              <bitWidth>2</bitWidth>
            </field>
            <field>
              <name>MONO</name>
              <bitOffset>12</bitOffset>
              <bitWidth>1</bitWidth>
            </field>
            <field>
              <name>OUTDRIV</name>
              <bitOffset>13</bitOffset>
              <bitWidth>1</bitWidth>
            </field>
            <field>
              <name>SAIEN</name>
              <bitOffset>16</bitOffset>
              <bitWidth>1</bitWidth>
            </field>
            <field>
              <name>DMAEN</name>
              <bitOffset>17</bitOffset>
              <bitWidth>1</bitWidth>
            </field>
            <field>
              <name>NODIV</name>
              <bitOffset>19</bitOffset>
              <bitWidth>1</bitWidth>
            </field>
            <field>
              <name>MCKDIV</name>
              <bitOffset>20</bitOffset>
              <bitWidth>4</bitWidth>
            </field>
          </fields>
        </register>
        <register>
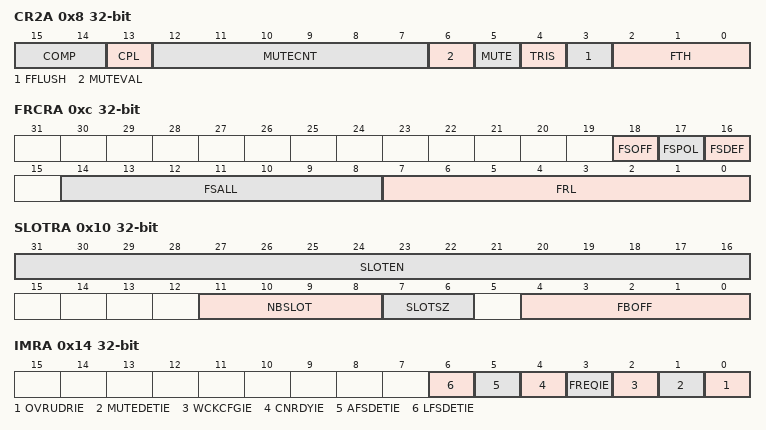
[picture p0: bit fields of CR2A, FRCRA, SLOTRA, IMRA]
          <name>CR2A</name>
          <addressOffset>0x8</addressOffset>
          <size>0x20</size>
          <fields>
            <field>
              <name>FTH</name>
              <bitOffset>0</bitOffset>
              <bitWidth>3</bitWidth>
            </field>
            <field>
              <name>FFLUSH</name>
              <bitOffset>3</bitOffset>
              <bitWidth>1</bitWidth>
            </field>
            <field>
              <name>TRIS</name>
              <bitOffset>4</bitOffset>
              <bitWidth>1</bitWidth>
            </field>
            <field>
              <name>MUTE</name>
              <bitOffset>5</bitOffset>
              <bitWidth>1</bitWidth>
            </field>
            <field>
              <name>MUTEVAL</name>
              <bitOffset>6</bitOffset>
              <bitWidth>1</bitWidth>
            </field>
            <field>
              <name>MUTECNT</name>
              <bitOffset>7</bitOffset>
              <bitWidth>6</bitWidth>
            </field>
            <field>
              <name>CPL</name>
              <bitOffset>13</bitOffset>
              <bitWidth>1</bitWidth>
            </field>
            <field>
              <name>COMP</name>
              <bitOffset>14</bitOffset>
              <bitWidth>2</bitWidth>
            </field>
          </fields>
        </register>
        <register>
          <name>FRCRA</name>
          <addressOffset>0xc</addressOffset>
          <size>0x20</size>
          <fields>
            <field>
              <name>FRL</name>
              <bitOffset>0</bitOffset>
              <bitWidth>8</bitWidth>
            </field>
            <field>
              <name>FSALL</name>
              <bitOffset>8</bitOffset>
              <bitWidth>7</bitWidth>
            </field>
            <field>
              <name>FSDEF</name>
              <bitOffset>16</bitOffset>
              <bitWidth>1</bitWidth>
            </field>
            <field>
              <name>FSPOL</name>
              <bitOffset>17</bitOffset>
              <bitWidth>1</bitWidth>
            </field>
            <field>
              <name>FSOFF</name>
              <bitOffset>18</bitOffset>
              <bitWidth>1</bitWidth>
            </field>
          </fields>
        </register>
        <register>
          <name>SLOTRA</name>
          <addressOffset>0x10</addressOffset>
          <size>0x20</size>
          <fields>
            <field>
              <name>FBOFF</name>
              <bitOffset>0</bitOffset>
              <bitWidth>5</bitWidth>
            </field>
            <field>
              <name>SLOTSZ</name>
              <bitOffset>6</bitOffset>
              <bitWidth>2</bitWidth>
            </field>
            <field>
              <name>NBSLOT</name>
              <bitOffset>8</bitOffset>
              <bitWidth>4</bitWidth>
            </field>
            <field>
              <name>SLOTEN</name>
              <bitOffset>16</bitOffset>
              <bitWidth>16</bitWidth>
            </field>
          </fields>
        </register>
        <register>
          <name>IMRA</name>
          <addressOffset>0x14</addressOffset>
          <size>0x20</size>
          <fields>
            <field>
              <name>OVRUDRIE</name>
              <bitOffset>0</bitOffset>
              <bitWidth>1</bitWidth>
            </field>
            <field>
              <name>MUTEDETIE</name>
              <bitOffset>1</bitOffset>
              <bitWidth>1</bitWidth>
            </field>
            <field>
              <name>WCKCFGIE</name>
              <bitOffset>2</bitOffset>
              <bitWidth>1</bitWidth>
            </field>
            <field>
              <name>FREQIE</name>
              <bitOffset>3</bitOffset>
              <bitWidth>1</bitWidth>
            </field>
            <field>
              <name>CNRDYIE</name>
              <bitOffset>4</bitOffset>
              <bitWidth>1</bitWidth>
            </field>
            <field>
              <name>AFSDETIE</name>
              <bitOffset>5</bitOffset>
              <bitWidth>1</bitWidth>
            </field>
            <field>
              <name>LFSDETIE</name>
              <bitOffset>6</bitOffset>
              <bitWidth>1</bitWidth>
            </field>
          </fields>
        </register>
        <register>
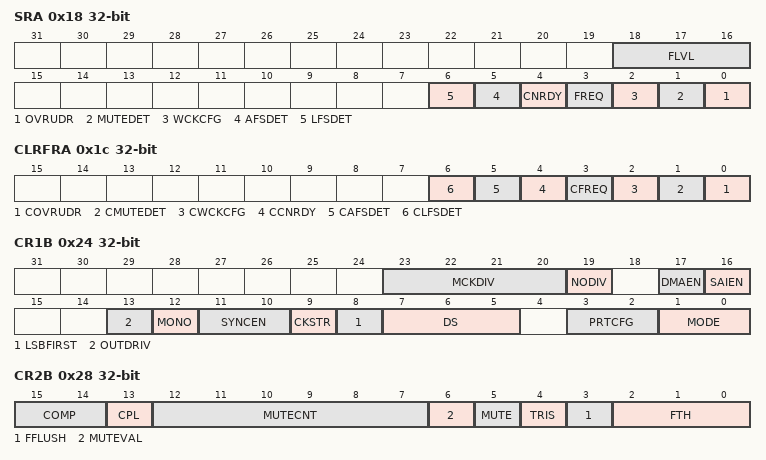
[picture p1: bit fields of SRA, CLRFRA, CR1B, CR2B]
          <name>SRA</name>
          <addressOffset>0x18</addressOffset>
          <size>0x20</size>
          <fields>
            <field>
              <name>OVRUDR</name>
              <bitOffset>0</bitOffset>
              <bitWidth>1</bitWidth>
            </field>
            <field>
              <name>MUTEDET</name>
              <bitOffset>1</bitOffset>
              <bitWidth>1</bitWidth>
            </field>
            <field>
              <name>WCKCFG</name>
              <bitOffset>2</bitOffset>
              <bitWidth>1</bitWidth>
            </field>
            <field>
              <name>FREQ</name>
              <bitOffset>3</bitOffset>
              <bitWidth>1</bitWidth>
            </field>
            <field>
              <name>CNRDY</name>
              <bitOffset>4</bitOffset>
              <bitWidth>1</bitWidth>
            </field>
            <field>
              <name>AFSDET</name>
              <bitOffset>5</bitOffset>
              <bitWidth>1</bitWidth>
            </field>
            <field>
              <name>LFSDET</name>
              <bitOffset>6</bitOffset>
              <bitWidth>1</bitWidth>
            </field>
            <field>
              <name>FLVL</name>
              <bitOffset>16</bitOffset>
              <bitWidth>3</bitWidth>
            </field>
          </fields>
        </register>
        <register>
          <name>CLRFRA</name>
          <addressOffset>0x1c</addressOffset>
          <size>0x20</size>
          <fields>
            <field>
              <name>COVRUDR</name>
              <bitOffset>0</bitOffset>
              <bitWidth>1</bitWidth>
            </field>
            <field>
              <name>CMUTEDET</name>
              <bitOffset>1</bitOffset>
              <bitWidth>1</bitWidth>
            </field>
            <field>
              <name>CWCKCFG</name>
              <bitOffset>2</bitOffset>
              <bitWidth>1</bitWidth>
            </field>
            <field>
              <name>CFREQ</name>
              <bitOffset>3</bitOffset>
              <bitWidth>1</bitWidth>
            </field>
            <field>
              <name>CCNRDY</name>
              <bitOffset>4</bitOffset>
              <bitWidth>1</bitWidth>
            </field>
            <field>
              <name>CAFSDET</name>
              <bitOffset>5</bitOffset>
              <bitWidth>1</bitWidth>
            </field>
            <field>
              <name>CLFSDET</name>
              <bitOffset>6</bitOffset>
              <bitWidth>1</bitWidth>
            </field>
          </fields>
        </register>
        <register>
          <name>DRA</name>
          <addressOffset>0x20</addressOffset>
          <size>0x20</size>
          <fields>
            <field>
              <name>DATA</name>
              <bitOffset>0</bitOffset>
              <bitWidth>32</bitWidth>
            </field>
          </fields>
        </register>
        <register>
          <name>CR1B</name>
          <addressOffset>0x24</addressOffset>
          <size>0x20</size>
          <fields>
            <field>
              <name>MODE</name>
              <bitOffset>0</bitOffset>
              <bitWidth>2</bitWidth>
            </field>
            <field>
              <name>PRTCFG</name>
              <bitOffset>2</bitOffset>
              <bitWidth>2</bitWidth>
            </field>
            <field>
              <name>DS</name>
              <bitOffset>5</bitOffset>
              <bitWidth>3</bitWidth>
            </field>
            <field>
              <name>LSBFIRST</name>
              <bitOffset>8</bitOffset>
              <bitWidth>1</bitWidth>
            </field>
            <field>
              <name>CKSTR</name>
              <bitOffset>9</bitOffset>
              <bitWidth>1</bitWidth>
            </field>
            <field>
              <name>SYNCEN</name>
              <bitOffset>10</bitOffset>
              <bitWidth>2</bitWidth>
            </field>
            <field>
              <name>MONO</name>
              <bitOffset>12</bitOffset>
              <bitWidth>1</bitWidth>
            </field>
            <field>
              <name>OUTDRIV</name>
              <bitOffset>13</bitOffset>
              <bitWidth>1</bitWidth>
            </field>
            <field>
              <name>SAIEN</name>
              <bitOffset>16</bitOffset>
              <bitWidth>1</bitWidth>
            </field>
            <field>
              <name>DMAEN</name>
              <bitOffset>17</bitOffset>
              <bitWidth>1</bitWidth>
            </field>
            <field>
              <name>NODIV</name>
              <bitOffset>19</bitOffset>
              <bitWidth>1</bitWidth>
            </field>
            <field>
              <name>MCKDIV</name>
              <bitOffset>20</bitOffset>
              <bitWidth>4</bitWidth>
            </field>
          </fields>
        </register>
        <register>
          <name>CR2B</name>
          <addressOffset>0x28</addressOffset>
          <size>0x20</size>
          <fields>
            <field>
              <name>FTH</name>
              <bitOffset>0</bitOffset>
              <bitWidth>3</bitWidth>
            </field>
            <field>
              <name>FFLUSH</name>
              <bitOffset>3</bitOffset>
              <bitWidth>1</bitWidth>
            </field>
            <field>
              <name>TRIS</name>
              <bitOffset>4</bitOffset>
              <bitWidth>1</bitWidth>
            </field>
            <field>
              <name>MUTE</name>
              <bitOffset>5</bitOffset>
              <bitWidth>1</bitWidth>
            </field>
            <field>
              <name>MUTEVAL</name>
              <bitOffset>6</bitOffset>
              <bitWidth>1</bitWidth>
            </field>
            <field>
              <name>MUTECNT</name>
              <bitOffset>7</bitOffset>
              <bitWidth>6</bitWidth>
            </field>
            <field>
              <name>CPL</name>
              <bitOffset>13</bitOffset>
              <bitWidth>1</bitWidth>
            </field>
            <field>
              <name>COMP</name>
              <bitOffset>14</bitOffset>
              <bitWidth>2</bitWidth>
            </field>
          </fields>
        </register>
        <register>
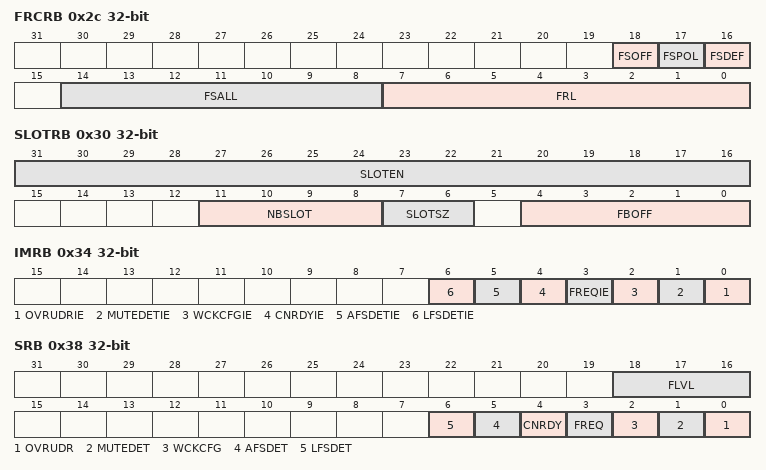
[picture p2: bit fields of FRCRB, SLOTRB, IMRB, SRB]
          <name>FRCRB</name>
          <addressOffset>0x2c</addressOffset>
          <size>0x20</size>
          <fields>
            <field>
              <name>FRL</name>
              <bitOffset>0</bitOffset>
              <bitWidth>8</bitWidth>
            </field>
            <field>
              <name>FSALL</name>
              <bitOffset>8</bitOffset>
              <bitWidth>7</bitWidth>
            </field>
            <field>
              <name>FSDEF</name>
              <bitOffset>16</bitOffset>
              <bitWidth>1</bitWidth>
            </field>
            <field>
              <name>FSPOL</name>
              <bitOffset>17</bitOffset>
              <bitWidth>1</bitWidth>
            </field>
            <field>
              <name>FSOFF</name>
              <bitOffset>18</bitOffset>
              <bitWidth>1</bitWidth>
            </field>
          </fields>
        </register>
        <register>
          <name>SLOTRB</name>
          <addressOffset>0x30</addressOffset>
          <size>0x20</size>
          <fields>
            <field>
              <name>FBOFF</name>
              <bitOffset>0</bitOffset>
              <bitWidth>5</bitWidth>
            </field>
            <field>
              <name>SLOTSZ</name>
              <bitOffset>6</bitOffset>
              <bitWidth>2</bitWidth>
            </field>
            <field>
              <name>NBSLOT</name>
              <bitOffset>8</bitOffset>
              <bitWidth>4</bitWidth>
            </field>
            <field>
              <name>SLOTEN</name>
              <bitOffset>16</bitOffset>
              <bitWidth>16</bitWidth>
            </field>
          </fields>
        </register>
        <register>
          <name>IMRB</name>
          <addressOffset>0x34</addressOffset>
          <size>0x20</size>
          <fields>
            <field>
              <name>OVRUDRIE</name>
              <bitOffset>0</bitOffset>
              <bitWidth>1</bitWidth>
            </field>
            <field>
              <name>MUTEDETIE</name>
              <bitOffset>1</bitOffset>
              <bitWidth>1</bitWidth>
            </field>
            <field>
              <name>WCKCFGIE</name>
              <bitOffset>2</bitOffset>
              <bitWidth>1</bitWidth>
            </field>
            <field>
              <name>FREQIE</name>
              <bitOffset>3</bitOffset>
              <bitWidth>1</bitWidth>
            </field>
            <field>
              <name>CNRDYIE</name>
              <bitOffset>4</bitOffset>
              <bitWidth>1</bitWidth>
            </field>
            <field>
              <name>AFSDETIE</name>
              <bitOffset>5</bitOffset>
              <bitWidth>1</bitWidth>
            </field>
            <field>
              <name>LFSDETIE</name>
              <bitOffset>6</bitOffset>
              <bitWidth>1</bitWidth>
            </field>
          </fields>
        </register>
        <register>
          <name>SRB</name>
          <addressOffset>0x38</addressOffset>
          <size>0x20</size>
          <fields>
            <field>
              <name>OVRUDR</name>
              <bitOffset>0</bitOffset>
              <bitWidth>1</bitWidth>
            </field>
            <field>
              <name>MUTEDET</name>
              <bitOffset>1</bitOffset>
              <bitWidth>1</bitWidth>
            </field>
            <field>
              <name>WCKCFG</name>
              <bitOffset>2</bitOffset>
              <bitWidth>1</bitWidth>
            </field>
            <field>
              <name>FREQ</name>
              <bitOffset>3</bitOffset>
              <bitWidth>1</bitWidth>
            </field>
            <field>
              <name>CNRDY</name>
              <bitOffset>4</bitOffset>
              <bitWidth>1</bitWidth>
            </field>
            <field>
              <name>AFSDET</name>
              <bitOffset>5</bitOffset>
              <bitWidth>1</bitWidth>
            </field>
            <field>
              <name>LFSDET</name>
              <bitOffset>6</bitOffset>
              <bitWidth>1</bitWidth>
            </field>
            <field>
              <name>FLVL</name>
              <bitOffset>16</bitOffset>
              <bitWidth>3</bitWidth>
            </field>
          </fields>
        </register>
        <register>
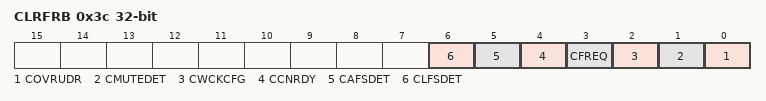
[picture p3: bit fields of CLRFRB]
          <name>CLRFRB</name>
          <addressOffset>0x3c</addressOffset>
          <size>0x20</size>
          <fields>
            <field>
              <name>COVRUDR</name>
              <bitOffset>0</bitOffset>
              <bitWidth>1</bitWidth>
            </field>
            <field>
              <name>CMUTEDET</name>
              <bitOffset>1</bitOffset>
              <bitWidth>1</bitWidth>
            </field>
            <field>
              <name>CWCKCFG</name>
              <bitOffset>2</bitOffset>
              <bitWidth>1</bitWidth>
            </field>
            <field>
              <name>CFREQ</name>
              <bitOffset>3</bitOffset>
              <bitWidth>1</bitWidth>
            </field>
            <field>
              <name>CCNRDY</name>
              <bitOffset>4</bitOffset>
              <bitWidth>1</bitWidth>
            </field>
            <field>
              <name>CAFSDET</name>
              <bitOffset>5</bitOffset>
              <bitWidth>1</bitWidth>
            </field>
            <field>
              <name>CLFSDET</name>
              <bitOffset>6</bitOffset>
              <bitWidth>1</bitWidth>
            </field>
          </fields>
        </register>
        <register>
          <name>DRB</name>
          <addressOffset>0x40</addressOffset>
          <size>0x20</size>
          <fields>
            <field>
              <name>DATA</name>
              <bitOffset>0</bitOffset>
              <bitWidth>32</bitWidth>
            </field>
          </fields>
        </register>
      </registers>
    </peripheral>
    <peripheral>
      <name>LTDC</name>
      <baseAddress>0x40016800</baseAddress>
      <registers>
        <register>
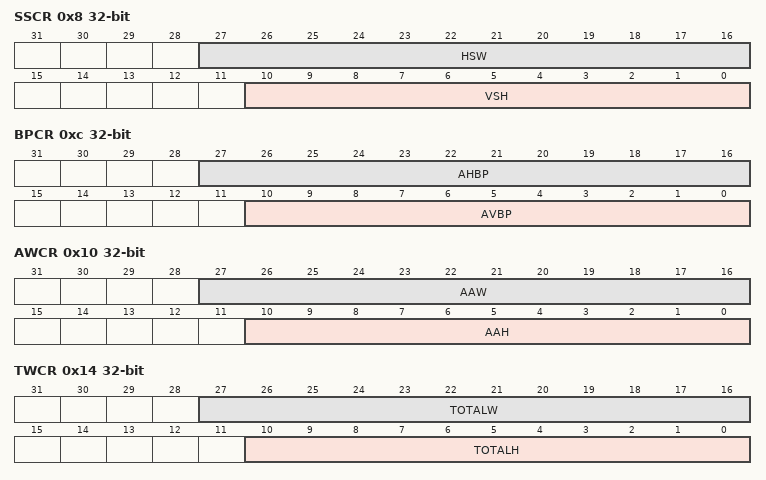
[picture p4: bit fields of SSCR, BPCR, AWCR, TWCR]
          <name>SSCR</name>
          <addressOffset>0x8</addressOffset>
          <size>0x20</size>
          <fields>
            <field>
              <name>VSH</name>
              <bitOffset>0</bitOffset>
              <bitWidth>11</bitWidth>
            </field>
            <field>
              <name>HSW</name>
              <bitOffset>16</bitOffset>
              <bitWidth>12</bitWidth>
            </field>
          </fields>
        </register>
        <register>
          <name>BPCR</name>
          <addressOffset>0xc</addressOffset>
          <size>0x20</size>
          <fields>
            <field>
              <name>AVBP</name>
              <bitOffset>0</bitOffset>
              <bitWidth>11</bitWidth>
            </field>
            <field>
              <name>AHBP</name>
              <bitOffset>16</bitOffset>
              <bitWidth>12</bitWidth>
            </field>
          </fields>
        </register>
        <register>
          <name>AWCR</name>
          <addressOffset>0x10</addressOffset>
          <size>0x20</size>
          <fields>
            <field>
              <name>AAH</name>
              <bitOffset>0</bitOffset>
              <bitWidth>11</bitWidth>
            </field>
            <field>
              <name>AAW</name>
              <bitOffset>16</bitOffset>
              <bitWidth>12</bitWidth>
            </field>
          </fields>
        </register>
        <register>
          <name>TWCR</name>
          <addressOffset>0x14</addressOffset>
          <size>0x20</size>
          <fields>
            <field>
              <name>TOTALH</name>
              <bitOffset>0</bitOffset>
              <bitWidth>11</bitWidth>
            </field>
            <field>
              <name>TOTALW</name>
              <bitOffset>16</bitOffset>
              <bitWidth>12</bitWidth>
            </field>
          </fields>
        </register>
        <register>
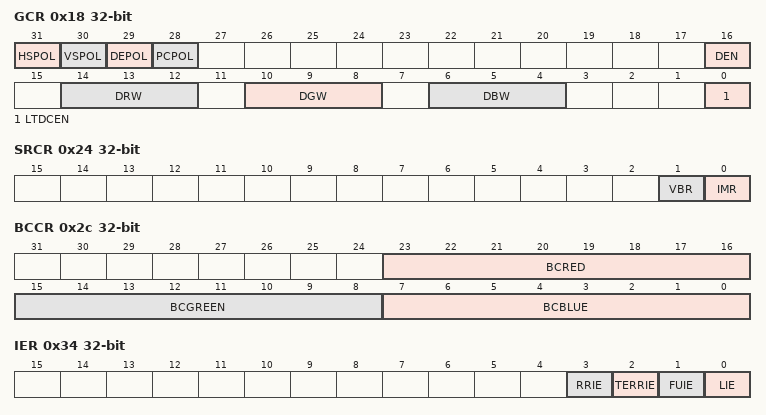
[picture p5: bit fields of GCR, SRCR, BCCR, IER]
          <name>GCR</name>
          <addressOffset>0x18</addressOffset>
          <size>0x20</size>
          <fields>
            <field>
              <name>LTDCEN</name>
              <bitOffset>0</bitOffset>
              <bitWidth>1</bitWidth>
            </field>
            <field>
              <name>DBW</name>
              <bitOffset>4</bitOffset>
              <bitWidth>3</bitWidth>
            </field>
            <field>
              <name>DGW</name>
              <bitOffset>8</bitOffset>
              <bitWidth>3</bitWidth>
            </field>
            <field>
              <name>DRW</name>
              <bitOffset>12</bitOffset>
              <bitWidth>3</bitWidth>
            </field>
            <field>
              <name>DEN</name>
              <bitOffset>16</bitOffset>
              <bitWidth>1</bitWidth>
            </field>
            <field>
              <name>PCPOL</name>
              <bitOffset>28</bitOffset>
              <bitWidth>1</bitWidth>
            </field>
            <field>
              <name>DEPOL</name>
              <bitOffset>29</bitOffset>
              <bitWidth>1</bitWidth>
            </field>
            <field>
              <name>VSPOL</name>
              <bitOffset>30</bitOffset>
              <bitWidth>1</bitWidth>
            </field>
            <field>
              <name>HSPOL</name>
              <bitOffset>31</bitOffset>
              <bitWidth>1</bitWidth>
            </field>
          </fields>
        </register>
        <register>
          <name>SRCR</name>
          <addressOffset>0x24</addressOffset>
          <size>0x20</size>
          <fields>
            <field>
              <name>IMR</name>
              <bitOffset>0</bitOffset>
              <bitWidth>1</bitWidth>
            </field>
            <field>
              <name>VBR</name>
              <bitOffset>1</bitOffset>
              <bitWidth>1</bitWidth>
            </field>
          </fields>
        </register>
        <register>
          <name>BCCR</name>
          <addressOffset>0x2c</addressOffset>
          <size>0x20</size>
          <fields>
            <field>
              <name>BCBLUE</name>
              <bitOffset>0</bitOffset>
              <bitWidth>8</bitWidth>
            </field>
            <field>
              <name>BCGREEN</name>
              <bitOffset>8</bitOffset>
              <bitWidth>8</bitWidth>
            </field>
            <field>
              <name>BCRED</name>
              <bitOffset>16</bitOffset>
              <bitWidth>8</bitWidth>
            </field>
          </fields>
        </register>
        <register>
          <name>IER</name>
          <addressOffset>0x34</addressOffset>
          <size>0x20</size>
          <fields>
            <field>
              <name>LIE</name>
              <bitOffset>0</bitOffset>
              <bitWidth>1</bitWidth>
            </field>
            <field>
              <name>FUIE</name>
              <bitOffset>1</bitOffset>
              <bitWidth>1</bitWidth>
            </field>
            <field>
              <name>TERRIE</name>
              <bitOffset>2</bitOffset>
              <bitWidth>1</bitWidth>
            </field>
            <field>
              <name>RRIE</name>
              <bitOffset>3</bitOffset>
              <bitWidth>1</bitWidth>
            </field>
          </fields>
        </register>
        <register>
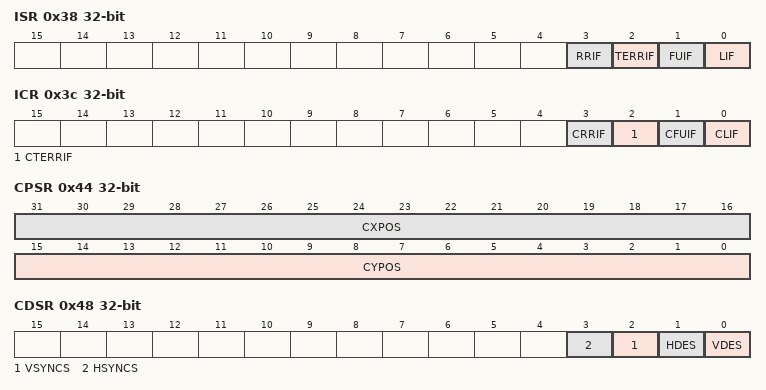
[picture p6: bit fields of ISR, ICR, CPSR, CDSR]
          <name>ISR</name>
          <addressOffset>0x38</addressOffset>
          <size>0x20</size>
          <fields>
            <field>
              <name>LIF</name>
              <bitOffset>0</bitOffset>
              <bitWidth>1</bitWidth>
            </field>
            <field>
              <name>FUIF</name>
              <bitOffset>1</bitOffset>
              <bitWidth>1</bitWidth>
            </field>
            <field>
              <name>TERRIF</name>
              <bitOffset>2</bitOffset>
              <bitWidth>1</bitWidth>
            </field>
            <field>
              <name>RRIF</name>
              <bitOffset>3</bitOffset>
              <bitWidth>1</bitWidth>
            </field>
          </fields>
        </register>
        <register>
          <name>ICR</name>
          <addressOffset>0x3c</addressOffset>
          <size>0x20</size>
          <fields>
            <field>
              <name>CLIF</name>
              <bitOffset>0</bitOffset>
              <bitWidth>1</bitWidth>
            </field>
            <field>
              <name>CFUIF</name>
              <bitOffset>1</bitOffset>
              <bitWidth>1</bitWidth>
            </field>
            <field>
              <name>CTERRIF</name>
              <bitOffset>2</bitOffset>
              <bitWidth>1</bitWidth>
            </field>
            <field>
              <name>CRRIF</name>
              <bitOffset>3</bitOffset>
              <bitWidth>1</bitWidth>
            </field>
          </fields>
        </register>
        <register>
          <name>LIPCR</name>
          <addressOffset>0x40</addressOffset>
          <size>0x20</size>
          <fields>
            <field>
              <name>LIPOS</name>
              <bitOffset>0</bitOffset>
              <bitWidth>11</bitWidth>
            </field>
          </fields>
        </register>
        <register>
          <name>CPSR</name>
          <addressOffset>0x44</addressOffset>
          <size>0x20</size>
          <fields>
            <field>
              <name>CYPOS</name>
              <bitOffset>0</bitOffset>
              <bitWidth>16</bitWidth>
            </field>
            <field>
              <name>CXPOS</name>
              <bitOffset>16</bitOffset>
              <bitWidth>16</bitWidth>
            </field>
          </fields>
        </register>
        <register>
          <name>CDSR</name>
          <addressOffset>0x48</addressOffset>
          <size>0x20</size>
          <fields>
            <field>
              <name>VDES</name>
              <bitOffset>0</bitOffset>
              <bitWidth>1</bitWidth>
            </field>
            <field>
              <name>HDES</name>
              <bitOffset>1</bitOffset>
              <bitWidth>1</bitWidth>
            </field>
            <field>
              <name>VSYNCS</name>
              <bitOffset>2</bitOffset>
              <bitWidth>1</bitWidth>
            </field>
            <field>
              <name>HSYNCS</name>
              <bitOffset>3</bitOffset>
              <bitWidth>1</bitWidth>
            </field>
          </fields>
        </register>
        <register>
          <name>CR1</name>
          <addressOffset>0x84</addressOffset>
          <size>0x20</size>
        </register>
        <register>
          <name>WHPCR1</name>
          <addressOffset>0x88</addressOffset>
          <size>0x20</size>
        </register>
        <register>
          <name>WVPCR1</name>
          <addressOffset>0x8c</addressOffset>
          <size>0x20</size>
        </register>
        <register>
          <name>CKCR1</name>
          <addressOffset>0x90</addressOffset>
          <size>0x20</size>
        </register>
        <register>
          <name>PFCR1</name>
          <addressOffset>0x94</addressOffset>
          <size>0x20</size>
        </register>
        <register>
          <name>CACR1</name>
          <addressOffset>0x98</addressOffset>
          <size>0x20</size>
        </register>
        <register>
          <name>DCCR1</name>
          <addressOffset>0x9c</addressOffset>
          <size>0x20</size>
        </register>
        <register>
          <name>BFCR1</name>
          <addressOffset>0xa0</addressOffset>
          <size>0x20</size>
        </register>
        <register>
          <name>CFBAR1</name>
          <addressOffset>0xac</addressOffset>
          <size>0x20</size>
        </register>
        <register>
          <name>CFBLR1</name>
          <addressOffset>0xb0</addressOffset>
          <size>0x20</size>
        </register>
        <register>
          <name>CFBLNR1</name>
          <addressOffset>0xb4</addressOffset>
          <size>0x20</size>
        </register>
        <register>
          <name>CLUTWR1</name>
          <addressOffset>0xc4</addressOffset>
          <size>0x20</size>
        </register>
        <register>
          <name>CR2</name>
          <addressOffset>0x104</addressOffset>
          <size>0x20</size>
        </register>
        <register>
          <name>WHPCR2</name>
          <addressOffset>0x108</addressOffset>
          <size>0x20</size>
        </register>
        <register>
          <name>WVPCR2</name>
          <addressOffset>0x10c</addressOffset>
          <size>0x20</size>
        </register>
        <register>
          <name>CKCR2</name>
          <addressOffset>0x110</addressOffset>
          <size>0x20</size>
        </register>
        <register>
          <name>PFCR2</name>
          <addressOffset>0x114</addressOffset>
          <size>0x20</size>
        </register>
        <register>
          <name>CACR2</name>
          <addressOffset>0x118</addressOffset>
          <size>0x20</size>
        </register>
        <register>
          <name>DCCR2</name>
          <addressOffset>0x11c</addressOffset>
          <size>0x20</size>
        </register>
        <register>
          <name>BFCR2</name>
          <addressOffset>0x120</addressOffset>
          <size>0x20</size>
        </register>
        <register>
          <name>CFBAR2</name>
          <addressOffset>0x12c</addressOffset>
          <size>0x20</size>
        </register>
        <register>
          <name>CFBLR2</name>
          <addressOffset>0x130</addressOffset>
          <size>0x20</size>
        </register>
        <register>
          <name>CFBLNR2</name>
          <addressOffset>0x134</addressOffset>
          <size>0x20</size>
        </register>
        <register>
          <name>CLUTWR2</name>
          <addressOffset>0x144</addressOffset>
          <size>0x20</size>
        </register>
      </registers>
    </peripheral>
    <peripheral>
      <name>GPIOA</name>
      <baseAddress>0x40020000</baseAddress>
      <registers>
        <register>
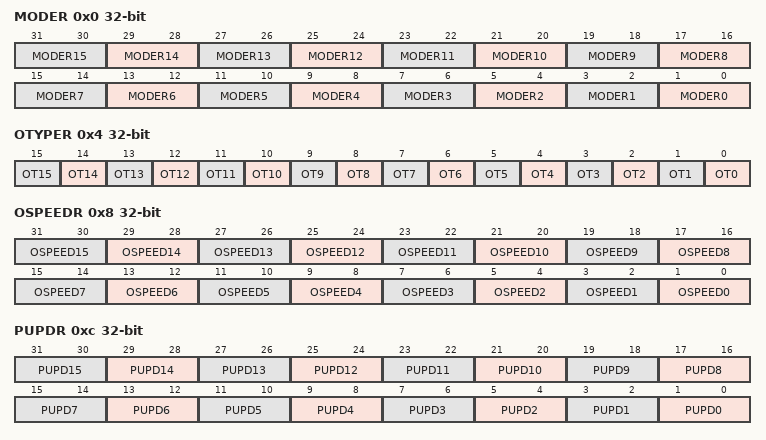
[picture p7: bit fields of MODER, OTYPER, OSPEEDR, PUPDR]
          <name>MODER</name>
          <addressOffset>0x0</addressOffset>
          <size>0x20</size>
          <fields>
            <field>
              <name>MODER0</name>
              <bitOffset>0</bitOffset>
              <bitWidth>2</bitWidth>
            </field>
            <field>
              <name>MODER1</name>
              <bitOffset>2</bitOffset>
              <bitWidth>2</bitWidth>
            </field>
            <field>
              <name>MODER2</name>
              <bitOffset>4</bitOffset>
              <bitWidth>2</bitWidth>
            </field>
            <field>
              <name>MODER3</name>
              <bitOffset>6</bitOffset>
              <bitWidth>2</bitWidth>
            </field>
            <field>
              <name>MODER4</name>
              <bitOffset>8</bitOffset>
              <bitWidth>2</bitWidth>
            </field>
            <field>
              <name>MODER5</name>
              <bitOffset>10</bitOffset>
              <bitWidth>2</bitWidth>
            </field>
            <field>
              <name>MODER6</name>
              <bitOffset>12</bitOffset>
              <bitWidth>2</bitWidth>
            </field>
            <field>
              <name>MODER7</name>
              <bitOffset>14</bitOffset>
              <bitWidth>2</bitWidth>
            </field>
            <field>
              <name>MODER8</name>
              <bitOffset>16</bitOffset>
              <bitWidth>2</bitWidth>
            </field>
            <field>
              <name>MODER9</name>
              <bitOffset>18</bitOffset>
              <bitWidth>2</bitWidth>
            </field>
            <field>
              <name>MODER10</name>
              <bitOffset>20</bitOffset>
              <bitWidth>2</bitWidth>
            </field>
            <field>
              <name>MODER11</name>
              <bitOffset>22</bitOffset>
              <bitWidth>2</bitWidth>
            </field>
            <field>
              <name>MODER12</name>
              <bitOffset>24</bitOffset>
              <bitWidth>2</bitWidth>
            </field>
            <field>
              <name>MODER13</name>
              <bitOffset>26</bitOffset>
              <bitWidth>2</bitWidth>
            </field>
            <field>
              <name>MODER14</name>
              <bitOffset>28</bitOffset>
              <bitWidth>2</bitWidth>
            </field>
            <field>
              <name>MODER15</name>
              <bitOffset>30</bitOffset>
              <bitWidth>2</bitWidth>
            </field>
          </fields>
        </register>
        <register>
          <name>OTYPER</name>
          <addressOffset>0x4</addressOffset>
          <size>0x20</size>
          <fields>
            <field>
              <name>OT0</name>
              <bitOffset>0</bitOffset>
              <bitWidth>1</bitWidth>
            </field>
            <field>
              <name>OT1</name>
              <bitOffset>1</bitOffset>
              <bitWidth>1</bitWidth>
            </field>
            <field>
              <name>OT2</name>
              <bitOffset>2</bitOffset>
              <bitWidth>1</bitWidth>
            </field>
            <field>
              <name>OT3</name>
              <bitOffset>3</bitOffset>
              <bitWidth>1</bitWidth>
            </field>
            <field>
              <name>OT4</name>
              <bitOffset>4</bitOffset>
              <bitWidth>1</bitWidth>
            </field>
            <field>
              <name>OT5</name>
              <bitOffset>5</bitOffset>
              <bitWidth>1</bitWidth>
            </field>
            <field>
              <name>OT6</name>
              <bitOffset>6</bitOffset>
              <bitWidth>1</bitWidth>
            </field>
            <field>
              <name>OT7</name>
              <bitOffset>7</bitOffset>
              <bitWidth>1</bitWidth>
            </field>
            <field>
              <name>OT8</name>
              <bitOffset>8</bitOffset>
              <bitWidth>1</bitWidth>
            </field>
            <field>
              <name>OT9</name>
              <bitOffset>9</bitOffset>
              <bitWidth>1</bitWidth>
            </field>
            <field>
              <name>OT10</name>
              <bitOffset>10</bitOffset>
              <bitWidth>1</bitWidth>
            </field>
            <field>
              <name>OT11</name>
              <bitOffset>11</bitOffset>
              <bitWidth>1</bitWidth>
            </field>
            <field>
              <name>OT12</name>
              <bitOffset>12</bitOffset>
              <bitWidth>1</bitWidth>
            </field>
            <field>
              <name>OT13</name>
              <bitOffset>13</bitOffset>
              <bitWidth>1</bitWidth>
            </field>
            <field>
              <name>OT14</name>
              <bitOffset>14</bitOffset>
              <bitWidth>1</bitWidth>
            </field>
            <field>
              <name>OT15</name>
              <bitOffset>15</bitOffset>
              <bitWidth>1</bitWidth>
            </field>
          </fields>
        </register>
        <register>
          <name>OSPEEDR</name>
          <addressOffset>0x8</addressOffset>
          <size>0x20</size>
          <fields>
            <field>
              <name>OSPEED0</name>
              <bitOffset>0</bitOffset>
              <bitWidth>2</bitWidth>
            </field>
            <field>
              <name>OSPEED1</name>
              <bitOffset>2</bitOffset>
              <bitWidth>2</bitWidth>
            </field>
            <field>
              <name>OSPEED2</name>
              <bitOffset>4</bitOffset>
              <bitWidth>2</bitWidth>
            </field>
            <field>
              <name>OSPEED3</name>
              <bitOffset>6</bitOffset>
              <bitWidth>2</bitWidth>
            </field>
            <field>
              <name>OSPEED4</name>
              <bitOffset>8</bitOffset>
              <bitWidth>2</bitWidth>
            </field>
            <field>
              <name>OSPEED5</name>
              <bitOffset>10</bitOffset>
              <bitWidth>2</bitWidth>
            </field>
            <field>
              <name>OSPEED6</name>
              <bitOffset>12</bitOffset>
              <bitWidth>2</bitWidth>
            </field>
            <field>
              <name>OSPEED7</name>
              <bitOffset>14</bitOffset>
              <bitWidth>2</bitWidth>
            </field>
            <field>
              <name>OSPEED8</name>
              <bitOffset>16</bitOffset>
              <bitWidth>2</bitWidth>
            </field>
            <field>
              <name>OSPEED9</name>
              <bitOffset>18</bitOffset>
              <bitWidth>2</bitWidth>
            </field>
            <field>
              <name>OSPEED10</name>
              <bitOffset>20</bitOffset>
              <bitWidth>2</bitWidth>
            </field>
            <field>
              <name>OSPEED11</name>
              <bitOffset>22</bitOffset>
              <bitWidth>2</bitWidth>
            </field>
            <field>
              <name>OSPEED12</name>
              <bitOffset>24</bitOffset>
              <bitWidth>2</bitWidth>
            </field>
            <field>
              <name>OSPEED13</name>
              <bitOffset>26</bitOffset>
              <bitWidth>2</bitWidth>
            </field>
            <field>
              <name>OSPEED14</name>
              <bitOffset>28</bitOffset>
              <bitWidth>2</bitWidth>
            </field>
            <field>
              <name>OSPEED15</name>
              <bitOffset>30</bitOffset>
              <bitWidth>2</bitWidth>
            </field>
          </fields>
        </register>
        <register>
          <name>PUPDR</name>
          <addressOffset>0xc</addressOffset>
          <size>0x20</size>
          <fields>
            <field>
              <name>PUPD0</name>
              <bitOffset>0</bitOffset>
              <bitWidth>2</bitWidth>
            </field>
            <field>
              <name>PUPD1</name>
              <bitOffset>2</bitOffset>
              <bitWidth>2</bitWidth>
            </field>
            <field>
              <name>PUPD2</name>
              <bitOffset>4</bitOffset>
              <bitWidth>2</bitWidth>
            </field>
            <field>
              <name>PUPD3</name>
              <bitOffset>6</bitOffset>
              <bitWidth>2</bitWidth>
            </field>
            <field>
              <name>PUPD4</name>
              <bitOffset>8</bitOffset>
              <bitWidth>2</bitWidth>
            </field>
            <field>
              <name>PUPD5</name>
              <bitOffset>10</bitOffset>
              <bitWidth>2</bitWidth>
            </field>
            <field>
              <name>PUPD6</name>
              <bitOffset>12</bitOffset>
              <bitWidth>2</bitWidth>
            </field>
            <field>
              <name>PUPD7</name>
              <bitOffset>14</bitOffset>
              <bitWidth>2</bitWidth>
            </field>
            <field>
              <name>PUPD8</name>
              <bitOffset>16</bitOffset>
              <bitWidth>2</bitWidth>
            </field>
            <field>
              <name>PUPD9</name>
              <bitOffset>18</bitOffset>
              <bitWidth>2</bitWidth>
            </field>
            <field>
              <name>PUPD10</name>
              <bitOffset>20</bitOffset>
              <bitWidth>2</bitWidth>
            </field>
            <field>
              <name>PUPD11</name>
              <bitOffset>22</bitOffset>
              <bitWidth>2</bitWidth>
            </field>
            <field>
              <name>PUPD12</name>
              <bitOffset>24</bitOffset>
              <bitWidth>2</bitWidth>
            </field>
            <field>
              <name>PUPD13</name>
              <bitOffset>26</bitOffset>
              <bitWidth>2</bitWidth>
            </field>
            <field>
              <name>PUPD14</name>
              <bitOffset>28</bitOffset>
              <bitWidth>2</bitWidth>
            </field>
            <field>
              <name>PUPD15</name>
              <bitOffset>30</bitOffset>
              <bitWidth>2</bitWidth>
            </field>
          </fields>
        </register>
        <register>
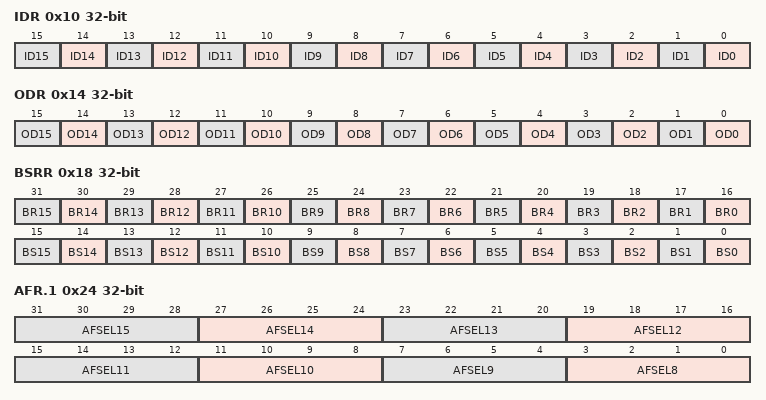
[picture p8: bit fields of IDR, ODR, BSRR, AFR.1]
          <name>IDR</name>
          <addressOffset>0x10</addressOffset>
          <size>0x20</size>
          <fields>
            <field>
              <name>ID0</name>
              <bitOffset>0</bitOffset>
              <bitWidth>1</bitWidth>
            </field>
            <field>
              <name>ID1</name>
              <bitOffset>1</bitOffset>
              <bitWidth>1</bitWidth>
            </field>
            <field>
              <name>ID2</name>
              <bitOffset>2</bitOffset>
              <bitWidth>1</bitWidth>
            </field>
            <field>
              <name>ID3</name>
              <bitOffset>3</bitOffset>
              <bitWidth>1</bitWidth>
            </field>
            <field>
              <name>ID4</name>
              <bitOffset>4</bitOffset>
              <bitWidth>1</bitWidth>
            </field>
            <field>
              <name>ID5</name>
              <bitOffset>5</bitOffset>
              <bitWidth>1</bitWidth>
            </field>
            <field>
              <name>ID6</name>
              <bitOffset>6</bitOffset>
              <bitWidth>1</bitWidth>
            </field>
            <field>
              <name>ID7</name>
              <bitOffset>7</bitOffset>
              <bitWidth>1</bitWidth>
            </field>
            <field>
              <name>ID8</name>
              <bitOffset>8</bitOffset>
              <bitWidth>1</bitWidth>
            </field>
            <field>
              <name>ID9</name>
              <bitOffset>9</bitOffset>
              <bitWidth>1</bitWidth>
            </field>
            <field>
              <name>ID10</name>
              <bitOffset>10</bitOffset>
              <bitWidth>1</bitWidth>
            </field>
            <field>
              <name>ID11</name>
              <bitOffset>11</bitOffset>
              <bitWidth>1</bitWidth>
            </field>
            <field>
              <name>ID12</name>
              <bitOffset>12</bitOffset>
              <bitWidth>1</bitWidth>
            </field>
            <field>
              <name>ID13</name>
              <bitOffset>13</bitOffset>
              <bitWidth>1</bitWidth>
            </field>
            <field>
              <name>ID14</name>
              <bitOffset>14</bitOffset>
              <bitWidth>1</bitWidth>
            </field>
            <field>
              <name>ID15</name>
              <bitOffset>15</bitOffset>
              <bitWidth>1</bitWidth>
            </field>
          </fields>
        </register>
        <register>
          <name>ODR</name>
          <addressOffset>0x14</addressOffset>
          <size>0x20</size>
          <fields>
            <field>
              <name>OD0</name>
              <bitOffset>0</bitOffset>
              <bitWidth>1</bitWidth>
            </field>
            <field>
              <name>OD1</name>
              <bitOffset>1</bitOffset>
              <bitWidth>1</bitWidth>
            </field>
            <field>
              <name>OD2</name>
              <bitOffset>2</bitOffset>
              <bitWidth>1</bitWidth>
            </field>
            <field>
              <name>OD3</name>
              <bitOffset>3</bitOffset>
              <bitWidth>1</bitWidth>
            </field>
            <field>
              <name>OD4</name>
              <bitOffset>4</bitOffset>
              <bitWidth>1</bitWidth>
            </field>
            <field>
              <name>OD5</name>
              <bitOffset>5</bitOffset>
              <bitWidth>1</bitWidth>
            </field>
            <field>
              <name>OD6</name>
              <bitOffset>6</bitOffset>
              <bitWidth>1</bitWidth>
            </field>
            <field>
              <name>OD7</name>
              <bitOffset>7</bitOffset>
              <bitWidth>1</bitWidth>
            </field>
            <field>
              <name>OD8</name>
              <bitOffset>8</bitOffset>
              <bitWidth>1</bitWidth>
            </field>
            <field>
              <name>OD9</name>
              <bitOffset>9</bitOffset>
              <bitWidth>1</bitWidth>
            </field>
            <field>
              <name>OD10</name>
              <bitOffset>10</bitOffset>
              <bitWidth>1</bitWidth>
            </field>
            <field>
              <name>OD11</name>
              <bitOffset>11</bitOffset>
              <bitWidth>1</bitWidth>
            </field>
            <field>
              <name>OD12</name>
              <bitOffset>12</bitOffset>
              <bitWidth>1</bitWidth>
            </field>
            <field>
              <name>OD13</name>
              <bitOffset>13</bitOffset>
              <bitWidth>1</bitWidth>
            </field>
            <field>
              <name>OD14</name>
              <bitOffset>14</bitOffset>
              <bitWidth>1</bitWidth>
            </field>
            <field>
              <name>OD15</name>
              <bitOffset>15</bitOffset>
              <bitWidth>1</bitWidth>
            </field>
          </fields>
        </register>
        <register>
          <name>BSRR</name>
          <addressOffset>0x18</addressOffset>
          <size>0x20</size>
          <fields>
            <field>
              <name>BS0</name>
              <bitOffset>0</bitOffset>
              <bitWidth>1</bitWidth>
            </field>
            <field>
              <name>BS1</name>
              <bitOffset>1</bitOffset>
              <bitWidth>1</bitWidth>
            </field>
            <field>
              <name>BS2</name>
              <bitOffset>2</bitOffset>
              <bitWidth>1</bitWidth>
            </field>
            <field>
              <name>BS3</name>
              <bitOffset>3</bitOffset>
              <bitWidth>1</bitWidth>
            </field>
            <field>
              <name>BS4</name>
              <bitOffset>4</bitOffset>
              <bitWidth>1</bitWidth>
            </field>
            <field>
              <name>BS5</name>
              <bitOffset>5</bitOffset>
              <bitWidth>1</bitWidth>
            </field>
            <field>
              <name>BS6</name>
              <bitOffset>6</bitOffset>
              <bitWidth>1</bitWidth>
            </field>
            <field>
              <name>BS7</name>
              <bitOffset>7</bitOffset>
              <bitWidth>1</bitWidth>
            </field>
            <field>
              <name>BS8</name>
              <bitOffset>8</bitOffset>
              <bitWidth>1</bitWidth>
            </field>
            <field>
              <name>BS9</name>
              <bitOffset>9</bitOffset>
              <bitWidth>1</bitWidth>
            </field>
            <field>
              <name>BS10</name>
              <bitOffset>10</bitOffset>
              <bitWidth>1</bitWidth>
            </field>
            <field>
              <name>BS11</name>
              <bitOffset>11</bitOffset>
              <bitWidth>1</bitWidth>
            </field>
            <field>
              <name>BS12</name>
              <bitOffset>12</bitOffset>
              <bitWidth>1</bitWidth>
            </field>
            <field>
              <name>BS13</name>
              <bitOffset>13</bitOffset>
              <bitWidth>1</bitWidth>
            </field>
            <field>
              <name>BS14</name>
              <bitOffset>14</bitOffset>
              <bitWidth>1</bitWidth>
            </field>
            <field>
              <name>BS15</name>
              <bitOffset>15</bitOffset>
              <bitWidth>1</bitWidth>
            </field>
            <field>
              <name>BR0</name>
              <bitOffset>16</bitOffset>
              <bitWidth>1</bitWidth>
            </field>
            <field>
              <name>BR1</name>
              <bitOffset>17</bitOffset>
              <bitWidth>1</bitWidth>
            </field>
            <field>
              <name>BR2</name>
              <bitOffset>18</bitOffset>
              <bitWidth>1</bitWidth>
            </field>
            <field>
              <name>BR3</name>
              <bitOffset>19</bitOffset>
              <bitWidth>1</bitWidth>
            </field>
            <field>
              <name>BR4</name>
              <bitOffset>20</bitOffset>
              <bitWidth>1</bitWidth>
            </field>
            <field>
              <name>BR5</name>
              <bitOffset>21</bitOffset>
              <bitWidth>1</bitWidth>
            </field>
            <field>
              <name>BR6</name>
              <bitOffset>22</bitOffset>
              <bitWidth>1</bitWidth>
            </field>
            <field>
              <name>BR7</name>
              <bitOffset>23</bitOffset>
              <bitWidth>1</bitWidth>
            </field>
            <field>
              <name>BR8</name>
              <bitOffset>24</bitOffset>
              <bitWidth>1</bitWidth>
            </field>
            <field>
              <name>BR9</name>
              <bitOffset>25</bitOffset>
              <bitWidth>1</bitWidth>
            </field>
            <field>
              <name>BR10</name>
              <bitOffset>26</bitOffset>
              <bitWidth>1</bitWidth>
            </field>
            <field>
              <name>BR11</name>
              <bitOffset>27</bitOffset>
              <bitWidth>1</bitWidth>
            </field>
            <field>
              <name>BR12</name>
              <bitOffset>28</bitOffset>
              <bitWidth>1</bitWidth>
            </field>
            <field>
              <name>BR13</name>
              <bitOffset>29</bitOffset>
              <bitWidth>1</bitWidth>
            </field>
            <field>
              <name>BR14</name>
              <bitOffset>30</bitOffset>
              <bitWidth>1</bitWidth>
            </field>
            <field>
              <name>BR15</name>
              <bitOffset>31</bitOffset>
              <bitWidth>1</bitWidth>
            </field>
          </fields>
        </register>
        <register>
          <name>LCKR</name>
          <addressOffset>0x1c</addressOffset>
          <size>0x20</size>
        </register>
        <register>
          <name>AFR.0</name>
          <addressOffset>0x20</addressOffset>
          <size>0x20</size>
        </register>
        <register>
          <name>AFR.1</name>
          <addressOffset>0x24</addressOffset>
          <size>0x20</size>
          <fields>
            <field>
              <name>AFSEL8</name>
              <bitOffset>0</bitOffset>
              <bitWidth>4</bitWidth>
            </field>
            <field>
              <name>AFSEL9</name>
              <bitOffset>4</bitOffset>
              <bitWidth>4</bitWidth>
            </field>
            <field>
              <name>AFSEL10</name>
              <bitOffset>8</bitOffset>
              <bitWidth>4</bitWidth>
            </field>
            <field>
              <name>AFSEL11</name>
              <bitOffset>12</bitOffset>
              <bitWidth>4</bitWidth>
            </field>
            <field>
              <name>AFSEL12</name>
              <bitOffset>16</bitOffset>
              <bitWidth>4</bitWidth>
            </field>
            <field>
              <name>AFSEL13</name>
              <bitOffset>20</bitOffset>
              <bitWidth>4</bitWidth>
            </field>
            <field>
              <name>AFSEL14</name>
              <bitOffset>24</bitOffset>
              <bitWidth>4</bitWidth>
            </field>
            <field>
              <name>AFSEL15</name>
              <bitOffset>28</bitOffset>
              <bitWidth>4</bitWidth>
            </field>
          </fields>
        </register>
      </registers>
    </peripheral>
    <peripheral>
      <name>GPIOB</name>
      <baseAddress>0x40020400</baseAddress>
      <registers>
        <register>
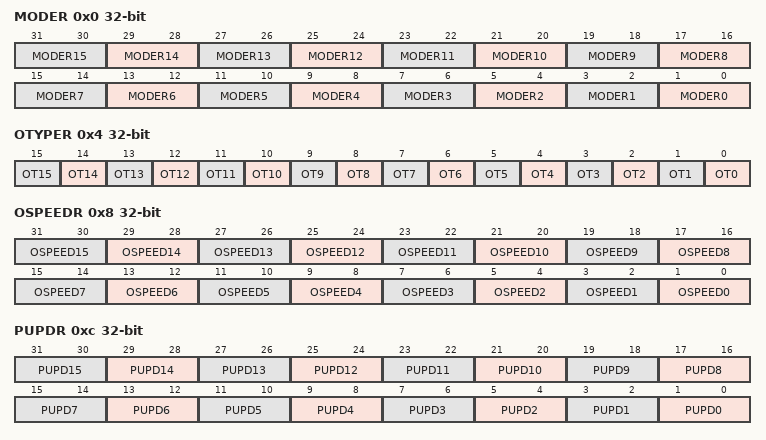
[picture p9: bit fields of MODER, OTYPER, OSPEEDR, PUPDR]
          <name>MODER</name>
          <addressOffset>0x0</addressOffset>
          <size>0x20</size>
          <fields>
            <field>
              <name>MODER0</name>
              <bitOffset>0</bitOffset>
              <bitWidth>2</bitWidth>
            </field>
            <field>
              <name>MODER1</name>
              <bitOffset>2</bitOffset>
              <bitWidth>2</bitWidth>
            </field>
            <field>
              <name>MODER2</name>
              <bitOffset>4</bitOffset>
              <bitWidth>2</bitWidth>
            </field>
            <field>
              <name>MODER3</name>
              <bitOffset>6</bitOffset>
              <bitWidth>2</bitWidth>
            </field>
            <field>
              <name>MODER4</name>
              <bitOffset>8</bitOffset>
              <bitWidth>2</bitWidth>
            </field>
            <field>
              <name>MODER5</name>
              <bitOffset>10</bitOffset>
              <bitWidth>2</bitWidth>
            </field>
            <field>
              <name>MODER6</name>
              <bitOffset>12</bitOffset>
              <bitWidth>2</bitWidth>
            </field>
            <field>
              <name>MODER7</name>
              <bitOffset>14</bitOffset>
              <bitWidth>2</bitWidth>
            </field>
            <field>
              <name>MODER8</name>
              <bitOffset>16</bitOffset>
              <bitWidth>2</bitWidth>
            </field>
            <field>
              <name>MODER9</name>
              <bitOffset>18</bitOffset>
              <bitWidth>2</bitWidth>
            </field>
            <field>
              <name>MODER10</name>
              <bitOffset>20</bitOffset>
              <bitWidth>2</bitWidth>
            </field>
            <field>
              <name>MODER11</name>
              <bitOffset>22</bitOffset>
              <bitWidth>2</bitWidth>
            </field>
            <field>
              <name>MODER12</name>
              <bitOffset>24</bitOffset>
              <bitWidth>2</bitWidth>
            </field>
            <field>
              <name>MODER13</name>
              <bitOffset>26</bitOffset>
              <bitWidth>2</bitWidth>
            </field>
            <field>
              <name>MODER14</name>
              <bitOffset>28</bitOffset>
              <bitWidth>2</bitWidth>
            </field>
            <field>
              <name>MODER15</name>
              <bitOffset>30</bitOffset>
              <bitWidth>2</bitWidth>
            </field>
          </fields>
        </register>
        <register>
          <name>OTYPER</name>
          <addressOffset>0x4</addressOffset>
          <size>0x20</size>
          <fields>
            <field>
              <name>OT0</name>
              <bitOffset>0</bitOffset>
              <bitWidth>1</bitWidth>
            </field>
            <field>
              <name>OT1</name>
              <bitOffset>1</bitOffset>
              <bitWidth>1</bitWidth>
            </field>
            <field>
              <name>OT2</name>
              <bitOffset>2</bitOffset>
              <bitWidth>1</bitWidth>
            </field>
            <field>
              <name>OT3</name>
              <bitOffset>3</bitOffset>
              <bitWidth>1</bitWidth>
            </field>
            <field>
              <name>OT4</name>
              <bitOffset>4</bitOffset>
              <bitWidth>1</bitWidth>
            </field>
            <field>
              <name>OT5</name>
              <bitOffset>5</bitOffset>
              <bitWidth>1</bitWidth>
            </field>
            <field>
              <name>OT6</name>
              <bitOffset>6</bitOffset>
              <bitWidth>1</bitWidth>
            </field>
            <field>
              <name>OT7</name>
              <bitOffset>7</bitOffset>
              <bitWidth>1</bitWidth>
            </field>
            <field>
              <name>OT8</name>
              <bitOffset>8</bitOffset>
              <bitWidth>1</bitWidth>
            </field>
            <field>
              <name>OT9</name>
              <bitOffset>9</bitOffset>
              <bitWidth>1</bitWidth>
            </field>
            <field>
              <name>OT10</name>
              <bitOffset>10</bitOffset>
              <bitWidth>1</bitWidth>
            </field>
            <field>
              <name>OT11</name>
              <bitOffset>11</bitOffset>
              <bitWidth>1</bitWidth>
            </field>
            <field>
              <name>OT12</name>
              <bitOffset>12</bitOffset>
              <bitWidth>1</bitWidth>
            </field>
            <field>
              <name>OT13</name>
              <bitOffset>13</bitOffset>
              <bitWidth>1</bitWidth>
            </field>
            <field>
              <name>OT14</name>
              <bitOffset>14</bitOffset>
              <bitWidth>1</bitWidth>
            </field>
            <field>
              <name>OT15</name>
              <bitOffset>15</bitOffset>
              <bitWidth>1</bitWidth>
            </field>
          </fields>
        </register>
        <register>
          <name>OSPEEDR</name>
          <addressOffset>0x8</addressOffset>
          <size>0x20</size>
          <fields>
            <field>
              <name>OSPEED0</name>
              <bitOffset>0</bitOffset>
              <bitWidth>2</bitWidth>
            </field>
            <field>
              <name>OSPEED1</name>
              <bitOffset>2</bitOffset>
              <bitWidth>2</bitWidth>
            </field>
            <field>
              <name>OSPEED2</name>
              <bitOffset>4</bitOffset>
              <bitWidth>2</bitWidth>
            </field>
            <field>
              <name>OSPEED3</name>
              <bitOffset>6</bitOffset>
              <bitWidth>2</bitWidth>
            </field>
            <field>
              <name>OSPEED4</name>
              <bitOffset>8</bitOffset>
              <bitWidth>2</bitWidth>
            </field>
            <field>
              <name>OSPEED5</name>
              <bitOffset>10</bitOffset>
              <bitWidth>2</bitWidth>
            </field>
            <field>
              <name>OSPEED6</name>
              <bitOffset>12</bitOffset>
              <bitWidth>2</bitWidth>
            </field>
            <field>
              <name>OSPEED7</name>
              <bitOffset>14</bitOffset>
              <bitWidth>2</bitWidth>
            </field>
            <field>
              <name>OSPEED8</name>
              <bitOffset>16</bitOffset>
              <bitWidth>2</bitWidth>
            </field>
            <field>
              <name>OSPEED9</name>
              <bitOffset>18</bitOffset>
              <bitWidth>2</bitWidth>
            </field>
            <field>
              <name>OSPEED10</name>
              <bitOffset>20</bitOffset>
              <bitWidth>2</bitWidth>
            </field>
            <field>
              <name>OSPEED11</name>
              <bitOffset>22</bitOffset>
              <bitWidth>2</bitWidth>
            </field>
            <field>
              <name>OSPEED12</name>
              <bitOffset>24</bitOffset>
              <bitWidth>2</bitWidth>
            </field>
            <field>
              <name>OSPEED13</name>
              <bitOffset>26</bitOffset>
              <bitWidth>2</bitWidth>
            </field>
            <field>
              <name>OSPEED14</name>
              <bitOffset>28</bitOffset>
              <bitWidth>2</bitWidth>
            </field>
            <field>
              <name>OSPEED15</name>
              <bitOffset>30</bitOffset>
              <bitWidth>2</bitWidth>
            </field>
          </fields>
        </register>
        <register>
          <name>PUPDR</name>
          <addressOffset>0xc</addressOffset>
          <size>0x20</size>
          <fields>
            <field>
              <name>PUPD0</name>
              <bitOffset>0</bitOffset>
              <bitWidth>2</bitWidth>
            </field>
            <field>
              <name>PUPD1</name>
              <bitOffset>2</bitOffset>
              <bitWidth>2</bitWidth>
            </field>
            <field>
              <name>PUPD2</name>
              <bitOffset>4</bitOffset>
              <bitWidth>2</bitWidth>
            </field>
            <field>
              <name>PUPD3</name>
              <bitOffset>6</bitOffset>
              <bitWidth>2</bitWidth>
            </field>
            <field>
              <name>PUPD4</name>
              <bitOffset>8</bitOffset>
              <bitWidth>2</bitWidth>
            </field>
            <field>
              <name>PUPD5</name>
              <bitOffset>10</bitOffset>
              <bitWidth>2</bitWidth>
            </field>
            <field>
              <name>PUPD6</name>
              <bitOffset>12</bitOffset>
              <bitWidth>2</bitWidth>
            </field>
            <field>
              <name>PUPD7</name>
              <bitOffset>14</bitOffset>
              <bitWidth>2</bitWidth>
            </field>
            <field>
              <name>PUPD8</name>
              <bitOffset>16</bitOffset>
              <bitWidth>2</bitWidth>
            </field>
            <field>
              <name>PUPD9</name>
              <bitOffset>18</bitOffset>
              <bitWidth>2</bitWidth>
            </field>
            <field>
              <name>PUPD10</name>
              <bitOffset>20</bitOffset>
              <bitWidth>2</bitWidth>
            </field>
            <field>
              <name>PUPD11</name>
              <bitOffset>22</bitOffset>
              <bitWidth>2</bitWidth>
            </field>
            <field>
              <name>PUPD12</name>
              <bitOffset>24</bitOffset>
              <bitWidth>2</bitWidth>
            </field>
            <field>
              <name>PUPD13</name>
              <bitOffset>26</bitOffset>
              <bitWidth>2</bitWidth>
            </field>
            <field>
              <name>PUPD14</name>
              <bitOffset>28</bitOffset>
              <bitWidth>2</bitWidth>
            </field>
            <field>
              <name>PUPD15</name>
              <bitOffset>30</bitOffset>
              <bitWidth>2</bitWidth>
            </field>
          </fields>
        </register>
        <register>
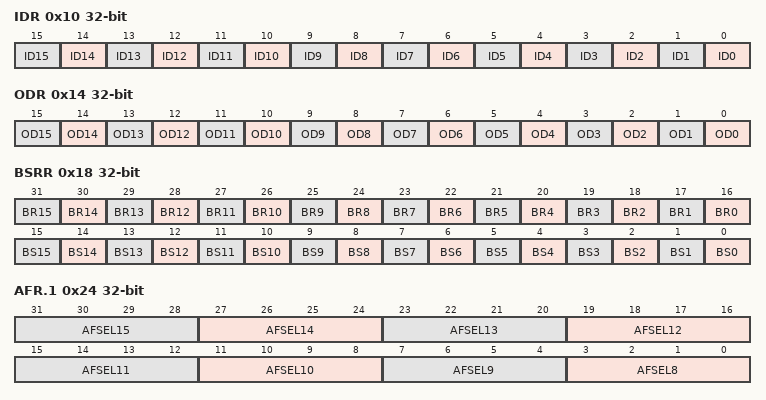
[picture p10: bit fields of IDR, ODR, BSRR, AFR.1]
          <name>IDR</name>
          <addressOffset>0x10</addressOffset>
          <size>0x20</size>
          <fields>
            <field>
              <name>ID0</name>
              <bitOffset>0</bitOffset>
              <bitWidth>1</bitWidth>
            </field>
            <field>
              <name>ID1</name>
              <bitOffset>1</bitOffset>
              <bitWidth>1</bitWidth>
            </field>
            <field>
              <name>ID2</name>
              <bitOffset>2</bitOffset>
              <bitWidth>1</bitWidth>
            </field>
            <field>
              <name>ID3</name>
              <bitOffset>3</bitOffset>
              <bitWidth>1</bitWidth>
            </field>
            <field>
              <name>ID4</name>
              <bitOffset>4</bitOffset>
              <bitWidth>1</bitWidth>
            </field>
            <field>
              <name>ID5</name>
              <bitOffset>5</bitOffset>
              <bitWidth>1</bitWidth>
            </field>
            <field>
              <name>ID6</name>
              <bitOffset>6</bitOffset>
              <bitWidth>1</bitWidth>
            </field>
            <field>
              <name>ID7</name>
              <bitOffset>7</bitOffset>
              <bitWidth>1</bitWidth>
            </field>
            <field>
              <name>ID8</name>
              <bitOffset>8</bitOffset>
              <bitWidth>1</bitWidth>
            </field>
            <field>
              <name>ID9</name>
              <bitOffset>9</bitOffset>
              <bitWidth>1</bitWidth>
            </field>
            <field>
              <name>ID10</name>
              <bitOffset>10</bitOffset>
              <bitWidth>1</bitWidth>
            </field>
            <field>
              <name>ID11</name>
              <bitOffset>11</bitOffset>
              <bitWidth>1</bitWidth>
            </field>
            <field>
              <name>ID12</name>
              <bitOffset>12</bitOffset>
              <bitWidth>1</bitWidth>
            </field>
            <field>
              <name>ID13</name>
              <bitOffset>13</bitOffset>
              <bitWidth>1</bitWidth>
            </field>
            <field>
              <name>ID14</name>
              <bitOffset>14</bitOffset>
              <bitWidth>1</bitWidth>
            </field>
            <field>
              <name>ID15</name>
              <bitOffset>15</bitOffset>
              <bitWidth>1</bitWidth>
            </field>
          </fields>
        </register>
        <register>
          <name>ODR</name>
          <addressOffset>0x14</addressOffset>
          <size>0x20</size>
          <fields>
            <field>
              <name>OD0</name>
              <bitOffset>0</bitOffset>
              <bitWidth>1</bitWidth>
            </field>
            <field>
              <name>OD1</name>
              <bitOffset>1</bitOffset>
              <bitWidth>1</bitWidth>
            </field>
            <field>
              <name>OD2</name>
              <bitOffset>2</bitOffset>
              <bitWidth>1</bitWidth>
            </field>
            <field>
              <name>OD3</name>
              <bitOffset>3</bitOffset>
              <bitWidth>1</bitWidth>
            </field>
            <field>
              <name>OD4</name>
              <bitOffset>4</bitOffset>
              <bitWidth>1</bitWidth>
            </field>
            <field>
              <name>OD5</name>
              <bitOffset>5</bitOffset>
              <bitWidth>1</bitWidth>
            </field>
            <field>
              <name>OD6</name>
              <bitOffset>6</bitOffset>
              <bitWidth>1</bitWidth>
            </field>
            <field>
              <name>OD7</name>
              <bitOffset>7</bitOffset>
              <bitWidth>1</bitWidth>
            </field>
            <field>
              <name>OD8</name>
              <bitOffset>8</bitOffset>
              <bitWidth>1</bitWidth>
            </field>
            <field>
              <name>OD9</name>
              <bitOffset>9</bitOffset>
              <bitWidth>1</bitWidth>
            </field>
            <field>
              <name>OD10</name>
              <bitOffset>10</bitOffset>
              <bitWidth>1</bitWidth>
            </field>
            <field>
              <name>OD11</name>
              <bitOffset>11</bitOffset>
              <bitWidth>1</bitWidth>
            </field>
            <field>
              <name>OD12</name>
              <bitOffset>12</bitOffset>
              <bitWidth>1</bitWidth>
            </field>
            <field>
              <name>OD13</name>
              <bitOffset>13</bitOffset>
              <bitWidth>1</bitWidth>
            </field>
            <field>
              <name>OD14</name>
              <bitOffset>14</bitOffset>
              <bitWidth>1</bitWidth>
            </field>
            <field>
              <name>OD15</name>
              <bitOffset>15</bitOffset>
              <bitWidth>1</bitWidth>
            </field>
          </fields>
        </register>
        <register>
          <name>BSRR</name>
          <addressOffset>0x18</addressOffset>
          <size>0x20</size>
          <fields>
            <field>
              <name>BS0</name>
              <bitOffset>0</bitOffset>
              <bitWidth>1</bitWidth>
            </field>
            <field>
              <name>BS1</name>
              <bitOffset>1</bitOffset>
              <bitWidth>1</bitWidth>
            </field>
            <field>
              <name>BS2</name>
              <bitOffset>2</bitOffset>
              <bitWidth>1</bitWidth>
            </field>
            <field>
              <name>BS3</name>
              <bitOffset>3</bitOffset>
              <bitWidth>1</bitWidth>
            </field>
            <field>
              <name>BS4</name>
              <bitOffset>4</bitOffset>
              <bitWidth>1</bitWidth>
            </field>
            <field>
              <name>BS5</name>
              <bitOffset>5</bitOffset>
              <bitWidth>1</bitWidth>
            </field>
            <field>
              <name>BS6</name>
              <bitOffset>6</bitOffset>
              <bitWidth>1</bitWidth>
            </field>
            <field>
              <name>BS7</name>
              <bitOffset>7</bitOffset>
              <bitWidth>1</bitWidth>
            </field>
            <field>
              <name>BS8</name>
              <bitOffset>8</bitOffset>
              <bitWidth>1</bitWidth>
            </field>
            <field>
              <name>BS9</name>
              <bitOffset>9</bitOffset>
              <bitWidth>1</bitWidth>
            </field>
            <field>
              <name>BS10</name>
              <bitOffset>10</bitOffset>
              <bitWidth>1</bitWidth>
            </field>
            <field>
              <name>BS11</name>
              <bitOffset>11</bitOffset>
              <bitWidth>1</bitWidth>
            </field>
            <field>
              <name>BS12</name>
              <bitOffset>12</bitOffset>
              <bitWidth>1</bitWidth>
            </field>
            <field>
              <name>BS13</name>
              <bitOffset>13</bitOffset>
              <bitWidth>1</bitWidth>
            </field>
            <field>
              <name>BS14</name>
              <bitOffset>14</bitOffset>
              <bitWidth>1</bitWidth>
            </field>
            <field>
              <name>BS15</name>
              <bitOffset>15</bitOffset>
              <bitWidth>1</bitWidth>
            </field>
            <field>
              <name>BR0</name>
              <bitOffset>16</bitOffset>
              <bitWidth>1</bitWidth>
            </field>
            <field>
              <name>BR1</name>
              <bitOffset>17</bitOffset>
              <bitWidth>1</bitWidth>
            </field>
            <field>
              <name>BR2</name>
              <bitOffset>18</bitOffset>
              <bitWidth>1</bitWidth>
            </field>
            <field>
              <name>BR3</name>
              <bitOffset>19</bitOffset>
              <bitWidth>1</bitWidth>
            </field>
            <field>
              <name>BR4</name>
              <bitOffset>20</bitOffset>
              <bitWidth>1</bitWidth>
            </field>
            <field>
              <name>BR5</name>
              <bitOffset>21</bitOffset>
              <bitWidth>1</bitWidth>
            </field>
            <field>
              <name>BR6</name>
              <bitOffset>22</bitOffset>
              <bitWidth>1</bitWidth>
            </field>
            <field>
              <name>BR7</name>
              <bitOffset>23</bitOffset>
              <bitWidth>1</bitWidth>
            </field>
            <field>
              <name>BR8</name>
              <bitOffset>24</bitOffset>
              <bitWidth>1</bitWidth>
            </field>
            <field>
              <name>BR9</name>
              <bitOffset>25</bitOffset>
              <bitWidth>1</bitWidth>
            </field>
            <field>
              <name>BR10</name>
              <bitOffset>26</bitOffset>
              <bitWidth>1</bitWidth>
            </field>
            <field>
              <name>BR11</name>
              <bitOffset>27</bitOffset>
              <bitWidth>1</bitWidth>
            </field>
            <field>
              <name>BR12</name>
              <bitOffset>28</bitOffset>
              <bitWidth>1</bitWidth>
            </field>
            <field>
              <name>BR13</name>
              <bitOffset>29</bitOffset>
              <bitWidth>1</bitWidth>
            </field>
            <field>
              <name>BR14</name>
              <bitOffset>30</bitOffset>
              <bitWidth>1</bitWidth>
            </field>
            <field>
              <name>BR15</name>
              <bitOffset>31</bitOffset>
              <bitWidth>1</bitWidth>
            </field>
          </fields>
        </register>
        <register>
          <name>LCKR</name>
          <addressOffset>0x1c</addressOffset>
          <size>0x20</size>
        </register>
        <register>
          <name>AFR.0</name>
          <addressOffset>0x20</addressOffset>
          <size>0x20</size>
        </register>
        <register>
          <name>AFR.1</name>
          <addressOffset>0x24</addressOffset>
          <size>0x20</size>
          <fields>
            <field>
              <name>AFSEL8</name>
              <bitOffset>0</bitOffset>
              <bitWidth>4</bitWidth>
            </field>
            <field>
              <name>AFSEL9</name>
              <bitOffset>4</bitOffset>
              <bitWidth>4</bitWidth>
            </field>
            <field>
              <name>AFSEL10</name>
              <bitOffset>8</bitOffset>
              <bitWidth>4</bitWidth>
            </field>
            <field>
              <name>AFSEL11</name>
              <bitOffset>12</bitOffset>
              <bitWidth>4</bitWidth>
            </field>
            <field>
              <name>AFSEL12</name>
              <bitOffset>16</bitOffset>
              <bitWidth>4</bitWidth>
            </field>
            <field>
              <name>AFSEL13</name>
              <bitOffset>20</bitOffset>
              <bitWidth>4</bitWidth>
            </field>
            <field>
              <name>AFSEL14</name>
              <bitOffset>24</bitOffset>
              <bitWidth>4</bitWidth>
            </field>
            <field>
              <name>AFSEL15</name>
              <bitOffset>28</bitOffset>
              <bitWidth>4</bitWidth>
            </field>
          </fields>
        </register>
      </registers>
    </peripheral>
    <peripheral>
      <name>GPIOC</name>
      <baseAddress>0x40020800</baseAddress>
      <registers>
        <register>
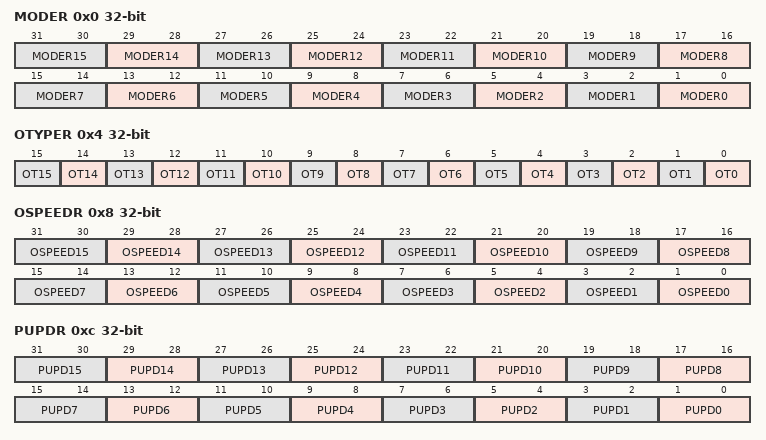
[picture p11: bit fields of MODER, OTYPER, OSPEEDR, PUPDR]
          <name>MODER</name>
          <addressOffset>0x0</addressOffset>
          <size>0x20</size>
          <fields>
            <field>
              <name>MODER0</name>
              <bitOffset>0</bitOffset>
              <bitWidth>2</bitWidth>
            </field>
            <field>
              <name>MODER1</name>
              <bitOffset>2</bitOffset>
              <bitWidth>2</bitWidth>
            </field>
            <field>
              <name>MODER2</name>
              <bitOffset>4</bitOffset>
              <bitWidth>2</bitWidth>
            </field>
            <field>
              <name>MODER3</name>
              <bitOffset>6</bitOffset>
              <bitWidth>2</bitWidth>
            </field>
            <field>
              <name>MODER4</name>
              <bitOffset>8</bitOffset>
              <bitWidth>2</bitWidth>
            </field>
            <field>
              <name>MODER5</name>
              <bitOffset>10</bitOffset>
              <bitWidth>2</bitWidth>
            </field>
            <field>
              <name>MODER6</name>
              <bitOffset>12</bitOffset>
              <bitWidth>2</bitWidth>
            </field>
            <field>
              <name>MODER7</name>
              <bitOffset>14</bitOffset>
              <bitWidth>2</bitWidth>
            </field>
            <field>
              <name>MODER8</name>
              <bitOffset>16</bitOffset>
              <bitWidth>2</bitWidth>
            </field>
            <field>
              <name>MODER9</name>
              <bitOffset>18</bitOffset>
              <bitWidth>2</bitWidth>
            </field>
            <field>
              <name>MODER10</name>
              <bitOffset>20</bitOffset>
              <bitWidth>2</bitWidth>
            </field>
            <field>
              <name>MODER11</name>
              <bitOffset>22</bitOffset>
              <bitWidth>2</bitWidth>
            </field>
            <field>
              <name>MODER12</name>
              <bitOffset>24</bitOffset>
              <bitWidth>2</bitWidth>
            </field>
            <field>
              <name>MODER13</name>
              <bitOffset>26</bitOffset>
              <bitWidth>2</bitWidth>
            </field>
            <field>
              <name>MODER14</name>
              <bitOffset>28</bitOffset>
              <bitWidth>2</bitWidth>
            </field>
            <field>
              <name>MODER15</name>
              <bitOffset>30</bitOffset>
              <bitWidth>2</bitWidth>
            </field>
          </fields>
        </register>
        <register>
          <name>OTYPER</name>
          <addressOffset>0x4</addressOffset>
          <size>0x20</size>
          <fields>
            <field>
              <name>OT0</name>
              <bitOffset>0</bitOffset>
              <bitWidth>1</bitWidth>
            </field>
            <field>
              <name>OT1</name>
              <bitOffset>1</bitOffset>
              <bitWidth>1</bitWidth>
            </field>
            <field>
              <name>OT2</name>
              <bitOffset>2</bitOffset>
              <bitWidth>1</bitWidth>
            </field>
            <field>
              <name>OT3</name>
              <bitOffset>3</bitOffset>
              <bitWidth>1</bitWidth>
            </field>
            <field>
              <name>OT4</name>
              <bitOffset>4</bitOffset>
              <bitWidth>1</bitWidth>
            </field>
            <field>
              <name>OT5</name>
              <bitOffset>5</bitOffset>
              <bitWidth>1</bitWidth>
            </field>
            <field>
              <name>OT6</name>
              <bitOffset>6</bitOffset>
              <bitWidth>1</bitWidth>
            </field>
            <field>
              <name>OT7</name>
              <bitOffset>7</bitOffset>
              <bitWidth>1</bitWidth>
            </field>
            <field>
              <name>OT8</name>
              <bitOffset>8</bitOffset>
              <bitWidth>1</bitWidth>
            </field>
            <field>
              <name>OT9</name>
              <bitOffset>9</bitOffset>
              <bitWidth>1</bitWidth>
            </field>
            <field>
              <name>OT10</name>
              <bitOffset>10</bitOffset>
              <bitWidth>1</bitWidth>
            </field>
            <field>
              <name>OT11</name>
              <bitOffset>11</bitOffset>
              <bitWidth>1</bitWidth>
            </field>
            <field>
              <name>OT12</name>
              <bitOffset>12</bitOffset>
              <bitWidth>1</bitWidth>
            </field>
            <field>
              <name>OT13</name>
              <bitOffset>13</bitOffset>
              <bitWidth>1</bitWidth>
            </field>
            <field>
              <name>OT14</name>
              <bitOffset>14</bitOffset>
              <bitWidth>1</bitWidth>
            </field>
            <field>
              <name>OT15</name>
              <bitOffset>15</bitOffset>
              <bitWidth>1</bitWidth>
            </field>
          </fields>
        </register>
        <register>
          <name>OSPEEDR</name>
          <addressOffset>0x8</addressOffset>
          <size>0x20</size>
          <fields>
            <field>
              <name>OSPEED0</name>
              <bitOffset>0</bitOffset>
              <bitWidth>2</bitWidth>
            </field>
            <field>
              <name>OSPEED1</name>
              <bitOffset>2</bitOffset>
              <bitWidth>2</bitWidth>
            </field>
            <field>
              <name>OSPEED2</name>
              <bitOffset>4</bitOffset>
              <bitWidth>2</bitWidth>
            </field>
            <field>
              <name>OSPEED3</name>
              <bitOffset>6</bitOffset>
              <bitWidth>2</bitWidth>
            </field>
            <field>
              <name>OSPEED4</name>
              <bitOffset>8</bitOffset>
              <bitWidth>2</bitWidth>
            </field>
            <field>
              <name>OSPEED5</name>
              <bitOffset>10</bitOffset>
              <bitWidth>2</bitWidth>
            </field>
            <field>
              <name>OSPEED6</name>
              <bitOffset>12</bitOffset>
              <bitWidth>2</bitWidth>
            </field>
            <field>
              <name>OSPEED7</name>
              <bitOffset>14</bitOffset>
              <bitWidth>2</bitWidth>
            </field>
            <field>
              <name>OSPEED8</name>
              <bitOffset>16</bitOffset>
              <bitWidth>2</bitWidth>
            </field>
            <field>
              <name>OSPEED9</name>
              <bitOffset>18</bitOffset>
              <bitWidth>2</bitWidth>
            </field>
            <field>
              <name>OSPEED10</name>
              <bitOffset>20</bitOffset>
              <bitWidth>2</bitWidth>
            </field>
            <field>
              <name>OSPEED11</name>
              <bitOffset>22</bitOffset>
              <bitWidth>2</bitWidth>
            </field>
            <field>
              <name>OSPEED12</name>
              <bitOffset>24</bitOffset>
              <bitWidth>2</bitWidth>
            </field>
            <field>
              <name>OSPEED13</name>
              <bitOffset>26</bitOffset>
              <bitWidth>2</bitWidth>
            </field>
            <field>
              <name>OSPEED14</name>
              <bitOffset>28</bitOffset>
              <bitWidth>2</bitWidth>
            </field>
            <field>
              <name>OSPEED15</name>
              <bitOffset>30</bitOffset>
              <bitWidth>2</bitWidth>
            </field>
          </fields>
        </register>
        <register>
          <name>PUPDR</name>
          <addressOffset>0xc</addressOffset>
          <size>0x20</size>
          <fields>
            <field>
              <name>PUPD0</name>
              <bitOffset>0</bitOffset>
              <bitWidth>2</bitWidth>
            </field>
            <field>
              <name>PUPD1</name>
              <bitOffset>2</bitOffset>
              <bitWidth>2</bitWidth>
            </field>
            <field>
              <name>PUPD2</name>
              <bitOffset>4</bitOffset>
              <bitWidth>2</bitWidth>
            </field>
            <field>
              <name>PUPD3</name>
              <bitOffset>6</bitOffset>
              <bitWidth>2</bitWidth>
            </field>
            <field>
              <name>PUPD4</name>
              <bitOffset>8</bitOffset>
              <bitWidth>2</bitWidth>
            </field>
            <field>
              <name>PUPD5</name>
              <bitOffset>10</bitOffset>
              <bitWidth>2</bitWidth>
            </field>
            <field>
              <name>PUPD6</name>
              <bitOffset>12</bitOffset>
              <bitWidth>2</bitWidth>
            </field>
            <field>
              <name>PUPD7</name>
              <bitOffset>14</bitOffset>
              <bitWidth>2</bitWidth>
            </field>
            <field>
              <name>PUPD8</name>
              <bitOffset>16</bitOffset>
              <bitWidth>2</bitWidth>
            </field>
            <field>
              <name>PUPD9</name>
              <bitOffset>18</bitOffset>
              <bitWidth>2</bitWidth>
            </field>
            <field>
              <name>PUPD10</name>
              <bitOffset>20</bitOffset>
              <bitWidth>2</bitWidth>
            </field>
            <field>
              <name>PUPD11</name>
              <bitOffset>22</bitOffset>
              <bitWidth>2</bitWidth>
            </field>
            <field>
              <name>PUPD12</name>
              <bitOffset>24</bitOffset>
              <bitWidth>2</bitWidth>
            </field>
            <field>
              <name>PUPD13</name>
              <bitOffset>26</bitOffset>
              <bitWidth>2</bitWidth>
            </field>
            <field>
              <name>PUPD14</name>
              <bitOffset>28</bitOffset>
              <bitWidth>2</bitWidth>
            </field>
            <field>
              <name>PUPD15</name>
              <bitOffset>30</bitOffset>
              <bitWidth>2</bitWidth>
            </field>
          </fields>
        </register>
        <register>
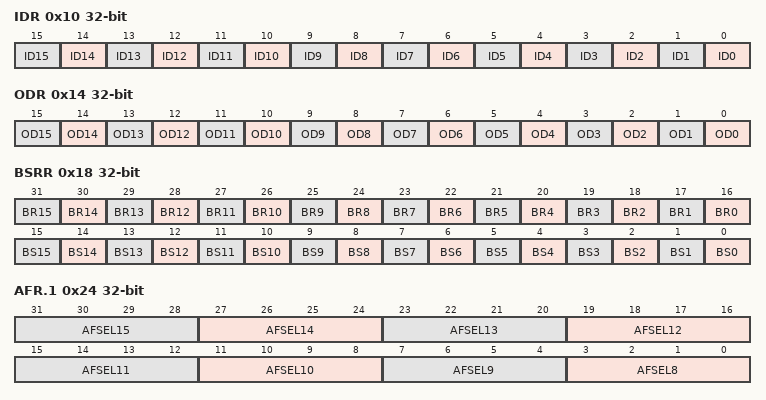
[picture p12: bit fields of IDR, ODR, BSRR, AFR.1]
          <name>IDR</name>
          <addressOffset>0x10</addressOffset>
          <size>0x20</size>
          <fields>
            <field>
              <name>ID0</name>
              <bitOffset>0</bitOffset>
              <bitWidth>1</bitWidth>
            </field>
            <field>
              <name>ID1</name>
              <bitOffset>1</bitOffset>
              <bitWidth>1</bitWidth>
            </field>
            <field>
              <name>ID2</name>
              <bitOffset>2</bitOffset>
              <bitWidth>1</bitWidth>
            </field>
            <field>
              <name>ID3</name>
              <bitOffset>3</bitOffset>
              <bitWidth>1</bitWidth>
            </field>
            <field>
              <name>ID4</name>
              <bitOffset>4</bitOffset>
              <bitWidth>1</bitWidth>
            </field>
            <field>
              <name>ID5</name>
              <bitOffset>5</bitOffset>
              <bitWidth>1</bitWidth>
            </field>
            <field>
              <name>ID6</name>
              <bitOffset>6</bitOffset>
              <bitWidth>1</bitWidth>
            </field>
            <field>
              <name>ID7</name>
              <bitOffset>7</bitOffset>
              <bitWidth>1</bitWidth>
            </field>
            <field>
              <name>ID8</name>
              <bitOffset>8</bitOffset>
              <bitWidth>1</bitWidth>
            </field>
            <field>
              <name>ID9</name>
              <bitOffset>9</bitOffset>
              <bitWidth>1</bitWidth>
            </field>
            <field>
              <name>ID10</name>
              <bitOffset>10</bitOffset>
              <bitWidth>1</bitWidth>
            </field>
            <field>
              <name>ID11</name>
              <bitOffset>11</bitOffset>
              <bitWidth>1</bitWidth>
            </field>
            <field>
              <name>ID12</name>
              <bitOffset>12</bitOffset>
              <bitWidth>1</bitWidth>
            </field>
            <field>
              <name>ID13</name>
              <bitOffset>13</bitOffset>
              <bitWidth>1</bitWidth>
            </field>
            <field>
              <name>ID14</name>
              <bitOffset>14</bitOffset>
              <bitWidth>1</bitWidth>
            </field>
            <field>
              <name>ID15</name>
              <bitOffset>15</bitOffset>
              <bitWidth>1</bitWidth>
            </field>
          </fields>
        </register>
        <register>
          <name>ODR</name>
          <addressOffset>0x14</addressOffset>
          <size>0x20</size>
          <fields>
            <field>
              <name>OD0</name>
              <bitOffset>0</bitOffset>
              <bitWidth>1</bitWidth>
            </field>
            <field>
              <name>OD1</name>
              <bitOffset>1</bitOffset>
              <bitWidth>1</bitWidth>
            </field>
            <field>
              <name>OD2</name>
              <bitOffset>2</bitOffset>
              <bitWidth>1</bitWidth>
            </field>
            <field>
              <name>OD3</name>
              <bitOffset>3</bitOffset>
              <bitWidth>1</bitWidth>
            </field>
            <field>
              <name>OD4</name>
              <bitOffset>4</bitOffset>
              <bitWidth>1</bitWidth>
            </field>
            <field>
              <name>OD5</name>
              <bitOffset>5</bitOffset>
              <bitWidth>1</bitWidth>
            </field>
            <field>
              <name>OD6</name>
              <bitOffset>6</bitOffset>
              <bitWidth>1</bitWidth>
            </field>
            <field>
              <name>OD7</name>
              <bitOffset>7</bitOffset>
              <bitWidth>1</bitWidth>
            </field>
            <field>
              <name>OD8</name>
              <bitOffset>8</bitOffset>
              <bitWidth>1</bitWidth>
            </field>
            <field>
              <name>OD9</name>
              <bitOffset>9</bitOffset>
              <bitWidth>1</bitWidth>
            </field>
            <field>
              <name>OD10</name>
              <bitOffset>10</bitOffset>
              <bitWidth>1</bitWidth>
            </field>
            <field>
              <name>OD11</name>
              <bitOffset>11</bitOffset>
              <bitWidth>1</bitWidth>
            </field>
            <field>
              <name>OD12</name>
              <bitOffset>12</bitOffset>
              <bitWidth>1</bitWidth>
            </field>
            <field>
              <name>OD13</name>
              <bitOffset>13</bitOffset>
              <bitWidth>1</bitWidth>
            </field>
            <field>
              <name>OD14</name>
              <bitOffset>14</bitOffset>
              <bitWidth>1</bitWidth>
            </field>
            <field>
              <name>OD15</name>
              <bitOffset>15</bitOffset>
              <bitWidth>1</bitWidth>
            </field>
          </fields>
        </register>
        <register>
          <name>BSRR</name>
          <addressOffset>0x18</addressOffset>
          <size>0x20</size>
          <fields>
            <field>
              <name>BS0</name>
              <bitOffset>0</bitOffset>
              <bitWidth>1</bitWidth>
            </field>
            <field>
              <name>BS1</name>
              <bitOffset>1</bitOffset>
              <bitWidth>1</bitWidth>
            </field>
            <field>
              <name>BS2</name>
              <bitOffset>2</bitOffset>
              <bitWidth>1</bitWidth>
            </field>
            <field>
              <name>BS3</name>
              <bitOffset>3</bitOffset>
              <bitWidth>1</bitWidth>
            </field>
            <field>
              <name>BS4</name>
              <bitOffset>4</bitOffset>
              <bitWidth>1</bitWidth>
            </field>
            <field>
              <name>BS5</name>
              <bitOffset>5</bitOffset>
              <bitWidth>1</bitWidth>
            </field>
            <field>
              <name>BS6</name>
              <bitOffset>6</bitOffset>
              <bitWidth>1</bitWidth>
            </field>
            <field>
              <name>BS7</name>
              <bitOffset>7</bitOffset>
              <bitWidth>1</bitWidth>
            </field>
            <field>
              <name>BS8</name>
              <bitOffset>8</bitOffset>
              <bitWidth>1</bitWidth>
            </field>
            <field>
              <name>BS9</name>
              <bitOffset>9</bitOffset>
              <bitWidth>1</bitWidth>
            </field>
            <field>
              <name>BS10</name>
              <bitOffset>10</bitOffset>
              <bitWidth>1</bitWidth>
            </field>
            <field>
              <name>BS11</name>
              <bitOffset>11</bitOffset>
              <bitWidth>1</bitWidth>
            </field>
            <field>
              <name>BS12</name>
              <bitOffset>12</bitOffset>
              <bitWidth>1</bitWidth>
            </field>
            <field>
              <name>BS13</name>
              <bitOffset>13</bitOffset>
              <bitWidth>1</bitWidth>
            </field>
            <field>
              <name>BS14</name>
              <bitOffset>14</bitOffset>
              <bitWidth>1</bitWidth>
            </field>
            <field>
              <name>BS15</name>
              <bitOffset>15</bitOffset>
              <bitWidth>1</bitWidth>
            </field>
            <field>
              <name>BR0</name>
              <bitOffset>16</bitOffset>
              <bitWidth>1</bitWidth>
            </field>
            <field>
              <name>BR1</name>
              <bitOffset>17</bitOffset>
              <bitWidth>1</bitWidth>
            </field>
            <field>
              <name>BR2</name>
              <bitOffset>18</bitOffset>
              <bitWidth>1</bitWidth>
            </field>
            <field>
              <name>BR3</name>
              <bitOffset>19</bitOffset>
              <bitWidth>1</bitWidth>
            </field>
            <field>
              <name>BR4</name>
              <bitOffset>20</bitOffset>
              <bitWidth>1</bitWidth>
            </field>
            <field>
              <name>BR5</name>
              <bitOffset>21</bitOffset>
              <bitWidth>1</bitWidth>
            </field>
            <field>
              <name>BR6</name>
              <bitOffset>22</bitOffset>
              <bitWidth>1</bitWidth>
            </field>
            <field>
              <name>BR7</name>
              <bitOffset>23</bitOffset>
              <bitWidth>1</bitWidth>
            </field>
            <field>
              <name>BR8</name>
              <bitOffset>24</bitOffset>
              <bitWidth>1</bitWidth>
            </field>
            <field>
              <name>BR9</name>
              <bitOffset>25</bitOffset>
              <bitWidth>1</bitWidth>
            </field>
            <field>
              <name>BR10</name>
              <bitOffset>26</bitOffset>
              <bitWidth>1</bitWidth>
            </field>
            <field>
              <name>BR11</name>
              <bitOffset>27</bitOffset>
              <bitWidth>1</bitWidth>
            </field>
            <field>
              <name>BR12</name>
              <bitOffset>28</bitOffset>
              <bitWidth>1</bitWidth>
            </field>
            <field>
              <name>BR13</name>
              <bitOffset>29</bitOffset>
              <bitWidth>1</bitWidth>
            </field>
            <field>
              <name>BR14</name>
              <bitOffset>30</bitOffset>
              <bitWidth>1</bitWidth>
            </field>
            <field>
              <name>BR15</name>
              <bitOffset>31</bitOffset>
              <bitWidth>1</bitWidth>
            </field>
          </fields>
        </register>
        <register>
          <name>LCKR</name>
          <addressOffset>0x1c</addressOffset>
          <size>0x20</size>
        </register>
        <register>
          <name>AFR.0</name>
          <addressOffset>0x20</addressOffset>
          <size>0x20</size>
        </register>
        <register>
          <name>AFR.1</name>
          <addressOffset>0x24</addressOffset>
          <size>0x20</size>
          <fields>
            <field>
              <name>AFSEL8</name>
              <bitOffset>0</bitOffset>
              <bitWidth>4</bitWidth>
            </field>
            <field>
              <name>AFSEL9</name>
              <bitOffset>4</bitOffset>
              <bitWidth>4</bitWidth>
            </field>
            <field>
              <name>AFSEL10</name>
              <bitOffset>8</bitOffset>
              <bitWidth>4</bitWidth>
            </field>
            <field>
              <name>AFSEL11</name>
              <bitOffset>12</bitOffset>
              <bitWidth>4</bitWidth>
            </field>
            <field>
              <name>AFSEL12</name>
              <bitOffset>16</bitOffset>
              <bitWidth>4</bitWidth>
            </field>
            <field>
              <name>AFSEL13</name>
              <bitOffset>20</bitOffset>
              <bitWidth>4</bitWidth>
            </field>
            <field>
              <name>AFSEL14</name>
              <bitOffset>24</bitOffset>
              <bitWidth>4</bitWidth>
            </field>
            <field>
              <name>AFSEL15</name>
              <bitOffset>28</bitOffset>
              <bitWidth>4</bitWidth>
            </field>
          </fields>
        </register>
      </registers>
    </peripheral>
    <peripheral>
      <name>GPIOD</name>
      <baseAddress>0x40020c00</baseAddress>
      <registers>
        <register>
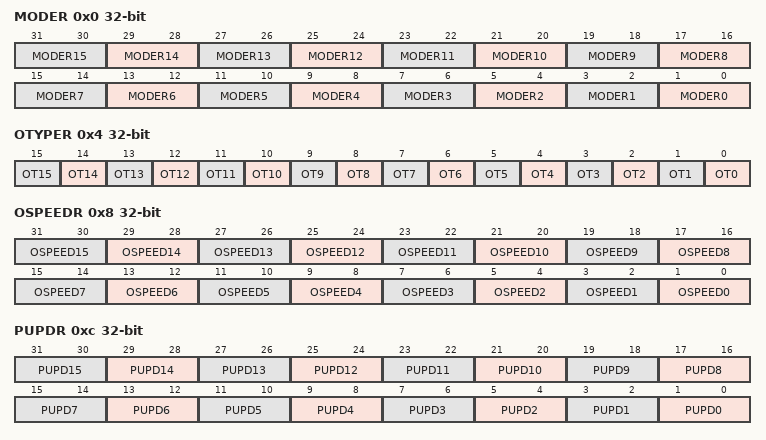
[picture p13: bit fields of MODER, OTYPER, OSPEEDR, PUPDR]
          <name>MODER</name>
          <addressOffset>0x0</addressOffset>
          <size>0x20</size>
          <fields>
            <field>
              <name>MODER0</name>
              <bitOffset>0</bitOffset>
              <bitWidth>2</bitWidth>
            </field>
            <field>
              <name>MODER1</name>
              <bitOffset>2</bitOffset>
              <bitWidth>2</bitWidth>
            </field>
            <field>
              <name>MODER2</name>
              <bitOffset>4</bitOffset>
              <bitWidth>2</bitWidth>
            </field>
            <field>
              <name>MODER3</name>
              <bitOffset>6</bitOffset>
              <bitWidth>2</bitWidth>
            </field>
            <field>
              <name>MODER4</name>
              <bitOffset>8</bitOffset>
              <bitWidth>2</bitWidth>
            </field>
            <field>
              <name>MODER5</name>
              <bitOffset>10</bitOffset>
              <bitWidth>2</bitWidth>
            </field>
            <field>
              <name>MODER6</name>
              <bitOffset>12</bitOffset>
              <bitWidth>2</bitWidth>
            </field>
            <field>
              <name>MODER7</name>
              <bitOffset>14</bitOffset>
              <bitWidth>2</bitWidth>
            </field>
            <field>
              <name>MODER8</name>
              <bitOffset>16</bitOffset>
              <bitWidth>2</bitWidth>
            </field>
            <field>
              <name>MODER9</name>
              <bitOffset>18</bitOffset>
              <bitWidth>2</bitWidth>
            </field>
            <field>
              <name>MODER10</name>
              <bitOffset>20</bitOffset>
              <bitWidth>2</bitWidth>
            </field>
            <field>
              <name>MODER11</name>
              <bitOffset>22</bitOffset>
              <bitWidth>2</bitWidth>
            </field>
            <field>
              <name>MODER12</name>
              <bitOffset>24</bitOffset>
              <bitWidth>2</bitWidth>
            </field>
            <field>
              <name>MODER13</name>
              <bitOffset>26</bitOffset>
              <bitWidth>2</bitWidth>
            </field>
            <field>
              <name>MODER14</name>
              <bitOffset>28</bitOffset>
              <bitWidth>2</bitWidth>
            </field>
            <field>
              <name>MODER15</name>
              <bitOffset>30</bitOffset>
              <bitWidth>2</bitWidth>
            </field>
          </fields>
        </register>
        <register>
          <name>OTYPER</name>
          <addressOffset>0x4</addressOffset>
          <size>0x20</size>
          <fields>
            <field>
              <name>OT0</name>
              <bitOffset>0</bitOffset>
              <bitWidth>1</bitWidth>
            </field>
            <field>
              <name>OT1</name>
              <bitOffset>1</bitOffset>
              <bitWidth>1</bitWidth>
            </field>
            <field>
              <name>OT2</name>
              <bitOffset>2</bitOffset>
              <bitWidth>1</bitWidth>
            </field>
            <field>
              <name>OT3</name>
              <bitOffset>3</bitOffset>
              <bitWidth>1</bitWidth>
            </field>
            <field>
              <name>OT4</name>
              <bitOffset>4</bitOffset>
              <bitWidth>1</bitWidth>
            </field>
            <field>
              <name>OT5</name>
              <bitOffset>5</bitOffset>
              <bitWidth>1</bitWidth>
            </field>
            <field>
              <name>OT6</name>
              <bitOffset>6</bitOffset>
              <bitWidth>1</bitWidth>
            </field>
            <field>
              <name>OT7</name>
              <bitOffset>7</bitOffset>
              <bitWidth>1</bitWidth>
            </field>
            <field>
              <name>OT8</name>
              <bitOffset>8</bitOffset>
              <bitWidth>1</bitWidth>
            </field>
            <field>
              <name>OT9</name>
              <bitOffset>9</bitOffset>
              <bitWidth>1</bitWidth>
            </field>
            <field>
              <name>OT10</name>
              <bitOffset>10</bitOffset>
              <bitWidth>1</bitWidth>
            </field>
            <field>
              <name>OT11</name>
              <bitOffset>11</bitOffset>
              <bitWidth>1</bitWidth>
            </field>
            <field>
              <name>OT12</name>
              <bitOffset>12</bitOffset>
              <bitWidth>1</bitWidth>
            </field>
            <field>
              <name>OT13</name>
              <bitOffset>13</bitOffset>
              <bitWidth>1</bitWidth>
            </field>
            <field>
              <name>OT14</name>
              <bitOffset>14</bitOffset>
              <bitWidth>1</bitWidth>
            </field>
            <field>
              <name>OT15</name>
              <bitOffset>15</bitOffset>
              <bitWidth>1</bitWidth>
            </field>
          </fields>
        </register>
        <register>
          <name>OSPEEDR</name>
          <addressOffset>0x8</addressOffset>
          <size>0x20</size>
          <fields>
            <field>
              <name>OSPEED0</name>
              <bitOffset>0</bitOffset>
              <bitWidth>2</bitWidth>
            </field>
            <field>
              <name>OSPEED1</name>
              <bitOffset>2</bitOffset>
              <bitWidth>2</bitWidth>
            </field>
            <field>
              <name>OSPEED2</name>
              <bitOffset>4</bitOffset>
              <bitWidth>2</bitWidth>
            </field>
            <field>
              <name>OSPEED3</name>
              <bitOffset>6</bitOffset>
              <bitWidth>2</bitWidth>
            </field>
            <field>
              <name>OSPEED4</name>
              <bitOffset>8</bitOffset>
              <bitWidth>2</bitWidth>
            </field>
            <field>
              <name>OSPEED5</name>
              <bitOffset>10</bitOffset>
              <bitWidth>2</bitWidth>
            </field>
            <field>
              <name>OSPEED6</name>
              <bitOffset>12</bitOffset>
              <bitWidth>2</bitWidth>
            </field>
            <field>
              <name>OSPEED7</name>
              <bitOffset>14</bitOffset>
              <bitWidth>2</bitWidth>
            </field>
            <field>
              <name>OSPEED8</name>
              <bitOffset>16</bitOffset>
              <bitWidth>2</bitWidth>
            </field>
            <field>
              <name>OSPEED9</name>
              <bitOffset>18</bitOffset>
              <bitWidth>2</bitWidth>
            </field>
            <field>
              <name>OSPEED10</name>
              <bitOffset>20</bitOffset>
              <bitWidth>2</bitWidth>
            </field>
            <field>
              <name>OSPEED11</name>
              <bitOffset>22</bitOffset>
              <bitWidth>2</bitWidth>
            </field>
            <field>
              <name>OSPEED12</name>
              <bitOffset>24</bitOffset>
              <bitWidth>2</bitWidth>
            </field>
            <field>
              <name>OSPEED13</name>
              <bitOffset>26</bitOffset>
              <bitWidth>2</bitWidth>
            </field>
            <field>
              <name>OSPEED14</name>
              <bitOffset>28</bitOffset>
              <bitWidth>2</bitWidth>
            </field>
            <field>
              <name>OSPEED15</name>
              <bitOffset>30</bitOffset>
              <bitWidth>2</bitWidth>
            </field>
          </fields>
        </register>
        <register>
          <name>PUPDR</name>
          <addressOffset>0xc</addressOffset>
          <size>0x20</size>
          <fields>
            <field>
              <name>PUPD0</name>
              <bitOffset>0</bitOffset>
              <bitWidth>2</bitWidth>
            </field>
            <field>
              <name>PUPD1</name>
              <bitOffset>2</bitOffset>
              <bitWidth>2</bitWidth>
            </field>
            <field>
              <name>PUPD2</name>
              <bitOffset>4</bitOffset>
              <bitWidth>2</bitWidth>
            </field>
            <field>
              <name>PUPD3</name>
              <bitOffset>6</bitOffset>
              <bitWidth>2</bitWidth>
            </field>
            <field>
              <name>PUPD4</name>
              <bitOffset>8</bitOffset>
              <bitWidth>2</bitWidth>
            </field>
            <field>
              <name>PUPD5</name>
              <bitOffset>10</bitOffset>
              <bitWidth>2</bitWidth>
            </field>
            <field>
              <name>PUPD6</name>
              <bitOffset>12</bitOffset>
              <bitWidth>2</bitWidth>
            </field>
            <field>
              <name>PUPD7</name>
              <bitOffset>14</bitOffset>
              <bitWidth>2</bitWidth>
            </field>
            <field>
              <name>PUPD8</name>
              <bitOffset>16</bitOffset>
              <bitWidth>2</bitWidth>
            </field>
            <field>
              <name>PUPD9</name>
              <bitOffset>18</bitOffset>
              <bitWidth>2</bitWidth>
            </field>
            <field>
              <name>PUPD10</name>
              <bitOffset>20</bitOffset>
              <bitWidth>2</bitWidth>
            </field>
            <field>
              <name>PUPD11</name>
              <bitOffset>22</bitOffset>
              <bitWidth>2</bitWidth>
            </field>
            <field>
              <name>PUPD12</name>
              <bitOffset>24</bitOffset>
              <bitWidth>2</bitWidth>
            </field>
            <field>
              <name>PUPD13</name>
              <bitOffset>26</bitOffset>
              <bitWidth>2</bitWidth>
            </field>
            <field>
              <name>PUPD14</name>
              <bitOffset>28</bitOffset>
              <bitWidth>2</bitWidth>
            </field>
            <field>
              <name>PUPD15</name>
              <bitOffset>30</bitOffset>
              <bitWidth>2</bitWidth>
            </field>
          </fields>
        </register>
        <register>
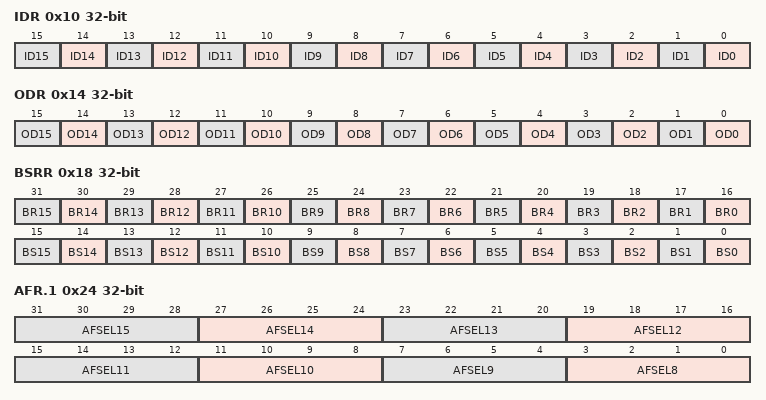
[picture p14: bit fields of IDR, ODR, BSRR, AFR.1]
          <name>IDR</name>
          <addressOffset>0x10</addressOffset>
          <size>0x20</size>
          <fields>
            <field>
              <name>ID0</name>
              <bitOffset>0</bitOffset>
              <bitWidth>1</bitWidth>
            </field>
            <field>
              <name>ID1</name>
              <bitOffset>1</bitOffset>
              <bitWidth>1</bitWidth>
            </field>
            <field>
              <name>ID2</name>
              <bitOffset>2</bitOffset>
              <bitWidth>1</bitWidth>
            </field>
            <field>
              <name>ID3</name>
              <bitOffset>3</bitOffset>
              <bitWidth>1</bitWidth>
            </field>
            <field>
              <name>ID4</name>
              <bitOffset>4</bitOffset>
              <bitWidth>1</bitWidth>
            </field>
            <field>
              <name>ID5</name>
              <bitOffset>5</bitOffset>
              <bitWidth>1</bitWidth>
            </field>
            <field>
              <name>ID6</name>
              <bitOffset>6</bitOffset>
              <bitWidth>1</bitWidth>
            </field>
            <field>
              <name>ID7</name>
              <bitOffset>7</bitOffset>
              <bitWidth>1</bitWidth>
            </field>
            <field>
              <name>ID8</name>
              <bitOffset>8</bitOffset>
              <bitWidth>1</bitWidth>
            </field>
            <field>
              <name>ID9</name>
              <bitOffset>9</bitOffset>
              <bitWidth>1</bitWidth>
            </field>
            <field>
              <name>ID10</name>
              <bitOffset>10</bitOffset>
              <bitWidth>1</bitWidth>
            </field>
            <field>
              <name>ID11</name>
              <bitOffset>11</bitOffset>
              <bitWidth>1</bitWidth>
            </field>
            <field>
              <name>ID12</name>
              <bitOffset>12</bitOffset>
              <bitWidth>1</bitWidth>
            </field>
            <field>
              <name>ID13</name>
              <bitOffset>13</bitOffset>
              <bitWidth>1</bitWidth>
            </field>
            <field>
              <name>ID14</name>
              <bitOffset>14</bitOffset>
              <bitWidth>1</bitWidth>
            </field>
            <field>
              <name>ID15</name>
              <bitOffset>15</bitOffset>
              <bitWidth>1</bitWidth>
            </field>
          </fields>
        </register>
        <register>
          <name>ODR</name>
          <addressOffset>0x14</addressOffset>
          <size>0x20</size>
          <fields>
            <field>
              <name>OD0</name>
              <bitOffset>0</bitOffset>
              <bitWidth>1</bitWidth>
            </field>
            <field>
              <name>OD1</name>
              <bitOffset>1</bitOffset>
              <bitWidth>1</bitWidth>
            </field>
            <field>
              <name>OD2</name>
              <bitOffset>2</bitOffset>
              <bitWidth>1</bitWidth>
            </field>
            <field>
              <name>OD3</name>
              <bitOffset>3</bitOffset>
              <bitWidth>1</bitWidth>
            </field>
            <field>
              <name>OD4</name>
              <bitOffset>4</bitOffset>
              <bitWidth>1</bitWidth>
            </field>
            <field>
              <name>OD5</name>
              <bitOffset>5</bitOffset>
              <bitWidth>1</bitWidth>
            </field>
            <field>
              <name>OD6</name>
              <bitOffset>6</bitOffset>
              <bitWidth>1</bitWidth>
            </field>
            <field>
              <name>OD7</name>
              <bitOffset>7</bitOffset>
              <bitWidth>1</bitWidth>
            </field>
            <field>
              <name>OD8</name>
              <bitOffset>8</bitOffset>
              <bitWidth>1</bitWidth>
            </field>
            <field>
              <name>OD9</name>
              <bitOffset>9</bitOffset>
              <bitWidth>1</bitWidth>
            </field>
            <field>
              <name>OD10</name>
              <bitOffset>10</bitOffset>
              <bitWidth>1</bitWidth>
            </field>
            <field>
              <name>OD11</name>
              <bitOffset>11</bitOffset>
              <bitWidth>1</bitWidth>
            </field>
            <field>
              <name>OD12</name>
              <bitOffset>12</bitOffset>
              <bitWidth>1</bitWidth>
            </field>
            <field>
              <name>OD13</name>
              <bitOffset>13</bitOffset>
              <bitWidth>1</bitWidth>
            </field>
            <field>
              <name>OD14</name>
              <bitOffset>14</bitOffset>
              <bitWidth>1</bitWidth>
            </field>
            <field>
              <name>OD15</name>
              <bitOffset>15</bitOffset>
              <bitWidth>1</bitWidth>
            </field>
          </fields>
        </register>
        <register>
          <name>BSRR</name>
          <addressOffset>0x18</addressOffset>
          <size>0x20</size>
          <fields>
            <field>
              <name>BS0</name>
              <bitOffset>0</bitOffset>
              <bitWidth>1</bitWidth>
            </field>
            <field>
              <name>BS1</name>
              <bitOffset>1</bitOffset>
              <bitWidth>1</bitWidth>
            </field>
            <field>
              <name>BS2</name>
              <bitOffset>2</bitOffset>
              <bitWidth>1</bitWidth>
            </field>
            <field>
              <name>BS3</name>
              <bitOffset>3</bitOffset>
              <bitWidth>1</bitWidth>
            </field>
            <field>
              <name>BS4</name>
              <bitOffset>4</bitOffset>
              <bitWidth>1</bitWidth>
            </field>
            <field>
              <name>BS5</name>
              <bitOffset>5</bitOffset>
              <bitWidth>1</bitWidth>
            </field>
            <field>
              <name>BS6</name>
              <bitOffset>6</bitOffset>
              <bitWidth>1</bitWidth>
            </field>
            <field>
              <name>BS7</name>
              <bitOffset>7</bitOffset>
              <bitWidth>1</bitWidth>
            </field>
            <field>
              <name>BS8</name>
              <bitOffset>8</bitOffset>
              <bitWidth>1</bitWidth>
            </field>
            <field>
              <name>BS9</name>
              <bitOffset>9</bitOffset>
              <bitWidth>1</bitWidth>
            </field>
            <field>
              <name>BS10</name>
              <bitOffset>10</bitOffset>
              <bitWidth>1</bitWidth>
            </field>
            <field>
              <name>BS11</name>
              <bitOffset>11</bitOffset>
              <bitWidth>1</bitWidth>
            </field>
            <field>
              <name>BS12</name>
              <bitOffset>12</bitOffset>
              <bitWidth>1</bitWidth>
            </field>
            <field>
              <name>BS13</name>
              <bitOffset>13</bitOffset>
              <bitWidth>1</bitWidth>
            </field>
            <field>
              <name>BS14</name>
              <bitOffset>14</bitOffset>
              <bitWidth>1</bitWidth>
            </field>
            <field>
              <name>BS15</name>
              <bitOffset>15</bitOffset>
              <bitWidth>1</bitWidth>
            </field>
            <field>
              <name>BR0</name>
              <bitOffset>16</bitOffset>
              <bitWidth>1</bitWidth>
            </field>
            <field>
              <name>BR1</name>
              <bitOffset>17</bitOffset>
              <bitWidth>1</bitWidth>
            </field>
            <field>
              <name>BR2</name>
              <bitOffset>18</bitOffset>
              <bitWidth>1</bitWidth>
            </field>
            <field>
              <name>BR3</name>
              <bitOffset>19</bitOffset>
              <bitWidth>1</bitWidth>
            </field>
            <field>
              <name>BR4</name>
              <bitOffset>20</bitOffset>
              <bitWidth>1</bitWidth>
            </field>
            <field>
              <name>BR5</name>
              <bitOffset>21</bitOffset>
              <bitWidth>1</bitWidth>
            </field>
            <field>
              <name>BR6</name>
              <bitOffset>22</bitOffset>
              <bitWidth>1</bitWidth>
            </field>
            <field>
              <name>BR7</name>
              <bitOffset>23</bitOffset>
              <bitWidth>1</bitWidth>
            </field>
            <field>
              <name>BR8</name>
              <bitOffset>24</bitOffset>
              <bitWidth>1</bitWidth>
            </field>
            <field>
              <name>BR9</name>
              <bitOffset>25</bitOffset>
              <bitWidth>1</bitWidth>
            </field>
            <field>
              <name>BR10</name>
              <bitOffset>26</bitOffset>
              <bitWidth>1</bitWidth>
            </field>
            <field>
              <name>BR11</name>
              <bitOffset>27</bitOffset>
              <bitWidth>1</bitWidth>
            </field>
            <field>
              <name>BR12</name>
              <bitOffset>28</bitOffset>
              <bitWidth>1</bitWidth>
            </field>
            <field>
              <name>BR13</name>
              <bitOffset>29</bitOffset>
              <bitWidth>1</bitWidth>
            </field>
            <field>
              <name>BR14</name>
              <bitOffset>30</bitOffset>
              <bitWidth>1</bitWidth>
            </field>
            <field>
              <name>BR15</name>
              <bitOffset>31</bitOffset>
              <bitWidth>1</bitWidth>
            </field>
          </fields>
        </register>
        <register>
          <name>LCKR</name>
          <addressOffset>0x1c</addressOffset>
          <size>0x20</size>
        </register>
        <register>
          <name>AFR.0</name>
          <addressOffset>0x20</addressOffset>
          <size>0x20</size>
        </register>
        <register>
          <name>AFR.1</name>
          <addressOffset>0x24</addressOffset>
          <size>0x20</size>
          <fields>
            <field>
              <name>AFSEL8</name>
              <bitOffset>0</bitOffset>
              <bitWidth>4</bitWidth>
            </field>
            <field>
              <name>AFSEL9</name>
              <bitOffset>4</bitOffset>
              <bitWidth>4</bitWidth>
            </field>
            <field>
              <name>AFSEL10</name>
              <bitOffset>8</bitOffset>
              <bitWidth>4</bitWidth>
            </field>
            <field>
              <name>AFSEL11</name>
              <bitOffset>12</bitOffset>
              <bitWidth>4</bitWidth>
            </field>
            <field>
              <name>AFSEL12</name>
              <bitOffset>16</bitOffset>
              <bitWidth>4</bitWidth>
            </field>
            <field>
              <name>AFSEL13</name>
              <bitOffset>20</bitOffset>
              <bitWidth>4</bitWidth>
            </field>
            <field>
              <name>AFSEL14</name>
              <bitOffset>24</bitOffset>
              <bitWidth>4</bitWidth>
            </field>
            <field>
              <name>AFSEL15</name>
              <bitOffset>28</bitOffset>
              <bitWidth>4</bitWidth>
            </field>
          </fields>
        </register>
      </registers>
    </peripheral>
    <peripheral>
      <name>GPIOE</name>
      <baseAddress>0x40021000</baseAddress>
      <registers>
        <register>
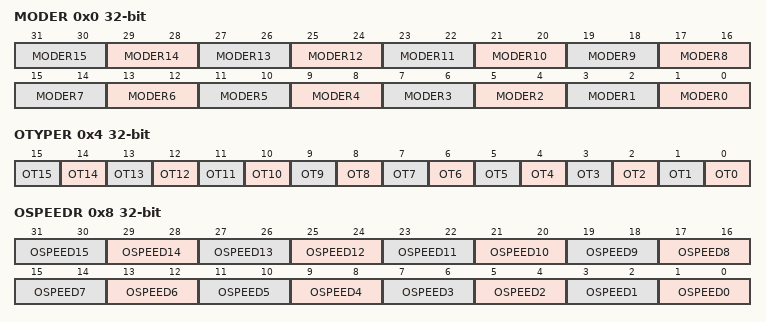
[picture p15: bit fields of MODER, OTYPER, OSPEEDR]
          <name>MODER</name>
          <addressOffset>0x0</addressOffset>
          <size>0x20</size>
          <fields>
            <field>
              <name>MODER0</name>
              <bitOffset>0</bitOffset>
              <bitWidth>2</bitWidth>
            </field>
            <field>
              <name>MODER1</name>
              <bitOffset>2</bitOffset>
              <bitWidth>2</bitWidth>
            </field>
            <field>
              <name>MODER2</name>
              <bitOffset>4</bitOffset>
              <bitWidth>2</bitWidth>
            </field>
            <field>
              <name>MODER3</name>
              <bitOffset>6</bitOffset>
              <bitWidth>2</bitWidth>
            </field>
            <field>
              <name>MODER4</name>
              <bitOffset>8</bitOffset>
              <bitWidth>2</bitWidth>
            </field>
            <field>
              <name>MODER5</name>
              <bitOffset>10</bitOffset>
              <bitWidth>2</bitWidth>
            </field>
            <field>
              <name>MODER6</name>
              <bitOffset>12</bitOffset>
              <bitWidth>2</bitWidth>
            </field>
            <field>
              <name>MODER7</name>
              <bitOffset>14</bitOffset>
              <bitWidth>2</bitWidth>
            </field>
            <field>
              <name>MODER8</name>
              <bitOffset>16</bitOffset>
              <bitWidth>2</bitWidth>
            </field>
            <field>
              <name>MODER9</name>
              <bitOffset>18</bitOffset>
              <bitWidth>2</bitWidth>
            </field>
            <field>
              <name>MODER10</name>
              <bitOffset>20</bitOffset>
              <bitWidth>2</bitWidth>
            </field>
            <field>
              <name>MODER11</name>
              <bitOffset>22</bitOffset>
              <bitWidth>2</bitWidth>
            </field>
            <field>
              <name>MODER12</name>
              <bitOffset>24</bitOffset>
              <bitWidth>2</bitWidth>
            </field>
            <field>
              <name>MODER13</name>
              <bitOffset>26</bitOffset>
              <bitWidth>2</bitWidth>
            </field>
            <field>
              <name>MODER14</name>
              <bitOffset>28</bitOffset>
              <bitWidth>2</bitWidth>
            </field>
            <field>
              <name>MODER15</name>
              <bitOffset>30</bitOffset>
              <bitWidth>2</bitWidth>
            </field>
          </fields>
        </register>
        <register>
          <name>OTYPER</name>
          <addressOffset>0x4</addressOffset>
          <size>0x20</size>
          <fields>
            <field>
              <name>OT0</name>
              <bitOffset>0</bitOffset>
              <bitWidth>1</bitWidth>
            </field>
            <field>
              <name>OT1</name>
              <bitOffset>1</bitOffset>
              <bitWidth>1</bitWidth>
            </field>
            <field>
              <name>OT2</name>
              <bitOffset>2</bitOffset>
              <bitWidth>1</bitWidth>
            </field>
            <field>
              <name>OT3</name>
              <bitOffset>3</bitOffset>
              <bitWidth>1</bitWidth>
            </field>
            <field>
              <name>OT4</name>
              <bitOffset>4</bitOffset>
              <bitWidth>1</bitWidth>
            </field>
            <field>
              <name>OT5</name>
              <bitOffset>5</bitOffset>
              <bitWidth>1</bitWidth>
            </field>
            <field>
              <name>OT6</name>
              <bitOffset>6</bitOffset>
              <bitWidth>1</bitWidth>
            </field>
            <field>
              <name>OT7</name>
              <bitOffset>7</bitOffset>
              <bitWidth>1</bitWidth>
            </field>
            <field>
              <name>OT8</name>
              <bitOffset>8</bitOffset>
              <bitWidth>1</bitWidth>
            </field>
            <field>
              <name>OT9</name>
              <bitOffset>9</bitOffset>
              <bitWidth>1</bitWidth>
            </field>
            <field>
              <name>OT10</name>
              <bitOffset>10</bitOffset>
              <bitWidth>1</bitWidth>
            </field>
            <field>
              <name>OT11</name>
              <bitOffset>11</bitOffset>
              <bitWidth>1</bitWidth>
            </field>
            <field>
              <name>OT12</name>
              <bitOffset>12</bitOffset>
              <bitWidth>1</bitWidth>
            </field>
            <field>
              <name>OT13</name>
              <bitOffset>13</bitOffset>
              <bitWidth>1</bitWidth>
            </field>
            <field>
              <name>OT14</name>
              <bitOffset>14</bitOffset>
              <bitWidth>1</bitWidth>
            </field>
            <field>
              <name>OT15</name>
              <bitOffset>15</bitOffset>
              <bitWidth>1</bitWidth>
            </field>
          </fields>
        </register>
        <register>
          <name>OSPEEDR</name>
          <addressOffset>0x8</addressOffset>
          <size>0x20</size>
          <fields>
            <field>
              <name>OSPEED0</name>
              <bitOffset>0</bitOffset>
              <bitWidth>2</bitWidth>
            </field>
            <field>
              <name>OSPEED1</name>
              <bitOffset>2</bitOffset>
              <bitWidth>2</bitWidth>
            </field>
            <field>
              <name>OSPEED2</name>
              <bitOffset>4</bitOffset>
              <bitWidth>2</bitWidth>
            </field>
            <field>
              <name>OSPEED3</name>
              <bitOffset>6</bitOffset>
              <bitWidth>2</bitWidth>
            </field>
            <field>
              <name>OSPEED4</name>
              <bitOffset>8</bitOffset>
              <bitWidth>2</bitWidth>
            </field>
            <field>
              <name>OSPEED5</name>
              <bitOffset>10</bitOffset>
              <bitWidth>2</bitWidth>
            </field>
            <field>
              <name>OSPEED6</name>
              <bitOffset>12</bitOffset>
              <bitWidth>2</bitWidth>
            </field>
            <field>
              <name>OSPEED7</name>
              <bitOffset>14</bitOffset>
              <bitWidth>2</bitWidth>
            </field>
            <field>
              <name>OSPEED8</name>
              <bitOffset>16</bitOffset>
              <bitWidth>2</bitWidth>
            </field>
            <field>
              <name>OSPEED9</name>
              <bitOffset>18</bitOffset>
              <bitWidth>2</bitWidth>
            </field>
            <field>
              <name>OSPEED10</name>
              <bitOffset>20</bitOffset>
              <bitWidth>2</bitWidth>
            </field>
            <field>
              <name>OSPEED11</name>
              <bitOffset>22</bitOffset>
              <bitWidth>2</bitWidth>
            </field>
            <field>
              <name>OSPEED12</name>
              <bitOffset>24</bitOffset>
              <bitWidth>2</bitWidth>
            </field>
            <field>
              <name>OSPEED13</name>
              <bitOffset>26</bitOffset>
              <bitWidth>2</bitWidth>
            </field>
            <field>
              <name>OSPEED14</name>
              <bitOffset>28</bitOffset>
              <bitWidth>2</bitWidth>
            </field>
            <field>
              <name>OSPEED15</name>
              <bitOffset>30</bitOffset>
              <bitWidth>2</bitWidth>
            </field>
          </fields>
        </register>
        <register>
          <name>PUPDR</name>
          <addressOffset>0xc</addressOffset>
          <size>0x20</size>
          <fields>
            <field>
              <name>PUPD0</name>
              <bitOffset>0</bitOffset>
              <bitWidth>2</bitWidth>
            </field>
            <field>
              <name>PUPD1</name>
              <bitOffset>2</bitOffset>
              <bitWidth>2</bitWidth>
            </field>
            <field>
              <name>PUPD2</name>
              <bitOffset>4</bitOffset>
              <bitWidth>2</bitWidth>
            </field>
            <field>
              <name>PUPD3</name>
              <bitOffset>6</bitOffset>
              <bitWidth>2</bitWidth>
            </field>
            <field>
              <name>PUPD4</name>
              <bitOffset>8</bitOffset>
              <bitWidth>2</bitWidth>
            </field>
            <field>
              <name>PUPD5</name>
              <bitOffset>10</bitOffset>
              <bitWidth>2</bitWidth>
            </field>
            <field>
              <name>PUPD6</name>
              <bitOffset>12</bitOffset>
              <bitWidth>2</bitWidth>
            </field>
            <field>
              <name>PUPD7</name>
              <bitOffset>14</bitOffset>
              <bitWidth>2</bitWidth>
            </field>
            <field>
              <name>PUPD8</name>
              <bitOffset>16</bitOffset>
              <bitWidth>2</bitWidth>
            </field>
            <field>
              <name>PUPD9</name>
              <bitOffset>18</bitOffset>
              <bitWidth>2</bitWidth>
            </field>
            <field>
              <name>PUPD10</name>
              <bitOffset>20</bitOffset>
              <bitWidth>2</bitWidth>
            </field>
            <field>
              <name>PUPD11</name>
              <bitOffset>22</bitOffset>
              <bitWidth>2</bitWidth>
            </field>
            <field>
              <name>PUPD12</name>
              <bitOffset>24</bitOffset>
              <bitWidth>2</bitWidth>
            </field>
            <field>
              <name>PUPD13</name>
              <bitOffset>26</bitOffset>
              <bitWidth>2</bitWidth>
            </field>
            <field>
              <name>PUPD14</name>
              <bitOffset>28</bitOffset>
              <bitWidth>2</bitWidth>
            </field>
            <field>
              <name>PUPD15</name>
              <bitOffset>30</bitOffset>
              <bitWidth>2</bitWidth>
            </field>
          </fields>
        </register>
        <register>
          <name>IDR</name>
          <addressOffset>0x10</addressOffset>
          <size>0x20</size>
          <fields>
            <field>
              <name>ID0</name>
              <bitOffset>0</bitOffset>
              <bitWidth>1</bitWidth>
            </field>
            <field>
              <name>ID1</name>
              <bitOffset>1</bitOffset>
              <bitWidth>1</bitWidth>
            </field>
            <field>
              <name>ID2</name>
              <bitOffset>2</bitOffset>
              <bitWidth>1</bitWidth>
            </field>
            <field>
              <name>ID3</name>
              <bitOffset>3</bitOffset>
              <bitWidth>1</bitWidth>
            </field>
            <field>
              <name>ID4</name>
              <bitOffset>4</bitOffset>
              <bitWidth>1</bitWidth>
            </field>
            <field>
              <name>ID5</name>
              <bitOffset>5</bitOffset>
              <bitWidth>1</bitWidth>
            </field>
            <field>
              <name>ID6</name>
              <bitOffset>6</bitOffset>
              <bitWidth>1</bitWidth>
            </field>
            <field>
              <name>ID7</name>
              <bitOffset>7</bitOffset>
              <bitWidth>1</bitWidth>
            </field>
            <field>
              <name>ID8</name>
              <bitOffset>8</bitOffset>
              <bitWidth>1</bitWidth>
            </field>
            <field>
              <name>ID9</name>
              <bitOffset>9</bitOffset>
              <bitWidth>1</bitWidth>
            </field>
            <field>
              <name>ID10</name>
              <bitOffset>10</bitOffset>
              <bitWidth>1</bitWidth>
            </field>
            <field>
              <name>ID11</name>
              <bitOffset>11</bitOffset>
              <bitWidth>1</bitWidth>
            </field>
            <field>
              <name>ID12</name>
              <bitOffset>12</bitOffset>
              <bitWidth>1</bitWidth>
            </field>
            <field>
              <name>ID13</name>
              <bitOffset>13</bitOffset>
              <bitWidth>1</bitWidth>
            </field>
            <field>
              <name>ID14</name>
              <bitOffset>14</bitOffset>
              <bitWidth>1</bitWidth>
            </field>
            <field>
              <name>ID15</name>
              <bitOffset>15</bitOffset>
              <bitWidth>1</bitWidth>
            </field>
          </fields>
        </register>
        <register>
          <name>ODR</name>
          <addressOffset>0x14</addressOffset>
          <size>0x20</size>
          <fields>
            <field>
              <name>OD0</name>
              <bitOffset>0</bitOffset>
              <bitWidth>1</bitWidth>
            </field>
            <field>
              <name>OD1</name>
              <bitOffset>1</bitOffset>
              <bitWidth>1</bitWidth>
            </field>
            <field>
              <name>OD2</name>
              <bitOffset>2</bitOffset>
              <bitWidth>1</bitWidth>
            </field>
            <field>
              <name>OD3</name>
              <bitOffset>3</bitOffset>
              <bitWidth>1</bitWidth>
            </field>
            <field>
              <name>OD4</name>
              <bitOffset>4</bitOffset>
              <bitWidth>1</bitWidth>
            </field>
            <field>
              <name>OD5</name>
              <bitOffset>5</bitOffset>
              <bitWidth>1</bitWidth>
            </field>
            <field>
              <name>OD6</name>
              <bitOffset>6</bitOffset>
              <bitWidth>1</bitWidth>
            </field>
            <field>
              <name>OD7</name>
              <bitOffset>7</bitOffset>
              <bitWidth>1</bitWidth>
            </field>
            <field>
              <name>OD8</name>
              <bitOffset>8</bitOffset>
              <bitWidth>1</bitWidth>
            </field>
            <field>
              <name>OD9</name>
              <bitOffset>9</bitOffset>
              <bitWidth>1</bitWidth>
            </field>
            <field>
              <name>OD10</name>
              <bitOffset>10</bitOffset>
              <bitWidth>1</bitWidth>
            </field>
            <field>
              <name>OD11</name>
              <bitOffset>11</bitOffset>
              <bitWidth>1</bitWidth>
            </field>
            <field>
              <name>OD12</name>
              <bitOffset>12</bitOffset>
              <bitWidth>1</bitWidth>
            </field>
            <field>
              <name>OD13</name>
              <bitOffset>13</bitOffset>
              <bitWidth>1</bitWidth>
            </field>
            <field>
              <name>OD14</name>
              <bitOffset>14</bitOffset>
              <bitWidth>1</bitWidth>
            </field>
            <field>
              <name>OD15</name>
              <bitOffset>15</bitOffset>
              <bitWidth>1</bitWidth>
            </field>
          </fields>
        </register>
        <register>
          <name>BSRR</name>
          <addressOffset>0x18</addressOffset>
          <size>0x20</size>
          <fields>
            <field>
              <name>BS0</name>
              <bitOffset>0</bitOffset>
              <bitWidth>1</bitWidth>
            </field>
            <field>
              <name>BS1</name>
              <bitOffset>1</bitOffset>
              <bitWidth>1</bitWidth>
            </field>
            <field>
              <name>BS2</name>
              <bitOffset>2</bitOffset>
              <bitWidth>1</bitWidth>
            </field>
            <field>
              <name>BS3</name>
              <bitOffset>3</bitOffset>
              <bitWidth>1</bitWidth>
            </field>
            <field>
              <name>BS4</name>
              <bitOffset>4</bitOffset>
              <bitWidth>1</bitWidth>
            </field>
            <field>
              <name>BS5</name>
              <bitOffset>5</bitOffset>
              <bitWidth>1</bitWidth>
            </field>
            <field>
              <name>BS6</name>
              <bitOffset>6</bitOffset>
              <bitWidth>1</bitWidth>
            </field>
            <field>
              <name>BS7</name>
              <bitOffset>7</bitOffset>
              <bitWidth>1</bitWidth>
            </field>
            <field>
              <name>BS8</name>
              <bitOffset>8</bitOffset>
              <bitWidth>1</bitWidth>
            </field>
            <field>
              <name>BS9</name>
              <bitOffset>9</bitOffset>
              <bitWidth>1</bitWidth>
            </field>
            <field>
              <name>BS10</name>
              <bitOffset>10</bitOffset>
              <bitWidth>1</bitWidth>
            </field>
            <field>
              <name>BS11</name>
              <bitOffset>11</bitOffset>
              <bitWidth>1</bitWidth>
            </field>
            <field>
              <name>BS12</name>
              <bitOffset>12</bitOffset>
              <bitWidth>1</bitWidth>
            </field>
            <field>
              <name>BS13</name>
              <bitOffset>13</bitOffset>
              <bitWidth>1</bitWidth>
            </field>
            <field>
              <name>BS14</name>
              <bitOffset>14</bitOffset>
              <bitWidth>1</bitWidth>
            </field>
            <field>
              <name>BS15</name>
              <bitOffset>15</bitOffset>
              <bitWidth>1</bitWidth>
            </field>
            <field>
              <name>BR0</name>
              <bitOffset>16</bitOffset>
              <bitWidth>1</bitWidth>
            </field>
            <field>
              <name>BR1</name>
              <bitOffset>17</bitOffset>
              <bitWidth>1</bitWidth>
            </field>
            <field>
              <name>BR2</name>
              <bitOffset>18</bitOffset>
              <bitWidth>1</bitWidth>
            </field>
            <field>
              <name>BR3</name>
              <bitOffset>19</bitOffset>
              <bitWidth>1</bitWidth>
            </field>
            <field>
              <name>BR4</name>
              <bitOffset>20</bitOffset>
              <bitWidth>1</bitWidth>
            </field>
            <field>
              <name>BR5</name>
              <bitOffset>21</bitOffset>
              <bitWidth>1</bitWidth>
            </field>
            <field>
              <name>BR6</name>
              <bitOffset>22</bitOffset>
              <bitWidth>1</bitWidth>
            </field>
            <field>
              <name>BR7</name>
              <bitOffset>23</bitOffset>
              <bitWidth>1</bitWidth>
            </field>
            <field>
              <name>BR8</name>
              <bitOffset>24</bitOffset>
              <bitWidth>1</bitWidth>
            </field>
            <field>
              <name>BR9</name>
              <bitOffset>25</bitOffset>
              <bitWidth>1</bitWidth>
            </field>
            <field>
              <name>BR10</name>
              <bitOffset>26</bitOffset>
              <bitWidth>1</bitWidth>
            </field>
            <field>
              <name>BR11</name>
              <bitOffset>27</bitOffset>
              <bitWidth>1</bitWidth>
            </field>
            <field>
              <name>BR12</name>
              <bitOffset>28</bitOffset>
              <bitWidth>1</bitWidth>
            </field>
            <field>
              <name>BR13</name>
              <bitOffset>29</bitOffset>
              <bitWidth>1</bitWidth>
            </field>
            <field>
              <name>BR14</name>
              <bitOffset>30</bitOffset>
              <bitWidth>1</bitWidth>
            </field>
            <field>
              <name>BR15</name>
              <bitOffset>31</bitOffset>
              <bitWidth>1</bitWidth>
            </field>
          </fields>
        </register>
        <register>
          <name>LCKR</name>
          <addressOffset>0x1c</addressOffset>
          <size>0x20</size>
        </register>
        <register>
          <name>AFR.0</name>
          <addressOffset>0x20</addressOffset>
          <size>0x20</size>
        </register>
        <register>
          <name>AFR.1</name>
          <addressOffset>0x24</addressOffset>
          <size>0x20</size>
          <fields>
            <field>
              <name>AFSEL8</name>
              <bitOffset>0</bitOffset>
              <bitWidth>4</bitWidth>
            </field>
            <field>
              <name>AFSEL9</name>
              <bitOffset>4</bitOffset>
              <bitWidth>4</bitWidth>
            </field>
            <field>
              <name>AFSEL10</name>
              <bitOffset>8</bitOffset>
              <bitWidth>4</bitWidth>
            </field>
            <field>
              <name>AFSEL11</name>
              <bitOffset>12</bitOffset>
              <bitWidth>4</bitWidth>
            </field>
            <field>
              <name>AFSEL12</name>
              <bitOffset>16</bitOffset>
              <bitWidth>4</bitWidth>
            </field>
            <field>
              <name>AFSEL13</name>
              <bitOffset>20</bitOffset>
              <bitWidth>4</bitWidth>
            </field>
            <field>
              <name>AFSEL14</name>
              <bitOffset>24</bitOffset>
              <bitWidth>4</bitWidth>
            </field>
            <field>
              <name>AFSEL15</name>
              <bitOffset>28</bitOffset>
              <bitWidth>4</bitWidth>
            </field>
          </fields>
        </register>
      </registers>
    </peripheral>
    <peripheral>
      <name>GPIOF</name>
      <baseAddress>0x40021400</baseAddress>
      <registers>
        <register>
          <name>MODER</name>
          <addressOffset>0x0</addressOffset>
          <size>0x20</size>
          <fields>
            <field>
              <name>MODER0</name>
              <bitOffset>0</bitOffset>
              <bitWidth>2</bitWidth>
            </field>
            <field>
              <name>MODER1</name>
              <bitOffset>2</bitOffset>
              <bitWidth>2</bitWidth>
            </field>
            <field>
              <name>MODER2</name>
              <bitOffset>4</bitOffset>
              <bitWidth>2</bitWidth>
            </field>
            <field>
              <name>MODER3</name>
              <bitOffset>6</bitOffset>
              <bitWidth>2</bitWidth>
            </field>
            <field>
              <name>MODER4</name>
              <bitOffset>8</bitOffset>
              <bitWidth>2</bitWidth>
            </field>
            <field>
              <name>MODER5</name>
              <bitOffset>10</bitOffset>
              <bitWidth>2</bitWidth>
            </field>
            <field>
              <name>MODER6</name>
              <bitOffset>12</bitOffset>
              <bitWidth>2</bitWidth>
            </field>
            <field>
              <name>MODER7</name>
              <bitOffset>14</bitOffset>
              <bitWidth>2</bitWidth>
            </field>
            <field>
              <name>MODER8</name>
              <bitOffset>16</bitOffset>
              <bitWidth>2</bitWidth>
            </field>
            <field>
              <name>MODER9</name>
              <bitOffset>18</bitOffset>
              <bitWidth>2</bitWidth>
            </field>
            <field>
              <name>MODER10</name>
              <bitOffset>20</bitOffset>
              <bitWidth>2</bitWidth>
            </field>
            <field>
              <name>MODER11</name>
              <bitOffset>22</bitOffset>
              <bitWidth>2</bitWidth>
            </field>
            <field>
              <name>MODER12</name>
              <bitOffset>24</bitOffset>
              <bitWidth>2</bitWidth>
            </field>
            <field>
              <name>MODER13</name>
              <bitOffset>26</bitOffset>
              <bitWidth>2</bitWidth>
            </field>
            <field>
              <name>MODER14</name>
              <bitOffset>28</bitOffset>
              <bitWidth>2</bitWidth>
            </field>
            <field>
              <name>MODER15</name>
              <bitOffset>30</bitOffset>
              <bitWidth>2</bitWidth>
            </field>
          </fields>
        </register>
        <register>
          <name>OTYPER</name>
          <addressOffset>0x4</addressOffset>
          <size>0x20</size>
          <fields>
            <field>
              <name>OT0</name>
              <bitOffset>0</bitOffset>
              <bitWidth>1</bitWidth>
            </field>
            <field>
              <name>OT1</name>
              <bitOffset>1</bitOffset>
              <bitWidth>1</bitWidth>
            </field>
            <field>
              <name>OT2</name>
              <bitOffset>2</bitOffset>
              <bitWidth>1</bitWidth>
            </field>
            <field>
              <name>OT3</name>
              <bitOffset>3</bitOffset>
              <bitWidth>1</bitWidth>
            </field>
            <field>
              <name>OT4</name>
              <bitOffset>4</bitOffset>
              <bitWidth>1</bitWidth>
            </field>
            <field>
              <name>OT5</name>
              <bitOffset>5</bitOffset>
              <bitWidth>1</bitWidth>
            </field>
            <field>
              <name>OT6</name>
              <bitOffset>6</bitOffset>
              <bitWidth>1</bitWidth>
            </field>
            <field>
              <name>OT7</name>
              <bitOffset>7</bitOffset>
              <bitWidth>1</bitWidth>
            </field>
            <field>
              <name>OT8</name>
              <bitOffset>8</bitOffset>
              <bitWidth>1</bitWidth>
            </field>
            <field>
              <name>OT9</name>
              <bitOffset>9</bitOffset>
              <bitWidth>1</bitWidth>
            </field>
            <field>
              <name>OT10</name>
              <bitOffset>10</bitOffset>
              <bitWidth>1</bitWidth>
            </field>
            <field>
              <name>OT11</name>
              <bitOffset>11</bitOffset>
              <bitWidth>1</bitWidth>
            </field>
            <field>
              <name>OT12</name>
              <bitOffset>12</bitOffset>
              <bitWidth>1</bitWidth>
            </field>
            <field>
              <name>OT13</name>
              <bitOffset>13</bitOffset>
              <bitWidth>1</bitWidth>
            </field>
            <field>
              <name>OT14</name>
              <bitOffset>14</bitOffset>
              <bitWidth>1</bitWidth>
            </field>
            <field>
              <name>OT15</name>
              <bitOffset>15</bitOffset>
              <bitWidth>1</bitWidth>
            </field>
          </fields>
        </register>
        <register>
          <name>OSPEEDR</name>
          <addressOffset>0x8</addressOffset>
          <size>0x20</size>
          <fields>
            <field>
              <name>OSPEED0</name>
              <bitOffset>0</bitOffset>
              <bitWidth>2</bitWidth>
            </field>
            <field>
              <name>OSPEED1</name>
              <bitOffset>2</bitOffset>
              <bitWidth>2</bitWidth>
            </field>
            <field>
              <name>OSPEED2</name>
              <bitOffset>4</bitOffset>
              <bitWidth>2</bitWidth>
            </field>
            <field>
              <name>OSPEED3</name>
              <bitOffset>6</bitOffset>
              <bitWidth>2</bitWidth>
            </field>
            <field>
              <name>OSPEED4</name>
              <bitOffset>8</bitOffset>
              <bitWidth>2</bitWidth>
            </field>
            <field>
              <name>OSPEED5</name>
              <bitOffset>10</bitOffset>
              <bitWidth>2</bitWidth>
            </field>
            <field>
              <name>OSPEED6</name>
              <bitOffset>12</bitOffset>
              <bitWidth>2</bitWidth>
            </field>
            <field>
              <name>OSPEED7</name>
              <bitOffset>14</bitOffset>
              <bitWidth>2</bitWidth>
            </field>
            <field>
              <name>OSPEED8</name>
              <bitOffset>16</bitOffset>
              <bitWidth>2</bitWidth>
            </field>
            <field>
              <name>OSPEED9</name>
              <bitOffset>18</bitOffset>
              <bitWidth>2</bitWidth>
            </field>
            <field>
              <name>OSPEED10</name>
              <bitOffset>20</bitOffset>
              <bitWidth>2</bitWidth>
            </field>
            <field>
              <name>OSPEED11</name>
              <bitOffset>22</bitOffset>
              <bitWidth>2</bitWidth>
            </field>
            <field>
              <name>OSPEED12</name>
              <bitOffset>24</bitOffset>
              <bitWidth>2</bitWidth>
            </field>
            <field>
              <name>OSPEED13</name>
              <bitOffset>26</bitOffset>
              <bitWidth>2</bitWidth>
            </field>
            <field>
              <name>OSPEED14</name>
              <bitOffset>28</bitOffset>
              <bitWidth>2</bitWidth>
            </field>
            <field>
              <name>OSPEED15</name>
              <bitOffset>30</bitOffset>
              <bitWidth>2</bitWidth>
            </field>
          </fields>
        </register>
        <register>
          <name>PUPDR</name>
          <addressOffset>0xc</addressOffset>
          <size>0x20</size>
          <fields>
            <field>
              <name>PUPD0</name>
              <bitOffset>0</bitOffset>
              <bitWidth>2</bitWidth>
            </field>
            <field>
              <name>PUPD1</name>
              <bitOffset>2</bitOffset>
              <bitWidth>2</bitWidth>
            </field>
            <field>
              <name>PUPD2</name>
              <bitOffset>4</bitOffset>
              <bitWidth>2</bitWidth>
            </field>
            <field>
              <name>PUPD3</name>
              <bitOffset>6</bitOffset>
              <bitWidth>2</bitWidth>
            </field>
            <field>
              <name>PUPD4</name>
              <bitOffset>8</bitOffset>
              <bitWidth>2</bitWidth>
            </field>
            <field>
              <name>PUPD5</name>
              <bitOffset>10</bitOffset>
              <bitWidth>2</bitWidth>
            </field>
            <field>
              <name>PUPD6</name>
              <bitOffset>12</bitOffset>
              <bitWidth>2</bitWidth>
            </field>
            <field>
              <name>PUPD7</name>
              <bitOffset>14</bitOffset>
              <bitWidth>2</bitWidth>
            </field>
            <field>
              <name>PUPD8</name>
              <bitOffset>16</bitOffset>
              <bitWidth>2</bitWidth>
            </field>
            <field>
              <name>PUPD9</name>
              <bitOffset>18</bitOffset>
              <bitWidth>2</bitWidth>
            </field>
            <field>
              <name>PUPD10</name>
              <bitOffset>20</bitOffset>
              <bitWidth>2</bitWidth>
            </field>
            <field>
              <name>PUPD11</name>
              <bitOffset>22</bitOffset>
              <bitWidth>2</bitWidth>
            </field>
            <field>
              <name>PUPD12</name>
              <bitOffset>24</bitOffset>
              <bitWidth>2</bitWidth>
            </field>
            <field>
              <name>PUPD13</name>
              <bitOffset>26</bitOffset>
              <bitWidth>2</bitWidth>
            </field>
            <field>
              <name>PUPD14</name>
              <bitOffset>28</bitOffset>
              <bitWidth>2</bitWidth>
            </field>
            <field>
              <name>PUPD15</name>
              <bitOffset>30</bitOffset>
              <bitWidth>2</bitWidth>
            </field>
          </fields>
        </register>
        <register>
          <name>IDR</name>
          <addressOffset>0x10</addressOffset>
          <size>0x20</size>
          <fields>
            <field>
              <name>ID0</name>
              <bitOffset>0</bitOffset>
              <bitWidth>1</bitWidth>
            </field>
            <field>
              <name>ID1</name>
              <bitOffset>1</bitOffset>
              <bitWidth>1</bitWidth>
            </field>
            <field>
              <name>ID2</name>
              <bitOffset>2</bitOffset>
              <bitWidth>1</bitWidth>
            </field>
            <field>
              <name>ID3</name>
              <bitOffset>3</bitOffset>
              <bitWidth>1</bitWidth>
            </field>
            <field>
              <name>ID4</name>
              <bitOffset>4</bitOffset>
              <bitWidth>1</bitWidth>
            </field>
            <field>
              <name>ID5</name>
              <bitOffset>5</bitOffset>
              <bitWidth>1</bitWidth>
            </field>
            <field>
              <name>ID6</name>
              <bitOffset>6</bitOffset>
              <bitWidth>1</bitWidth>
            </field>
            <field>
              <name>ID7</name>
              <bitOffset>7</bitOffset>
              <bitWidth>1</bitWidth>
            </field>
            <field>
              <name>ID8</name>
              <bitOffset>8</bitOffset>
              <bitWidth>1</bitWidth>
            </field>
            <field>
              <name>ID9</name>
              <bitOffset>9</bitOffset>
              <bitWidth>1</bitWidth>
            </field>
            <field>
              <name>ID10</name>
              <bitOffset>10</bitOffset>
              <bitWidth>1</bitWidth>
            </field>
            <field>
              <name>ID11</name>
              <bitOffset>11</bitOffset>
              <bitWidth>1</bitWidth>
            </field>
            <field>
              <name>ID12</name>
              <bitOffset>12</bitOffset>
              <bitWidth>1</bitWidth>
            </field>
            <field>
              <name>ID13</name>
              <bitOffset>13</bitOffset>
              <bitWidth>1</bitWidth>
            </field>
            <field>
              <name>ID14</name>
              <bitOffset>14</bitOffset>
              <bitWidth>1</bitWidth>
            </field>
            <field>
              <name>ID15</name>
              <bitOffset>15</bitOffset>
              <bitWidth>1</bitWidth>
            </field>
          </fields>
        </register>
        <register>
          <name>ODR</name>
          <addressOffset>0x14</addressOffset>
          <size>0x20</size>
          <fields>
            <field>
              <name>OD0</name>
              <bitOffset>0</bitOffset>
              <bitWidth>1</bitWidth>
            </field>
            <field>
              <name>OD1</name>
              <bitOffset>1</bitOffset>
              <bitWidth>1</bitWidth>
            </field>
            <field>
              <name>OD2</name>
              <bitOffset>2</bitOffset>
              <bitWidth>1</bitWidth>
            </field>
            <field>
              <name>OD3</name>
              <bitOffset>3</bitOffset>
              <bitWidth>1</bitWidth>
            </field>
            <field>
              <name>OD4</name>
              <bitOffset>4</bitOffset>
              <bitWidth>1</bitWidth>
            </field>
            <field>
              <name>OD5</name>
              <bitOffset>5</bitOffset>
              <bitWidth>1</bitWidth>
            </field>
            <field>
              <name>OD6</name>
              <bitOffset>6</bitOffset>
              <bitWidth>1</bitWidth>
            </field>
            <field>
              <name>OD7</name>
              <bitOffset>7</bitOffset>
              <bitWidth>1</bitWidth>
            </field>
            <field>
              <name>OD8</name>
              <bitOffset>8</bitOffset>
              <bitWidth>1</bitWidth>
            </field>
            <field>
              <name>OD9</name>
              <bitOffset>9</bitOffset>
              <bitWidth>1</bitWidth>
            </field>
            <field>
              <name>OD10</name>
              <bitOffset>10</bitOffset>
              <bitWidth>1</bitWidth>
            </field>
            <field>
              <name>OD11</name>
              <bitOffset>11</bitOffset>
              <bitWidth>1</bitWidth>
            </field>
            <field>
              <name>OD12</name>
              <bitOffset>12</bitOffset>
              <bitWidth>1</bitWidth>
            </field>
            <field>
              <name>OD13</name>
              <bitOffset>13</bitOffset>
              <bitWidth>1</bitWidth>
            </field>
            <field>
              <name>OD14</name>
              <bitOffset>14</bitOffset>
              <bitWidth>1</bitWidth>
            </field>
            <field>
              <name>OD15</name>
              <bitOffset>15</bitOffset>
              <bitWidth>1</bitWidth>
            </field>
          </fields>
        </register>
        <register>
          <name>BSRR</name>
          <addressOffset>0x18</addressOffset>
          <size>0x20</size>
          <fields>
            <field>
              <name>BS0</name>
              <bitOffset>0</bitOffset>
              <bitWidth>1</bitWidth>
            </field>
            <field>
              <name>BS1</name>
              <bitOffset>1</bitOffset>
              <bitWidth>1</bitWidth>
            </field>
            <field>
              <name>BS2</name>
              <bitOffset>2</bitOffset>
              <bitWidth>1</bitWidth>
            </field>
            <field>
              <name>BS3</name>
              <bitOffset>3</bitOffset>
              <bitWidth>1</bitWidth>
            </field>
            <field>
              <name>BS4</name>
              <bitOffset>4</bitOffset>
              <bitWidth>1</bitWidth>
            </field>
            <field>
              <name>BS5</name>
              <bitOffset>5</bitOffset>
              <bitWidth>1</bitWidth>
            </field>
            <field>
              <name>BS6</name>
              <bitOffset>6</bitOffset>
              <bitWidth>1</bitWidth>
            </field>
            <field>
              <name>BS7</name>
              <bitOffset>7</bitOffset>
              <bitWidth>1</bitWidth>
            </field>
            <field>
              <name>BS8</name>
              <bitOffset>8</bitOffset>
              <bitWidth>1</bitWidth>
            </field>
            <field>
              <name>BS9</name>
              <bitOffset>9</bitOffset>
              <bitWidth>1</bitWidth>
            </field>
            <field>
              <name>BS10</name>
              <bitOffset>10</bitOffset>
              <bitWidth>1</bitWidth>
            </field>
            <field>
              <name>BS11</name>
              <bitOffset>11</bitOffset>
              <bitWidth>1</bitWidth>
            </field>
            <field>
              <name>BS12</name>
              <bitOffset>12</bitOffset>
              <bitWidth>1</bitWidth>
            </field>
            <field>
              <name>BS13</name>
              <bitOffset>13</bitOffset>
              <bitWidth>1</bitWidth>
            </field>
            <field>
              <name>BS14</name>
              <bitOffset>14</bitOffset>
              <bitWidth>1</bitWidth>
            </field>
            <field>
              <name>BS15</name>
              <bitOffset>15</bitOffset>
              <bitWidth>1</bitWidth>
            </field>
            <field>
              <name>BR0</name>
              <bitOffset>16</bitOffset>
              <bitWidth>1</bitWidth>
            </field>
            <field>
              <name>BR1</name>
              <bitOffset>17</bitOffset>
              <bitWidth>1</bitWidth>
            </field>
            <field>
              <name>BR2</name>
              <bitOffset>18</bitOffset>
              <bitWidth>1</bitWidth>
            </field>
            <field>
              <name>BR3</name>
              <bitOffset>19</bitOffset>
              <bitWidth>1</bitWidth>
            </field>
            <field>
              <name>BR4</name>
              <bitOffset>20</bitOffset>
              <bitWidth>1</bitWidth>
            </field>
            <field>
              <name>BR5</name>
              <bitOffset>21</bitOffset>
              <bitWidth>1</bitWidth>
            </field>
            <field>
              <name>BR6</name>
              <bitOffset>22</bitOffset>
              <bitWidth>1</bitWidth>
            </field>
            <field>
              <name>BR7</name>
              <bitOffset>23</bitOffset>
              <bitWidth>1</bitWidth>
            </field>
            <field>
              <name>BR8</name>
              <bitOffset>24</bitOffset>
              <bitWidth>1</bitWidth>
            </field>
            <field>
              <name>BR9</name>
              <bitOffset>25</bitOffset>
              <bitWidth>1</bitWidth>
            </field>
            <field>
              <name>BR10</name>
              <bitOffset>26</bitOffset>
              <bitWidth>1</bitWidth>
            </field>
            <field>
              <name>BR11</name>
              <bitOffset>27</bitOffset>
              <bitWidth>1</bitWidth>
            </field>
            <field>
              <name>BR12</name>
              <bitOffset>28</bitOffset>
              <bitWidth>1</bitWidth>
            </field>
            <field>
              <name>BR13</name>
              <bitOffset>29</bitOffset>
              <bitWidth>1</bitWidth>
            </field>
            <field>
              <name>BR14</name>
              <bitOffset>30</bitOffset>
              <bitWidth>1</bitWidth>
            </field>
            <field>
              <name>BR15</name>
              <bitOffset>31</bitOffset>
              <bitWidth>1</bitWidth>
            </field>
          </fields>
        </register>
        <register>
          <name>LCKR</name>
          <addressOffset>0x1c</addressOffset>
          <size>0x20</size>
        </register>
        <register>
          <name>AFR.0</name>
          <addressOffset>0x20</addressOffset>
          <size>0x20</size>
        </register>
        <register>
          <name>AFR.1</name>
          <addressOffset>0x24</addressOffset>
          <size>0x20</size>
          <fields>
            <field>
              <name>AFSEL8</name>
              <bitOffset>0</bitOffset>
              <bitWidth>4</bitWidth>
            </field>
            <field>
              <name>AFSEL9</name>
              <bitOffset>4</bitOffset>
              <bitWidth>4</bitWidth>
            </field>
            <field>
              <name>AFSEL10</name>
              <bitOffset>8</bitOffset>
              <bitWidth>4</bitWidth>
            </field>
            <field>
              <name>AFSEL11</name>
              <bitOffset>12</bitOffset>
              <bitWidth>4</bitWidth>
            </field>
            <field>
              <name>AFSEL12</name>
              <bitOffset>16</bitOffset>
              <bitWidth>4</bitWidth>
            </field>
            <field>
              <name>AFSEL13</name>
              <bitOffset>20</bitOffset>
              <bitWidth>4</bitWidth>
            </field>
            <field>
              <name>AFSEL14</name>
              <bitOffset>24</bitOffset>
              <bitWidth>4</bitWidth>
            </field>
            <field>
              <name>AFSEL15</name>
              <bitOffset>28</bitOffset>
              <bitWidth>4</bitWidth>
            </field>
          </fields>
        </register>
      </registers>
    </peripheral>
    <peripheral>
      <name>GPIOG</name>
      <baseAddress>0x40021800</baseAddress>
      <registers>
        <register>
          <name>MODER</name>
          <addressOffset>0x0</addressOffset>
          <size>0x20</size>
          <fields>
            <field>
              <name>MODER0</name>
              <bitOffset>0</bitOffset>
              <bitWidth>2</bitWidth>
            </field>
            <field>
              <name>MODER1</name>
              <bitOffset>2</bitOffset>
              <bitWidth>2</bitWidth>
            </field>
            <field>
              <name>MODER2</name>
              <bitOffset>4</bitOffset>
              <bitWidth>2</bitWidth>
            </field>
            <field>
              <name>MODER3</name>
              <bitOffset>6</bitOffset>
              <bitWidth>2</bitWidth>
            </field>
            <field>
              <name>MODER4</name>
              <bitOffset>8</bitOffset>
              <bitWidth>2</bitWidth>
            </field>
            <field>
              <name>MODER5</name>
              <bitOffset>10</bitOffset>
              <bitWidth>2</bitWidth>
            </field>
            <field>
              <name>MODER6</name>
              <bitOffset>12</bitOffset>
              <bitWidth>2</bitWidth>
            </field>
            <field>
              <name>MODER7</name>
              <bitOffset>14</bitOffset>
              <bitWidth>2</bitWidth>
            </field>
            <field>
              <name>MODER8</name>
              <bitOffset>16</bitOffset>
              <bitWidth>2</bitWidth>
            </field>
            <field>
              <name>MODER9</name>
              <bitOffset>18</bitOffset>
              <bitWidth>2</bitWidth>
            </field>
            <field>
              <name>MODER10</name>
              <bitOffset>20</bitOffset>
              <bitWidth>2</bitWidth>
            </field>
            <field>
              <name>MODER11</name>
              <bitOffset>22</bitOffset>
              <bitWidth>2</bitWidth>
            </field>
            <field>
              <name>MODER12</name>
              <bitOffset>24</bitOffset>
              <bitWidth>2</bitWidth>
            </field>
            <field>
              <name>MODER13</name>
              <bitOffset>26</bitOffset>
              <bitWidth>2</bitWidth>
            </field>
            <field>
              <name>MODER14</name>
              <bitOffset>28</bitOffset>
              <bitWidth>2</bitWidth>
            </field>
            <field>
              <name>MODER15</name>
              <bitOffset>30</bitOffset>
              <bitWidth>2</bitWidth>
            </field>
          </fields>
        </register>
        <register>
          <name>OTYPER</name>
          <addressOffset>0x4</addressOffset>
          <size>0x20</size>
          <fields>
            <field>
              <name>OT0</name>
              <bitOffset>0</bitOffset>
              <bitWidth>1</bitWidth>
            </field>
            <field>
              <name>OT1</name>
              <bitOffset>1</bitOffset>
              <bitWidth>1</bitWidth>
            </field>
            <field>
              <name>OT2</name>
              <bitOffset>2</bitOffset>
              <bitWidth>1</bitWidth>
            </field>
            <field>
              <name>OT3</name>
              <bitOffset>3</bitOffset>
              <bitWidth>1</bitWidth>
            </field>
            <field>
              <name>OT4</name>
              <bitOffset>4</bitOffset>
              <bitWidth>1</bitWidth>
            </field>
            <field>
              <name>OT5</name>
              <bitOffset>5</bitOffset>
              <bitWidth>1</bitWidth>
            </field>
            <field>
              <name>OT6</name>
              <bitOffset>6</bitOffset>
              <bitWidth>1</bitWidth>
            </field>
            <field>
              <name>OT7</name>
              <bitOffset>7</bitOffset>
              <bitWidth>1</bitWidth>
            </field>
            <field>
              <name>OT8</name>
              <bitOffset>8</bitOffset>
              <bitWidth>1</bitWidth>
            </field>
            <field>
              <name>OT9</name>
              <bitOffset>9</bitOffset>
              <bitWidth>1</bitWidth>
            </field>
            <field>
              <name>OT10</name>
              <bitOffset>10</bitOffset>
              <bitWidth>1</bitWidth>
            </field>
            <field>
              <name>OT11</name>
              <bitOffset>11</bitOffset>
              <bitWidth>1</bitWidth>
            </field>
            <field>
              <name>OT12</name>
              <bitOffset>12</bitOffset>
              <bitWidth>1</bitWidth>
            </field>
            <field>
              <name>OT13</name>
              <bitOffset>13</bitOffset>
              <bitWidth>1</bitWidth>
            </field>
            <field>
              <name>OT14</name>
              <bitOffset>14</bitOffset>
              <bitWidth>1</bitWidth>
            </field>
            <field>
              <name>OT15</name>
              <bitOffset>15</bitOffset>
              <bitWidth>1</bitWidth>
            </field>
          </fields>
        </register>
        <register>
          <name>OSPEEDR</name>
          <addressOffset>0x8</addressOffset>
          <size>0x20</size>
          <fields>
            <field>
              <name>OSPEED0</name>
              <bitOffset>0</bitOffset>
              <bitWidth>2</bitWidth>
            </field>
            <field>
              <name>OSPEED1</name>
              <bitOffset>2</bitOffset>
              <bitWidth>2</bitWidth>
            </field>
            <field>
              <name>OSPEED2</name>
              <bitOffset>4</bitOffset>
              <bitWidth>2</bitWidth>
            </field>
            <field>
              <name>OSPEED3</name>
              <bitOffset>6</bitOffset>
              <bitWidth>2</bitWidth>
            </field>
            <field>
              <name>OSPEED4</name>
              <bitOffset>8</bitOffset>
              <bitWidth>2</bitWidth>
            </field>
            <field>
              <name>OSPEED5</name>
              <bitOffset>10</bitOffset>
              <bitWidth>2</bitWidth>
            </field>
            <field>
              <name>OSPEED6</name>
              <bitOffset>12</bitOffset>
              <bitWidth>2</bitWidth>
            </field>
            <field>
              <name>OSPEED7</name>
              <bitOffset>14</bitOffset>
              <bitWidth>2</bitWidth>
            </field>
            <field>
              <name>OSPEED8</name>
              <bitOffset>16</bitOffset>
              <bitWidth>2</bitWidth>
            </field>
            <field>
              <name>OSPEED9</name>
              <bitOffset>18</bitOffset>
              <bitWidth>2</bitWidth>
            </field>
            <field>
              <name>OSPEED10</name>
              <bitOffset>20</bitOffset>
              <bitWidth>2</bitWidth>
            </field>
            <field>
              <name>OSPEED11</name>
              <bitOffset>22</bitOffset>
              <bitWidth>2</bitWidth>
            </field>
            <field>
              <name>OSPEED12</name>
              <bitOffset>24</bitOffset>
              <bitWidth>2</bitWidth>
            </field>
            <field>
              <name>OSPEED13</name>
              <bitOffset>26</bitOffset>
              <bitWidth>2</bitWidth>
            </field>
            <field>
              <name>OSPEED14</name>
              <bitOffset>28</bitOffset>
              <bitWidth>2</bitWidth>
            </field>
            <field>
              <name>OSPEED15</name>
              <bitOffset>30</bitOffset>
              <bitWidth>2</bitWidth>
            </field>
          </fields>
        </register>
        <register>
          <name>PUPDR</name>
          <addressOffset>0xc</addressOffset>
          <size>0x20</size>
          <fields>
            <field>
              <name>PUPD0</name>
              <bitOffset>0</bitOffset>
              <bitWidth>2</bitWidth>
            </field>
            <field>
              <name>PUPD1</name>
              <bitOffset>2</bitOffset>
              <bitWidth>2</bitWidth>
            </field>
            <field>
              <name>PUPD2</name>
              <bitOffset>4</bitOffset>
              <bitWidth>2</bitWidth>
            </field>
            <field>
              <name>PUPD3</name>
              <bitOffset>6</bitOffset>
              <bitWidth>2</bitWidth>
            </field>
            <field>
              <name>PUPD4</name>
              <bitOffset>8</bitOffset>
              <bitWidth>2</bitWidth>
            </field>
            <field>
              <name>PUPD5</name>
              <bitOffset>10</bitOffset>
              <bitWidth>2</bitWidth>
            </field>
            <field>
              <name>PUPD6</name>
              <bitOffset>12</bitOffset>
              <bitWidth>2</bitWidth>
            </field>
            <field>
              <name>PUPD7</name>
              <bitOffset>14</bitOffset>
              <bitWidth>2</bitWidth>
            </field>
            <field>
              <name>PUPD8</name>
              <bitOffset>16</bitOffset>
              <bitWidth>2</bitWidth>
            </field>
            <field>
              <name>PUPD9</name>
              <bitOffset>18</bitOffset>
              <bitWidth>2</bitWidth>
            </field>
            <field>
              <name>PUPD10</name>
              <bitOffset>20</bitOffset>
              <bitWidth>2</bitWidth>
            </field>
            <field>
              <name>PUPD11</name>
              <bitOffset>22</bitOffset>
              <bitWidth>2</bitWidth>
            </field>
            <field>
              <name>PUPD12</name>
              <bitOffset>24</bitOffset>
              <bitWidth>2</bitWidth>
            </field>
            <field>
              <name>PUPD13</name>
              <bitOffset>26</bitOffset>
              <bitWidth>2</bitWidth>
            </field>
            <field>
              <name>PUPD14</name>
              <bitOffset>28</bitOffset>
              <bitWidth>2</bitWidth>
            </field>
            <field>
              <name>PUPD15</name>
              <bitOffset>30</bitOffset>
              <bitWidth>2</bitWidth>
            </field>
          </fields>
        </register>
        <register>
          <name>IDR</name>
          <addressOffset>0x10</addressOffset>
          <size>0x20</size>
          <fields>
            <field>
              <name>ID0</name>
              <bitOffset>0</bitOffset>
              <bitWidth>1</bitWidth>
            </field>
            <field>
              <name>ID1</name>
              <bitOffset>1</bitOffset>
              <bitWidth>1</bitWidth>
            </field>
            <field>
              <name>ID2</name>
              <bitOffset>2</bitOffset>
              <bitWidth>1</bitWidth>
            </field>
            <field>
              <name>ID3</name>
              <bitOffset>3</bitOffset>
              <bitWidth>1</bitWidth>
            </field>
            <field>
              <name>ID4</name>
              <bitOffset>4</bitOffset>
              <bitWidth>1</bitWidth>
            </field>
            <field>
              <name>ID5</name>
              <bitOffset>5</bitOffset>
              <bitWidth>1</bitWidth>
            </field>
            <field>
              <name>ID6</name>
              <bitOffset>6</bitOffset>
              <bitWidth>1</bitWidth>
            </field>
            <field>
              <name>ID7</name>
              <bitOffset>7</bitOffset>
              <bitWidth>1</bitWidth>
            </field>
            <field>
              <name>ID8</name>
              <bitOffset>8</bitOffset>
              <bitWidth>1</bitWidth>
            </field>
            <field>
              <name>ID9</name>
              <bitOffset>9</bitOffset>
              <bitWidth>1</bitWidth>
            </field>
            <field>
              <name>ID10</name>
              <bitOffset>10</bitOffset>
              <bitWidth>1</bitWidth>
            </field>
            <field>
              <name>ID11</name>
              <bitOffset>11</bitOffset>
              <bitWidth>1</bitWidth>
            </field>
            <field>
              <name>ID12</name>
              <bitOffset>12</bitOffset>
              <bitWidth>1</bitWidth>
            </field>
            <field>
              <name>ID13</name>
              <bitOffset>13</bitOffset>
              <bitWidth>1</bitWidth>
            </field>
            <field>
              <name>ID14</name>
              <bitOffset>14</bitOffset>
              <bitWidth>1</bitWidth>
            </field>
            <field>
              <name>ID15</name>
              <bitOffset>15</bitOffset>
              <bitWidth>1</bitWidth>
            </field>
          </fields>
        </register>
        <register>
          <name>ODR</name>
          <addressOffset>0x14</addressOffset>
          <size>0x20</size>
          <fields>
            <field>
              <name>OD0</name>
              <bitOffset>0</bitOffset>
              <bitWidth>1</bitWidth>
            </field>
            <field>
              <name>OD1</name>
              <bitOffset>1</bitOffset>
              <bitWidth>1</bitWidth>
            </field>
            <field>
              <name>OD2</name>
              <bitOffset>2</bitOffset>
              <bitWidth>1</bitWidth>
            </field>
            <field>
              <name>OD3</name>
              <bitOffset>3</bitOffset>
              <bitWidth>1</bitWidth>
            </field>
            <field>
              <name>OD4</name>
              <bitOffset>4</bitOffset>
              <bitWidth>1</bitWidth>
            </field>
            <field>
              <name>OD5</name>
              <bitOffset>5</bitOffset>
              <bitWidth>1</bitWidth>
            </field>
            <field>
              <name>OD6</name>
              <bitOffset>6</bitOffset>
              <bitWidth>1</bitWidth>
            </field>
            <field>
              <name>OD7</name>
              <bitOffset>7</bitOffset>
              <bitWidth>1</bitWidth>
            </field>
            <field>
              <name>OD8</name>
              <bitOffset>8</bitOffset>
              <bitWidth>1</bitWidth>
            </field>
            <field>
              <name>OD9</name>
              <bitOffset>9</bitOffset>
              <bitWidth>1</bitWidth>
            </field>
            <field>
              <name>OD10</name>
              <bitOffset>10</bitOffset>
              <bitWidth>1</bitWidth>
            </field>
            <field>
              <name>OD11</name>
              <bitOffset>11</bitOffset>
              <bitWidth>1</bitWidth>
            </field>
            <field>
              <name>OD12</name>
              <bitOffset>12</bitOffset>
              <bitWidth>1</bitWidth>
            </field>
            <field>
              <name>OD13</name>
              <bitOffset>13</bitOffset>
              <bitWidth>1</bitWidth>
            </field>
            <field>
              <name>OD14</name>
              <bitOffset>14</bitOffset>
              <bitWidth>1</bitWidth>
            </field>
            <field>
              <name>OD15</name>
              <bitOffset>15</bitOffset>
              <bitWidth>1</bitWidth>
            </field>
          </fields>
        </register>
        <register>
          <name>BSRR</name>
          <addressOffset>0x18</addressOffset>
          <size>0x20</size>
          <fields>
            <field>
              <name>BS0</name>
              <bitOffset>0</bitOffset>
              <bitWidth>1</bitWidth>
            </field>
            <field>
              <name>BS1</name>
              <bitOffset>1</bitOffset>
              <bitWidth>1</bitWidth>
            </field>
            <field>
              <name>BS2</name>
              <bitOffset>2</bitOffset>
              <bitWidth>1</bitWidth>
            </field>
            <field>
              <name>BS3</name>
              <bitOffset>3</bitOffset>
              <bitWidth>1</bitWidth>
            </field>
            <field>
              <name>BS4</name>
              <bitOffset>4</bitOffset>
              <bitWidth>1</bitWidth>
            </field>
            <field>
              <name>BS5</name>
              <bitOffset>5</bitOffset>
              <bitWidth>1</bitWidth>
            </field>
            <field>
              <name>BS6</name>
              <bitOffset>6</bitOffset>
              <bitWidth>1</bitWidth>
            </field>
            <field>
              <name>BS7</name>
              <bitOffset>7</bitOffset>
              <bitWidth>1</bitWidth>
            </field>
            <field>
              <name>BS8</name>
              <bitOffset>8</bitOffset>
              <bitWidth>1</bitWidth>
            </field>
            <field>
              <name>BS9</name>
              <bitOffset>9</bitOffset>
              <bitWidth>1</bitWidth>
            </field>
            <field>
              <name>BS10</name>
              <bitOffset>10</bitOffset>
              <bitWidth>1</bitWidth>
            </field>
            <field>
              <name>BS11</name>
              <bitOffset>11</bitOffset>
              <bitWidth>1</bitWidth>
            </field>
            <field>
              <name>BS12</name>
              <bitOffset>12</bitOffset>
              <bitWidth>1</bitWidth>
            </field>
            <field>
              <name>BS13</name>
              <bitOffset>13</bitOffset>
              <bitWidth>1</bitWidth>
            </field>
            <field>
              <name>BS14</name>
              <bitOffset>14</bitOffset>
              <bitWidth>1</bitWidth>
            </field>
            <field>
              <name>BS15</name>
              <bitOffset>15</bitOffset>
              <bitWidth>1</bitWidth>
            </field>
            <field>
              <name>BR0</name>
              <bitOffset>16</bitOffset>
              <bitWidth>1</bitWidth>
            </field>
            <field>
              <name>BR1</name>
              <bitOffset>17</bitOffset>
              <bitWidth>1</bitWidth>
            </field>
            <field>
              <name>BR2</name>
              <bitOffset>18</bitOffset>
              <bitWidth>1</bitWidth>
            </field>
            <field>
              <name>BR3</name>
              <bitOffset>19</bitOffset>
              <bitWidth>1</bitWidth>
            </field>
            <field>
              <name>BR4</name>
              <bitOffset>20</bitOffset>
              <bitWidth>1</bitWidth>
            </field>
            <field>
              <name>BR5</name>
              <bitOffset>21</bitOffset>
              <bitWidth>1</bitWidth>
            </field>
            <field>
              <name>BR6</name>
              <bitOffset>22</bitOffset>
              <bitWidth>1</bitWidth>
            </field>
            <field>
              <name>BR7</name>
              <bitOffset>23</bitOffset>
              <bitWidth>1</bitWidth>
            </field>
            <field>
              <name>BR8</name>
              <bitOffset>24</bitOffset>
              <bitWidth>1</bitWidth>
            </field>
            <field>
              <name>BR9</name>
              <bitOffset>25</bitOffset>
              <bitWidth>1</bitWidth>
            </field>
            <field>
              <name>BR10</name>
              <bitOffset>26</bitOffset>
              <bitWidth>1</bitWidth>
            </field>
            <field>
              <name>BR11</name>
              <bitOffset>27</bitOffset>
              <bitWidth>1</bitWidth>
            </field>
            <field>
              <name>BR12</name>
              <bitOffset>28</bitOffset>
              <bitWidth>1</bitWidth>
            </field>
            <field>
              <name>BR13</name>
              <bitOffset>29</bitOffset>
              <bitWidth>1</bitWidth>
            </field>
            <field>
              <name>BR14</name>
              <bitOffset>30</bitOffset>
              <bitWidth>1</bitWidth>
            </field>
            <field>
              <name>BR15</name>
              <bitOffset>31</bitOffset>
              <bitWidth>1</bitWidth>
            </field>
          </fields>
        </register>
        <register>
          <name>LCKR</name>
          <addressOffset>0x1c</addressOffset>
          <size>0x20</size>
        </register>
        <register>
          <name>AFR.0</name>
          <addressOffset>0x20</addressOffset>
          <size>0x20</size>
        </register>
        <register>
          <name>AFR.1</name>
          <addressOffset>0x24</addressOffset>
          <size>0x20</size>
          <fields>
            <field>
              <name>AFSEL8</name>
              <bitOffset>0</bitOffset>
              <bitWidth>4</bitWidth>
            </field>
            <field>
              <name>AFSEL9</name>
              <bitOffset>4</bitOffset>
              <bitWidth>4</bitWidth>
            </field>
            <field>
              <name>AFSEL10</name>
              <bitOffset>8</bitOffset>
              <bitWidth>4</bitWidth>
            </field>
            <field>
              <name>AFSEL11</name>
              <bitOffset>12</bitOffset>
              <bitWidth>4</bitWidth>
            </field>
            <field>
              <name>AFSEL12</name>
              <bitOffset>16</bitOffset>
              <bitWidth>4</bitWidth>
            </field>
            <field>
              <name>AFSEL13</name>
              <bitOffset>20</bitOffset>
              <bitWidth>4</bitWidth>
            </field>
            <field>
              <name>AFSEL14</name>
              <bitOffset>24</bitOffset>
              <bitWidth>4</bitWidth>
            </field>
            <field>
              <name>AFSEL15</name>
              <bitOffset>28</bitOffset>
              <bitWidth>4</bitWidth>
            </field>
          </fields>
        </register>
      </registers>
    </peripheral>
    <peripheral>
      <name>GPIOH</name>
      <baseAddress>0x40021c00</baseAddress>
      <registers>
        <register>
          <name>MODER</name>
          <addressOffset>0x0</addressOffset>
          <size>0x20</size>
          <fields>
            <field>
              <name>MODER0</name>
              <bitOffset>0</bitOffset>
              <bitWidth>2</bitWidth>
            </field>
            <field>
              <name>MODER1</name>
              <bitOffset>2</bitOffset>
              <bitWidth>2</bitWidth>
            </field>
            <field>
              <name>MODER2</name>
              <bitOffset>4</bitOffset>
              <bitWidth>2</bitWidth>
            </field>
            <field>
              <name>MODER3</name>
              <bitOffset>6</bitOffset>
              <bitWidth>2</bitWidth>
            </field>
            <field>
              <name>MODER4</name>
              <bitOffset>8</bitOffset>
              <bitWidth>2</bitWidth>
            </field>
            <field>
              <name>MODER5</name>
              <bitOffset>10</bitOffset>
              <bitWidth>2</bitWidth>
            </field>
            <field>
              <name>MODER6</name>
              <bitOffset>12</bitOffset>
              <bitWidth>2</bitWidth>
            </field>
            <field>
              <name>MODER7</name>
              <bitOffset>14</bitOffset>
              <bitWidth>2</bitWidth>
            </field>
            <field>
              <name>MODER8</name>
              <bitOffset>16</bitOffset>
              <bitWidth>2</bitWidth>
            </field>
            <field>
              <name>MODER9</name>
              <bitOffset>18</bitOffset>
              <bitWidth>2</bitWidth>
            </field>
            <field>
              <name>MODER10</name>
              <bitOffset>20</bitOffset>
              <bitWidth>2</bitWidth>
            </field>
            <field>
              <name>MODER11</name>
              <bitOffset>22</bitOffset>
              <bitWidth>2</bitWidth>
            </field>
            <field>
              <name>MODER12</name>
              <bitOffset>24</bitOffset>
              <bitWidth>2</bitWidth>
            </field>
            <field>
              <name>MODER13</name>
              <bitOffset>26</bitOffset>
              <bitWidth>2</bitWidth>
            </field>
            <field>
              <name>MODER14</name>
              <bitOffset>28</bitOffset>
              <bitWidth>2</bitWidth>
            </field>
            <field>
              <name>MODER15</name>
              <bitOffset>30</bitOffset>
              <bitWidth>2</bitWidth>
            </field>
          </fields>
        </register>
        <register>
          <name>OTYPER</name>
          <addressOffset>0x4</addressOffset>
          <size>0x20</size>
          <fields>
            <field>
              <name>OT0</name>
              <bitOffset>0</bitOffset>
              <bitWidth>1</bitWidth>
            </field>
            <field>
              <name>OT1</name>
              <bitOffset>1</bitOffset>
              <bitWidth>1</bitWidth>
            </field>
            <field>
              <name>OT2</name>
              <bitOffset>2</bitOffset>
              <bitWidth>1</bitWidth>
            </field>
            <field>
              <name>OT3</name>
              <bitOffset>3</bitOffset>
              <bitWidth>1</bitWidth>
            </field>
            <field>
              <name>OT4</name>
              <bitOffset>4</bitOffset>
              <bitWidth>1</bitWidth>
            </field>
            <field>
              <name>OT5</name>
              <bitOffset>5</bitOffset>
              <bitWidth>1</bitWidth>
            </field>
            <field>
              <name>OT6</name>
              <bitOffset>6</bitOffset>
              <bitWidth>1</bitWidth>
            </field>
            <field>
              <name>OT7</name>
              <bitOffset>7</bitOffset>
              <bitWidth>1</bitWidth>
            </field>
            <field>
              <name>OT8</name>
              <bitOffset>8</bitOffset>
              <bitWidth>1</bitWidth>
            </field>
            <field>
              <name>OT9</name>
              <bitOffset>9</bitOffset>
              <bitWidth>1</bitWidth>
            </field>
            <field>
              <name>OT10</name>
              <bitOffset>10</bitOffset>
              <bitWidth>1</bitWidth>
            </field>
            <field>
              <name>OT11</name>
              <bitOffset>11</bitOffset>
              <bitWidth>1</bitWidth>
            </field>
            <field>
              <name>OT12</name>
              <bitOffset>12</bitOffset>
              <bitWidth>1</bitWidth>
            </field>
            <field>
              <name>OT13</name>
              <bitOffset>13</bitOffset>
              <bitWidth>1</bitWidth>
            </field>
            <field>
              <name>OT14</name>
              <bitOffset>14</bitOffset>
              <bitWidth>1</bitWidth>
            </field>
            <field>
              <name>OT15</name>
              <bitOffset>15</bitOffset>
              <bitWidth>1</bitWidth>
            </field>
          </fields>
        </register>
        <register>
          <name>OSPEEDR</name>
          <addressOffset>0x8</addressOffset>
          <size>0x20</size>
          <fields>
            <field>
              <name>OSPEED0</name>
              <bitOffset>0</bitOffset>
              <bitWidth>2</bitWidth>
            </field>
            <field>
              <name>OSPEED1</name>
              <bitOffset>2</bitOffset>
              <bitWidth>2</bitWidth>
            </field>
            <field>
              <name>OSPEED2</name>
              <bitOffset>4</bitOffset>
              <bitWidth>2</bitWidth>
            </field>
            <field>
              <name>OSPEED3</name>
              <bitOffset>6</bitOffset>
              <bitWidth>2</bitWidth>
            </field>
            <field>
              <name>OSPEED4</name>
              <bitOffset>8</bitOffset>
              <bitWidth>2</bitWidth>
            </field>
            <field>
              <name>OSPEED5</name>
              <bitOffset>10</bitOffset>
              <bitWidth>2</bitWidth>
            </field>
            <field>
              <name>OSPEED6</name>
              <bitOffset>12</bitOffset>
              <bitWidth>2</bitWidth>
            </field>
            <field>
              <name>OSPEED7</name>
              <bitOffset>14</bitOffset>
              <bitWidth>2</bitWidth>
            </field>
            <field>
              <name>OSPEED8</name>
              <bitOffset>16</bitOffset>
              <bitWidth>2</bitWidth>
            </field>
            <field>
              <name>OSPEED9</name>
              <bitOffset>18</bitOffset>
              <bitWidth>2</bitWidth>
            </field>
            <field>
              <name>OSPEED10</name>
              <bitOffset>20</bitOffset>
              <bitWidth>2</bitWidth>
            </field>
            <field>
              <name>OSPEED11</name>
              <bitOffset>22</bitOffset>
              <bitWidth>2</bitWidth>
            </field>
            <field>
              <name>OSPEED12</name>
              <bitOffset>24</bitOffset>
              <bitWidth>2</bitWidth>
            </field>
            <field>
              <name>OSPEED13</name>
              <bitOffset>26</bitOffset>
              <bitWidth>2</bitWidth>
            </field>
            <field>
              <name>OSPEED14</name>
              <bitOffset>28</bitOffset>
              <bitWidth>2</bitWidth>
            </field>
            <field>
              <name>OSPEED15</name>
              <bitOffset>30</bitOffset>
              <bitWidth>2</bitWidth>
            </field>
          </fields>
        </register>
        <register>
          <name>PUPDR</name>
          <addressOffset>0xc</addressOffset>
          <size>0x20</size>
          <fields>
            <field>
              <name>PUPD0</name>
              <bitOffset>0</bitOffset>
              <bitWidth>2</bitWidth>
            </field>
            <field>
              <name>PUPD1</name>
              <bitOffset>2</bitOffset>
              <bitWidth>2</bitWidth>
            </field>
            <field>
              <name>PUPD2</name>
              <bitOffset>4</bitOffset>
              <bitWidth>2</bitWidth>
            </field>
            <field>
              <name>PUPD3</name>
              <bitOffset>6</bitOffset>
              <bitWidth>2</bitWidth>
            </field>
            <field>
              <name>PUPD4</name>
              <bitOffset>8</bitOffset>
              <bitWidth>2</bitWidth>
            </field>
            <field>
              <name>PUPD5</name>
              <bitOffset>10</bitOffset>
              <bitWidth>2</bitWidth>
            </field>
            <field>
              <name>PUPD6</name>
              <bitOffset>12</bitOffset>
              <bitWidth>2</bitWidth>
            </field>
            <field>
              <name>PUPD7</name>
              <bitOffset>14</bitOffset>
              <bitWidth>2</bitWidth>
            </field>
            <field>
              <name>PUPD8</name>
              <bitOffset>16</bitOffset>
              <bitWidth>2</bitWidth>
            </field>
            <field>
              <name>PUPD9</name>
              <bitOffset>18</bitOffset>
              <bitWidth>2</bitWidth>
            </field>
            <field>
              <name>PUPD10</name>
              <bitOffset>20</bitOffset>
              <bitWidth>2</bitWidth>
            </field>
            <field>
              <name>PUPD11</name>
              <bitOffset>22</bitOffset>
              <bitWidth>2</bitWidth>
            </field>
            <field>
              <name>PUPD12</name>
              <bitOffset>24</bitOffset>
              <bitWidth>2</bitWidth>
            </field>
            <field>
              <name>PUPD13</name>
              <bitOffset>26</bitOffset>
              <bitWidth>2</bitWidth>
            </field>
            <field>
              <name>PUPD14</name>
              <bitOffset>28</bitOffset>
              <bitWidth>2</bitWidth>
            </field>
            <field>
              <name>PUPD15</name>
              <bitOffset>30</bitOffset>
              <bitWidth>2</bitWidth>
            </field>
          </fields>
        </register>
        <register>
          <name>IDR</name>
          <addressOffset>0x10</addressOffset>
          <size>0x20</size>
          <fields>
            <field>
              <name>ID0</name>
              <bitOffset>0</bitOffset>
              <bitWidth>1</bitWidth>
            </field>
            <field>
              <name>ID1</name>
              <bitOffset>1</bitOffset>
              <bitWidth>1</bitWidth>
            </field>
            <field>
              <name>ID2</name>
              <bitOffset>2</bitOffset>
              <bitWidth>1</bitWidth>
            </field>
            <field>
              <name>ID3</name>
              <bitOffset>3</bitOffset>
              <bitWidth>1</bitWidth>
            </field>
            <field>
              <name>ID4</name>
              <bitOffset>4</bitOffset>
              <bitWidth>1</bitWidth>
            </field>
            <field>
              <name>ID5</name>
              <bitOffset>5</bitOffset>
              <bitWidth>1</bitWidth>
            </field>
            <field>
              <name>ID6</name>
              <bitOffset>6</bitOffset>
              <bitWidth>1</bitWidth>
            </field>
            <field>
              <name>ID7</name>
              <bitOffset>7</bitOffset>
              <bitWidth>1</bitWidth>
            </field>
            <field>
              <name>ID8</name>
              <bitOffset>8</bitOffset>
              <bitWidth>1</bitWidth>
            </field>
            <field>
              <name>ID9</name>
              <bitOffset>9</bitOffset>
              <bitWidth>1</bitWidth>
            </field>
            <field>
              <name>ID10</name>
              <bitOffset>10</bitOffset>
              <bitWidth>1</bitWidth>
            </field>
            <field>
              <name>ID11</name>
              <bitOffset>11</bitOffset>
              <bitWidth>1</bitWidth>
            </field>
            <field>
              <name>ID12</name>
              <bitOffset>12</bitOffset>
              <bitWidth>1</bitWidth>
            </field>
            <field>
              <name>ID13</name>
              <bitOffset>13</bitOffset>
              <bitWidth>1</bitWidth>
            </field>
            <field>
              <name>ID14</name>
              <bitOffset>14</bitOffset>
              <bitWidth>1</bitWidth>
            </field>
            <field>
              <name>ID15</name>
              <bitOffset>15</bitOffset>
              <bitWidth>1</bitWidth>
            </field>
          </fields>
        </register>
        <register>
          <name>ODR</name>
          <addressOffset>0x14</addressOffset>
          <size>0x20</size>
          <fields>
            <field>
              <name>OD0</name>
              <bitOffset>0</bitOffset>
              <bitWidth>1</bitWidth>
            </field>
            <field>
              <name>OD1</name>
              <bitOffset>1</bitOffset>
              <bitWidth>1</bitWidth>
            </field>
            <field>
              <name>OD2</name>
              <bitOffset>2</bitOffset>
              <bitWidth>1</bitWidth>
            </field>
            <field>
              <name>OD3</name>
              <bitOffset>3</bitOffset>
              <bitWidth>1</bitWidth>
            </field>
            <field>
              <name>OD4</name>
              <bitOffset>4</bitOffset>
              <bitWidth>1</bitWidth>
            </field>
            <field>
              <name>OD5</name>
              <bitOffset>5</bitOffset>
              <bitWidth>1</bitWidth>
            </field>
            <field>
              <name>OD6</name>
              <bitOffset>6</bitOffset>
              <bitWidth>1</bitWidth>
            </field>
            <field>
              <name>OD7</name>
              <bitOffset>7</bitOffset>
              <bitWidth>1</bitWidth>
            </field>
            <field>
              <name>OD8</name>
              <bitOffset>8</bitOffset>
              <bitWidth>1</bitWidth>
            </field>
            <field>
              <name>OD9</name>
              <bitOffset>9</bitOffset>
              <bitWidth>1</bitWidth>
            </field>
            <field>
              <name>OD10</name>
              <bitOffset>10</bitOffset>
              <bitWidth>1</bitWidth>
            </field>
            <field>
              <name>OD11</name>
              <bitOffset>11</bitOffset>
              <bitWidth>1</bitWidth>
            </field>
            <field>
              <name>OD12</name>
              <bitOffset>12</bitOffset>
              <bitWidth>1</bitWidth>
            </field>
            <field>
              <name>OD13</name>
              <bitOffset>13</bitOffset>
              <bitWidth>1</bitWidth>
            </field>
            <field>
              <name>OD14</name>
              <bitOffset>14</bitOffset>
              <bitWidth>1</bitWidth>
            </field>
            <field>
              <name>OD15</name>
              <bitOffset>15</bitOffset>
              <bitWidth>1</bitWidth>
            </field>
          </fields>
        </register>
        <register>
          <name>BSRR</name>
          <addressOffset>0x18</addressOffset>
          <size>0x20</size>
          <fields>
            <field>
              <name>BS0</name>
              <bitOffset>0</bitOffset>
              <bitWidth>1</bitWidth>
            </field>
            <field>
              <name>BS1</name>
              <bitOffset>1</bitOffset>
              <bitWidth>1</bitWidth>
            </field>
            <field>
              <name>BS2</name>
              <bitOffset>2</bitOffset>
              <bitWidth>1</bitWidth>
            </field>
            <field>
              <name>BS3</name>
              <bitOffset>3</bitOffset>
              <bitWidth>1</bitWidth>
            </field>
            <field>
              <name>BS4</name>
              <bitOffset>4</bitOffset>
              <bitWidth>1</bitWidth>
            </field>
            <field>
              <name>BS5</name>
              <bitOffset>5</bitOffset>
              <bitWidth>1</bitWidth>
            </field>
            <field>
              <name>BS6</name>
              <bitOffset>6</bitOffset>
              <bitWidth>1</bitWidth>
            </field>
            <field>
              <name>BS7</name>
              <bitOffset>7</bitOffset>
              <bitWidth>1</bitWidth>
            </field>
            <field>
              <name>BS8</name>
              <bitOffset>8</bitOffset>
              <bitWidth>1</bitWidth>
            </field>
            <field>
              <name>BS9</name>
              <bitOffset>9</bitOffset>
              <bitWidth>1</bitWidth>
            </field>
            <field>
              <name>BS10</name>
              <bitOffset>10</bitOffset>
              <bitWidth>1</bitWidth>
            </field>
            <field>
              <name>BS11</name>
              <bitOffset>11</bitOffset>
              <bitWidth>1</bitWidth>
            </field>
            <field>
              <name>BS12</name>
              <bitOffset>12</bitOffset>
              <bitWidth>1</bitWidth>
            </field>
            <field>
              <name>BS13</name>
              <bitOffset>13</bitOffset>
              <bitWidth>1</bitWidth>
            </field>
            <field>
              <name>BS14</name>
              <bitOffset>14</bitOffset>
              <bitWidth>1</bitWidth>
            </field>
            <field>
              <name>BS15</name>
              <bitOffset>15</bitOffset>
              <bitWidth>1</bitWidth>
            </field>
            <field>
              <name>BR0</name>
              <bitOffset>16</bitOffset>
              <bitWidth>1</bitWidth>
            </field>
            <field>
              <name>BR1</name>
              <bitOffset>17</bitOffset>
              <bitWidth>1</bitWidth>
            </field>
            <field>
              <name>BR2</name>
              <bitOffset>18</bitOffset>
              <bitWidth>1</bitWidth>
            </field>
            <field>
              <name>BR3</name>
              <bitOffset>19</bitOffset>
              <bitWidth>1</bitWidth>
            </field>
            <field>
              <name>BR4</name>
              <bitOffset>20</bitOffset>
              <bitWidth>1</bitWidth>
            </field>
            <field>
              <name>BR5</name>
              <bitOffset>21</bitOffset>
              <bitWidth>1</bitWidth>
            </field>
            <field>
              <name>BR6</name>
              <bitOffset>22</bitOffset>
              <bitWidth>1</bitWidth>
            </field>
            <field>
              <name>BR7</name>
              <bitOffset>23</bitOffset>
              <bitWidth>1</bitWidth>
            </field>
            <field>
              <name>BR8</name>
              <bitOffset>24</bitOffset>
              <bitWidth>1</bitWidth>
            </field>
            <field>
              <name>BR9</name>
              <bitOffset>25</bitOffset>
              <bitWidth>1</bitWidth>
            </field>
            <field>
              <name>BR10</name>
              <bitOffset>26</bitOffset>
              <bitWidth>1</bitWidth>
            </field>
            <field>
              <name>BR11</name>
              <bitOffset>27</bitOffset>
              <bitWidth>1</bitWidth>
            </field>
            <field>
              <name>BR12</name>
              <bitOffset>28</bitOffset>
              <bitWidth>1</bitWidth>
            </field>
            <field>
              <name>BR13</name>
              <bitOffset>29</bitOffset>
              <bitWidth>1</bitWidth>
            </field>
            <field>
              <name>BR14</name>
              <bitOffset>30</bitOffset>
              <bitWidth>1</bitWidth>
            </field>
            <field>
              <name>BR15</name>
              <bitOffset>31</bitOffset>
              <bitWidth>1</bitWidth>
            </field>
          </fields>
        </register>
        <register>
          <name>LCKR</name>
          <addressOffset>0x1c</addressOffset>
          <size>0x20</size>
        </register>
        <register>
          <name>AFR.0</name>
          <addressOffset>0x20</addressOffset>
          <size>0x20</size>
        </register>
        <register>
          <name>AFR.1</name>
          <addressOffset>0x24</addressOffset>
          <size>0x20</size>
          <fields>
            <field>
              <name>AFSEL8</name>
              <bitOffset>0</bitOffset>
              <bitWidth>4</bitWidth>
            </field>
            <field>
              <name>AFSEL9</name>
              <bitOffset>4</bitOffset>
              <bitWidth>4</bitWidth>
            </field>
            <field>
              <name>AFSEL10</name>
              <bitOffset>8</bitOffset>
              <bitWidth>4</bitWidth>
            </field>
            <field>
              <name>AFSEL11</name>
              <bitOffset>12</bitOffset>
              <bitWidth>4</bitWidth>
            </field>
            <field>
              <name>AFSEL12</name>
              <bitOffset>16</bitOffset>
              <bitWidth>4</bitWidth>
            </field>
            <field>
              <name>AFSEL13</name>
              <bitOffset>20</bitOffset>
              <bitWidth>4</bitWidth>
            </field>
            <field>
              <name>AFSEL14</name>
              <bitOffset>24</bitOffset>
              <bitWidth>4</bitWidth>
            </field>
            <field>
              <name>AFSEL15</name>
              <bitOffset>28</bitOffset>
              <bitWidth>4</bitWidth>
            </field>
          </fields>
        </register>
      </registers>
    </peripheral>
    <peripheral>
      <name>GPIOI</name>
      <baseAddress>0x40022000</baseAddress>
      <registers>
        <register>
          <name>MODER</name>
          <addressOffset>0x0</addressOffset>
          <size>0x20</size>
          <fields>
            <field>
              <name>MODER0</name>
              <bitOffset>0</bitOffset>
              <bitWidth>2</bitWidth>
            </field>
            <field>
              <name>MODER1</name>
              <bitOffset>2</bitOffset>
              <bitWidth>2</bitWidth>
            </field>
            <field>
              <name>MODER2</name>
              <bitOffset>4</bitOffset>
              <bitWidth>2</bitWidth>
            </field>
            <field>
              <name>MODER3</name>
              <bitOffset>6</bitOffset>
              <bitWidth>2</bitWidth>
            </field>
            <field>
              <name>MODER4</name>
              <bitOffset>8</bitOffset>
              <bitWidth>2</bitWidth>
            </field>
            <field>
              <name>MODER5</name>
              <bitOffset>10</bitOffset>
              <bitWidth>2</bitWidth>
            </field>
            <field>
              <name>MODER6</name>
              <bitOffset>12</bitOffset>
              <bitWidth>2</bitWidth>
            </field>
            <field>
              <name>MODER7</name>
              <bitOffset>14</bitOffset>
              <bitWidth>2</bitWidth>
            </field>
            <field>
              <name>MODER8</name>
              <bitOffset>16</bitOffset>
              <bitWidth>2</bitWidth>
            </field>
            <field>
              <name>MODER9</name>
              <bitOffset>18</bitOffset>
              <bitWidth>2</bitWidth>
            </field>
            <field>
              <name>MODER10</name>
              <bitOffset>20</bitOffset>
              <bitWidth>2</bitWidth>
            </field>
            <field>
              <name>MODER11</name>
              <bitOffset>22</bitOffset>
              <bitWidth>2</bitWidth>
            </field>
            <field>
              <name>MODER12</name>
              <bitOffset>24</bitOffset>
              <bitWidth>2</bitWidth>
            </field>
            <field>
              <name>MODER13</name>
              <bitOffset>26</bitOffset>
              <bitWidth>2</bitWidth>
            </field>
            <field>
              <name>MODER14</name>
              <bitOffset>28</bitOffset>
              <bitWidth>2</bitWidth>
            </field>
            <field>
              <name>MODER15</name>
              <bitOffset>30</bitOffset>
              <bitWidth>2</bitWidth>
            </field>
          </fields>
        </register>
        <register>
          <name>OTYPER</name>
          <addressOffset>0x4</addressOffset>
          <size>0x20</size>
          <fields>
            <field>
              <name>OT0</name>
              <bitOffset>0</bitOffset>
              <bitWidth>1</bitWidth>
            </field>
            <field>
              <name>OT1</name>
              <bitOffset>1</bitOffset>
              <bitWidth>1</bitWidth>
            </field>
            <field>
              <name>OT2</name>
              <bitOffset>2</bitOffset>
              <bitWidth>1</bitWidth>
            </field>
            <field>
              <name>OT3</name>
              <bitOffset>3</bitOffset>
              <bitWidth>1</bitWidth>
            </field>
            <field>
              <name>OT4</name>
              <bitOffset>4</bitOffset>
              <bitWidth>1</bitWidth>
            </field>
            <field>
              <name>OT5</name>
              <bitOffset>5</bitOffset>
              <bitWidth>1</bitWidth>
            </field>
            <field>
              <name>OT6</name>
              <bitOffset>6</bitOffset>
              <bitWidth>1</bitWidth>
            </field>
            <field>
              <name>OT7</name>
              <bitOffset>7</bitOffset>
              <bitWidth>1</bitWidth>
            </field>
            <field>
              <name>OT8</name>
              <bitOffset>8</bitOffset>
              <bitWidth>1</bitWidth>
            </field>
            <field>
              <name>OT9</name>
              <bitOffset>9</bitOffset>
              <bitWidth>1</bitWidth>
            </field>
            <field>
              <name>OT10</name>
              <bitOffset>10</bitOffset>
              <bitWidth>1</bitWidth>
            </field>
            <field>
              <name>OT11</name>
              <bitOffset>11</bitOffset>
              <bitWidth>1</bitWidth>
            </field>
            <field>
              <name>OT12</name>
              <bitOffset>12</bitOffset>
              <bitWidth>1</bitWidth>
            </field>
            <field>
              <name>OT13</name>
              <bitOffset>13</bitOffset>
              <bitWidth>1</bitWidth>
            </field>
            <field>
              <name>OT14</name>
              <bitOffset>14</bitOffset>
              <bitWidth>1</bitWidth>
            </field>
            <field>
              <name>OT15</name>
              <bitOffset>15</bitOffset>
              <bitWidth>1</bitWidth>
            </field>
          </fields>
        </register>
        <register>
          <name>OSPEEDR</name>
          <addressOffset>0x8</addressOffset>
          <size>0x20</size>
          <fields>
            <field>
              <name>OSPEED0</name>
              <bitOffset>0</bitOffset>
              <bitWidth>2</bitWidth>
            </field>
            <field>
              <name>OSPEED1</name>
              <bitOffset>2</bitOffset>
              <bitWidth>2</bitWidth>
            </field>
            <field>
              <name>OSPEED2</name>
              <bitOffset>4</bitOffset>
              <bitWidth>2</bitWidth>
            </field>
            <field>
              <name>OSPEED3</name>
              <bitOffset>6</bitOffset>
              <bitWidth>2</bitWidth>
            </field>
            <field>
              <name>OSPEED4</name>
              <bitOffset>8</bitOffset>
              <bitWidth>2</bitWidth>
            </field>
            <field>
              <name>OSPEED5</name>
              <bitOffset>10</bitOffset>
              <bitWidth>2</bitWidth>
            </field>
            <field>
              <name>OSPEED6</name>
              <bitOffset>12</bitOffset>
              <bitWidth>2</bitWidth>
            </field>
            <field>
              <name>OSPEED7</name>
              <bitOffset>14</bitOffset>
              <bitWidth>2</bitWidth>
            </field>
            <field>
              <name>OSPEED8</name>
              <bitOffset>16</bitOffset>
              <bitWidth>2</bitWidth>
            </field>
            <field>
              <name>OSPEED9</name>
              <bitOffset>18</bitOffset>
              <bitWidth>2</bitWidth>
            </field>
            <field>
              <name>OSPEED10</name>
              <bitOffset>20</bitOffset>
              <bitWidth>2</bitWidth>
            </field>
            <field>
              <name>OSPEED11</name>
              <bitOffset>22</bitOffset>
              <bitWidth>2</bitWidth>
            </field>
            <field>
              <name>OSPEED12</name>
              <bitOffset>24</bitOffset>
              <bitWidth>2</bitWidth>
            </field>
            <field>
              <name>OSPEED13</name>
              <bitOffset>26</bitOffset>
              <bitWidth>2</bitWidth>
            </field>
            <field>
              <name>OSPEED14</name>
              <bitOffset>28</bitOffset>
              <bitWidth>2</bitWidth>
            </field>
            <field>
              <name>OSPEED15</name>
              <bitOffset>30</bitOffset>
              <bitWidth>2</bitWidth>
            </field>
          </fields>
        </register>
        <register>
          <name>PUPDR</name>
          <addressOffset>0xc</addressOffset>
          <size>0x20</size>
          <fields>
            <field>
              <name>PUPD0</name>
              <bitOffset>0</bitOffset>
              <bitWidth>2</bitWidth>
            </field>
            <field>
              <name>PUPD1</name>
              <bitOffset>2</bitOffset>
              <bitWidth>2</bitWidth>
            </field>
            <field>
              <name>PUPD2</name>
              <bitOffset>4</bitOffset>
              <bitWidth>2</bitWidth>
            </field>
            <field>
              <name>PUPD3</name>
              <bitOffset>6</bitOffset>
              <bitWidth>2</bitWidth>
            </field>
            <field>
              <name>PUPD4</name>
              <bitOffset>8</bitOffset>
              <bitWidth>2</bitWidth>
            </field>
            <field>
              <name>PUPD5</name>
              <bitOffset>10</bitOffset>
              <bitWidth>2</bitWidth>
            </field>
            <field>
              <name>PUPD6</name>
              <bitOffset>12</bitOffset>
              <bitWidth>2</bitWidth>
            </field>
            <field>
              <name>PUPD7</name>
              <bitOffset>14</bitOffset>
              <bitWidth>2</bitWidth>
            </field>
            <field>
              <name>PUPD8</name>
              <bitOffset>16</bitOffset>
              <bitWidth>2</bitWidth>
            </field>
            <field>
              <name>PUPD9</name>
              <bitOffset>18</bitOffset>
              <bitWidth>2</bitWidth>
            </field>
            <field>
              <name>PUPD10</name>
              <bitOffset>20</bitOffset>
              <bitWidth>2</bitWidth>
            </field>
            <field>
              <name>PUPD11</name>
              <bitOffset>22</bitOffset>
              <bitWidth>2</bitWidth>
            </field>
            <field>
              <name>PUPD12</name>
              <bitOffset>24</bitOffset>
              <bitWidth>2</bitWidth>
            </field>
            <field>
              <name>PUPD13</name>
              <bitOffset>26</bitOffset>
              <bitWidth>2</bitWidth>
            </field>
            <field>
              <name>PUPD14</name>
              <bitOffset>28</bitOffset>
              <bitWidth>2</bitWidth>
            </field>
            <field>
              <name>PUPD15</name>
              <bitOffset>30</bitOffset>
              <bitWidth>2</bitWidth>
            </field>
          </fields>
        </register>
        <register>
          <name>IDR</name>
          <addressOffset>0x10</addressOffset>
          <size>0x20</size>
          <fields>
            <field>
              <name>ID0</name>
              <bitOffset>0</bitOffset>
              <bitWidth>1</bitWidth>
            </field>
            <field>
              <name>ID1</name>
              <bitOffset>1</bitOffset>
              <bitWidth>1</bitWidth>
            </field>
            <field>
              <name>ID2</name>
              <bitOffset>2</bitOffset>
              <bitWidth>1</bitWidth>
            </field>
            <field>
              <name>ID3</name>
              <bitOffset>3</bitOffset>
              <bitWidth>1</bitWidth>
            </field>
            <field>
              <name>ID4</name>
              <bitOffset>4</bitOffset>
              <bitWidth>1</bitWidth>
            </field>
            <field>
              <name>ID5</name>
              <bitOffset>5</bitOffset>
              <bitWidth>1</bitWidth>
            </field>
            <field>
              <name>ID6</name>
              <bitOffset>6</bitOffset>
              <bitWidth>1</bitWidth>
            </field>
            <field>
              <name>ID7</name>
              <bitOffset>7</bitOffset>
              <bitWidth>1</bitWidth>
            </field>
            <field>
              <name>ID8</name>
              <bitOffset>8</bitOffset>
              <bitWidth>1</bitWidth>
            </field>
            <field>
              <name>ID9</name>
              <bitOffset>9</bitOffset>
              <bitWidth>1</bitWidth>
            </field>
            <field>
              <name>ID10</name>
              <bitOffset>10</bitOffset>
              <bitWidth>1</bitWidth>
            </field>
            <field>
              <name>ID11</name>
              <bitOffset>11</bitOffset>
              <bitWidth>1</bitWidth>
            </field>
            <field>
              <name>ID12</name>
              <bitOffset>12</bitOffset>
              <bitWidth>1</bitWidth>
            </field>
            <field>
              <name>ID13</name>
              <bitOffset>13</bitOffset>
              <bitWidth>1</bitWidth>
            </field>
            <field>
              <name>ID14</name>
              <bitOffset>14</bitOffset>
              <bitWidth>1</bitWidth>
            </field>
            <field>
              <name>ID15</name>
              <bitOffset>15</bitOffset>
              <bitWidth>1</bitWidth>
            </field>
          </fields>
        </register>
        <register>
          <name>ODR</name>
          <addressOffset>0x14</addressOffset>
          <size>0x20</size>
          <fields>
            <field>
              <name>OD0</name>
              <bitOffset>0</bitOffset>
              <bitWidth>1</bitWidth>
            </field>
            <field>
              <name>OD1</name>
              <bitOffset>1</bitOffset>
              <bitWidth>1</bitWidth>
            </field>
            <field>
              <name>OD2</name>
              <bitOffset>2</bitOffset>
              <bitWidth>1</bitWidth>
            </field>
            <field>
              <name>OD3</name>
              <bitOffset>3</bitOffset>
              <bitWidth>1</bitWidth>
            </field>
            <field>
              <name>OD4</name>
              <bitOffset>4</bitOffset>
              <bitWidth>1</bitWidth>
            </field>
            <field>
              <name>OD5</name>
              <bitOffset>5</bitOffset>
              <bitWidth>1</bitWidth>
            </field>
            <field>
              <name>OD6</name>
              <bitOffset>6</bitOffset>
              <bitWidth>1</bitWidth>
            </field>
            <field>
              <name>OD7</name>
              <bitOffset>7</bitOffset>
              <bitWidth>1</bitWidth>
            </field>
            <field>
              <name>OD8</name>
              <bitOffset>8</bitOffset>
              <bitWidth>1</bitWidth>
            </field>
            <field>
              <name>OD9</name>
              <bitOffset>9</bitOffset>
              <bitWidth>1</bitWidth>
            </field>
            <field>
              <name>OD10</name>
              <bitOffset>10</bitOffset>
              <bitWidth>1</bitWidth>
            </field>
            <field>
              <name>OD11</name>
              <bitOffset>11</bitOffset>
              <bitWidth>1</bitWidth>
            </field>
            <field>
              <name>OD12</name>
              <bitOffset>12</bitOffset>
              <bitWidth>1</bitWidth>
            </field>
            <field>
              <name>OD13</name>
              <bitOffset>13</bitOffset>
              <bitWidth>1</bitWidth>
            </field>
            <field>
              <name>OD14</name>
              <bitOffset>14</bitOffset>
              <bitWidth>1</bitWidth>
            </field>
            <field>
              <name>OD15</name>
              <bitOffset>15</bitOffset>
              <bitWidth>1</bitWidth>
            </field>
          </fields>
        </register>
        <register>
          <name>BSRR</name>
          <addressOffset>0x18</addressOffset>
          <size>0x20</size>
          <fields>
            <field>
              <name>BS0</name>
              <bitOffset>0</bitOffset>
              <bitWidth>1</bitWidth>
            </field>
            <field>
              <name>BS1</name>
              <bitOffset>1</bitOffset>
              <bitWidth>1</bitWidth>
            </field>
            <field>
              <name>BS2</name>
              <bitOffset>2</bitOffset>
              <bitWidth>1</bitWidth>
            </field>
            <field>
              <name>BS3</name>
              <bitOffset>3</bitOffset>
              <bitWidth>1</bitWidth>
            </field>
            <field>
              <name>BS4</name>
              <bitOffset>4</bitOffset>
              <bitWidth>1</bitWidth>
            </field>
            <field>
              <name>BS5</name>
              <bitOffset>5</bitOffset>
              <bitWidth>1</bitWidth>
            </field>
            <field>
              <name>BS6</name>
              <bitOffset>6</bitOffset>
              <bitWidth>1</bitWidth>
            </field>
            <field>
              <name>BS7</name>
              <bitOffset>7</bitOffset>
              <bitWidth>1</bitWidth>
            </field>
            <field>
              <name>BS8</name>
              <bitOffset>8</bitOffset>
              <bitWidth>1</bitWidth>
            </field>
            <field>
              <name>BS9</name>
              <bitOffset>9</bitOffset>
              <bitWidth>1</bitWidth>
            </field>
            <field>
              <name>BS10</name>
              <bitOffset>10</bitOffset>
              <bitWidth>1</bitWidth>
            </field>
            <field>
              <name>BS11</name>
              <bitOffset>11</bitOffset>
              <bitWidth>1</bitWidth>
            </field>
            <field>
              <name>BS12</name>
              <bitOffset>12</bitOffset>
              <bitWidth>1</bitWidth>
            </field>
            <field>
              <name>BS13</name>
              <bitOffset>13</bitOffset>
              <bitWidth>1</bitWidth>
            </field>
            <field>
              <name>BS14</name>
              <bitOffset>14</bitOffset>
              <bitWidth>1</bitWidth>
            </field>
            <field>
              <name>BS15</name>
              <bitOffset>15</bitOffset>
              <bitWidth>1</bitWidth>
            </field>
            <field>
              <name>BR0</name>
              <bitOffset>16</bitOffset>
              <bitWidth>1</bitWidth>
            </field>
            <field>
              <name>BR1</name>
              <bitOffset>17</bitOffset>
              <bitWidth>1</bitWidth>
            </field>
            <field>
              <name>BR2</name>
              <bitOffset>18</bitOffset>
              <bitWidth>1</bitWidth>
            </field>
            <field>
              <name>BR3</name>
              <bitOffset>19</bitOffset>
              <bitWidth>1</bitWidth>
            </field>
            <field>
              <name>BR4</name>
              <bitOffset>20</bitOffset>
              <bitWidth>1</bitWidth>
            </field>
            <field>
              <name>BR5</name>
              <bitOffset>21</bitOffset>
              <bitWidth>1</bitWidth>
            </field>
            <field>
              <name>BR6</name>
              <bitOffset>22</bitOffset>
              <bitWidth>1</bitWidth>
            </field>
            <field>
              <name>BR7</name>
              <bitOffset>23</bitOffset>
              <bitWidth>1</bitWidth>
            </field>
            <field>
              <name>BR8</name>
              <bitOffset>24</bitOffset>
              <bitWidth>1</bitWidth>
            </field>
            <field>
              <name>BR9</name>
              <bitOffset>25</bitOffset>
              <bitWidth>1</bitWidth>
            </field>
            <field>
              <name>BR10</name>
              <bitOffset>26</bitOffset>
              <bitWidth>1</bitWidth>
            </field>
            <field>
              <name>BR11</name>
              <bitOffset>27</bitOffset>
              <bitWidth>1</bitWidth>
            </field>
            <field>
              <name>BR12</name>
              <bitOffset>28</bitOffset>
              <bitWidth>1</bitWidth>
            </field>
            <field>
              <name>BR13</name>
              <bitOffset>29</bitOffset>
              <bitWidth>1</bitWidth>
            </field>
            <field>
              <name>BR14</name>
              <bitOffset>30</bitOffset>
              <bitWidth>1</bitWidth>
            </field>
            <field>
              <name>BR15</name>
              <bitOffset>31</bitOffset>
              <bitWidth>1</bitWidth>
            </field>
          </fields>
        </register>
        <register>
          <name>LCKR</name>
          <addressOffset>0x1c</addressOffset>
          <size>0x20</size>
        </register>
        <register>
          <name>AFR.0</name>
          <addressOffset>0x20</addressOffset>
          <size>0x20</size>
        </register>
        <register>
          <name>AFR.1</name>
          <addressOffset>0x24</addressOffset>
          <size>0x20</size>
          <fields>
            <field>
              <name>AFSEL8</name>
              <bitOffset>0</bitOffset>
              <bitWidth>4</bitWidth>
            </field>
            <field>
              <name>AFSEL9</name>
              <bitOffset>4</bitOffset>
              <bitWidth>4</bitWidth>
            </field>
            <field>
              <name>AFSEL10</name>
              <bitOffset>8</bitOffset>
              <bitWidth>4</bitWidth>
            </field>
            <field>
              <name>AFSEL11</name>
              <bitOffset>12</bitOffset>
              <bitWidth>4</bitWidth>
            </field>
            <field>
              <name>AFSEL12</name>
              <bitOffset>16</bitOffset>
              <bitWidth>4</bitWidth>
            </field>
            <field>
              <name>AFSEL13</name>
              <bitOffset>20</bitOffset>
              <bitWidth>4</bitWidth>
            </field>
            <field>
              <name>AFSEL14</name>
              <bitOffset>24</bitOffset>
              <bitWidth>4</bitWidth>
            </field>
            <field>
              <name>AFSEL15</name>
              <bitOffset>28</bitOffset>
              <bitWidth>4</bitWidth>
            </field>
          </fields>
        </register>
      </registers>
    </peripheral>
    <peripheral>
      <name>GPIOJ</name>
      <baseAddress>0x40022400</baseAddress>
      <registers>
        <register>
          <name>MODER</name>
          <addressOffset>0x0</addressOffset>
          <size>0x20</size>
          <fields>
            <field>
              <name>MODER0</name>
              <bitOffset>0</bitOffset>
              <bitWidth>2</bitWidth>
            </field>
            <field>
              <name>MODER1</name>
              <bitOffset>2</bitOffset>
              <bitWidth>2</bitWidth>
            </field>
            <field>
              <name>MODER2</name>
              <bitOffset>4</bitOffset>
              <bitWidth>2</bitWidth>
            </field>
            <field>
              <name>MODER3</name>
              <bitOffset>6</bitOffset>
              <bitWidth>2</bitWidth>
            </field>
            <field>
              <name>MODER4</name>
              <bitOffset>8</bitOffset>
              <bitWidth>2</bitWidth>
            </field>
            <field>
              <name>MODER5</name>
              <bitOffset>10</bitOffset>
              <bitWidth>2</bitWidth>
            </field>
            <field>
              <name>MODER6</name>
              <bitOffset>12</bitOffset>
              <bitWidth>2</bitWidth>
            </field>
            <field>
              <name>MODER7</name>
              <bitOffset>14</bitOffset>
              <bitWidth>2</bitWidth>
            </field>
            <field>
              <name>MODER8</name>
              <bitOffset>16</bitOffset>
              <bitWidth>2</bitWidth>
            </field>
            <field>
              <name>MODER9</name>
              <bitOffset>18</bitOffset>
              <bitWidth>2</bitWidth>
            </field>
            <field>
              <name>MODER10</name>
              <bitOffset>20</bitOffset>
              <bitWidth>2</bitWidth>
            </field>
            <field>
              <name>MODER11</name>
              <bitOffset>22</bitOffset>
              <bitWidth>2</bitWidth>
            </field>
            <field>
              <name>MODER12</name>
              <bitOffset>24</bitOffset>
              <bitWidth>2</bitWidth>
            </field>
            <field>
              <name>MODER13</name>
              <bitOffset>26</bitOffset>
              <bitWidth>2</bitWidth>
            </field>
            <field>
              <name>MODER14</name>
              <bitOffset>28</bitOffset>
              <bitWidth>2</bitWidth>
            </field>
            <field>
              <name>MODER15</name>
              <bitOffset>30</bitOffset>
              <bitWidth>2</bitWidth>
            </field>
          </fields>
        </register>
        <register>
          <name>OTYPER</name>
          <addressOffset>0x4</addressOffset>
          <size>0x20</size>
          <fields>
            <field>
              <name>OT0</name>
              <bitOffset>0</bitOffset>
              <bitWidth>1</bitWidth>
            </field>
            <field>
              <name>OT1</name>
              <bitOffset>1</bitOffset>
              <bitWidth>1</bitWidth>
            </field>
            <field>
              <name>OT2</name>
              <bitOffset>2</bitOffset>
              <bitWidth>1</bitWidth>
            </field>
            <field>
              <name>OT3</name>
              <bitOffset>3</bitOffset>
              <bitWidth>1</bitWidth>
            </field>
            <field>
              <name>OT4</name>
              <bitOffset>4</bitOffset>
              <bitWidth>1</bitWidth>
            </field>
            <field>
              <name>OT5</name>
              <bitOffset>5</bitOffset>
              <bitWidth>1</bitWidth>
            </field>
            <field>
              <name>OT6</name>
              <bitOffset>6</bitOffset>
              <bitWidth>1</bitWidth>
            </field>
            <field>
              <name>OT7</name>
              <bitOffset>7</bitOffset>
              <bitWidth>1</bitWidth>
            </field>
            <field>
              <name>OT8</name>
              <bitOffset>8</bitOffset>
              <bitWidth>1</bitWidth>
            </field>
            <field>
              <name>OT9</name>
              <bitOffset>9</bitOffset>
              <bitWidth>1</bitWidth>
            </field>
            <field>
              <name>OT10</name>
              <bitOffset>10</bitOffset>
              <bitWidth>1</bitWidth>
            </field>
            <field>
              <name>OT11</name>
              <bitOffset>11</bitOffset>
              <bitWidth>1</bitWidth>
            </field>
            <field>
              <name>OT12</name>
              <bitOffset>12</bitOffset>
              <bitWidth>1</bitWidth>
            </field>
            <field>
              <name>OT13</name>
              <bitOffset>13</bitOffset>
              <bitWidth>1</bitWidth>
            </field>
            <field>
              <name>OT14</name>
              <bitOffset>14</bitOffset>
              <bitWidth>1</bitWidth>
            </field>
            <field>
              <name>OT15</name>
              <bitOffset>15</bitOffset>
              <bitWidth>1</bitWidth>
            </field>
          </fields>
        </register>
        <register>
          <name>OSPEEDR</name>
          <addressOffset>0x8</addressOffset>
          <size>0x20</size>
          <fields>
            <field>
              <name>OSPEED0</name>
              <bitOffset>0</bitOffset>
              <bitWidth>2</bitWidth>
            </field>
            <field>
              <name>OSPEED1</name>
              <bitOffset>2</bitOffset>
              <bitWidth>2</bitWidth>
            </field>
            <field>
              <name>OSPEED2</name>
              <bitOffset>4</bitOffset>
              <bitWidth>2</bitWidth>
            </field>
            <field>
              <name>OSPEED3</name>
              <bitOffset>6</bitOffset>
              <bitWidth>2</bitWidth>
            </field>
            <field>
              <name>OSPEED4</name>
              <bitOffset>8</bitOffset>
              <bitWidth>2</bitWidth>
            </field>
            <field>
              <name>OSPEED5</name>
              <bitOffset>10</bitOffset>
              <bitWidth>2</bitWidth>
            </field>
            <field>
              <name>OSPEED6</name>
              <bitOffset>12</bitOffset>
              <bitWidth>2</bitWidth>
            </field>
            <field>
              <name>OSPEED7</name>
              <bitOffset>14</bitOffset>
              <bitWidth>2</bitWidth>
            </field>
            <field>
              <name>OSPEED8</name>
              <bitOffset>16</bitOffset>
              <bitWidth>2</bitWidth>
            </field>
            <field>
              <name>OSPEED9</name>
              <bitOffset>18</bitOffset>
              <bitWidth>2</bitWidth>
            </field>
            <field>
              <name>OSPEED10</name>
              <bitOffset>20</bitOffset>
              <bitWidth>2</bitWidth>
            </field>
            <field>
              <name>OSPEED11</name>
              <bitOffset>22</bitOffset>
              <bitWidth>2</bitWidth>
            </field>
            <field>
              <name>OSPEED12</name>
              <bitOffset>24</bitOffset>
              <bitWidth>2</bitWidth>
            </field>
            <field>
              <name>OSPEED13</name>
              <bitOffset>26</bitOffset>
              <bitWidth>2</bitWidth>
            </field>
            <field>
              <name>OSPEED14</name>
              <bitOffset>28</bitOffset>
              <bitWidth>2</bitWidth>
            </field>
            <field>
              <name>OSPEED15</name>
              <bitOffset>30</bitOffset>
              <bitWidth>2</bitWidth>
            </field>
          </fields>
        </register>
        <register>
          <name>PUPDR</name>
          <addressOffset>0xc</addressOffset>
          <size>0x20</size>
          <fields>
            <field>
              <name>PUPD0</name>
              <bitOffset>0</bitOffset>
              <bitWidth>2</bitWidth>
            </field>
            <field>
              <name>PUPD1</name>
              <bitOffset>2</bitOffset>
              <bitWidth>2</bitWidth>
            </field>
            <field>
              <name>PUPD2</name>
              <bitOffset>4</bitOffset>
              <bitWidth>2</bitWidth>
            </field>
            <field>
              <name>PUPD3</name>
              <bitOffset>6</bitOffset>
              <bitWidth>2</bitWidth>
            </field>
            <field>
              <name>PUPD4</name>
              <bitOffset>8</bitOffset>
              <bitWidth>2</bitWidth>
            </field>
            <field>
              <name>PUPD5</name>
              <bitOffset>10</bitOffset>
              <bitWidth>2</bitWidth>
            </field>
            <field>
              <name>PUPD6</name>
              <bitOffset>12</bitOffset>
              <bitWidth>2</bitWidth>
            </field>
            <field>
              <name>PUPD7</name>
              <bitOffset>14</bitOffset>
              <bitWidth>2</bitWidth>
            </field>
            <field>
              <name>PUPD8</name>
              <bitOffset>16</bitOffset>
              <bitWidth>2</bitWidth>
            </field>
            <field>
              <name>PUPD9</name>
              <bitOffset>18</bitOffset>
              <bitWidth>2</bitWidth>
            </field>
            <field>
              <name>PUPD10</name>
              <bitOffset>20</bitOffset>
              <bitWidth>2</bitWidth>
            </field>
            <field>
              <name>PUPD11</name>
              <bitOffset>22</bitOffset>
              <bitWidth>2</bitWidth>
            </field>
            <field>
              <name>PUPD12</name>
              <bitOffset>24</bitOffset>
              <bitWidth>2</bitWidth>
            </field>
            <field>
              <name>PUPD13</name>
              <bitOffset>26</bitOffset>
              <bitWidth>2</bitWidth>
            </field>
            <field>
              <name>PUPD14</name>
              <bitOffset>28</bitOffset>
              <bitWidth>2</bitWidth>
            </field>
            <field>
              <name>PUPD15</name>
              <bitOffset>30</bitOffset>
              <bitWidth>2</bitWidth>
            </field>
          </fields>
        </register>
        <register>
          <name>IDR</name>
          <addressOffset>0x10</addressOffset>
          <size>0x20</size>
          <fields>
            <field>
              <name>ID0</name>
              <bitOffset>0</bitOffset>
              <bitWidth>1</bitWidth>
            </field>
            <field>
              <name>ID1</name>
              <bitOffset>1</bitOffset>
              <bitWidth>1</bitWidth>
            </field>
            <field>
              <name>ID2</name>
              <bitOffset>2</bitOffset>
              <bitWidth>1</bitWidth>
            </field>
            <field>
              <name>ID3</name>
              <bitOffset>3</bitOffset>
              <bitWidth>1</bitWidth>
            </field>
            <field>
              <name>ID4</name>
              <bitOffset>4</bitOffset>
              <bitWidth>1</bitWidth>
            </field>
            <field>
              <name>ID5</name>
              <bitOffset>5</bitOffset>
              <bitWidth>1</bitWidth>
            </field>
            <field>
              <name>ID6</name>
              <bitOffset>6</bitOffset>
              <bitWidth>1</bitWidth>
            </field>
            <field>
              <name>ID7</name>
              <bitOffset>7</bitOffset>
              <bitWidth>1</bitWidth>
            </field>
            <field>
              <name>ID8</name>
              <bitOffset>8</bitOffset>
              <bitWidth>1</bitWidth>
            </field>
            <field>
              <name>ID9</name>
              <bitOffset>9</bitOffset>
              <bitWidth>1</bitWidth>
            </field>
            <field>
              <name>ID10</name>
              <bitOffset>10</bitOffset>
              <bitWidth>1</bitWidth>
            </field>
            <field>
              <name>ID11</name>
              <bitOffset>11</bitOffset>
              <bitWidth>1</bitWidth>
            </field>
            <field>
              <name>ID12</name>
              <bitOffset>12</bitOffset>
              <bitWidth>1</bitWidth>
            </field>
            <field>
              <name>ID13</name>
              <bitOffset>13</bitOffset>
              <bitWidth>1</bitWidth>
            </field>
            <field>
              <name>ID14</name>
              <bitOffset>14</bitOffset>
              <bitWidth>1</bitWidth>
            </field>
            <field>
              <name>ID15</name>
              <bitOffset>15</bitOffset>
              <bitWidth>1</bitWidth>
            </field>
          </fields>
        </register>
        <register>
          <name>ODR</name>
          <addressOffset>0x14</addressOffset>
          <size>0x20</size>
          <fields>
            <field>
              <name>OD0</name>
              <bitOffset>0</bitOffset>
              <bitWidth>1</bitWidth>
            </field>
            <field>
              <name>OD1</name>
              <bitOffset>1</bitOffset>
              <bitWidth>1</bitWidth>
            </field>
            <field>
              <name>OD2</name>
              <bitOffset>2</bitOffset>
              <bitWidth>1</bitWidth>
            </field>
            <field>
              <name>OD3</name>
              <bitOffset>3</bitOffset>
              <bitWidth>1</bitWidth>
            </field>
            <field>
              <name>OD4</name>
              <bitOffset>4</bitOffset>
              <bitWidth>1</bitWidth>
            </field>
            <field>
              <name>OD5</name>
              <bitOffset>5</bitOffset>
              <bitWidth>1</bitWidth>
            </field>
            <field>
              <name>OD6</name>
              <bitOffset>6</bitOffset>
              <bitWidth>1</bitWidth>
            </field>
            <field>
              <name>OD7</name>
              <bitOffset>7</bitOffset>
              <bitWidth>1</bitWidth>
            </field>
            <field>
              <name>OD8</name>
              <bitOffset>8</bitOffset>
              <bitWidth>1</bitWidth>
            </field>
            <field>
              <name>OD9</name>
              <bitOffset>9</bitOffset>
              <bitWidth>1</bitWidth>
            </field>
            <field>
              <name>OD10</name>
              <bitOffset>10</bitOffset>
              <bitWidth>1</bitWidth>
            </field>
            <field>
              <name>OD11</name>
              <bitOffset>11</bitOffset>
              <bitWidth>1</bitWidth>
            </field>
            <field>
              <name>OD12</name>
              <bitOffset>12</bitOffset>
              <bitWidth>1</bitWidth>
            </field>
            <field>
              <name>OD13</name>
              <bitOffset>13</bitOffset>
              <bitWidth>1</bitWidth>
            </field>
            <field>
              <name>OD14</name>
              <bitOffset>14</bitOffset>
              <bitWidth>1</bitWidth>
            </field>
            <field>
              <name>OD15</name>
              <bitOffset>15</bitOffset>
              <bitWidth>1</bitWidth>
            </field>
          </fields>
        </register>
        <register>
          <name>BSRR</name>
          <addressOffset>0x18</addressOffset>
          <size>0x20</size>
          <fields>
            <field>
              <name>BS0</name>
              <bitOffset>0</bitOffset>
              <bitWidth>1</bitWidth>
            </field>
            <field>
              <name>BS1</name>
              <bitOffset>1</bitOffset>
              <bitWidth>1</bitWidth>
            </field>
            <field>
              <name>BS2</name>
              <bitOffset>2</bitOffset>
              <bitWidth>1</bitWidth>
            </field>
            <field>
              <name>BS3</name>
              <bitOffset>3</bitOffset>
              <bitWidth>1</bitWidth>
            </field>
            <field>
              <name>BS4</name>
              <bitOffset>4</bitOffset>
              <bitWidth>1</bitWidth>
            </field>
            <field>
              <name>BS5</name>
              <bitOffset>5</bitOffset>
              <bitWidth>1</bitWidth>
            </field>
            <field>
              <name>BS6</name>
              <bitOffset>6</bitOffset>
              <bitWidth>1</bitWidth>
            </field>
            <field>
              <name>BS7</name>
              <bitOffset>7</bitOffset>
              <bitWidth>1</bitWidth>
            </field>
            <field>
              <name>BS8</name>
              <bitOffset>8</bitOffset>
              <bitWidth>1</bitWidth>
            </field>
            <field>
              <name>BS9</name>
              <bitOffset>9</bitOffset>
              <bitWidth>1</bitWidth>
            </field>
            <field>
              <name>BS10</name>
              <bitOffset>10</bitOffset>
              <bitWidth>1</bitWidth>
            </field>
            <field>
              <name>BS11</name>
              <bitOffset>11</bitOffset>
              <bitWidth>1</bitWidth>
            </field>
            <field>
              <name>BS12</name>
              <bitOffset>12</bitOffset>
              <bitWidth>1</bitWidth>
            </field>
            <field>
              <name>BS13</name>
              <bitOffset>13</bitOffset>
              <bitWidth>1</bitWidth>
            </field>
            <field>
              <name>BS14</name>
              <bitOffset>14</bitOffset>
              <bitWidth>1</bitWidth>
            </field>
            <field>
              <name>BS15</name>
              <bitOffset>15</bitOffset>
              <bitWidth>1</bitWidth>
            </field>
            <field>
              <name>BR0</name>
              <bitOffset>16</bitOffset>
              <bitWidth>1</bitWidth>
            </field>
            <field>
              <name>BR1</name>
              <bitOffset>17</bitOffset>
              <bitWidth>1</bitWidth>
            </field>
            <field>
              <name>BR2</name>
              <bitOffset>18</bitOffset>
              <bitWidth>1</bitWidth>
            </field>
            <field>
              <name>BR3</name>
              <bitOffset>19</bitOffset>
              <bitWidth>1</bitWidth>
            </field>
            <field>
              <name>BR4</name>
              <bitOffset>20</bitOffset>
              <bitWidth>1</bitWidth>
            </field>
            <field>
              <name>BR5</name>
              <bitOffset>21</bitOffset>
              <bitWidth>1</bitWidth>
            </field>
            <field>
              <name>BR6</name>
              <bitOffset>22</bitOffset>
              <bitWidth>1</bitWidth>
            </field>
            <field>
              <name>BR7</name>
              <bitOffset>23</bitOffset>
              <bitWidth>1</bitWidth>
            </field>
            <field>
              <name>BR8</name>
              <bitOffset>24</bitOffset>
              <bitWidth>1</bitWidth>
            </field>
            <field>
              <name>BR9</name>
              <bitOffset>25</bitOffset>
              <bitWidth>1</bitWidth>
            </field>
            <field>
              <name>BR10</name>
              <bitOffset>26</bitOffset>
              <bitWidth>1</bitWidth>
            </field>
            <field>
              <name>BR11</name>
              <bitOffset>27</bitOffset>
              <bitWidth>1</bitWidth>
            </field>
            <field>
              <name>BR12</name>
              <bitOffset>28</bitOffset>
              <bitWidth>1</bitWidth>
            </field>
            <field>
              <name>BR13</name>
              <bitOffset>29</bitOffset>
              <bitWidth>1</bitWidth>
            </field>
            <field>
              <name>BR14</name>
              <bitOffset>30</bitOffset>
              <bitWidth>1</bitWidth>
            </field>
            <field>
              <name>BR15</name>
              <bitOffset>31</bitOffset>
              <bitWidth>1</bitWidth>
            </field>
          </fields>
        </register>
        <register>
          <name>LCKR</name>
          <addressOffset>0x1c</addressOffset>
          <size>0x20</size>
        </register>
        <register>
          <name>AFR.0</name>
          <addressOffset>0x20</addressOffset>
          <size>0x20</size>
        </register>
        <register>
          <name>AFR.1</name>
          <addressOffset>0x24</addressOffset>
          <size>0x20</size>
          <fields>
            <field>
              <name>AFSEL8</name>
              <bitOffset>0</bitOffset>
              <bitWidth>4</bitWidth>
            </field>
            <field>
              <name>AFSEL9</name>
              <bitOffset>4</bitOffset>
              <bitWidth>4</bitWidth>
            </field>
            <field>
              <name>AFSEL10</name>
              <bitOffset>8</bitOffset>
              <bitWidth>4</bitWidth>
            </field>
            <field>
              <name>AFSEL11</name>
              <bitOffset>12</bitOffset>
              <bitWidth>4</bitWidth>
            </field>
            <field>
              <name>AFSEL12</name>
              <bitOffset>16</bitOffset>
              <bitWidth>4</bitWidth>
            </field>
            <field>
              <name>AFSEL13</name>
              <bitOffset>20</bitOffset>
              <bitWidth>4</bitWidth>
            </field>
            <field>
              <name>AFSEL14</name>
              <bitOffset>24</bitOffset>
              <bitWidth>4</bitWidth>
            </field>
            <field>
              <name>AFSEL15</name>
              <bitOffset>28</bitOffset>
              <bitWidth>4</bitWidth>
            </field>
          </fields>
        </register>
      </registers>
    </peripheral>
    <peripheral>
      <name>GPIOK</name>
      <baseAddress>0x40022800</baseAddress>
      <registers>
        <register>
          <name>MODER</name>
          <addressOffset>0x0</addressOffset>
          <size>0x20</size>
          <fields>
            <field>
              <name>MODER0</name>
              <bitOffset>0</bitOffset>
              <bitWidth>2</bitWidth>
            </field>
            <field>
              <name>MODER1</name>
              <bitOffset>2</bitOffset>
              <bitWidth>2</bitWidth>
            </field>
            <field>
              <name>MODER2</name>
              <bitOffset>4</bitOffset>
              <bitWidth>2</bitWidth>
            </field>
            <field>
              <name>MODER3</name>
              <bitOffset>6</bitOffset>
              <bitWidth>2</bitWidth>
            </field>
            <field>
              <name>MODER4</name>
              <bitOffset>8</bitOffset>
              <bitWidth>2</bitWidth>
            </field>
            <field>
              <name>MODER5</name>
              <bitOffset>10</bitOffset>
              <bitWidth>2</bitWidth>
            </field>
            <field>
              <name>MODER6</name>
              <bitOffset>12</bitOffset>
              <bitWidth>2</bitWidth>
            </field>
            <field>
              <name>MODER7</name>
              <bitOffset>14</bitOffset>
              <bitWidth>2</bitWidth>
            </field>
            <field>
              <name>MODER8</name>
              <bitOffset>16</bitOffset>
              <bitWidth>2</bitWidth>
            </field>
            <field>
              <name>MODER9</name>
              <bitOffset>18</bitOffset>
              <bitWidth>2</bitWidth>
            </field>
            <field>
              <name>MODER10</name>
              <bitOffset>20</bitOffset>
              <bitWidth>2</bitWidth>
            </field>
            <field>
              <name>MODER11</name>
              <bitOffset>22</bitOffset>
              <bitWidth>2</bitWidth>
            </field>
            <field>
              <name>MODER12</name>
              <bitOffset>24</bitOffset>
              <bitWidth>2</bitWidth>
            </field>
            <field>
              <name>MODER13</name>
              <bitOffset>26</bitOffset>
              <bitWidth>2</bitWidth>
            </field>
            <field>
              <name>MODER14</name>
              <bitOffset>28</bitOffset>
              <bitWidth>2</bitWidth>
            </field>
            <field>
              <name>MODER15</name>
              <bitOffset>30</bitOffset>
              <bitWidth>2</bitWidth>
            </field>
          </fields>
        </register>
        <register>
          <name>OTYPER</name>
          <addressOffset>0x4</addressOffset>
          <size>0x20</size>
          <fields>
            <field>
              <name>OT0</name>
              <bitOffset>0</bitOffset>
              <bitWidth>1</bitWidth>
            </field>
            <field>
              <name>OT1</name>
              <bitOffset>1</bitOffset>
              <bitWidth>1</bitWidth>
            </field>
            <field>
              <name>OT2</name>
              <bitOffset>2</bitOffset>
              <bitWidth>1</bitWidth>
            </field>
            <field>
              <name>OT3</name>
              <bitOffset>3</bitOffset>
              <bitWidth>1</bitWidth>
            </field>
            <field>
              <name>OT4</name>
              <bitOffset>4</bitOffset>
              <bitWidth>1</bitWidth>
            </field>
            <field>
              <name>OT5</name>
              <bitOffset>5</bitOffset>
              <bitWidth>1</bitWidth>
            </field>
            <field>
              <name>OT6</name>
              <bitOffset>6</bitOffset>
              <bitWidth>1</bitWidth>
            </field>
            <field>
              <name>OT7</name>
              <bitOffset>7</bitOffset>
              <bitWidth>1</bitWidth>
            </field>
            <field>
              <name>OT8</name>
              <bitOffset>8</bitOffset>
              <bitWidth>1</bitWidth>
            </field>
            <field>
              <name>OT9</name>
              <bitOffset>9</bitOffset>
              <bitWidth>1</bitWidth>
            </field>
            <field>
              <name>OT10</name>
              <bitOffset>10</bitOffset>
              <bitWidth>1</bitWidth>
            </field>
            <field>
              <name>OT11</name>
              <bitOffset>11</bitOffset>
              <bitWidth>1</bitWidth>
            </field>
            <field>
              <name>OT12</name>
              <bitOffset>12</bitOffset>
              <bitWidth>1</bitWidth>
            </field>
            <field>
              <name>OT13</name>
              <bitOffset>13</bitOffset>
              <bitWidth>1</bitWidth>
            </field>
            <field>
              <name>OT14</name>
              <bitOffset>14</bitOffset>
              <bitWidth>1</bitWidth>
            </field>
            <field>
              <name>OT15</name>
              <bitOffset>15</bitOffset>
              <bitWidth>1</bitWidth>
            </field>
          </fields>
        </register>
        <register>
          <name>OSPEEDR</name>
          <addressOffset>0x8</addressOffset>
          <size>0x20</size>
          <fields>
            <field>
              <name>OSPEED0</name>
              <bitOffset>0</bitOffset>
              <bitWidth>2</bitWidth>
            </field>
            <field>
              <name>OSPEED1</name>
              <bitOffset>2</bitOffset>
              <bitWidth>2</bitWidth>
            </field>
            <field>
              <name>OSPEED2</name>
              <bitOffset>4</bitOffset>
              <bitWidth>2</bitWidth>
            </field>
            <field>
              <name>OSPEED3</name>
              <bitOffset>6</bitOffset>
              <bitWidth>2</bitWidth>
            </field>
            <field>
              <name>OSPEED4</name>
              <bitOffset>8</bitOffset>
              <bitWidth>2</bitWidth>
            </field>
            <field>
              <name>OSPEED5</name>
              <bitOffset>10</bitOffset>
              <bitWidth>2</bitWidth>
            </field>
            <field>
              <name>OSPEED6</name>
              <bitOffset>12</bitOffset>
              <bitWidth>2</bitWidth>
            </field>
            <field>
              <name>OSPEED7</name>
              <bitOffset>14</bitOffset>
              <bitWidth>2</bitWidth>
            </field>
            <field>
              <name>OSPEED8</name>
              <bitOffset>16</bitOffset>
              <bitWidth>2</bitWidth>
            </field>
            <field>
              <name>OSPEED9</name>
              <bitOffset>18</bitOffset>
              <bitWidth>2</bitWidth>
            </field>
            <field>
              <name>OSPEED10</name>
              <bitOffset>20</bitOffset>
              <bitWidth>2</bitWidth>
            </field>
            <field>
              <name>OSPEED11</name>
              <bitOffset>22</bitOffset>
              <bitWidth>2</bitWidth>
            </field>
            <field>
              <name>OSPEED12</name>
              <bitOffset>24</bitOffset>
              <bitWidth>2</bitWidth>
            </field>
            <field>
              <name>OSPEED13</name>
              <bitOffset>26</bitOffset>
              <bitWidth>2</bitWidth>
            </field>
            <field>
              <name>OSPEED14</name>
              <bitOffset>28</bitOffset>
              <bitWidth>2</bitWidth>
            </field>
            <field>
              <name>OSPEED15</name>
              <bitOffset>30</bitOffset>
              <bitWidth>2</bitWidth>
            </field>
          </fields>
        </register>
        <register>
          <name>PUPDR</name>
          <addressOffset>0xc</addressOffset>
          <size>0x20</size>
          <fields>
            <field>
              <name>PUPD0</name>
              <bitOffset>0</bitOffset>
              <bitWidth>2</bitWidth>
            </field>
            <field>
              <name>PUPD1</name>
              <bitOffset>2</bitOffset>
              <bitWidth>2</bitWidth>
            </field>
            <field>
              <name>PUPD2</name>
              <bitOffset>4</bitOffset>
              <bitWidth>2</bitWidth>
            </field>
            <field>
              <name>PUPD3</name>
              <bitOffset>6</bitOffset>
              <bitWidth>2</bitWidth>
            </field>
            <field>
              <name>PUPD4</name>
              <bitOffset>8</bitOffset>
              <bitWidth>2</bitWidth>
            </field>
            <field>
              <name>PUPD5</name>
              <bitOffset>10</bitOffset>
              <bitWidth>2</bitWidth>
            </field>
            <field>
              <name>PUPD6</name>
              <bitOffset>12</bitOffset>
              <bitWidth>2</bitWidth>
            </field>
            <field>
              <name>PUPD7</name>
              <bitOffset>14</bitOffset>
              <bitWidth>2</bitWidth>
            </field>
            <field>
              <name>PUPD8</name>
              <bitOffset>16</bitOffset>
              <bitWidth>2</bitWidth>
            </field>
            <field>
              <name>PUPD9</name>
              <bitOffset>18</bitOffset>
              <bitWidth>2</bitWidth>
            </field>
            <field>
              <name>PUPD10</name>
              <bitOffset>20</bitOffset>
              <bitWidth>2</bitWidth>
            </field>
            <field>
              <name>PUPD11</name>
              <bitOffset>22</bitOffset>
              <bitWidth>2</bitWidth>
            </field>
            <field>
              <name>PUPD12</name>
              <bitOffset>24</bitOffset>
              <bitWidth>2</bitWidth>
            </field>
            <field>
              <name>PUPD13</name>
              <bitOffset>26</bitOffset>
              <bitWidth>2</bitWidth>
            </field>
            <field>
              <name>PUPD14</name>
              <bitOffset>28</bitOffset>
              <bitWidth>2</bitWidth>
            </field>
            <field>
              <name>PUPD15</name>
              <bitOffset>30</bitOffset>
              <bitWidth>2</bitWidth>
            </field>
          </fields>
        </register>
        <register>
          <name>IDR</name>
          <addressOffset>0x10</addressOffset>
          <size>0x20</size>
          <fields>
            <field>
              <name>ID0</name>
              <bitOffset>0</bitOffset>
              <bitWidth>1</bitWidth>
            </field>
            <field>
              <name>ID1</name>
              <bitOffset>1</bitOffset>
              <bitWidth>1</bitWidth>
            </field>
            <field>
              <name>ID2</name>
              <bitOffset>2</bitOffset>
              <bitWidth>1</bitWidth>
            </field>
            <field>
              <name>ID3</name>
              <bitOffset>3</bitOffset>
              <bitWidth>1</bitWidth>
            </field>
            <field>
              <name>ID4</name>
              <bitOffset>4</bitOffset>
              <bitWidth>1</bitWidth>
            </field>
            <field>
              <name>ID5</name>
              <bitOffset>5</bitOffset>
              <bitWidth>1</bitWidth>
            </field>
            <field>
              <name>ID6</name>
              <bitOffset>6</bitOffset>
              <bitWidth>1</bitWidth>
            </field>
            <field>
              <name>ID7</name>
              <bitOffset>7</bitOffset>
              <bitWidth>1</bitWidth>
            </field>
            <field>
              <name>ID8</name>
              <bitOffset>8</bitOffset>
              <bitWidth>1</bitWidth>
            </field>
            <field>
              <name>ID9</name>
              <bitOffset>9</bitOffset>
              <bitWidth>1</bitWidth>
            </field>
            <field>
              <name>ID10</name>
              <bitOffset>10</bitOffset>
              <bitWidth>1</bitWidth>
            </field>
            <field>
              <name>ID11</name>
              <bitOffset>11</bitOffset>
              <bitWidth>1</bitWidth>
            </field>
            <field>
              <name>ID12</name>
              <bitOffset>12</bitOffset>
              <bitWidth>1</bitWidth>
            </field>
            <field>
              <name>ID13</name>
              <bitOffset>13</bitOffset>
              <bitWidth>1</bitWidth>
            </field>
            <field>
              <name>ID14</name>
              <bitOffset>14</bitOffset>
              <bitWidth>1</bitWidth>
            </field>
            <field>
              <name>ID15</name>
              <bitOffset>15</bitOffset>
              <bitWidth>1</bitWidth>
            </field>
          </fields>
        </register>
        <register>
          <name>ODR</name>
          <addressOffset>0x14</addressOffset>
          <size>0x20</size>
          <fields>
            <field>
              <name>OD0</name>
              <bitOffset>0</bitOffset>
              <bitWidth>1</bitWidth>
            </field>
            <field>
              <name>OD1</name>
              <bitOffset>1</bitOffset>
              <bitWidth>1</bitWidth>
            </field>
            <field>
              <name>OD2</name>
              <bitOffset>2</bitOffset>
              <bitWidth>1</bitWidth>
            </field>
            <field>
              <name>OD3</name>
              <bitOffset>3</bitOffset>
              <bitWidth>1</bitWidth>
            </field>
            <field>
              <name>OD4</name>
              <bitOffset>4</bitOffset>
              <bitWidth>1</bitWidth>
            </field>
            <field>
              <name>OD5</name>
              <bitOffset>5</bitOffset>
              <bitWidth>1</bitWidth>
            </field>
            <field>
              <name>OD6</name>
              <bitOffset>6</bitOffset>
              <bitWidth>1</bitWidth>
            </field>
            <field>
              <name>OD7</name>
              <bitOffset>7</bitOffset>
              <bitWidth>1</bitWidth>
            </field>
            <field>
              <name>OD8</name>
              <bitOffset>8</bitOffset>
              <bitWidth>1</bitWidth>
            </field>
            <field>
              <name>OD9</name>
              <bitOffset>9</bitOffset>
              <bitWidth>1</bitWidth>
            </field>
            <field>
              <name>OD10</name>
              <bitOffset>10</bitOffset>
              <bitWidth>1</bitWidth>
            </field>
            <field>
              <name>OD11</name>
              <bitOffset>11</bitOffset>
              <bitWidth>1</bitWidth>
            </field>
            <field>
              <name>OD12</name>
              <bitOffset>12</bitOffset>
              <bitWidth>1</bitWidth>
            </field>
            <field>
              <name>OD13</name>
              <bitOffset>13</bitOffset>
              <bitWidth>1</bitWidth>
            </field>
            <field>
              <name>OD14</name>
              <bitOffset>14</bitOffset>
              <bitWidth>1</bitWidth>
            </field>
            <field>
              <name>OD15</name>
              <bitOffset>15</bitOffset>
              <bitWidth>1</bitWidth>
            </field>
          </fields>
        </register>
        <register>
          <name>BSRR</name>
          <addressOffset>0x18</addressOffset>
          <size>0x20</size>
          <fields>
            <field>
              <name>BS0</name>
              <bitOffset>0</bitOffset>
              <bitWidth>1</bitWidth>
            </field>
            <field>
              <name>BS1</name>
              <bitOffset>1</bitOffset>
              <bitWidth>1</bitWidth>
            </field>
            <field>
              <name>BS2</name>
              <bitOffset>2</bitOffset>
              <bitWidth>1</bitWidth>
            </field>
            <field>
              <name>BS3</name>
              <bitOffset>3</bitOffset>
              <bitWidth>1</bitWidth>
            </field>
            <field>
              <name>BS4</name>
              <bitOffset>4</bitOffset>
              <bitWidth>1</bitWidth>
            </field>
            <field>
              <name>BS5</name>
              <bitOffset>5</bitOffset>
              <bitWidth>1</bitWidth>
            </field>
            <field>
              <name>BS6</name>
              <bitOffset>6</bitOffset>
              <bitWidth>1</bitWidth>
            </field>
            <field>
              <name>BS7</name>
              <bitOffset>7</bitOffset>
              <bitWidth>1</bitWidth>
            </field>
            <field>
              <name>BS8</name>
              <bitOffset>8</bitOffset>
              <bitWidth>1</bitWidth>
            </field>
            <field>
              <name>BS9</name>
              <bitOffset>9</bitOffset>
              <bitWidth>1</bitWidth>
            </field>
            <field>
              <name>BS10</name>
              <bitOffset>10</bitOffset>
              <bitWidth>1</bitWidth>
            </field>
            <field>
              <name>BS11</name>
              <bitOffset>11</bitOffset>
              <bitWidth>1</bitWidth>
            </field>
            <field>
              <name>BS12</name>
              <bitOffset>12</bitOffset>
              <bitWidth>1</bitWidth>
            </field>
            <field>
              <name>BS13</name>
              <bitOffset>13</bitOffset>
              <bitWidth>1</bitWidth>
            </field>
            <field>
              <name>BS14</name>
              <bitOffset>14</bitOffset>
              <bitWidth>1</bitWidth>
            </field>
            <field>
              <name>BS15</name>
              <bitOffset>15</bitOffset>
              <bitWidth>1</bitWidth>
            </field>
            <field>
              <name>BR0</name>
              <bitOffset>16</bitOffset>
              <bitWidth>1</bitWidth>
            </field>
            <field>
              <name>BR1</name>
              <bitOffset>17</bitOffset>
              <bitWidth>1</bitWidth>
            </field>
            <field>
              <name>BR2</name>
              <bitOffset>18</bitOffset>
              <bitWidth>1</bitWidth>
            </field>
            <field>
              <name>BR3</name>
              <bitOffset>19</bitOffset>
              <bitWidth>1</bitWidth>
            </field>
            <field>
              <name>BR4</name>
              <bitOffset>20</bitOffset>
              <bitWidth>1</bitWidth>
            </field>
            <field>
              <name>BR5</name>
              <bitOffset>21</bitOffset>
              <bitWidth>1</bitWidth>
            </field>
            <field>
              <name>BR6</name>
              <bitOffset>22</bitOffset>
              <bitWidth>1</bitWidth>
            </field>
            <field>
              <name>BR7</name>
              <bitOffset>23</bitOffset>
              <bitWidth>1</bitWidth>
            </field>
            <field>
              <name>BR8</name>
              <bitOffset>24</bitOffset>
              <bitWidth>1</bitWidth>
            </field>
            <field>
              <name>BR9</name>
              <bitOffset>25</bitOffset>
              <bitWidth>1</bitWidth>
            </field>
            <field>
              <name>BR10</name>
              <bitOffset>26</bitOffset>
              <bitWidth>1</bitWidth>
            </field>
            <field>
              <name>BR11</name>
              <bitOffset>27</bitOffset>
              <bitWidth>1</bitWidth>
            </field>
            <field>
              <name>BR12</name>
              <bitOffset>28</bitOffset>
              <bitWidth>1</bitWidth>
            </field>
            <field>
              <name>BR13</name>
              <bitOffset>29</bitOffset>
              <bitWidth>1</bitWidth>
            </field>
            <field>
              <name>BR14</name>
              <bitOffset>30</bitOffset>
              <bitWidth>1</bitWidth>
            </field>
            <field>
              <name>BR15</name>
              <bitOffset>31</bitOffset>
              <bitWidth>1</bitWidth>
            </field>
          </fields>
        </register>
        <register>
          <name>LCKR</name>
          <addressOffset>0x1c</addressOffset>
          <size>0x20</size>
        </register>
        <register>
          <name>AFR.0</name>
          <addressOffset>0x20</addressOffset>
          <size>0x20</size>
        </register>
        <register>
          <name>AFR.1</name>
          <addressOffset>0x24</addressOffset>
          <size>0x20</size>
          <fields>
            <field>
              <name>AFSEL8</name>
              <bitOffset>0</bitOffset>
              <bitWidth>4</bitWidth>
            </field>
            <field>
              <name>AFSEL9</name>
              <bitOffset>4</bitOffset>
              <bitWidth>4</bitWidth>
            </field>
            <field>
              <name>AFSEL10</name>
              <bitOffset>8</bitOffset>
              <bitWidth>4</bitWidth>
            </field>
            <field>
              <name>AFSEL11</name>
              <bitOffset>12</bitOffset>
              <bitWidth>4</bitWidth>
            </field>
            <field>
              <name>AFSEL12</name>
              <bitOffset>16</bitOffset>
              <bitWidth>4</bitWidth>
            </field>
            <field>
              <name>AFSEL13</name>
              <bitOffset>20</bitOffset>
              <bitWidth>4</bitWidth>
            </field>
            <field>
              <name>AFSEL14</name>
              <bitOffset>24</bitOffset>
              <bitWidth>4</bitWidth>
            </field>
            <field>
              <name>AFSEL15</name>
              <bitOffset>28</bitOffset>
              <bitWidth>4</bitWidth>
            </field>
          </fields>
        </register>
      </registers>
    </peripheral>
    <peripheral>
      <name>CRC</name>
      <baseAddress>0x40023000</baseAddress>
      <registers>
        <register>
          <name>DR</name>
          <addressOffset>0x0</addressOffset>
          <size>0x20</size>
          <fields>
            <field>
              <name>DR</name>
              <bitOffset>0</bitOffset>
              <bitWidth>32</bitWidth>
            </field>
          </fields>
        </register>
        <register>
          <name>IDR</name>
          <addressOffset>0x4</addressOffset>
          <size>0x8</size>
          <fields>
            <field>
              <name>IDR</name>
              <bitOffset>0</bitOffset>
              <bitWidth>8</bitWidth>
            </field>
          </fields>
        </register>
        <register>
          <name>CR</name>
          <addressOffset>0x8</addressOffset>
          <size>0x20</size>
          <fields>
            <field>
              <name>RESET</name>
              <bitOffset>0</bitOffset>
              <bitWidth>1</bitWidth>
            </field>
          </fields>
        </register>
      </registers>
    </peripheral>
    <peripheral>
      <name>RCC</name>
      <baseAddress>0x40023800</baseAddress>
      <registers>
        <register>
          <name>CR</name>
          <addressOffset>0x0</addressOffset>
          <size>0x20</size>
          <fields>
            <field>
              <name>HSION</name>
              <bitOffset>0</bitOffset>
              <bitWidth>1</bitWidth>
            </field>
            <field>
              <name>HSIRDY</name>
              <bitOffset>1</bitOffset>
              <bitWidth>1</bitWidth>
            </field>
            <field>
              <name>HSITRIM</name>
              <bitOffset>3</bitOffset>
              <bitWidth>5</bitWidth>
            </field>
            <field>
              <name>HSICAL</name>
              <bitOffset>8</bitOffset>
              <bitWidth>8</bitWidth>
            </field>
            <field>
              <name>HSEON</name>
              <bitOffset>16</bitOffset>
              <bitWidth>1</bitWidth>
            </field>
            <field>
              <name>HSERDY</name>
              <bitOffset>17</bitOffset>
              <bitWidth>1</bitWidth>
            </field>
            <field>
              <name>HSEBYP</name>
              <bitOffset>18</bitOffset>
              <bitWidth>1</bitWidth>
            </field>
            <field>
              <name>CSSON</name>
              <bitOffset>19</bitOffset>
              <bitWidth>1</bitWidth>
            </field>
            <field>
              <name>PLLON</name>
              <bitOffset>24</bitOffset>
              <bitWidth>1</bitWidth>
            </field>
            <field>
              <name>PLLRDY</name>
              <bitOffset>25</bitOffset>
              <bitWidth>1</bitWidth>
            </field>
            <field>
              <name>PLLI2SON</name>
              <bitOffset>26</bitOffset>
              <bitWidth>1</bitWidth>
            </field>
            <field>
              <name>PLLI2SRDY</name>
              <bitOffset>27</bitOffset>
              <bitWidth>1</bitWidth>
            </field>
            <field>
              <name>PLLSAION</name>
              <bitOffset>28</bitOffset>
              <bitWidth>1</bitWidth>
            </field>
            <field>
              <name>PLLSAIRDY</name>
              <bitOffset>29</bitOffset>
              <bitWidth>1</bitWidth>
            </field>
          </fields>
        </register>
        <register>
          <name>PLLCFGR</name>
          <addressOffset>0x4</addressOffset>
          <size>0x20</size>
          <fields>
            <field>
              <name>PLLM</name>
              <bitOffset>0</bitOffset>
              <bitWidth>6</bitWidth>
            </field>
            <field>
              <name>PLLN</name>
              <bitOffset>6</bitOffset>
              <bitWidth>9</bitWidth>
            </field>
            <field>
              <name>PLLP</name>
              <bitOffset>16</bitOffset>
              <bitWidth>2</bitWidth>
            </field>
            <field>
              <name>PLLSRC_HSE</name>
              <bitOffset>22</bitOffset>
              <bitWidth>1</bitWidth>
            </field>
            <field>
              <name>PLLQ</name>
              <bitOffset>24</bitOffset>
              <bitWidth>4</bitWidth>
            </field>
          </fields>
        </register>
        <register>
          <name>CFGR</name>
          <addressOffset>0x8</addressOffset>
          <size>0x20</size>
          <fields>
            <field>
              <name>SW</name>
              <bitOffset>0</bitOffset>
              <bitWidth>2</bitWidth>
            </field>
            <field>
              <name>SWS</name>
              <bitOffset>2</bitOffset>
              <bitWidth>2</bitWidth>
            </field>
            <field>
              <name>HPRE</name>
              <bitOffset>4</bitOffset>
              <bitWidth>4</bitWidth>
            </field>
            <field>
              <name>PPRE1</name>
              <bitOffset>10</bitOffset>
              <bitWidth>3</bitWidth>
            </field>
            <field>
              <name>PPRE2</name>
              <bitOffset>13</bitOffset>
              <bitWidth>3</bitWidth>
            </field>
            <field>
              <name>RTCPRE</name>
              <bitOffset>16</bitOffset>
              <bitWidth>5</bitWidth>
            </field>
            <field>
              <name>MCO1</name>
              <bitOffset>21</bitOffset>
              <bitWidth>2</bitWidth>
            </field>
            <field>
              <name>I2SSRC</name>
              <bitOffset>23</bitOffset>
              <bitWidth>1</bitWidth>
            </field>
            <field>
              <name>MCO1PRE</name>
              <bitOffset>24</bitOffset>
              <bitWidth>3</bitWidth>
            </field>
            <field>
              <name>MCO2PRE</name>
              <bitOffset>27</bitOffset>
              <bitWidth>3</bitWidth>
            </field>
            <field>
              <name>MCO2</name>
              <bitOffset>30</bitOffset>
              <bitWidth>2</bitWidth>
            </field>
          </fields>
        </register>
        <register>
          <name>CIR</name>
          <addressOffset>0xc</addressOffset>
          <size>0x20</size>
          <fields>
            <field>
              <name>LSIRDYF</name>
              <bitOffset>0</bitOffset>
              <bitWidth>1</bitWidth>
            </field>
            <field>
              <name>LSERDYF</name>
              <bitOffset>1</bitOffset>
              <bitWidth>1</bitWidth>
            </field>
            <field>
              <name>HSIRDYF</name>
              <bitOffset>2</bitOffset>
              <bitWidth>1</bitWidth>
            </field>
            <field>
              <name>HSERDYF</name>
              <bitOffset>3</bitOffset>
              <bitWidth>1</bitWidth>
            </field>
            <field>
              <name>PLLRDYF</name>
              <bitOffset>4</bitOffset>
              <bitWidth>1</bitWidth>
            </field>
            <field>
              <name>PLLI2SRDYF</name>
              <bitOffset>5</bitOffset>
              <bitWidth>1</bitWidth>
            </field>
            <field>
              <name>PLLSAIRDYF</name>
              <bitOffset>6</bitOffset>
              <bitWidth>1</bitWidth>
            </field>
            <field>
              <name>CSSF</name>
              <bitOffset>7</bitOffset>
              <bitWidth>1</bitWidth>
            </field>
            <field>
              <name>LSIRDYIE</name>
              <bitOffset>8</bitOffset>
              <bitWidth>1</bitWidth>
            </field>
            <field>
              <name>LSERDYIE</name>
              <bitOffset>9</bitOffset>
              <bitWidth>1</bitWidth>
            </field>
            <field>
              <name>HSIRDYIE</name>
              <bitOffset>10</bitOffset>
              <bitWidth>1</bitWidth>
            </field>
            <field>
              <name>HSERDYIE</name>
              <bitOffset>11</bitOffset>
              <bitWidth>1</bitWidth>
            </field>
            <field>
              <name>PLLRDYIE</name>
              <bitOffset>12</bitOffset>
              <bitWidth>1</bitWidth>
            </field>
            <field>
              <name>PLLI2SRDYIE</name>
              <bitOffset>13</bitOffset>
              <bitWidth>1</bitWidth>
            </field>
            <field>
              <name>PLLSAIRDYIE</name>
              <bitOffset>14</bitOffset>
              <bitWidth>1</bitWidth>
            </field>
            <field>
              <name>LSIRDYC</name>
              <bitOffset>16</bitOffset>
              <bitWidth>1</bitWidth>
            </field>
            <field>
              <name>LSERDYC</name>
              <bitOffset>17</bitOffset>
              <bitWidth>1</bitWidth>
            </field>
            <field>
              <name>HSIRDYC</name>
              <bitOffset>18</bitOffset>
              <bitWidth>1</bitWidth>
            </field>
            <field>
              <name>HSERDYC</name>
              <bitOffset>19</bitOffset>
              <bitWidth>1</bitWidth>
            </field>
            <field>
              <name>PLLRDYC</name>
              <bitOffset>20</bitOffset>
              <bitWidth>1</bitWidth>
            </field>
            <field>
              <name>PLLI2SRDYC</name>
              <bitOffset>21</bitOffset>
              <bitWidth>1</bitWidth>
            </field>
            <field>
              <name>PLLSAIRDYC</name>
              <bitOffset>22</bitOffset>
              <bitWidth>1</bitWidth>
            </field>
            <field>
              <name>CSSC</name>
              <bitOffset>23</bitOffset>
              <bitWidth>1</bitWidth>
            </field>
          </fields>
        </register>
        <register>
          <name>AHB1RSTR</name>
          <addressOffset>0x10</addressOffset>
          <size>0x20</size>
          <fields>
            <field>
              <name>GPIOARST</name>
              <bitOffset>0</bitOffset>
              <bitWidth>1</bitWidth>
            </field>
            <field>
              <name>GPIOBRST</name>
              <bitOffset>1</bitOffset>
              <bitWidth>1</bitWidth>
            </field>
            <field>
              <name>GPIOCRST</name>
              <bitOffset>2</bitOffset>
              <bitWidth>1</bitWidth>
            </field>
            <field>
              <name>GPIODRST</name>
              <bitOffset>3</bitOffset>
              <bitWidth>1</bitWidth>
            </field>
            <field>
              <name>GPIOERST</name>
              <bitOffset>4</bitOffset>
              <bitWidth>1</bitWidth>
            </field>
            <field>
              <name>GPIOFRST</name>
              <bitOffset>5</bitOffset>
              <bitWidth>1</bitWidth>
            </field>
            <field>
              <name>GPIOGRST</name>
              <bitOffset>6</bitOffset>
              <bitWidth>1</bitWidth>
            </field>
            <field>
              <name>GPIOHRST</name>
              <bitOffset>7</bitOffset>
              <bitWidth>1</bitWidth>
            </field>
            <field>
              <name>GPIOIRST</name>
              <bitOffset>8</bitOffset>
              <bitWidth>1</bitWidth>
            </field>
            <field>
              <name>GPIOJRST</name>
              <bitOffset>9</bitOffset>
              <bitWidth>1</bitWidth>
            </field>
            <field>
              <name>GPIOKRST</name>
              <bitOffset>10</bitOffset>
              <bitWidth>1</bitWidth>
            </field>
            <field>
              <name>CRCRST</name>
              <bitOffset>12</bitOffset>
              <bitWidth>1</bitWidth>
            </field>
            <field>
              <name>DMA1RST</name>
              <bitOffset>21</bitOffset>
              <bitWidth>1</bitWidth>
            </field>
            <field>
              <name>DMA2RST</name>
              <bitOffset>22</bitOffset>
              <bitWidth>1</bitWidth>
            </field>
            <field>
              <name>DMA2DRST</name>
              <bitOffset>23</bitOffset>
              <bitWidth>1</bitWidth>
            </field>
            <field>
              <name>ETHMACRST</name>
              <bitOffset>25</bitOffset>
              <bitWidth>1</bitWidth>
            </field>
            <field>
              <name>OTGHRST</name>
              <bitOffset>29</bitOffset>
              <bitWidth>1</bitWidth>
            </field>
          </fields>
        </register>
        <register>
          <name>AHB2RSTR</name>
          <addressOffset>0x14</addressOffset>
          <size>0x20</size>
          <fields>
            <field>
              <name>DCMIRST</name>
              <bitOffset>0</bitOffset>
              <bitWidth>1</bitWidth>
            </field>
            <field>
              <name>RNGRST</name>
              <bitOffset>6</bitOffset>
              <bitWidth>1</bitWidth>
            </field>
            <field>
              <name>OTGFSRST</name>
              <bitOffset>7</bitOffset>
              <bitWidth>1</bitWidth>
            </field>
          </fields>
        </register>
        <register>
          <name>AHB3RSTR</name>
          <addressOffset>0x18</addressOffset>
          <size>0x20</size>
          <fields>
            <field>
              <name>FMCRST</name>
              <bitOffset>0</bitOffset>
              <bitWidth>1</bitWidth>
            </field>
          </fields>
        </register>
        <register>
          <name>APB1RSTR</name>
          <addressOffset>0x20</addressOffset>
          <size>0x20</size>
          <fields>
            <field>
              <name>TIM2RST</name>
              <bitOffset>0</bitOffset>
              <bitWidth>1</bitWidth>
            </field>
            <field>
              <name>TIM3RST</name>
              <bitOffset>1</bitOffset>
              <bitWidth>1</bitWidth>
            </field>
            <field>
              <name>TIM4RST</name>
              <bitOffset>2</bitOffset>
              <bitWidth>1</bitWidth>
            </field>
            <field>
              <name>TIM5RST</name>
              <bitOffset>3</bitOffset>
              <bitWidth>1</bitWidth>
            </field>
            <field>
              <name>TIM6RST</name>
              <bitOffset>4</bitOffset>
              <bitWidth>1</bitWidth>
            </field>
            <field>
              <name>TIM7RST</name>
              <bitOffset>5</bitOffset>
              <bitWidth>1</bitWidth>
            </field>
            <field>
              <name>TIM12RST</name>
              <bitOffset>6</bitOffset>
              <bitWidth>1</bitWidth>
            </field>
            <field>
              <name>TIM13RST</name>
              <bitOffset>7</bitOffset>
              <bitWidth>1</bitWidth>
            </field>
            <field>
              <name>TIM14RST</name>
              <bitOffset>8</bitOffset>
              <bitWidth>1</bitWidth>
            </field>
            <field>
              <name>WWDGRST</name>
              <bitOffset>11</bitOffset>
              <bitWidth>1</bitWidth>
            </field>
            <field>
              <name>SPI2RST</name>
              <bitOffset>14</bitOffset>
              <bitWidth>1</bitWidth>
            </field>
            <field>
              <name>SPI3RST</name>
              <bitOffset>15</bitOffset>
              <bitWidth>1</bitWidth>
            </field>
            <field>
              <name>USART2RST</name>
              <bitOffset>17</bitOffset>
              <bitWidth>1</bitWidth>
            </field>
            <field>
              <name>USART3RST</name>
              <bitOffset>18</bitOffset>
              <bitWidth>1</bitWidth>
            </field>
            <field>
              <name>UART4RST</name>
              <bitOffset>19</bitOffset>
              <bitWidth>1</bitWidth>
            </field>
            <field>
              <name>UART5RST</name>
              <bitOffset>20</bitOffset>
              <bitWidth>1</bitWidth>
            </field>
            <field>
              <name>I2C1RST</name>
              <bitOffset>21</bitOffset>
              <bitWidth>1</bitWidth>
            </field>
            <field>
              <name>I2C2RST</name>
              <bitOffset>22</bitOffset>
              <bitWidth>1</bitWidth>
            </field>
            <field>
              <name>I2C3RST</name>
              <bitOffset>23</bitOffset>
              <bitWidth>1</bitWidth>
            </field>
            <field>
              <name>CAN1RST</name>
              <bitOffset>25</bitOffset>
              <bitWidth>1</bitWidth>
            </field>
            <field>
              <name>CAN2RST</name>
              <bitOffset>26</bitOffset>
              <bitWidth>1</bitWidth>
            </field>
            <field>
              <name>PWRRST</name>
              <bitOffset>28</bitOffset>
              <bitWidth>1</bitWidth>
            </field>
            <field>
              <name>DACRST</name>
              <bitOffset>29</bitOffset>
              <bitWidth>1</bitWidth>
            </field>
            <field>
              <name>UART7RST</name>
              <bitOffset>30</bitOffset>
              <bitWidth>1</bitWidth>
            </field>
            <field>
              <name>UART8RST</name>
              <bitOffset>31</bitOffset>
              <bitWidth>1</bitWidth>
            </field>
          </fields>
        </register>
        <register>
          <name>APB2RSTR</name>
          <addressOffset>0x24</addressOffset>
          <size>0x20</size>
          <fields>
            <field>
              <name>TIM1RST</name>
              <bitOffset>0</bitOffset>
              <bitWidth>1</bitWidth>
            </field>
            <field>
              <name>TIM8RST</name>
              <bitOffset>1</bitOffset>
              <bitWidth>1</bitWidth>
            </field>
            <field>
              <name>USART1RST</name>
              <bitOffset>4</bitOffset>
              <bitWidth>1</bitWidth>
            </field>
            <field>
              <name>USART6RST</name>
              <bitOffset>5</bitOffset>
              <bitWidth>1</bitWidth>
            </field>
            <field>
              <name>ADCRST</name>
              <bitOffset>8</bitOffset>
              <bitWidth>1</bitWidth>
            </field>
            <field>
              <name>SDIORST</name>
              <bitOffset>11</bitOffset>
              <bitWidth>1</bitWidth>
            </field>
            <field>
              <name>SPI1RST</name>
              <bitOffset>12</bitOffset>
              <bitWidth>1</bitWidth>
            </field>
            <field>
              <name>SPI4RST</name>
              <bitOffset>13</bitOffset>
              <bitWidth>1</bitWidth>
            </field>
            <field>
              <name>SYSCFGRST</name>
              <bitOffset>14</bitOffset>
              <bitWidth>1</bitWidth>
            </field>
            <field>
              <name>TIM9RST</name>
              <bitOffset>16</bitOffset>
              <bitWidth>1</bitWidth>
            </field>
            <field>
              <name>TIM10RST</name>
              <bitOffset>17</bitOffset>
              <bitWidth>1</bitWidth>
            </field>
            <field>
              <name>TIM11RST</name>
              <bitOffset>18</bitOffset>
              <bitWidth>1</bitWidth>
            </field>
            <field>
              <name>SPI5RST</name>
              <bitOffset>20</bitOffset>
              <bitWidth>1</bitWidth>
            </field>
            <field>
              <name>SPI6RST</name>
              <bitOffset>21</bitOffset>
              <bitWidth>1</bitWidth>
            </field>
            <field>
              <name>SAI1RST</name>
              <bitOffset>22</bitOffset>
              <bitWidth>1</bitWidth>
            </field>
            <field>
              <name>LTDCRST</name>
              <bitOffset>26</bitOffset>
              <bitWidth>1</bitWidth>
            </field>
          </fields>
        </register>
        <register>
          <name>AHB1ENR</name>
          <addressOffset>0x30</addressOffset>
          <size>0x20</size>
          <fields>
            <field>
              <name>GPIOAEN</name>
              <bitOffset>0</bitOffset>
              <bitWidth>1</bitWidth>
            </field>
            <field>
              <name>GPIOBEN</name>
              <bitOffset>1</bitOffset>
              <bitWidth>1</bitWidth>
            </field>
            <field>
              <name>GPIOCEN</name>
              <bitOffset>2</bitOffset>
              <bitWidth>1</bitWidth>
            </field>
            <field>
              <name>GPIODEN</name>
              <bitOffset>3</bitOffset>
              <bitWidth>1</bitWidth>
            </field>
            <field>
              <name>GPIOEEN</name>
              <bitOffset>4</bitOffset>
              <bitWidth>1</bitWidth>
            </field>
            <field>
              <name>GPIOFEN</name>
              <bitOffset>5</bitOffset>
              <bitWidth>1</bitWidth>
            </field>
            <field>
              <name>GPIOGEN</name>
              <bitOffset>6</bitOffset>
              <bitWidth>1</bitWidth>
            </field>
            <field>
              <name>GPIOHEN</name>
              <bitOffset>7</bitOffset>
              <bitWidth>1</bitWidth>
            </field>
            <field>
              <name>GPIOIEN</name>
              <bitOffset>8</bitOffset>
              <bitWidth>1</bitWidth>
            </field>
            <field>
              <name>GPIOJEN</name>
              <bitOffset>9</bitOffset>
              <bitWidth>1</bitWidth>
            </field>
            <field>
              <name>GPIOKEN</name>
              <bitOffset>10</bitOffset>
              <bitWidth>1</bitWidth>
            </field>
            <field>
              <name>CRCEN</name>
              <bitOffset>12</bitOffset>
              <bitWidth>1</bitWidth>
            </field>
            <field>
              <name>BKPSRAMEN</name>
              <bitOffset>18</bitOffset>
              <bitWidth>1</bitWidth>
            </field>
            <field>
              <name>CCMDATARAMEN</name>
              <bitOffset>20</bitOffset>
              <bitWidth>1</bitWidth>
            </field>
            <field>
              <name>DMA1EN</name>
              <bitOffset>21</bitOffset>
              <bitWidth>1</bitWidth>
            </field>
            <field>
              <name>DMA2EN</name>
              <bitOffset>22</bitOffset>
              <bitWidth>1</bitWidth>
            </field>
            <field>
              <name>DMA2DEN</name>
              <bitOffset>23</bitOffset>
              <bitWidth>1</bitWidth>
            </field>
            <field>
              <name>ETHMACEN</name>
              <bitOffset>25</bitOffset>
              <bitWidth>1</bitWidth>
            </field>
            <field>
              <name>ETHMACTXEN</name>
              <bitOffset>26</bitOffset>
              <bitWidth>1</bitWidth>
            </field>
            <field>
              <name>ETHMACRXEN</name>
              <bitOffset>27</bitOffset>
              <bitWidth>1</bitWidth>
            </field>
            <field>
              <name>ETHMACPTPEN</name>
              <bitOffset>28</bitOffset>
              <bitWidth>1</bitWidth>
            </field>
            <field>
              <name>OTGHSEN</name>
              <bitOffset>29</bitOffset>
              <bitWidth>1</bitWidth>
            </field>
            <field>
              <name>OTGHSULPIEN</name>
              <bitOffset>30</bitOffset>
              <bitWidth>1</bitWidth>
            </field>
          </fields>
        </register>
        <register>
          <name>AHB2ENR</name>
          <addressOffset>0x34</addressOffset>
          <size>0x20</size>
          <fields>
            <field>
              <name>DCMIEN</name>
              <bitOffset>0</bitOffset>
              <bitWidth>1</bitWidth>
            </field>
            <field>
              <name>RNGEN</name>
              <bitOffset>6</bitOffset>
              <bitWidth>1</bitWidth>
            </field>
            <field>
              <name>OTGFSEN</name>
              <bitOffset>7</bitOffset>
              <bitWidth>1</bitWidth>
            </field>
          </fields>
        </register>
        <register>
          <name>AHB3ENR</name>
          <addressOffset>0x38</addressOffset>
          <size>0x20</size>
          <fields>
            <field>
              <name>FMCEN</name>
              <bitOffset>0</bitOffset>
              <bitWidth>1</bitWidth>
            </field>
          </fields>
        </register>
        <register>
          <name>APB1ENR</name>
          <addressOffset>0x40</addressOffset>
          <size>0x20</size>
          <fields>
            <field>
              <name>TIM2EN</name>
              <bitOffset>0</bitOffset>
              <bitWidth>1</bitWidth>
            </field>
            <field>
              <name>TIM3EN</name>
              <bitOffset>1</bitOffset>
              <bitWidth>1</bitWidth>
            </field>
            <field>
              <name>TIM4EN</name>
              <bitOffset>2</bitOffset>
              <bitWidth>1</bitWidth>
            </field>
            <field>
              <name>TIM5EN</name>
              <bitOffset>3</bitOffset>
              <bitWidth>1</bitWidth>
            </field>
            <field>
              <name>TIM6EN</name>
              <bitOffset>4</bitOffset>
              <bitWidth>1</bitWidth>
            </field>
            <field>
              <name>TIM7EN</name>
              <bitOffset>5</bitOffset>
              <bitWidth>1</bitWidth>
            </field>
            <field>
              <name>TIM12EN</name>
              <bitOffset>6</bitOffset>
              <bitWidth>1</bitWidth>
            </field>
            <field>
              <name>TIM13EN</name>
              <bitOffset>7</bitOffset>
              <bitWidth>1</bitWidth>
            </field>
            <field>
              <name>TIM14EN</name>
              <bitOffset>8</bitOffset>
              <bitWidth>1</bitWidth>
            </field>
            <field>
              <name>WWDGEN</name>
              <bitOffset>11</bitOffset>
              <bitWidth>1</bitWidth>
            </field>
            <field>
              <name>SPI2EN</name>
              <bitOffset>14</bitOffset>
              <bitWidth>1</bitWidth>
            </field>
            <field>
              <name>SPI3EN</name>
              <bitOffset>15</bitOffset>
              <bitWidth>1</bitWidth>
            </field>
            <field>
              <name>USART2EN</name>
              <bitOffset>17</bitOffset>
              <bitWidth>1</bitWidth>
            </field>
            <field>
              <name>USART3EN</name>
              <bitOffset>18</bitOffset>
              <bitWidth>1</bitWidth>
            </field>
            <field>
              <name>UART4EN</name>
              <bitOffset>19</bitOffset>
              <bitWidth>1</bitWidth>
            </field>
            <field>
              <name>UART5EN</name>
              <bitOffset>20</bitOffset>
              <bitWidth>1</bitWidth>
            </field>
            <field>
              <name>I2C1EN</name>
              <bitOffset>21</bitOffset>
              <bitWidth>1</bitWidth>
            </field>
            <field>
              <name>I2C2EN</name>
              <bitOffset>22</bitOffset>
              <bitWidth>1</bitWidth>
            </field>
            <field>
              <name>I2C3EN</name>
              <bitOffset>23</bitOffset>
              <bitWidth>1</bitWidth>
            </field>
            <field>
              <name>CAN1EN</name>
              <bitOffset>25</bitOffset>
              <bitWidth>1</bitWidth>
            </field>
            <field>
              <name>CAN2EN</name>
              <bitOffset>26</bitOffset>
              <bitWidth>1</bitWidth>
            </field>
            <field>
              <name>PWREN</name>
              <bitOffset>28</bitOffset>
              <bitWidth>1</bitWidth>
            </field>
            <field>
              <name>DACEN</name>
              <bitOffset>29</bitOffset>
              <bitWidth>1</bitWidth>
            </field>
            <field>
              <name>UART7EN</name>
              <bitOffset>30</bitOffset>
              <bitWidth>1</bitWidth>
            </field>
            <field>
              <name>UART8EN</name>
              <bitOffset>31</bitOffset>
              <bitWidth>1</bitWidth>
            </field>
          </fields>
        </register>
        <register>
          <name>APB2ENR</name>
          <addressOffset>0x44</addressOffset>
          <size>0x20</size>
          <fields>
            <field>
              <name>TIM1EN</name>
              <bitOffset>0</bitOffset>
              <bitWidth>1</bitWidth>
            </field>
            <field>
              <name>TIM8EN</name>
              <bitOffset>1</bitOffset>
              <bitWidth>1</bitWidth>
            </field>
            <field>
              <name>USART1EN</name>
              <bitOffset>4</bitOffset>
              <bitWidth>1</bitWidth>
            </field>
            <field>
              <name>USART6EN</name>
              <bitOffset>5</bitOffset>
              <bitWidth>1</bitWidth>
            </field>
            <field>
              <name>ADC1EN</name>
              <bitOffset>8</bitOffset>
              <bitWidth>1</bitWidth>
            </field>
            <field>
              <name>ADC2EN</name>
              <bitOffset>9</bitOffset>
              <bitWidth>1</bitWidth>
            </field>
            <field>
              <name>ADC3EN</name>
              <bitOffset>10</bitOffset>
              <bitWidth>1</bitWidth>
            </field>
            <field>
              <name>SDIOEN</name>
              <bitOffset>11</bitOffset>
              <bitWidth>1</bitWidth>
            </field>
            <field>
              <name>SPI1EN</name>
              <bitOffset>12</bitOffset>
              <bitWidth>1</bitWidth>
            </field>
            <field>
              <name>SPI4EN</name>
              <bitOffset>13</bitOffset>
              <bitWidth>1</bitWidth>
            </field>
            <field>
              <name>SYSCFGEN</name>
              <bitOffset>14</bitOffset>
              <bitWidth>1</bitWidth>
            </field>
            <field>
              <name>TIM9EN</name>
              <bitOffset>16</bitOffset>
              <bitWidth>1</bitWidth>
            </field>
            <field>
              <name>TIM10EN</name>
              <bitOffset>17</bitOffset>
              <bitWidth>1</bitWidth>
            </field>
            <field>
              <name>TIM11EN</name>
              <bitOffset>18</bitOffset>
              <bitWidth>1</bitWidth>
            </field>
            <field>
              <name>SPI5EN</name>
              <bitOffset>20</bitOffset>
              <bitWidth>1</bitWidth>
            </field>
            <field>
              <name>SPI6EN</name>
              <bitOffset>21</bitOffset>
              <bitWidth>1</bitWidth>
            </field>
            <field>
              <name>SAI1EN</name>
              <bitOffset>22</bitOffset>
              <bitWidth>1</bitWidth>
            </field>
            <field>
              <name>LTDCEN</name>
              <bitOffset>26</bitOffset>
              <bitWidth>1</bitWidth>
            </field>
          </fields>
        </register>
        <register>
          <name>AHB1LPENR</name>
          <addressOffset>0x50</addressOffset>
          <size>0x20</size>
          <fields>
            <field>
              <name>GPIOALPEN</name>
              <bitOffset>0</bitOffset>
              <bitWidth>1</bitWidth>
            </field>
            <field>
              <name>GPIOBLPEN</name>
              <bitOffset>1</bitOffset>
              <bitWidth>1</bitWidth>
            </field>
            <field>
              <name>GPIOCLPEN</name>
              <bitOffset>2</bitOffset>
              <bitWidth>1</bitWidth>
            </field>
            <field>
              <name>GPIODLPEN</name>
              <bitOffset>3</bitOffset>
              <bitWidth>1</bitWidth>
            </field>
            <field>
              <name>GPIOELPEN</name>
              <bitOffset>4</bitOffset>
              <bitWidth>1</bitWidth>
            </field>
            <field>
              <name>GPIOFLPEN</name>
              <bitOffset>5</bitOffset>
              <bitWidth>1</bitWidth>
            </field>
            <field>
              <name>GPIOGLPEN</name>
              <bitOffset>6</bitOffset>
              <bitWidth>1</bitWidth>
            </field>
            <field>
              <name>GPIOHLPEN</name>
              <bitOffset>7</bitOffset>
              <bitWidth>1</bitWidth>
            </field>
            <field>
              <name>GPIOILPEN</name>
              <bitOffset>8</bitOffset>
              <bitWidth>1</bitWidth>
            </field>
            <field>
              <name>GPIOJLPEN</name>
              <bitOffset>9</bitOffset>
              <bitWidth>1</bitWidth>
            </field>
            <field>
              <name>GPIOKLPEN</name>
              <bitOffset>10</bitOffset>
              <bitWidth>1</bitWidth>
            </field>
            <field>
              <name>CRCLPEN</name>
              <bitOffset>12</bitOffset>
              <bitWidth>1</bitWidth>
            </field>
            <field>
              <name>FLITFLPEN</name>
              <bitOffset>15</bitOffset>
              <bitWidth>1</bitWidth>
            </field>
            <field>
              <name>SRAM1LPEN</name>
              <bitOffset>16</bitOffset>
              <bitWidth>1</bitWidth>
            </field>
            <field>
              <name>SRAM2LPEN</name>
              <bitOffset>17</bitOffset>
              <bitWidth>1</bitWidth>
            </field>
            <field>
              <name>BKPSRAMLPEN</name>
              <bitOffset>18</bitOffset>
              <bitWidth>1</bitWidth>
            </field>
            <field>
              <name>SRAM3LPEN</name>
              <bitOffset>19</bitOffset>
              <bitWidth>1</bitWidth>
            </field>
            <field>
              <name>DMA1LPEN</name>
              <bitOffset>21</bitOffset>
              <bitWidth>1</bitWidth>
            </field>
            <field>
              <name>DMA2LPEN</name>
              <bitOffset>22</bitOffset>
              <bitWidth>1</bitWidth>
            </field>
            <field>
              <name>DMA2DLPEN</name>
              <bitOffset>23</bitOffset>
              <bitWidth>1</bitWidth>
            </field>
            <field>
              <name>ETHMACLPEN</name>
              <bitOffset>25</bitOffset>
              <bitWidth>1</bitWidth>
            </field>
            <field>
              <name>ETHMACTXLPEN</name>
              <bitOffset>26</bitOffset>
              <bitWidth>1</bitWidth>
            </field>
            <field>
              <name>ETHMACRXLPEN</name>
              <bitOffset>27</bitOffset>
              <bitWidth>1</bitWidth>
            </field>
            <field>
              <name>ETHMACPTPLPEN</name>
              <bitOffset>28</bitOffset>
              <bitWidth>1</bitWidth>
            </field>
            <field>
              <name>OTGHSLPEN</name>
              <bitOffset>29</bitOffset>
              <bitWidth>1</bitWidth>
            </field>
            <field>
              <name>OTGHSULPILPEN</name>
              <bitOffset>30</bitOffset>
              <bitWidth>1</bitWidth>
            </field>
          </fields>
        </register>
        <register>
          <name>AHB2LPENR</name>
          <addressOffset>0x54</addressOffset>
          <size>0x20</size>
          <fields>
            <field>
              <name>DCMILPEN</name>
              <bitOffset>0</bitOffset>
              <bitWidth>1</bitWidth>
            </field>
            <field>
              <name>RNGLPEN</name>
              <bitOffset>6</bitOffset>
              <bitWidth>1</bitWidth>
            </field>
            <field>
              <name>OTGFSLPEN</name>
              <bitOffset>7</bitOffset>
              <bitWidth>1</bitWidth>
            </field>
          </fields>
        </register>
        <register>
          <name>AHB3LPENR</name>
          <addressOffset>0x58</addressOffset>
          <size>0x20</size>
          <fields>
            <field>
              <name>FMCLPEN</name>
              <bitOffset>0</bitOffset>
              <bitWidth>1</bitWidth>
            </field>
          </fields>
        </register>
        <register>
          <name>APB1LPENR</name>
          <addressOffset>0x60</addressOffset>
          <size>0x20</size>
          <fields>
            <field>
              <name>TIM2LPEN</name>
              <bitOffset>0</bitOffset>
              <bitWidth>1</bitWidth>
            </field>
            <field>
              <name>TIM3LPEN</name>
              <bitOffset>1</bitOffset>
              <bitWidth>1</bitWidth>
            </field>
            <field>
              <name>TIM4LPEN</name>
              <bitOffset>2</bitOffset>
              <bitWidth>1</bitWidth>
            </field>
            <field>
              <name>TIM5LPEN</name>
              <bitOffset>3</bitOffset>
              <bitWidth>1</bitWidth>
            </field>
            <field>
              <name>TIM6LPEN</name>
              <bitOffset>4</bitOffset>
              <bitWidth>1</bitWidth>
            </field>
            <field>
              <name>TIM7LPEN</name>
              <bitOffset>5</bitOffset>
              <bitWidth>1</bitWidth>
            </field>
            <field>
              <name>TIM12LPEN</name>
              <bitOffset>6</bitOffset>
              <bitWidth>1</bitWidth>
            </field>
            <field>
              <name>TIM13LPEN</name>
              <bitOffset>7</bitOffset>
              <bitWidth>1</bitWidth>
            </field>
            <field>
              <name>TIM14LPEN</name>
              <bitOffset>8</bitOffset>
              <bitWidth>1</bitWidth>
            </field>
            <field>
              <name>WWDGLPEN</name>
              <bitOffset>11</bitOffset>
              <bitWidth>1</bitWidth>
            </field>
            <field>
              <name>SPI2LPEN</name>
              <bitOffset>14</bitOffset>
              <bitWidth>1</bitWidth>
            </field>
            <field>
              <name>SPI3LPEN</name>
              <bitOffset>15</bitOffset>
              <bitWidth>1</bitWidth>
            </field>
            <field>
              <name>USART2LPEN</name>
              <bitOffset>17</bitOffset>
              <bitWidth>1</bitWidth>
            </field>
            <field>
              <name>USART3LPEN</name>
              <bitOffset>18</bitOffset>
              <bitWidth>1</bitWidth>
            </field>
            <field>
              <name>UART4LPEN</name>
              <bitOffset>19</bitOffset>
              <bitWidth>1</bitWidth>
            </field>
            <field>
              <name>UART5LPEN</name>
              <bitOffset>20</bitOffset>
              <bitWidth>1</bitWidth>
            </field>
            <field>
              <name>I2C1LPEN</name>
              <bitOffset>21</bitOffset>
              <bitWidth>1</bitWidth>
            </field>
            <field>
              <name>I2C2LPEN</name>
              <bitOffset>22</bitOffset>
              <bitWidth>1</bitWidth>
            </field>
            <field>
              <name>I2C3LPEN</name>
              <bitOffset>23</bitOffset>
              <bitWidth>1</bitWidth>
            </field>
            <field>
              <name>CAN1LPEN</name>
              <bitOffset>25</bitOffset>
              <bitWidth>1</bitWidth>
            </field>
            <field>
              <name>CAN2LPEN</name>
              <bitOffset>26</bitOffset>
              <bitWidth>1</bitWidth>
            </field>
            <field>
              <name>PWRLPEN</name>
              <bitOffset>28</bitOffset>
              <bitWidth>1</bitWidth>
            </field>
            <field>
              <name>DACLPEN</name>
              <bitOffset>29</bitOffset>
              <bitWidth>1</bitWidth>
            </field>
            <field>
              <name>UART7LPEN</name>
              <bitOffset>30</bitOffset>
              <bitWidth>1</bitWidth>
            </field>
            <field>
              <name>UART8LPEN</name>
              <bitOffset>31</bitOffset>
              <bitWidth>1</bitWidth>
            </field>
          </fields>
        </register>
        <register>
          <name>APB2LPENR</name>
          <addressOffset>0x64</addressOffset>
          <size>0x20</size>
          <fields>
            <field>
              <name>TIM1LPEN</name>
              <bitOffset>0</bitOffset>
              <bitWidth>1</bitWidth>
            </field>
            <field>
              <name>TIM8LPEN</name>
              <bitOffset>1</bitOffset>
              <bitWidth>1</bitWidth>
            </field>
            <field>
              <name>USART1LPEN</name>
              <bitOffset>4</bitOffset>
              <bitWidth>1</bitWidth>
            </field>
            <field>
              <name>USART6LPEN</name>
              <bitOffset>5</bitOffset>
              <bitWidth>1</bitWidth>
            </field>
            <field>
              <name>ADC1LPEN</name>
              <bitOffset>8</bitOffset>
              <bitWidth>1</bitWidth>
            </field>
            <field>
              <name>ADC2LPEN</name>
              <bitOffset>9</bitOffset>
              <bitWidth>1</bitWidth>
            </field>
            <field>
              <name>ADC3LPEN</name>
              <bitOffset>10</bitOffset>
              <bitWidth>1</bitWidth>
            </field>
            <field>
              <name>SDIOLPEN</name>
              <bitOffset>11</bitOffset>
              <bitWidth>1</bitWidth>
            </field>
            <field>
              <name>SPI1LPEN</name>
              <bitOffset>12</bitOffset>
              <bitWidth>1</bitWidth>
            </field>
            <field>
              <name>SPI4LPEN</name>
              <bitOffset>13</bitOffset>
              <bitWidth>1</bitWidth>
            </field>
            <field>
              <name>SYSCFGLPEN</name>
              <bitOffset>14</bitOffset>
              <bitWidth>1</bitWidth>
            </field>
            <field>
              <name>TIM9LPEN</name>
              <bitOffset>16</bitOffset>
              <bitWidth>1</bitWidth>
            </field>
            <field>
              <name>TIM10LPEN</name>
              <bitOffset>17</bitOffset>
              <bitWidth>1</bitWidth>
            </field>
            <field>
              <name>TIM11LPEN</name>
              <bitOffset>18</bitOffset>
              <bitWidth>1</bitWidth>
            </field>
            <field>
              <name>SPI5LPEN</name>
              <bitOffset>20</bitOffset>
              <bitWidth>1</bitWidth>
            </field>
            <field>
              <name>SPI6LPEN</name>
              <bitOffset>21</bitOffset>
              <bitWidth>1</bitWidth>
            </field>
            <field>
              <name>SAI1LPEN</name>
              <bitOffset>22</bitOffset>
              <bitWidth>1</bitWidth>
            </field>
            <field>
              <name>LTDCLPEN</name>
              <bitOffset>26</bitOffset>
              <bitWidth>1</bitWidth>
            </field>
          </fields>
        </register>
        <register>
          <name>BDCR</name>
          <addressOffset>0x70</addressOffset>
          <size>0x20</size>
          <fields>
            <field>
              <name>LSEON</name>
              <bitOffset>0</bitOffset>
              <bitWidth>1</bitWidth>
            </field>
            <field>
              <name>LSERDY</name>
              <bitOffset>1</bitOffset>
              <bitWidth>1</bitWidth>
            </field>
            <field>
              <name>LSEBYP</name>
              <bitOffset>2</bitOffset>
              <bitWidth>1</bitWidth>
            </field>
            <field>
              <name>RTCSEL</name>
              <bitOffset>8</bitOffset>
              <bitWidth>2</bitWidth>
            </field>
            <field>
              <name>RTCEN</name>
              <bitOffset>15</bitOffset>
              <bitWidth>1</bitWidth>
            </field>
            <field>
              <name>BDRST</name>
              <bitOffset>16</bitOffset>
              <bitWidth>1</bitWidth>
            </field>
          </fields>
        </register>
        <register>
          <name>CSR</name>
          <addressOffset>0x74</addressOffset>
          <size>0x20</size>
          <fields>
            <field>
              <name>LSION</name>
              <bitOffset>0</bitOffset>
              <bitWidth>1</bitWidth>
            </field>
            <field>
              <name>LSIRDY</name>
              <bitOffset>1</bitOffset>
              <bitWidth>1</bitWidth>
            </field>
            <field>
              <name>RMVF</name>
              <bitOffset>24</bitOffset>
              <bitWidth>1</bitWidth>
            </field>
            <field>
              <name>BORRSTF</name>
              <bitOffset>25</bitOffset>
              <bitWidth>1</bitWidth>
            </field>
            <field>
              <name>PINRSTF</name>
              <bitOffset>26</bitOffset>
              <bitWidth>1</bitWidth>
            </field>
            <field>
              <name>PORRSTF</name>
              <bitOffset>27</bitOffset>
              <bitWidth>1</bitWidth>
            </field>
            <field>
              <name>SFTRSTF</name>
              <bitOffset>28</bitOffset>
              <bitWidth>1</bitWidth>
            </field>
            <field>
              <name>IWDGRSTF</name>
              <bitOffset>29</bitOffset>
              <bitWidth>1</bitWidth>
            </field>
            <field>
              <name>WWDGRSTF</name>
              <bitOffset>30</bitOffset>
              <bitWidth>1</bitWidth>
            </field>
            <field>
              <name>LPWRRSTF</name>
              <bitOffset>31</bitOffset>
              <bitWidth>1</bitWidth>
            </field>
          </fields>
        </register>
        <register>
          <name>SSCGR</name>
          <addressOffset>0x80</addressOffset>
          <size>0x20</size>
          <fields>
            <field>
              <name>MODPER</name>
              <bitOffset>0</bitOffset>
              <bitWidth>13</bitWidth>
            </field>
            <field>
              <name>INCSTEP</name>
              <bitOffset>13</bitOffset>
              <bitWidth>15</bitWidth>
            </field>
            <field>
              <name>SPREADSEL</name>
              <bitOffset>30</bitOffset>
              <bitWidth>1</bitWidth>
            </field>
            <field>
              <name>SSCGEN</name>
              <bitOffset>31</bitOffset>
              <bitWidth>1</bitWidth>
            </field>
          </fields>
        </register>
        <register>
          <name>PLLI2SCFGR</name>
          <addressOffset>0x84</addressOffset>
          <size>0x20</size>
          <fields>
            <field>
              <name>PLLI2SN</name>
              <bitOffset>6</bitOffset>
              <bitWidth>9</bitWidth>
            </field>
            <field>
              <name>PLLI2SQ</name>
              <bitOffset>24</bitOffset>
              <bitWidth>4</bitWidth>
            </field>
            <field>
              <name>PLLI2SR</name>
              <bitOffset>28</bitOffset>
              <bitWidth>3</bitWidth>
            </field>
          </fields>
        </register>
        <register>
          <name>PLLSAICFGR</name>
          <addressOffset>0x88</addressOffset>
          <size>0x20</size>
          <fields>
            <field>
              <name>PLLSAIN</name>
              <bitOffset>6</bitOffset>
              <bitWidth>9</bitWidth>
            </field>
            <field>
              <name>PLLSAIQ</name>
              <bitOffset>24</bitOffset>
              <bitWidth>4</bitWidth>
            </field>
            <field>
              <name>PLLSAIR</name>
              <bitOffset>28</bitOffset>
              <bitWidth>3</bitWidth>
            </field>
          </fields>
        </register>
        <register>
          <name>DCKCFGR</name>
          <addressOffset>0x8c</addressOffset>
          <size>0x20</size>
          <fields>
            <field>
              <name>PLLI2SDIVQ</name>
              <bitOffset>0</bitOffset>
              <bitWidth>5</bitWidth>
            </field>
            <field>
              <name>PLLSAIDIVQ</name>
              <bitOffset>8</bitOffset>
              <bitWidth>5</bitWidth>
            </field>
            <field>
              <name>PLLSAIDIVR</name>
              <bitOffset>16</bitOffset>
              <bitWidth>2</bitWidth>
            </field>
            <field>
              <name>SAI1ASRC</name>
              <bitOffset>20</bitOffset>
              <bitWidth>2</bitWidth>
            </field>
            <field>
              <name>SAI1BSRC</name>
              <bitOffset>22</bitOffset>
              <bitWidth>2</bitWidth>
            </field>
            <field>
              <name>TIMPRE</name>
              <bitOffset>24</bitOffset>
              <bitWidth>1</bitWidth>
            </field>
          </fields>
        </register>
      </registers>
    </peripheral>
    <peripheral>
      <name>FLASH</name>
      <baseAddress>0x40023c00</baseAddress>
      <registers>
        <register>
          <name>ACR</name>
          <addressOffset>0x0</addressOffset>
          <size>0x20</size>
          <fields>
            <field>
              <name>LATENCY</name>
              <bitOffset>0</bitOffset>
              <bitWidth>4</bitWidth>
            </field>
            <field>
              <name>PRFTEN</name>
              <bitOffset>8</bitOffset>
              <bitWidth>1</bitWidth>
            </field>
            <field>
              <name>ICEN</name>
              <bitOffset>9</bitOffset>
              <bitWidth>1</bitWidth>
            </field>
            <field>
              <name>DCEN</name>
              <bitOffset>10</bitOffset>
              <bitWidth>1</bitWidth>
            </field>
            <field>
              <name>ICRST</name>
              <bitOffset>11</bitOffset>
              <bitWidth>1</bitWidth>
            </field>
            <field>
              <name>DCRST</name>
              <bitOffset>12</bitOffset>
              <bitWidth>1</bitWidth>
            </field>
          </fields>
        </register>
        <register>
          <name>KEYR</name>
          <addressOffset>0x4</addressOffset>
          <size>0x20</size>
        </register>
        <register>
          <name>OPTKEYR</name>
          <addressOffset>0x8</addressOffset>
          <size>0x20</size>
        </register>
        <register>
          <name>SR</name>
          <addressOffset>0xc</addressOffset>
          <size>0x20</size>
          <fields>
            <field>
              <name>EOP</name>
              <bitOffset>0</bitOffset>
              <bitWidth>1</bitWidth>
            </field>
            <field>
              <name>SOP</name>
              <bitOffset>1</bitOffset>
              <bitWidth>1</bitWidth>
            </field>
            <field>
              <name>WRPERR</name>
              <bitOffset>4</bitOffset>
              <bitWidth>1</bitWidth>
            </field>
            <field>
              <name>PGAERR</name>
              <bitOffset>5</bitOffset>
              <bitWidth>1</bitWidth>
            </field>
            <field>
              <name>PGPERR</name>
              <bitOffset>6</bitOffset>
              <bitWidth>1</bitWidth>
            </field>
            <field>
              <name>PGSERR</name>
              <bitOffset>7</bitOffset>
              <bitWidth>1</bitWidth>
            </field>
            <field>
              <name>RDERR</name>
              <bitOffset>8</bitOffset>
              <bitWidth>1</bitWidth>
            </field>
            <field>
              <name>BSY</name>
              <bitOffset>16</bitOffset>
              <bitWidth>1</bitWidth>
            </field>
          </fields>
        </register>
        <register>
          <name>CR</name>
          <addressOffset>0x10</addressOffset>
          <size>0x20</size>
          <fields>
            <field>
              <name>PG</name>
              <bitOffset>0</bitOffset>
              <bitWidth>1</bitWidth>
            </field>
            <field>
              <name>SER</name>
              <bitOffset>1</bitOffset>
              <bitWidth>1</bitWidth>
            </field>
            <field>
              <name>MER</name>
              <bitOffset>2</bitOffset>
              <bitWidth>1</bitWidth>
            </field>
            <field>
              <name>SNB</name>
              <bitOffset>3</bitOffset>
              <bitWidth>5</bitWidth>
            </field>
            <field>
              <name>PSIZE</name>
              <bitOffset>8</bitOffset>
              <bitWidth>2</bitWidth>
            </field>
            <field>
              <name>MER2</name>
              <bitOffset>15</bitOffset>
              <bitWidth>1</bitWidth>
            </field>
            <field>
              <name>STRT</name>
              <bitOffset>16</bitOffset>
              <bitWidth>1</bitWidth>
            </field>
            <field>
              <name>EOPIE</name>
              <bitOffset>24</bitOffset>
              <bitWidth>1</bitWidth>
            </field>
            <field>
              <name>ERRIE</name>
              <bitOffset>25</bitOffset>
              <bitWidth>1</bitWidth>
            </field>
            <field>
              <name>LOCK</name>
              <bitOffset>31</bitOffset>
              <bitWidth>1</bitWidth>
            </field>
          </fields>
        </register>
        <register>
          <name>OPTCR</name>
          <addressOffset>0x14</addressOffset>
          <size>0x20</size>
          <fields>
            <field>
              <name>OPTLOCK</name>
              <bitOffset>0</bitOffset>
              <bitWidth>1</bitWidth>
            </field>
            <field>
              <name>OPTSTRT</name>
              <bitOffset>1</bitOffset>
              <bitWidth>1</bitWidth>
            </field>
            <field>
              <name>BOR_LEV</name>
              <bitOffset>2</bitOffset>
              <bitWidth>2</bitWidth>
            </field>
            <field>
              <name>BFB2</name>
              <bitOffset>4</bitOffset>
              <bitWidth>1</bitWidth>
            </field>
            <field>
              <name>WDG_SW</name>
              <bitOffset>5</bitOffset>
              <bitWidth>1</bitWidth>
            </field>
            <field>
              <name>nRST_STOP</name>
              <bitOffset>6</bitOffset>
              <bitWidth>1</bitWidth>
            </field>
            <field>
              <name>nRST_STDBY</name>
              <bitOffset>7</bitOffset>
              <bitWidth>1</bitWidth>
            </field>
            <field>
              <name>RDP</name>
              <bitOffset>8</bitOffset>
              <bitWidth>8</bitWidth>
            </field>
            <field>
              <name>nWRP</name>
              <bitOffset>16</bitOffset>
              <bitWidth>12</bitWidth>
            </field>
            <field>
              <name>DB1M</name>
              <bitOffset>30</bitOffset>
              <bitWidth>1</bitWidth>
            </field>
            <field>
              <name>SPRMOD</name>
              <bitOffset>31</bitOffset>
              <bitWidth>1</bitWidth>
            </field>
          </fields>
        </register>
        <register>
          <name>OPTCR1</name>
          <addressOffset>0x18</addressOffset>
          <size>0x20</size>
          <fields>
            <field>
              <name>nWRP</name>
              <bitOffset>16</bitOffset>
              <bitWidth>12</bitWidth>
            </field>
          </fields>
        </register>
      </registers>
    </peripheral>
    <peripheral>
      <name>DMA1</name>
      <baseAddress>0x40026000</baseAddress>
      <registers>
        <register>
          <name>LISR</name>
          <addressOffset>0x0</addressOffset>
          <size>0x20</size>
          <fields>
            <field>
              <name>FEIF0</name>
              <bitOffset>0</bitOffset>
              <bitWidth>1</bitWidth>
            </field>
            <field>
              <name>DMEIF0</name>
              <bitOffset>2</bitOffset>
              <bitWidth>1</bitWidth>
            </field>
            <field>
              <name>TEIF0</name>
              <bitOffset>3</bitOffset>
              <bitWidth>1</bitWidth>
            </field>
            <field>
              <name>HTIF0</name>
              <bitOffset>4</bitOffset>
              <bitWidth>1</bitWidth>
            </field>
            <field>
              <name>TCIF0</name>
              <bitOffset>5</bitOffset>
              <bitWidth>1</bitWidth>
            </field>
            <field>
              <name>FEIF1</name>
              <bitOffset>6</bitOffset>
              <bitWidth>1</bitWidth>
            </field>
            <field>
              <name>DMEIF1</name>
              <bitOffset>8</bitOffset>
              <bitWidth>1</bitWidth>
            </field>
            <field>
              <name>TEIF1</name>
              <bitOffset>9</bitOffset>
              <bitWidth>1</bitWidth>
            </field>
            <field>
              <name>HTIF1</name>
              <bitOffset>10</bitOffset>
              <bitWidth>1</bitWidth>
            </field>
            <field>
              <name>TCIF1</name>
              <bitOffset>11</bitOffset>
              <bitWidth>1</bitWidth>
            </field>
            <field>
              <name>FEIF2</name>
              <bitOffset>16</bitOffset>
              <bitWidth>1</bitWidth>
            </field>
            <field>
              <name>DMEIF2</name>
              <bitOffset>18</bitOffset>
              <bitWidth>1</bitWidth>
            </field>
            <field>
              <name>TEIF2</name>
              <bitOffset>19</bitOffset>
              <bitWidth>1</bitWidth>
            </field>
            <field>
              <name>HTIF2</name>
              <bitOffset>20</bitOffset>
              <bitWidth>1</bitWidth>
            </field>
            <field>
              <name>TCIF2</name>
              <bitOffset>21</bitOffset>
              <bitWidth>1</bitWidth>
            </field>
            <field>
              <name>FEIF3</name>
              <bitOffset>22</bitOffset>
              <bitWidth>1</bitWidth>
            </field>
            <field>
              <name>DMEIF3</name>
              <bitOffset>24</bitOffset>
              <bitWidth>1</bitWidth>
            </field>
            <field>
              <name>TEIF3</name>
              <bitOffset>25</bitOffset>
              <bitWidth>1</bitWidth>
            </field>
            <field>
              <name>HTIF3</name>
              <bitOffset>26</bitOffset>
              <bitWidth>1</bitWidth>
            </field>
            <field>
              <name>TCIF3</name>
              <bitOffset>27</bitOffset>
              <bitWidth>1</bitWidth>
            </field>
          </fields>
        </register>
        <register>
          <name>HISR</name>
          <addressOffset>0x4</addressOffset>
          <size>0x20</size>
          <fields>
            <field>
              <name>FEIF4</name>
              <bitOffset>0</bitOffset>
              <bitWidth>1</bitWidth>
            </field>
            <field>
              <name>DMEIF4</name>
              <bitOffset>2</bitOffset>
              <bitWidth>1</bitWidth>
            </field>
            <field>
              <name>TEIF4</name>
              <bitOffset>3</bitOffset>
              <bitWidth>1</bitWidth>
            </field>
            <field>
              <name>HTIF4</name>
              <bitOffset>4</bitOffset>
              <bitWidth>1</bitWidth>
            </field>
            <field>
              <name>TCIF4</name>
              <bitOffset>5</bitOffset>
              <bitWidth>1</bitWidth>
            </field>
            <field>
              <name>FEIF5</name>
              <bitOffset>6</bitOffset>
              <bitWidth>1</bitWidth>
            </field>
            <field>
              <name>DMEIF5</name>
              <bitOffset>8</bitOffset>
              <bitWidth>1</bitWidth>
            </field>
            <field>
              <name>TEIF5</name>
              <bitOffset>9</bitOffset>
              <bitWidth>1</bitWidth>
            </field>
            <field>
              <name>HTIF5</name>
              <bitOffset>10</bitOffset>
              <bitWidth>1</bitWidth>
            </field>
            <field>
              <name>TCIF5</name>
              <bitOffset>11</bitOffset>
              <bitWidth>1</bitWidth>
            </field>
            <field>
              <name>FEIF6</name>
              <bitOffset>16</bitOffset>
              <bitWidth>1</bitWidth>
            </field>
            <field>
              <name>DMEIF6</name>
              <bitOffset>18</bitOffset>
              <bitWidth>1</bitWidth>
            </field>
            <field>
              <name>TEIF6</name>
              <bitOffset>19</bitOffset>
              <bitWidth>1</bitWidth>
            </field>
            <field>
              <name>HTIF6</name>
              <bitOffset>20</bitOffset>
              <bitWidth>1</bitWidth>
            </field>
            <field>
              <name>TCIF6</name>
              <bitOffset>21</bitOffset>
              <bitWidth>1</bitWidth>
            </field>
            <field>
              <name>FEIF7</name>
              <bitOffset>22</bitOffset>
              <bitWidth>1</bitWidth>
            </field>
            <field>
              <name>DMEIF7</name>
              <bitOffset>24</bitOffset>
              <bitWidth>1</bitWidth>
            </field>
            <field>
              <name>TEIF7</name>
              <bitOffset>25</bitOffset>
              <bitWidth>1</bitWidth>
            </field>
            <field>
              <name>HTIF7</name>
              <bitOffset>26</bitOffset>
              <bitWidth>1</bitWidth>
            </field>
            <field>
              <name>TCIF7</name>
              <bitOffset>27</bitOffset>
              <bitWidth>1</bitWidth>
            </field>
          </fields>
        </register>
        <register>
          <name>LIFCR</name>
          <addressOffset>0x8</addressOffset>
          <size>0x20</size>
          <fields>
            <field>
              <name>CFEIF0</name>
              <bitOffset>0</bitOffset>
              <bitWidth>1</bitWidth>
            </field>
            <field>
              <name>CDMEIF0</name>
              <bitOffset>2</bitOffset>
              <bitWidth>1</bitWidth>
            </field>
            <field>
              <name>CTEIF0</name>
              <bitOffset>3</bitOffset>
              <bitWidth>1</bitWidth>
            </field>
            <field>
              <name>CHTIF0</name>
              <bitOffset>4</bitOffset>
              <bitWidth>1</bitWidth>
            </field>
            <field>
              <name>CTCIF0</name>
              <bitOffset>5</bitOffset>
              <bitWidth>1</bitWidth>
            </field>
            <field>
              <name>CFEIF1</name>
              <bitOffset>6</bitOffset>
              <bitWidth>1</bitWidth>
            </field>
            <field>
              <name>CDMEIF1</name>
              <bitOffset>8</bitOffset>
              <bitWidth>1</bitWidth>
            </field>
            <field>
              <name>CTEIF1</name>
              <bitOffset>9</bitOffset>
              <bitWidth>1</bitWidth>
            </field>
            <field>
              <name>CHTIF1</name>
              <bitOffset>10</bitOffset>
              <bitWidth>1</bitWidth>
            </field>
            <field>
              <name>CTCIF1</name>
              <bitOffset>11</bitOffset>
              <bitWidth>1</bitWidth>
            </field>
            <field>
              <name>CFEIF2</name>
              <bitOffset>16</bitOffset>
              <bitWidth>1</bitWidth>
            </field>
            <field>
              <name>CDMEIF2</name>
              <bitOffset>18</bitOffset>
              <bitWidth>1</bitWidth>
            </field>
            <field>
              <name>CTEIF2</name>
              <bitOffset>19</bitOffset>
              <bitWidth>1</bitWidth>
            </field>
            <field>
              <name>CHTIF2</name>
              <bitOffset>20</bitOffset>
              <bitWidth>1</bitWidth>
            </field>
            <field>
              <name>CTCIF2</name>
              <bitOffset>21</bitOffset>
              <bitWidth>1</bitWidth>
            </field>
            <field>
              <name>CFEIF3</name>
              <bitOffset>22</bitOffset>
              <bitWidth>1</bitWidth>
            </field>
            <field>
              <name>CDMEIF3</name>
              <bitOffset>24</bitOffset>
              <bitWidth>1</bitWidth>
            </field>
            <field>
              <name>CTEIF3</name>
              <bitOffset>25</bitOffset>
              <bitWidth>1</bitWidth>
            </field>
            <field>
              <name>CHTIF3</name>
              <bitOffset>26</bitOffset>
              <bitWidth>1</bitWidth>
            </field>
            <field>
              <name>CTCIF3</name>
              <bitOffset>27</bitOffset>
              <bitWidth>1</bitWidth>
            </field>
          </fields>
        </register>
        <register>
          <name>HIFCR</name>
          <addressOffset>0xc</addressOffset>
          <size>0x20</size>
          <fields>
            <field>
              <name>CFEIF4</name>
              <bitOffset>0</bitOffset>
              <bitWidth>1</bitWidth>
            </field>
            <field>
              <name>CDMEIF4</name>
              <bitOffset>2</bitOffset>
              <bitWidth>1</bitWidth>
            </field>
            <field>
              <name>CTEIF4</name>
              <bitOffset>3</bitOffset>
              <bitWidth>1</bitWidth>
            </field>
            <field>
              <name>CHTIF4</name>
              <bitOffset>4</bitOffset>
              <bitWidth>1</bitWidth>
            </field>
            <field>
              <name>CTCIF4</name>
              <bitOffset>5</bitOffset>
              <bitWidth>1</bitWidth>
            </field>
            <field>
              <name>CFEIF5</name>
              <bitOffset>6</bitOffset>
              <bitWidth>1</bitWidth>
            </field>
            <field>
              <name>CDMEIF5</name>
              <bitOffset>8</bitOffset>
              <bitWidth>1</bitWidth>
            </field>
            <field>
              <name>CTEIF5</name>
              <bitOffset>9</bitOffset>
              <bitWidth>1</bitWidth>
            </field>
            <field>
              <name>CHTIF5</name>
              <bitOffset>10</bitOffset>
              <bitWidth>1</bitWidth>
            </field>
            <field>
              <name>CTCIF5</name>
              <bitOffset>11</bitOffset>
              <bitWidth>1</bitWidth>
            </field>
            <field>
              <name>CFEIF6</name>
              <bitOffset>16</bitOffset>
              <bitWidth>1</bitWidth>
            </field>
            <field>
              <name>CDMEIF6</name>
              <bitOffset>18</bitOffset>
              <bitWidth>1</bitWidth>
            </field>
            <field>
              <name>CTEIF6</name>
              <bitOffset>19</bitOffset>
              <bitWidth>1</bitWidth>
            </field>
            <field>
              <name>CHTIF6</name>
              <bitOffset>20</bitOffset>
              <bitWidth>1</bitWidth>
            </field>
            <field>
              <name>CTCIF6</name>
              <bitOffset>21</bitOffset>
              <bitWidth>1</bitWidth>
            </field>
            <field>
              <name>CFEIF7</name>
              <bitOffset>22</bitOffset>
              <bitWidth>1</bitWidth>
            </field>
            <field>
              <name>CDMEIF7</name>
              <bitOffset>24</bitOffset>
              <bitWidth>1</bitWidth>
            </field>
            <field>
              <name>CTEIF7</name>
              <bitOffset>25</bitOffset>
              <bitWidth>1</bitWidth>
            </field>
            <field>
              <name>CHTIF7</name>
              <bitOffset>26</bitOffset>
              <bitWidth>1</bitWidth>
            </field>
            <field>
              <name>CTCIF7</name>
              <bitOffset>27</bitOffset>
              <bitWidth>1</bitWidth>
            </field>
          </fields>
        </register>
        <register>
          <name>CR0</name>
          <addressOffset>0x10</addressOffset>
          <size>0x20</size>
        </register>
        <register>
          <name>CR0</name>
          <addressOffset>0x10</addressOffset>
          <size>0x20</size>
        </register>
        <register>
          <name>NDTR0</name>
          <addressOffset>0x14</addressOffset>
          <size>0x20</size>
        </register>
        <register>
          <name>NDTR0</name>
          <addressOffset>0x14</addressOffset>
          <size>0x20</size>
        </register>
        <register>
          <name>PAR0</name>
          <addressOffset>0x18</addressOffset>
          <size>0x20</size>
        </register>
        <register>
          <name>PAR0</name>
          <addressOffset>0x18</addressOffset>
          <size>0x20</size>
        </register>
        <register>
          <name>M0AR0</name>
          <addressOffset>0x1c</addressOffset>
          <size>0x20</size>
        </register>
        <register>
          <name>M0AR0</name>
          <addressOffset>0x1c</addressOffset>
          <size>0x20</size>
        </register>
        <register>
          <name>M1AR0</name>
          <addressOffset>0x20</addressOffset>
          <size>0x20</size>
        </register>
        <register>
          <name>M1AR0</name>
          <addressOffset>0x20</addressOffset>
          <size>0x20</size>
        </register>
        <register>
          <name>FCR0</name>
          <addressOffset>0x24</addressOffset>
          <size>0x20</size>
        </register>
        <register>
          <name>FCR0</name>
          <addressOffset>0x24</addressOffset>
          <size>0x20</size>
        </register>
        <register>
          <name>CR1</name>
          <addressOffset>0x28</addressOffset>
          <size>0x20</size>
        </register>
        <register>
          <name>CR1</name>
          <addressOffset>0x28</addressOffset>
          <size>0x20</size>
        </register>
        <register>
          <name>NDTR1</name>
          <addressOffset>0x2c</addressOffset>
          <size>0x20</size>
        </register>
        <register>
          <name>NDTR1</name>
          <addressOffset>0x2c</addressOffset>
          <size>0x20</size>
        </register>
        <register>
          <name>PAR1</name>
          <addressOffset>0x30</addressOffset>
          <size>0x20</size>
        </register>
        <register>
          <name>PAR1</name>
          <addressOffset>0x30</addressOffset>
          <size>0x20</size>
        </register>
        <register>
          <name>M0AR1</name>
          <addressOffset>0x34</addressOffset>
          <size>0x20</size>
        </register>
        <register>
          <name>M0AR1</name>
          <addressOffset>0x34</addressOffset>
          <size>0x20</size>
        </register>
        <register>
          <name>M1AR1</name>
          <addressOffset>0x38</addressOffset>
          <size>0x20</size>
        </register>
        <register>
          <name>M1AR1</name>
          <addressOffset>0x38</addressOffset>
          <size>0x20</size>
        </register>
        <register>
          <name>FCR1</name>
          <addressOffset>0x3c</addressOffset>
          <size>0x20</size>
        </register>
        <register>
          <name>FCR1</name>
          <addressOffset>0x3c</addressOffset>
          <size>0x20</size>
        </register>
        <register>
          <name>CR2</name>
          <addressOffset>0x40</addressOffset>
          <size>0x20</size>
        </register>
        <register>
          <name>CR2</name>
          <addressOffset>0x40</addressOffset>
          <size>0x20</size>
        </register>
        <register>
          <name>NDTR2</name>
          <addressOffset>0x44</addressOffset>
          <size>0x20</size>
        </register>
        <register>
          <name>NDTR2</name>
          <addressOffset>0x44</addressOffset>
          <size>0x20</size>
        </register>
        <register>
          <name>PAR2</name>
          <addressOffset>0x48</addressOffset>
          <size>0x20</size>
        </register>
        <register>
          <name>PAR2</name>
          <addressOffset>0x48</addressOffset>
          <size>0x20</size>
        </register>
        <register>
          <name>M0AR2</name>
          <addressOffset>0x4c</addressOffset>
          <size>0x20</size>
        </register>
        <register>
          <name>M0AR2</name>
          <addressOffset>0x4c</addressOffset>
          <size>0x20</size>
        </register>
        <register>
          <name>M1AR2</name>
          <addressOffset>0x50</addressOffset>
          <size>0x20</size>
        </register>
        <register>
          <name>M1AR2</name>
          <addressOffset>0x50</addressOffset>
          <size>0x20</size>
        </register>
        <register>
          <name>FCR2</name>
          <addressOffset>0x54</addressOffset>
          <size>0x20</size>
        </register>
        <register>
          <name>FCR2</name>
          <addressOffset>0x54</addressOffset>
          <size>0x20</size>
        </register>
        <register>
          <name>CR3</name>
          <addressOffset>0x58</addressOffset>
          <size>0x20</size>
        </register>
        <register>
          <name>CR3</name>
          <addressOffset>0x58</addressOffset>
          <size>0x20</size>
        </register>
        <register>
          <name>NDTR3</name>
          <addressOffset>0x5c</addressOffset>
          <size>0x20</size>
        </register>
        <register>
          <name>NDTR3</name>
          <addressOffset>0x5c</addressOffset>
          <size>0x20</size>
        </register>
        <register>
          <name>PAR3</name>
          <addressOffset>0x60</addressOffset>
          <size>0x20</size>
        </register>
        <register>
          <name>PAR3</name>
          <addressOffset>0x60</addressOffset>
          <size>0x20</size>
        </register>
        <register>
          <name>M0AR3</name>
          <addressOffset>0x64</addressOffset>
          <size>0x20</size>
        </register>
        <register>
          <name>M0AR3</name>
          <addressOffset>0x64</addressOffset>
          <size>0x20</size>
        </register>
        <register>
          <name>M1AR3</name>
          <addressOffset>0x68</addressOffset>
          <size>0x20</size>
        </register>
        <register>
          <name>M1AR3</name>
          <addressOffset>0x68</addressOffset>
          <size>0x20</size>
        </register>
        <register>
          <name>FCR3</name>
          <addressOffset>0x6c</addressOffset>
          <size>0x20</size>
        </register>
        <register>
          <name>FCR3</name>
          <addressOffset>0x6c</addressOffset>
          <size>0x20</size>
        </register>
        <register>
          <name>CR4</name>
          <addressOffset>0x70</addressOffset>
          <size>0x20</size>
        </register>
        <register>
          <name>CR4</name>
          <addressOffset>0x70</addressOffset>
          <size>0x20</size>
        </register>
        <register>
          <name>NDTR4</name>
          <addressOffset>0x74</addressOffset>
          <size>0x20</size>
        </register>
        <register>
          <name>NDTR4</name>
          <addressOffset>0x74</addressOffset>
          <size>0x20</size>
        </register>
        <register>
          <name>PAR4</name>
          <addressOffset>0x78</addressOffset>
          <size>0x20</size>
        </register>
        <register>
          <name>PAR4</name>
          <addressOffset>0x78</addressOffset>
          <size>0x20</size>
        </register>
        <register>
          <name>M0AR4</name>
          <addressOffset>0x7c</addressOffset>
          <size>0x20</size>
        </register>
        <register>
          <name>M0AR4</name>
          <addressOffset>0x7c</addressOffset>
          <size>0x20</size>
        </register>
        <register>
          <name>M1AR4</name>
          <addressOffset>0x80</addressOffset>
          <size>0x20</size>
        </register>
        <register>
          <name>M1AR4</name>
          <addressOffset>0x80</addressOffset>
          <size>0x20</size>
        </register>
        <register>
          <name>FCR4</name>
          <addressOffset>0x84</addressOffset>
          <size>0x20</size>
        </register>
        <register>
          <name>FCR4</name>
          <addressOffset>0x84</addressOffset>
          <size>0x20</size>
        </register>
        <register>
          <name>CR5</name>
          <addressOffset>0x88</addressOffset>
          <size>0x20</size>
        </register>
        <register>
          <name>CR5</name>
          <addressOffset>0x88</addressOffset>
          <size>0x20</size>
        </register>
        <register>
          <name>NDTR5</name>
          <addressOffset>0x8c</addressOffset>
          <size>0x20</size>
        </register>
        <register>
          <name>NDTR5</name>
          <addressOffset>0x8c</addressOffset>
          <size>0x20</size>
        </register>
        <register>
          <name>PAR5</name>
          <addressOffset>0x90</addressOffset>
          <size>0x20</size>
        </register>
        <register>
          <name>PAR5</name>
          <addressOffset>0x90</addressOffset>
          <size>0x20</size>
        </register>
        <register>
          <name>M0AR5</name>
          <addressOffset>0x94</addressOffset>
          <size>0x20</size>
        </register>
        <register>
          <name>M0AR5</name>
          <addressOffset>0x94</addressOffset>
          <size>0x20</size>
        </register>
        <register>
          <name>M1AR5</name>
          <addressOffset>0x98</addressOffset>
          <size>0x20</size>
        </register>
        <register>
          <name>M1AR5</name>
          <addressOffset>0x98</addressOffset>
          <size>0x20</size>
        </register>
        <register>
          <name>FCR5</name>
          <addressOffset>0x9c</addressOffset>
          <size>0x20</size>
        </register>
        <register>
          <name>FCR5</name>
          <addressOffset>0x9c</addressOffset>
          <size>0x20</size>
        </register>
        <register>
          <name>CR6</name>
          <addressOffset>0xa0</addressOffset>
          <size>0x20</size>
        </register>
        <register>
          <name>CR6</name>
          <addressOffset>0xa0</addressOffset>
          <size>0x20</size>
        </register>
        <register>
          <name>NDTR6</name>
          <addressOffset>0xa4</addressOffset>
          <size>0x20</size>
        </register>
        <register>
          <name>NDTR6</name>
          <addressOffset>0xa4</addressOffset>
          <size>0x20</size>
        </register>
        <register>
          <name>PAR6</name>
          <addressOffset>0xa8</addressOffset>
          <size>0x20</size>
        </register>
        <register>
          <name>PAR6</name>
          <addressOffset>0xa8</addressOffset>
          <size>0x20</size>
        </register>
        <register>
          <name>M0AR6</name>
          <addressOffset>0xac</addressOffset>
          <size>0x20</size>
        </register>
        <register>
          <name>M0AR6</name>
          <addressOffset>0xac</addressOffset>
          <size>0x20</size>
        </register>
        <register>
          <name>M1AR6</name>
          <addressOffset>0xb0</addressOffset>
          <size>0x20</size>
        </register>
        <register>
          <name>M1AR6</name>
          <addressOffset>0xb0</addressOffset>
          <size>0x20</size>
        </register>
        <register>
          <name>FCR6</name>
          <addressOffset>0xb4</addressOffset>
          <size>0x20</size>
        </register>
        <register>
          <name>FCR6</name>
          <addressOffset>0xb4</addressOffset>
          <size>0x20</size>
        </register>
        <register>
          <name>CR7</name>
          <addressOffset>0xb8</addressOffset>
          <size>0x20</size>
        </register>
        <register>
          <name>CR7</name>
          <addressOffset>0xb8</addressOffset>
          <size>0x20</size>
        </register>
        <register>
          <name>NDTR7</name>
          <addressOffset>0xbc</addressOffset>
          <size>0x20</size>
        </register>
        <register>
          <name>NDTR7</name>
          <addressOffset>0xbc</addressOffset>
          <size>0x20</size>
        </register>
        <register>
          <name>PAR7</name>
          <addressOffset>0xc0</addressOffset>
          <size>0x20</size>
        </register>
        <register>
          <name>PAR7</name>
          <addressOffset>0xc0</addressOffset>
          <size>0x20</size>
        </register>
        <register>
          <name>M0AR7</name>
          <addressOffset>0xc4</addressOffset>
          <size>0x20</size>
        </register>
        <register>
          <name>M0AR7</name>
          <addressOffset>0xc4</addressOffset>
          <size>0x20</size>
        </register>
        <register>
          <name>M1AR7</name>
          <addressOffset>0xc8</addressOffset>
          <size>0x20</size>
        </register>
        <register>
          <name>M1AR7</name>
          <addressOffset>0xc8</addressOffset>
          <size>0x20</size>
        </register>
        <register>
          <name>FCR7</name>
          <addressOffset>0xcc</addressOffset>
          <size>0x20</size>
        </register>
        <register>
          <name>FCR7</name>
          <addressOffset>0xcc</addressOffset>
          <size>0x20</size>
        </register>
      </registers>
    </peripheral>
    <peripheral>
      <name>DMA2</name>
      <baseAddress>0x40026400</baseAddress>
      <registers>
        <register>
          <name>LISR</name>
          <addressOffset>0x0</addressOffset>
          <size>0x20</size>
          <fields>
            <field>
              <name>FEIF0</name>
              <bitOffset>0</bitOffset>
              <bitWidth>1</bitWidth>
            </field>
            <field>
              <name>DMEIF0</name>
              <bitOffset>2</bitOffset>
              <bitWidth>1</bitWidth>
            </field>
            <field>
              <name>TEIF0</name>
              <bitOffset>3</bitOffset>
              <bitWidth>1</bitWidth>
            </field>
            <field>
              <name>HTIF0</name>
              <bitOffset>4</bitOffset>
              <bitWidth>1</bitWidth>
            </field>
            <field>
              <name>TCIF0</name>
              <bitOffset>5</bitOffset>
              <bitWidth>1</bitWidth>
            </field>
            <field>
              <name>FEIF1</name>
              <bitOffset>6</bitOffset>
              <bitWidth>1</bitWidth>
            </field>
            <field>
              <name>DMEIF1</name>
              <bitOffset>8</bitOffset>
              <bitWidth>1</bitWidth>
            </field>
            <field>
              <name>TEIF1</name>
              <bitOffset>9</bitOffset>
              <bitWidth>1</bitWidth>
            </field>
            <field>
              <name>HTIF1</name>
              <bitOffset>10</bitOffset>
              <bitWidth>1</bitWidth>
            </field>
            <field>
              <name>TCIF1</name>
              <bitOffset>11</bitOffset>
              <bitWidth>1</bitWidth>
            </field>
            <field>
              <name>FEIF2</name>
              <bitOffset>16</bitOffset>
              <bitWidth>1</bitWidth>
            </field>
            <field>
              <name>DMEIF2</name>
              <bitOffset>18</bitOffset>
              <bitWidth>1</bitWidth>
            </field>
            <field>
              <name>TEIF2</name>
              <bitOffset>19</bitOffset>
              <bitWidth>1</bitWidth>
            </field>
            <field>
              <name>HTIF2</name>
              <bitOffset>20</bitOffset>
              <bitWidth>1</bitWidth>
            </field>
            <field>
              <name>TCIF2</name>
              <bitOffset>21</bitOffset>
              <bitWidth>1</bitWidth>
            </field>
            <field>
              <name>FEIF3</name>
              <bitOffset>22</bitOffset>
              <bitWidth>1</bitWidth>
            </field>
            <field>
              <name>DMEIF3</name>
              <bitOffset>24</bitOffset>
              <bitWidth>1</bitWidth>
            </field>
            <field>
              <name>TEIF3</name>
              <bitOffset>25</bitOffset>
              <bitWidth>1</bitWidth>
            </field>
            <field>
              <name>HTIF3</name>
              <bitOffset>26</bitOffset>
              <bitWidth>1</bitWidth>
            </field>
            <field>
              <name>TCIF3</name>
              <bitOffset>27</bitOffset>
              <bitWidth>1</bitWidth>
            </field>
          </fields>
        </register>
        <register>
          <name>HISR</name>
          <addressOffset>0x4</addressOffset>
          <size>0x20</size>
          <fields>
            <field>
              <name>FEIF4</name>
              <bitOffset>0</bitOffset>
              <bitWidth>1</bitWidth>
            </field>
            <field>
              <name>DMEIF4</name>
              <bitOffset>2</bitOffset>
              <bitWidth>1</bitWidth>
            </field>
            <field>
              <name>TEIF4</name>
              <bitOffset>3</bitOffset>
              <bitWidth>1</bitWidth>
            </field>
            <field>
              <name>HTIF4</name>
              <bitOffset>4</bitOffset>
              <bitWidth>1</bitWidth>
            </field>
            <field>
              <name>TCIF4</name>
              <bitOffset>5</bitOffset>
              <bitWidth>1</bitWidth>
            </field>
            <field>
              <name>FEIF5</name>
              <bitOffset>6</bitOffset>
              <bitWidth>1</bitWidth>
            </field>
            <field>
              <name>DMEIF5</name>
              <bitOffset>8</bitOffset>
              <bitWidth>1</bitWidth>
            </field>
            <field>
              <name>TEIF5</name>
              <bitOffset>9</bitOffset>
              <bitWidth>1</bitWidth>
            </field>
            <field>
              <name>HTIF5</name>
              <bitOffset>10</bitOffset>
              <bitWidth>1</bitWidth>
            </field>
            <field>
              <name>TCIF5</name>
              <bitOffset>11</bitOffset>
              <bitWidth>1</bitWidth>
            </field>
            <field>
              <name>FEIF6</name>
              <bitOffset>16</bitOffset>
              <bitWidth>1</bitWidth>
            </field>
            <field>
              <name>DMEIF6</name>
              <bitOffset>18</bitOffset>
              <bitWidth>1</bitWidth>
            </field>
            <field>
              <name>TEIF6</name>
              <bitOffset>19</bitOffset>
              <bitWidth>1</bitWidth>
            </field>
            <field>
              <name>HTIF6</name>
              <bitOffset>20</bitOffset>
              <bitWidth>1</bitWidth>
            </field>
            <field>
              <name>TCIF6</name>
              <bitOffset>21</bitOffset>
              <bitWidth>1</bitWidth>
            </field>
            <field>
              <name>FEIF7</name>
              <bitOffset>22</bitOffset>
              <bitWidth>1</bitWidth>
            </field>
            <field>
              <name>DMEIF7</name>
              <bitOffset>24</bitOffset>
              <bitWidth>1</bitWidth>
            </field>
            <field>
              <name>TEIF7</name>
              <bitOffset>25</bitOffset>
              <bitWidth>1</bitWidth>
            </field>
            <field>
              <name>HTIF7</name>
              <bitOffset>26</bitOffset>
              <bitWidth>1</bitWidth>
            </field>
            <field>
              <name>TCIF7</name>
              <bitOffset>27</bitOffset>
              <bitWidth>1</bitWidth>
            </field>
          </fields>
        </register>
        <register>
          <name>LIFCR</name>
          <addressOffset>0x8</addressOffset>
          <size>0x20</size>
          <fields>
            <field>
              <name>CFEIF0</name>
              <bitOffset>0</bitOffset>
              <bitWidth>1</bitWidth>
            </field>
            <field>
              <name>CDMEIF0</name>
              <bitOffset>2</bitOffset>
              <bitWidth>1</bitWidth>
            </field>
            <field>
              <name>CTEIF0</name>
              <bitOffset>3</bitOffset>
              <bitWidth>1</bitWidth>
            </field>
            <field>
              <name>CHTIF0</name>
              <bitOffset>4</bitOffset>
              <bitWidth>1</bitWidth>
            </field>
            <field>
              <name>CTCIF0</name>
              <bitOffset>5</bitOffset>
              <bitWidth>1</bitWidth>
            </field>
            <field>
              <name>CFEIF1</name>
              <bitOffset>6</bitOffset>
              <bitWidth>1</bitWidth>
            </field>
            <field>
              <name>CDMEIF1</name>
              <bitOffset>8</bitOffset>
              <bitWidth>1</bitWidth>
            </field>
            <field>
              <name>CTEIF1</name>
              <bitOffset>9</bitOffset>
              <bitWidth>1</bitWidth>
            </field>
            <field>
              <name>CHTIF1</name>
              <bitOffset>10</bitOffset>
              <bitWidth>1</bitWidth>
            </field>
            <field>
              <name>CTCIF1</name>
              <bitOffset>11</bitOffset>
              <bitWidth>1</bitWidth>
            </field>
            <field>
              <name>CFEIF2</name>
              <bitOffset>16</bitOffset>
              <bitWidth>1</bitWidth>
            </field>
            <field>
              <name>CDMEIF2</name>
              <bitOffset>18</bitOffset>
              <bitWidth>1</bitWidth>
            </field>
            <field>
              <name>CTEIF2</name>
              <bitOffset>19</bitOffset>
              <bitWidth>1</bitWidth>
            </field>
            <field>
              <name>CHTIF2</name>
              <bitOffset>20</bitOffset>
              <bitWidth>1</bitWidth>
            </field>
            <field>
              <name>CTCIF2</name>
              <bitOffset>21</bitOffset>
              <bitWidth>1</bitWidth>
            </field>
            <field>
              <name>CFEIF3</name>
              <bitOffset>22</bitOffset>
              <bitWidth>1</bitWidth>
            </field>
            <field>
              <name>CDMEIF3</name>
              <bitOffset>24</bitOffset>
              <bitWidth>1</bitWidth>
            </field>
            <field>
              <name>CTEIF3</name>
              <bitOffset>25</bitOffset>
              <bitWidth>1</bitWidth>
            </field>
            <field>
              <name>CHTIF3</name>
              <bitOffset>26</bitOffset>
              <bitWidth>1</bitWidth>
            </field>
            <field>
              <name>CTCIF3</name>
              <bitOffset>27</bitOffset>
              <bitWidth>1</bitWidth>
            </field>
          </fields>
        </register>
        <register>
          <name>HIFCR</name>
          <addressOffset>0xc</addressOffset>
          <size>0x20</size>
          <fields>
            <field>
              <name>CFEIF4</name>
              <bitOffset>0</bitOffset>
              <bitWidth>1</bitWidth>
            </field>
            <field>
              <name>CDMEIF4</name>
              <bitOffset>2</bitOffset>
              <bitWidth>1</bitWidth>
            </field>
            <field>
              <name>CTEIF4</name>
              <bitOffset>3</bitOffset>
              <bitWidth>1</bitWidth>
            </field>
            <field>
              <name>CHTIF4</name>
              <bitOffset>4</bitOffset>
              <bitWidth>1</bitWidth>
            </field>
            <field>
              <name>CTCIF4</name>
              <bitOffset>5</bitOffset>
              <bitWidth>1</bitWidth>
            </field>
            <field>
              <name>CFEIF5</name>
              <bitOffset>6</bitOffset>
              <bitWidth>1</bitWidth>
            </field>
            <field>
              <name>CDMEIF5</name>
              <bitOffset>8</bitOffset>
              <bitWidth>1</bitWidth>
            </field>
            <field>
              <name>CTEIF5</name>
              <bitOffset>9</bitOffset>
              <bitWidth>1</bitWidth>
            </field>
            <field>
              <name>CHTIF5</name>
              <bitOffset>10</bitOffset>
              <bitWidth>1</bitWidth>
            </field>
            <field>
              <name>CTCIF5</name>
              <bitOffset>11</bitOffset>
              <bitWidth>1</bitWidth>
            </field>
            <field>
              <name>CFEIF6</name>
              <bitOffset>16</bitOffset>
              <bitWidth>1</bitWidth>
            </field>
            <field>
              <name>CDMEIF6</name>
              <bitOffset>18</bitOffset>
              <bitWidth>1</bitWidth>
            </field>
            <field>
              <name>CTEIF6</name>
              <bitOffset>19</bitOffset>
              <bitWidth>1</bitWidth>
            </field>
            <field>
              <name>CHTIF6</name>
              <bitOffset>20</bitOffset>
              <bitWidth>1</bitWidth>
            </field>
            <field>
              <name>CTCIF6</name>
              <bitOffset>21</bitOffset>
              <bitWidth>1</bitWidth>
            </field>
            <field>
              <name>CFEIF7</name>
              <bitOffset>22</bitOffset>
              <bitWidth>1</bitWidth>
            </field>
            <field>
              <name>CDMEIF7</name>
              <bitOffset>24</bitOffset>
              <bitWidth>1</bitWidth>
            </field>
            <field>
              <name>CTEIF7</name>
              <bitOffset>25</bitOffset>
              <bitWidth>1</bitWidth>
            </field>
            <field>
              <name>CHTIF7</name>
              <bitOffset>26</bitOffset>
              <bitWidth>1</bitWidth>
            </field>
            <field>
              <name>CTCIF7</name>
              <bitOffset>27</bitOffset>
              <bitWidth>1</bitWidth>
            </field>
          </fields>
        </register>
        <register>
          <name>CR0</name>
          <addressOffset>0x10</addressOffset>
          <size>0x20</size>
        </register>
        <register>
          <name>CR0</name>
          <addressOffset>0x10</addressOffset>
          <size>0x20</size>
        </register>
        <register>
          <name>NDTR0</name>
          <addressOffset>0x14</addressOffset>
          <size>0x20</size>
        </register>
        <register>
          <name>NDTR0</name>
          <addressOffset>0x14</addressOffset>
          <size>0x20</size>
        </register>
        <register>
          <name>PAR0</name>
          <addressOffset>0x18</addressOffset>
          <size>0x20</size>
        </register>
        <register>
          <name>PAR0</name>
          <addressOffset>0x18</addressOffset>
          <size>0x20</size>
        </register>
        <register>
          <name>M0AR0</name>
          <addressOffset>0x1c</addressOffset>
          <size>0x20</size>
        </register>
        <register>
          <name>M0AR0</name>
          <addressOffset>0x1c</addressOffset>
          <size>0x20</size>
        </register>
        <register>
          <name>M1AR0</name>
          <addressOffset>0x20</addressOffset>
          <size>0x20</size>
        </register>
        <register>
          <name>M1AR0</name>
          <addressOffset>0x20</addressOffset>
          <size>0x20</size>
        </register>
        <register>
          <name>FCR0</name>
          <addressOffset>0x24</addressOffset>
          <size>0x20</size>
        </register>
        <register>
          <name>FCR0</name>
          <addressOffset>0x24</addressOffset>
          <size>0x20</size>
        </register>
        <register>
          <name>CR1</name>
          <addressOffset>0x28</addressOffset>
          <size>0x20</size>
        </register>
        <register>
          <name>CR1</name>
          <addressOffset>0x28</addressOffset>
          <size>0x20</size>
        </register>
        <register>
          <name>NDTR1</name>
          <addressOffset>0x2c</addressOffset>
          <size>0x20</size>
        </register>
        <register>
          <name>NDTR1</name>
          <addressOffset>0x2c</addressOffset>
          <size>0x20</size>
        </register>
        <register>
          <name>PAR1</name>
          <addressOffset>0x30</addressOffset>
          <size>0x20</size>
        </register>
        <register>
          <name>PAR1</name>
          <addressOffset>0x30</addressOffset>
          <size>0x20</size>
        </register>
        <register>
          <name>M0AR1</name>
          <addressOffset>0x34</addressOffset>
          <size>0x20</size>
        </register>
        <register>
          <name>M0AR1</name>
          <addressOffset>0x34</addressOffset>
          <size>0x20</size>
        </register>
        <register>
          <name>M1AR1</name>
          <addressOffset>0x38</addressOffset>
          <size>0x20</size>
        </register>
        <register>
          <name>M1AR1</name>
          <addressOffset>0x38</addressOffset>
          <size>0x20</size>
        </register>
        <register>
          <name>FCR1</name>
          <addressOffset>0x3c</addressOffset>
          <size>0x20</size>
        </register>
        <register>
          <name>FCR1</name>
          <addressOffset>0x3c</addressOffset>
          <size>0x20</size>
        </register>
        <register>
          <name>CR2</name>
          <addressOffset>0x40</addressOffset>
          <size>0x20</size>
        </register>
        <register>
          <name>CR2</name>
          <addressOffset>0x40</addressOffset>
          <size>0x20</size>
        </register>
        <register>
          <name>NDTR2</name>
          <addressOffset>0x44</addressOffset>
          <size>0x20</size>
        </register>
        <register>
          <name>NDTR2</name>
          <addressOffset>0x44</addressOffset>
          <size>0x20</size>
        </register>
        <register>
          <name>PAR2</name>
          <addressOffset>0x48</addressOffset>
          <size>0x20</size>
        </register>
        <register>
          <name>PAR2</name>
          <addressOffset>0x48</addressOffset>
          <size>0x20</size>
        </register>
        <register>
          <name>M0AR2</name>
          <addressOffset>0x4c</addressOffset>
          <size>0x20</size>
        </register>
        <register>
          <name>M0AR2</name>
          <addressOffset>0x4c</addressOffset>
          <size>0x20</size>
        </register>
        <register>
          <name>M1AR2</name>
          <addressOffset>0x50</addressOffset>
          <size>0x20</size>
        </register>
        <register>
          <name>M1AR2</name>
          <addressOffset>0x50</addressOffset>
          <size>0x20</size>
        </register>
        <register>
          <name>FCR2</name>
          <addressOffset>0x54</addressOffset>
          <size>0x20</size>
        </register>
        <register>
          <name>FCR2</name>
          <addressOffset>0x54</addressOffset>
          <size>0x20</size>
        </register>
        <register>
          <name>CR3</name>
          <addressOffset>0x58</addressOffset>
          <size>0x20</size>
        </register>
        <register>
          <name>CR3</name>
          <addressOffset>0x58</addressOffset>
          <size>0x20</size>
        </register>
        <register>
          <name>NDTR3</name>
          <addressOffset>0x5c</addressOffset>
          <size>0x20</size>
        </register>
        <register>
          <name>NDTR3</name>
          <addressOffset>0x5c</addressOffset>
          <size>0x20</size>
        </register>
        <register>
          <name>PAR3</name>
          <addressOffset>0x60</addressOffset>
          <size>0x20</size>
        </register>
        <register>
          <name>PAR3</name>
          <addressOffset>0x60</addressOffset>
          <size>0x20</size>
        </register>
        <register>
          <name>M0AR3</name>
          <addressOffset>0x64</addressOffset>
          <size>0x20</size>
        </register>
        <register>
          <name>M0AR3</name>
          <addressOffset>0x64</addressOffset>
          <size>0x20</size>
        </register>
        <register>
          <name>M1AR3</name>
          <addressOffset>0x68</addressOffset>
          <size>0x20</size>
        </register>
        <register>
          <name>M1AR3</name>
          <addressOffset>0x68</addressOffset>
          <size>0x20</size>
        </register>
        <register>
          <name>FCR3</name>
          <addressOffset>0x6c</addressOffset>
          <size>0x20</size>
        </register>
        <register>
          <name>FCR3</name>
          <addressOffset>0x6c</addressOffset>
          <size>0x20</size>
        </register>
        <register>
          <name>CR4</name>
          <addressOffset>0x70</addressOffset>
          <size>0x20</size>
        </register>
        <register>
          <name>CR4</name>
          <addressOffset>0x70</addressOffset>
          <size>0x20</size>
        </register>
        <register>
          <name>NDTR4</name>
          <addressOffset>0x74</addressOffset>
          <size>0x20</size>
        </register>
        <register>
          <name>NDTR4</name>
          <addressOffset>0x74</addressOffset>
          <size>0x20</size>
        </register>
        <register>
          <name>PAR4</name>
          <addressOffset>0x78</addressOffset>
          <size>0x20</size>
        </register>
        <register>
          <name>PAR4</name>
          <addressOffset>0x78</addressOffset>
          <size>0x20</size>
        </register>
        <register>
          <name>M0AR4</name>
          <addressOffset>0x7c</addressOffset>
          <size>0x20</size>
        </register>
        <register>
          <name>M0AR4</name>
          <addressOffset>0x7c</addressOffset>
          <size>0x20</size>
        </register>
        <register>
          <name>M1AR4</name>
          <addressOffset>0x80</addressOffset>
          <size>0x20</size>
        </register>
        <register>
          <name>M1AR4</name>
          <addressOffset>0x80</addressOffset>
          <size>0x20</size>
        </register>
        <register>
          <name>FCR4</name>
          <addressOffset>0x84</addressOffset>
          <size>0x20</size>
        </register>
        <register>
          <name>FCR4</name>
          <addressOffset>0x84</addressOffset>
          <size>0x20</size>
        </register>
        <register>
          <name>CR5</name>
          <addressOffset>0x88</addressOffset>
          <size>0x20</size>
        </register>
        <register>
          <name>CR5</name>
          <addressOffset>0x88</addressOffset>
          <size>0x20</size>
        </register>
        <register>
          <name>NDTR5</name>
          <addressOffset>0x8c</addressOffset>
          <size>0x20</size>
        </register>
        <register>
          <name>NDTR5</name>
          <addressOffset>0x8c</addressOffset>
          <size>0x20</size>
        </register>
        <register>
          <name>PAR5</name>
          <addressOffset>0x90</addressOffset>
          <size>0x20</size>
        </register>
        <register>
          <name>PAR5</name>
          <addressOffset>0x90</addressOffset>
          <size>0x20</size>
        </register>
        <register>
          <name>M0AR5</name>
          <addressOffset>0x94</addressOffset>
          <size>0x20</size>
        </register>
        <register>
          <name>M0AR5</name>
          <addressOffset>0x94</addressOffset>
          <size>0x20</size>
        </register>
        <register>
          <name>M1AR5</name>
          <addressOffset>0x98</addressOffset>
          <size>0x20</size>
        </register>
        <register>
          <name>M1AR5</name>
          <addressOffset>0x98</addressOffset>
          <size>0x20</size>
        </register>
        <register>
          <name>FCR5</name>
          <addressOffset>0x9c</addressOffset>
          <size>0x20</size>
        </register>
        <register>
          <name>FCR5</name>
          <addressOffset>0x9c</addressOffset>
          <size>0x20</size>
        </register>
        <register>
          <name>CR6</name>
          <addressOffset>0xa0</addressOffset>
          <size>0x20</size>
        </register>
        <register>
          <name>CR6</name>
          <addressOffset>0xa0</addressOffset>
          <size>0x20</size>
        </register>
        <register>
          <name>NDTR6</name>
          <addressOffset>0xa4</addressOffset>
          <size>0x20</size>
        </register>
        <register>
          <name>NDTR6</name>
          <addressOffset>0xa4</addressOffset>
          <size>0x20</size>
        </register>
        <register>
          <name>PAR6</name>
          <addressOffset>0xa8</addressOffset>
          <size>0x20</size>
        </register>
        <register>
          <name>PAR6</name>
          <addressOffset>0xa8</addressOffset>
          <size>0x20</size>
        </register>
        <register>
          <name>M0AR6</name>
          <addressOffset>0xac</addressOffset>
          <size>0x20</size>
        </register>
        <register>
          <name>M0AR6</name>
          <addressOffset>0xac</addressOffset>
          <size>0x20</size>
        </register>
        <register>
          <name>M1AR6</name>
          <addressOffset>0xb0</addressOffset>
          <size>0x20</size>
        </register>
        <register>
          <name>M1AR6</name>
          <addressOffset>0xb0</addressOffset>
          <size>0x20</size>
        </register>
        <register>
          <name>FCR6</name>
          <addressOffset>0xb4</addressOffset>
          <size>0x20</size>
        </register>
        <register>
          <name>FCR6</name>
          <addressOffset>0xb4</addressOffset>
          <size>0x20</size>
        </register>
        <register>
          <name>CR7</name>
          <addressOffset>0xb8</addressOffset>
          <size>0x20</size>
        </register>
        <register>
          <name>CR7</name>
          <addressOffset>0xb8</addressOffset>
          <size>0x20</size>
        </register>
        <register>
          <name>NDTR7</name>
          <addressOffset>0xbc</addressOffset>
          <size>0x20</size>
        </register>
        <register>
          <name>NDTR7</name>
          <addressOffset>0xbc</addressOffset>
          <size>0x20</size>
        </register>
        <register>
          <name>PAR7</name>
          <addressOffset>0xc0</addressOffset>
          <size>0x20</size>
        </register>
        <register>
          <name>PAR7</name>
          <addressOffset>0xc0</addressOffset>
          <size>0x20</size>
        </register>
        <register>
          <name>M0AR7</name>
          <addressOffset>0xc4</addressOffset>
          <size>0x20</size>
        </register>
        <register>
          <name>M0AR7</name>
          <addressOffset>0xc4</addressOffset>
          <size>0x20</size>
        </register>
        <register>
          <name>M1AR7</name>
          <addressOffset>0xc8</addressOffset>
          <size>0x20</size>
        </register>
        <register>
          <name>M1AR7</name>
          <addressOffset>0xc8</addressOffset>
          <size>0x20</size>
        </register>
        <register>
          <name>FCR7</name>
          <addressOffset>0xcc</addressOffset>
          <size>0x20</size>
        </register>
        <register>
          <name>FCR7</name>
          <addressOffset>0xcc</addressOffset>
          <size>0x20</size>
        </register>
      </registers>
    </peripheral>
    <peripheral>
      <name>ETH</name>
      <baseAddress>0x40028000</baseAddress>
      <registers>
        <register>
          <name>MACCR</name>
          <addressOffset>0x0</addressOffset>
          <size>0x20</size>
          <fields>
            <field>
              <name>RE</name>
              <bitOffset>2</bitOffset>
              <bitWidth>1</bitWidth>
            </field>
            <field>
              <name>TE</name>
              <bitOffset>3</bitOffset>
              <bitWidth>1</bitWidth>
            </field>
            <field>
              <name>DC</name>
              <bitOffset>4</bitOffset>
              <bitWidth>1</bitWidth>
            </field>
            <field>
              <name>BL</name>
              <bitOffset>5</bitOffset>
              <bitWidth>2</bitWidth>
            </field>
            <field>
              <name>APCS</name>
              <bitOffset>7</bitOffset>
              <bitWidth>1</bitWidth>
            </field>
            <field>
              <name>RD</name>
              <bitOffset>9</bitOffset>
              <bitWidth>1</bitWidth>
            </field>
            <field>
              <name>IPCO</name>
              <bitOffset>10</bitOffset>
              <bitWidth>1</bitWidth>
            </field>
            <field>
              <name>DM</name>
              <bitOffset>11</bitOffset>
              <bitWidth>1</bitWidth>
            </field>
            <field>
              <name>LM</name>
              <bitOffset>12</bitOffset>
              <bitWidth>1</bitWidth>
            </field>
            <field>
              <name>ROD</name>
              <bitOffset>13</bitOffset>
              <bitWidth>1</bitWidth>
            </field>
            <field>
              <name>FES</name>
              <bitOffset>14</bitOffset>
              <bitWidth>1</bitWidth>
            </field>
            <field>
              <name>CSD</name>
              <bitOffset>16</bitOffset>
              <bitWidth>1</bitWidth>
            </field>
            <field>
              <name>IFG</name>
              <bitOffset>17</bitOffset>
              <bitWidth>3</bitWidth>
            </field>
            <field>
              <name>JD</name>
              <bitOffset>22</bitOffset>
              <bitWidth>1</bitWidth>
            </field>
            <field>
              <name>WD</name>
              <bitOffset>23</bitOffset>
              <bitWidth>1</bitWidth>
            </field>
          </fields>
        </register>
        <register>
          <name>MACFFR</name>
          <addressOffset>0x4</addressOffset>
          <size>0x20</size>
          <fields>
            <field>
              <name>PM</name>
              <bitOffset>0</bitOffset>
              <bitWidth>1</bitWidth>
            </field>
            <field>
              <name>HU</name>
              <bitOffset>1</bitOffset>
              <bitWidth>1</bitWidth>
            </field>
            <field>
              <name>HM</name>
              <bitOffset>2</bitOffset>
              <bitWidth>1</bitWidth>
            </field>
            <field>
              <name>DAIF</name>
              <bitOffset>3</bitOffset>
              <bitWidth>1</bitWidth>
            </field>
            <field>
              <name>PAM</name>
              <bitOffset>4</bitOffset>
              <bitWidth>1</bitWidth>
            </field>
            <field>
              <name>BFD</name>
              <bitOffset>5</bitOffset>
              <bitWidth>1</bitWidth>
            </field>
            <field>
              <name>PCF_ForwardPassedAddrFilter</name>
              <bitOffset>6</bitOffset>
              <bitWidth>2</bitWidth>
            </field>
            <field>
              <name>PCF_ForwardAll</name>
              <bitOffset>7</bitOffset>
              <bitWidth>1</bitWidth>
            </field>
            <field>
              <name>SAIF</name>
              <bitOffset>8</bitOffset>
              <bitWidth>1</bitWidth>
            </field>
            <field>
              <name>SAF</name>
              <bitOffset>9</bitOffset>
              <bitWidth>1</bitWidth>
            </field>
            <field>
              <name>HPF</name>
              <bitOffset>10</bitOffset>
              <bitWidth>1</bitWidth>
            </field>
            <field>
              <name>RA</name>
              <bitOffset>31</bitOffset>
              <bitWidth>1</bitWidth>
            </field>
          </fields>
        </register>
        <register>
          <name>MACHTHR</name>
          <addressOffset>0x8</addressOffset>
          <size>0x20</size>
          <fields>
            <field>
              <name>HTH</name>
              <bitOffset>0</bitOffset>
              <bitWidth>32</bitWidth>
            </field>
          </fields>
        </register>
        <register>
          <name>MACHTLR</name>
          <addressOffset>0xc</addressOffset>
          <size>0x20</size>
          <fields>
            <field>
              <name>HTL</name>
              <bitOffset>0</bitOffset>
              <bitWidth>32</bitWidth>
            </field>
          </fields>
        </register>
        <register>
          <name>MACMIIAR</name>
          <addressOffset>0x10</addressOffset>
          <size>0x20</size>
          <fields>
            <field>
              <name>MB</name>
              <bitOffset>0</bitOffset>
              <bitWidth>1</bitWidth>
            </field>
            <field>
              <name>MW</name>
              <bitOffset>1</bitOffset>
              <bitWidth>1</bitWidth>
            </field>
            <field>
              <name>CR_Div62</name>
              <bitOffset>2</bitOffset>
              <bitWidth>1</bitWidth>
            </field>
            <field>
              <name>CR_Div16</name>
              <bitOffset>3</bitOffset>
              <bitWidth>1</bitWidth>
            </field>
            <field>
              <name>CR_Div102</name>
              <bitOffset>4</bitOffset>
              <bitWidth>1</bitWidth>
            </field>
            <field>
              <name>MR</name>
              <bitOffset>6</bitOffset>
              <bitWidth>5</bitWidth>
            </field>
            <field>
              <name>PA</name>
              <bitOffset>11</bitOffset>
              <bitWidth>5</bitWidth>
            </field>
          </fields>
        </register>
        <register>
          <name>MACMIIDR</name>
          <addressOffset>0x14</addressOffset>
          <size>0x20</size>
          <fields>
            <field>
              <name>MD</name>
              <bitOffset>0</bitOffset>
              <bitWidth>16</bitWidth>
            </field>
          </fields>
        </register>
        <register>
          <name>MACFCR</name>
          <addressOffset>0x18</addressOffset>
          <size>0x20</size>
          <fields>
            <field>
              <name>FCBBPA</name>
              <bitOffset>0</bitOffset>
              <bitWidth>1</bitWidth>
            </field>
            <field>
              <name>TFCE</name>
              <bitOffset>1</bitOffset>
              <bitWidth>1</bitWidth>
            </field>
            <field>
              <name>RFCE</name>
              <bitOffset>2</bitOffset>
              <bitWidth>1</bitWidth>
            </field>
            <field>
              <name>UPFD</name>
              <bitOffset>3</bitOffset>
              <bitWidth>1</bitWidth>
            </field>
            <field>
              <name>PLT_Minus28</name>
              <bitOffset>4</bitOffset>
              <bitWidth>1</bitWidth>
            </field>
            <field>
              <name>PLT_Minus144</name>
              <bitOffset>5</bitOffset>
              <bitWidth>1</bitWidth>
            </field>
            <field>
              <name>ZQPD</name>
              <bitOffset>7</bitOffset>
              <bitWidth>1</bitWidth>
            </field>
            <field>
              <name>PT</name>
              <bitOffset>16</bitOffset>
              <bitWidth>16</bitWidth>
            </field>
          </fields>
        </register>
        <register>
          <name>MACVLANTR</name>
          <addressOffset>0x1c</addressOffset>
          <size>0x20</size>
          <fields>
            <field>
              <name>VLANTI</name>
              <bitOffset>0</bitOffset>
              <bitWidth>16</bitWidth>
            </field>
            <field>
              <name>VLANTC</name>
              <bitOffset>16</bitOffset>
              <bitWidth>1</bitWidth>
            </field>
          </fields>
        </register>
        <register>
          <name>MACRWUFFR</name>
          <addressOffset>0x28</addressOffset>
          <size>0x20</size>
          <fields>
            <field>
              <name>D</name>
              <bitOffset>0</bitOffset>
              <bitWidth>32</bitWidth>
            </field>
          </fields>
        </register>
        <register>
          <name>MACPMTCSR</name>
          <addressOffset>0x2c</addressOffset>
          <size>0x20</size>
          <fields>
            <field>
              <name>PD</name>
              <bitOffset>0</bitOffset>
              <bitWidth>1</bitWidth>
            </field>
            <field>
              <name>MPE</name>
              <bitOffset>1</bitOffset>
              <bitWidth>1</bitWidth>
            </field>
            <field>
              <name>WFE</name>
              <bitOffset>2</bitOffset>
              <bitWidth>1</bitWidth>
            </field>
            <field>
              <name>MPR</name>
              <bitOffset>5</bitOffset>
              <bitWidth>1</bitWidth>
            </field>
            <field>
              <name>WFR</name>
              <bitOffset>6</bitOffset>
              <bitWidth>1</bitWidth>
            </field>
            <field>
              <name>GU</name>
              <bitOffset>9</bitOffset>
              <bitWidth>1</bitWidth>
            </field>
            <field>
              <name>WFFRPR</name>
              <bitOffset>31</bitOffset>
              <bitWidth>1</bitWidth>
            </field>
          </fields>
        </register>
        <register>
          <name>MACDBGR</name>
          <addressOffset>0x34</addressOffset>
          <size>0x20</size>
          <fields>
            <field>
              <name>MMRPEA</name>
              <bitOffset>0</bitOffset>
              <bitWidth>1</bitWidth>
            </field>
            <field>
              <name>MSFRWCS</name>
              <bitOffset>1</bitOffset>
              <bitWidth>2</bitWidth>
            </field>
            <field>
              <name>RFWRA</name>
              <bitOffset>4</bitOffset>
              <bitWidth>1</bitWidth>
            </field>
            <field>
              <name>RFRCS_FLUSHING</name>
              <bitOffset>5</bitOffset>
              <bitWidth>2</bitWidth>
            </field>
            <field>
              <name>RFRCS_STATUSREADING</name>
              <bitOffset>6</bitOffset>
              <bitWidth>1</bitWidth>
            </field>
            <field>
              <name>RFFL_FULL</name>
              <bitOffset>8</bitOffset>
              <bitWidth>2</bitWidth>
            </field>
            <field>
              <name>RFFL_ABOVEFCT</name>
              <bitOffset>9</bitOffset>
              <bitWidth>1</bitWidth>
            </field>
            <field>
              <name>MMTEA</name>
              <bitOffset>16</bitOffset>
              <bitWidth>1</bitWidth>
            </field>
            <field>
              <name>MTFCS_WAITING</name>
              <bitOffset>17</bitOffset>
              <bitWidth>1</bitWidth>
            </field>
            <field>
              <name>MTFCS_GENERATINGPCF</name>
              <bitOffset>18</bitOffset>
              <bitWidth>1</bitWidth>
            </field>
            <field>
              <name>MTP</name>
              <bitOffset>19</bitOffset>
              <bitWidth>1</bitWidth>
            </field>
            <field>
              <name>TFRS_WRITING</name>
              <bitOffset>20</bitOffset>
              <bitWidth>2</bitWidth>
            </field>
            <field>
              <name>TFRS_WAITING</name>
              <bitOffset>21</bitOffset>
              <bitWidth>1</bitWidth>
            </field>
            <field>
              <name>TFWA</name>
              <bitOffset>22</bitOffset>
              <bitWidth>1</bitWidth>
            </field>
            <field>
              <name>TFNE</name>
              <bitOffset>24</bitOffset>
              <bitWidth>1</bitWidth>
            </field>
            <field>
              <name>TFF</name>
              <bitOffset>25</bitOffset>
              <bitWidth>1</bitWidth>
            </field>
          </fields>
        </register>
        <register>
          <name>MACSR</name>
          <addressOffset>0x38</addressOffset>
          <size>0x20</size>
          <fields>
            <field>
              <name>PMTS</name>
              <bitOffset>3</bitOffset>
              <bitWidth>1</bitWidth>
            </field>
            <field>
              <name>MMCS</name>
              <bitOffset>4</bitOffset>
              <bitWidth>1</bitWidth>
            </field>
            <field>
              <name>MMMCRS</name>
              <bitOffset>5</bitOffset>
              <bitWidth>1</bitWidth>
            </field>
            <field>
              <name>MMCTS</name>
              <bitOffset>6</bitOffset>
              <bitWidth>1</bitWidth>
            </field>
            <field>
              <name>TSTS</name>
              <bitOffset>9</bitOffset>
              <bitWidth>1</bitWidth>
            </field>
          </fields>
        </register>
        <register>
          <name>MACIMR</name>
          <addressOffset>0x3c</addressOffset>
          <size>0x20</size>
          <fields>
            <field>
              <name>PMTIM</name>
              <bitOffset>3</bitOffset>
              <bitWidth>1</bitWidth>
            </field>
            <field>
              <name>TSTIM</name>
              <bitOffset>9</bitOffset>
              <bitWidth>1</bitWidth>
            </field>
          </fields>
        </register>
        <register>
          <name>MACA0HR</name>
          <addressOffset>0x40</addressOffset>
          <size>0x20</size>
          <fields>
            <field>
              <name>MACA0H</name>
              <bitOffset>0</bitOffset>
              <bitWidth>16</bitWidth>
            </field>
          </fields>
        </register>
        <register>
          <name>MACA0LR</name>
          <addressOffset>0x44</addressOffset>
          <size>0x20</size>
          <fields>
            <field>
              <name>MACA0L</name>
              <bitOffset>0</bitOffset>
              <bitWidth>32</bitWidth>
            </field>
          </fields>
        </register>
        <register>
          <name>MACA1HR</name>
          <addressOffset>0x48</addressOffset>
          <size>0x20</size>
          <fields>
            <field>
              <name>MACA1H</name>
              <bitOffset>0</bitOffset>
              <bitWidth>16</bitWidth>
            </field>
            <field>
              <name>MBC</name>
              <bitOffset>24</bitOffset>
              <bitWidth>6</bitWidth>
            </field>
            <field>
              <name>SA</name>
              <bitOffset>30</bitOffset>
              <bitWidth>1</bitWidth>
            </field>
            <field>
              <name>AE</name>
              <bitOffset>31</bitOffset>
              <bitWidth>1</bitWidth>
            </field>
          </fields>
        </register>
        <register>
          <name>MACA1LR</name>
          <addressOffset>0x4c</addressOffset>
          <size>0x20</size>
          <fields>
            <field>
              <name>MACA1L</name>
              <bitOffset>0</bitOffset>
              <bitWidth>32</bitWidth>
            </field>
          </fields>
        </register>
        <register>
          <name>MACA2HR</name>
          <addressOffset>0x50</addressOffset>
          <size>0x20</size>
          <fields>
            <field>
              <name>MACA2H</name>
              <bitOffset>0</bitOffset>
              <bitWidth>16</bitWidth>
            </field>
            <field>
              <name>MBC</name>
              <bitOffset>24</bitOffset>
              <bitWidth>6</bitWidth>
            </field>
            <field>
              <name>SA</name>
              <bitOffset>30</bitOffset>
              <bitWidth>1</bitWidth>
            </field>
            <field>
              <name>AE</name>
              <bitOffset>31</bitOffset>
              <bitWidth>1</bitWidth>
            </field>
          </fields>
        </register>
        <register>
          <name>MACA2LR</name>
          <addressOffset>0x54</addressOffset>
          <size>0x20</size>
          <fields>
            <field>
              <name>MACA2L</name>
              <bitOffset>0</bitOffset>
              <bitWidth>32</bitWidth>
            </field>
          </fields>
        </register>
        <register>
          <name>MACA3HR</name>
          <addressOffset>0x58</addressOffset>
          <size>0x20</size>
          <fields>
            <field>
              <name>MACA3H</name>
              <bitOffset>0</bitOffset>
              <bitWidth>16</bitWidth>
            </field>
            <field>
              <name>MBC</name>
              <bitOffset>24</bitOffset>
              <bitWidth>6</bitWidth>
            </field>
            <field>
              <name>SA</name>
              <bitOffset>30</bitOffset>
              <bitWidth>1</bitWidth>
            </field>
            <field>
              <name>AE</name>
              <bitOffset>31</bitOffset>
              <bitWidth>1</bitWidth>
            </field>
          </fields>
        </register>
        <register>
          <name>MACA3LR</name>
          <addressOffset>0x5c</addressOffset>
          <size>0x20</size>
          <fields>
            <field>
              <name>MACA3L</name>
              <bitOffset>0</bitOffset>
              <bitWidth>32</bitWidth>
            </field>
          </fields>
        </register>
        <register>
          <name>MMCCR</name>
          <addressOffset>0x100</addressOffset>
          <size>0x20</size>
          <fields>
            <field>
              <name>CR</name>
              <bitOffset>0</bitOffset>
              <bitWidth>1</bitWidth>
            </field>
            <field>
              <name>CSR</name>
              <bitOffset>1</bitOffset>
              <bitWidth>1</bitWidth>
            </field>
            <field>
              <name>ROR</name>
              <bitOffset>2</bitOffset>
              <bitWidth>1</bitWidth>
            </field>
            <field>
              <name>MCF</name>
              <bitOffset>3</bitOffset>
              <bitWidth>1</bitWidth>
            </field>
            <field>
              <name>MCP</name>
              <bitOffset>4</bitOffset>
              <bitWidth>1</bitWidth>
            </field>
            <field>
              <name>MCFHP</name>
              <bitOffset>5</bitOffset>
              <bitWidth>1</bitWidth>
            </field>
          </fields>
        </register>
        <register>
          <name>MMCRIR</name>
          <addressOffset>0x104</addressOffset>
          <size>0x20</size>
          <fields>
            <field>
              <name>RFCES</name>
              <bitOffset>5</bitOffset>
              <bitWidth>1</bitWidth>
            </field>
            <field>
              <name>RFAES</name>
              <bitOffset>6</bitOffset>
              <bitWidth>1</bitWidth>
            </field>
            <field>
              <name>RGUFS</name>
              <bitOffset>17</bitOffset>
              <bitWidth>1</bitWidth>
            </field>
          </fields>
        </register>
        <register>
          <name>MMCTIR</name>
          <addressOffset>0x108</addressOffset>
          <size>0x20</size>
          <fields>
            <field>
              <name>TGFSCS</name>
              <bitOffset>14</bitOffset>
              <bitWidth>1</bitWidth>
            </field>
            <field>
              <name>TGFMSCS</name>
              <bitOffset>15</bitOffset>
              <bitWidth>1</bitWidth>
            </field>
            <field>
              <name>TGFS</name>
              <bitOffset>21</bitOffset>
              <bitWidth>1</bitWidth>
            </field>
          </fields>
        </register>
        <register>
          <name>MMCRIMR</name>
          <addressOffset>0x10c</addressOffset>
          <size>0x20</size>
          <fields>
            <field>
              <name>RFCEM</name>
              <bitOffset>5</bitOffset>
              <bitWidth>1</bitWidth>
            </field>
            <field>
              <name>RFAEM</name>
              <bitOffset>6</bitOffset>
              <bitWidth>1</bitWidth>
            </field>
            <field>
              <name>RGUFM</name>
              <bitOffset>17</bitOffset>
              <bitWidth>1</bitWidth>
            </field>
          </fields>
        </register>
        <register>
          <name>MMCTIMR</name>
          <addressOffset>0x110</addressOffset>
          <size>0x20</size>
          <fields>
            <field>
              <name>TGFSCM</name>
              <bitOffset>14</bitOffset>
              <bitWidth>1</bitWidth>
            </field>
            <field>
              <name>TGFMSCM</name>
              <bitOffset>15</bitOffset>
              <bitWidth>1</bitWidth>
            </field>
            <field>
              <name>TGFM</name>
              <bitOffset>21</bitOffset>
              <bitWidth>1</bitWidth>
            </field>
          </fields>
        </register>
        <register>
          <name>MMCTGFSCCR</name>
          <addressOffset>0x14c</addressOffset>
          <size>0x20</size>
          <fields>
            <field>
              <name>TGFSCC</name>
              <bitOffset>0</bitOffset>
              <bitWidth>32</bitWidth>
            </field>
          </fields>
        </register>
        <register>
          <name>MMCTGFMSCCR</name>
          <addressOffset>0x150</addressOffset>
          <size>0x20</size>
          <fields>
            <field>
              <name>TGFMSCC</name>
              <bitOffset>0</bitOffset>
              <bitWidth>32</bitWidth>
            </field>
          </fields>
        </register>
        <register>
          <name>MMCTGFCR</name>
          <addressOffset>0x168</addressOffset>
          <size>0x20</size>
          <fields>
            <field>
              <name>TGFC</name>
              <bitOffset>0</bitOffset>
              <bitWidth>32</bitWidth>
            </field>
          </fields>
        </register>
        <register>
          <name>MMCRFCECR</name>
          <addressOffset>0x194</addressOffset>
          <size>0x20</size>
          <fields>
            <field>
              <name>RFCEC</name>
              <bitOffset>0</bitOffset>
              <bitWidth>32</bitWidth>
            </field>
          </fields>
        </register>
        <register>
          <name>MMCRFAECR</name>
          <addressOffset>0x198</addressOffset>
          <size>0x20</size>
          <fields>
            <field>
              <name>RFAEC</name>
              <bitOffset>0</bitOffset>
              <bitWidth>32</bitWidth>
            </field>
          </fields>
        </register>
        <register>
          <name>MMCRGUFCR</name>
          <addressOffset>0x1c4</addressOffset>
          <size>0x20</size>
          <fields>
            <field>
              <name>RGUFC</name>
              <bitOffset>0</bitOffset>
              <bitWidth>32</bitWidth>
            </field>
          </fields>
        </register>
        <register>
          <name>PTPTSCR</name>
          <addressOffset>0x700</addressOffset>
          <size>0x20</size>
          <fields>
            <field>
              <name>TSE</name>
              <bitOffset>0</bitOffset>
              <bitWidth>1</bitWidth>
            </field>
            <field>
              <name>TSFCU</name>
              <bitOffset>1</bitOffset>
              <bitWidth>1</bitWidth>
            </field>
            <field>
              <name>TSSTI</name>
              <bitOffset>2</bitOffset>
              <bitWidth>1</bitWidth>
            </field>
            <field>
              <name>TSSTU</name>
              <bitOffset>3</bitOffset>
              <bitWidth>1</bitWidth>
            </field>
            <field>
              <name>TSITE</name>
              <bitOffset>4</bitOffset>
              <bitWidth>1</bitWidth>
            </field>
            <field>
              <name>TSARU</name>
              <bitOffset>5</bitOffset>
              <bitWidth>1</bitWidth>
            </field>
            <field>
              <name>TSSARFE</name>
              <bitOffset>8</bitOffset>
              <bitWidth>1</bitWidth>
            </field>
            <field>
              <name>TSSSR</name>
              <bitOffset>9</bitOffset>
              <bitWidth>1</bitWidth>
            </field>
            <field>
              <name>TSPTPPSV2E</name>
              <bitOffset>10</bitOffset>
              <bitWidth>1</bitWidth>
            </field>
            <field>
              <name>TSSPTPOEFE</name>
              <bitOffset>11</bitOffset>
              <bitWidth>1</bitWidth>
            </field>
            <field>
              <name>TSSIPV6FE</name>
              <bitOffset>12</bitOffset>
              <bitWidth>1</bitWidth>
            </field>
            <field>
              <name>TSSIPV4FE</name>
              <bitOffset>13</bitOffset>
              <bitWidth>1</bitWidth>
            </field>
            <field>
              <name>TSSEME</name>
              <bitOffset>14</bitOffset>
              <bitWidth>1</bitWidth>
            </field>
            <field>
              <name>TSSMRME</name>
              <bitOffset>15</bitOffset>
              <bitWidth>1</bitWidth>
            </field>
            <field>
              <name>TSCNT</name>
              <bitOffset>16</bitOffset>
              <bitWidth>2</bitWidth>
            </field>
            <field>
              <name>TSPFFMAE</name>
              <bitOffset>18</bitOffset>
              <bitWidth>1</bitWidth>
            </field>
          </fields>
        </register>
        <register>
          <name>PTPSSIR</name>
          <addressOffset>0x704</addressOffset>
          <size>0x20</size>
          <fields>
            <field>
              <name>STSSI</name>
              <bitOffset>0</bitOffset>
              <bitWidth>8</bitWidth>
            </field>
          </fields>
        </register>
        <register>
          <name>PTPTSHR</name>
          <addressOffset>0x708</addressOffset>
          <size>0x20</size>
          <fields>
            <field>
              <name>STS</name>
              <bitOffset>0</bitOffset>
              <bitWidth>32</bitWidth>
            </field>
          </fields>
        </register>
        <register>
          <name>PTPTSLR</name>
          <addressOffset>0x70c</addressOffset>
          <size>0x20</size>
          <fields>
            <field>
              <name>STSS</name>
              <bitOffset>0</bitOffset>
              <bitWidth>31</bitWidth>
            </field>
            <field>
              <name>STPNS</name>
              <bitOffset>31</bitOffset>
              <bitWidth>1</bitWidth>
            </field>
          </fields>
        </register>
        <register>
          <name>PTPTSHUR</name>
          <addressOffset>0x710</addressOffset>
          <size>0x20</size>
          <fields>
            <field>
              <name>TSUS</name>
              <bitOffset>0</bitOffset>
              <bitWidth>32</bitWidth>
            </field>
          </fields>
        </register>
        <register>
          <name>PTPTSLUR</name>
          <addressOffset>0x714</addressOffset>
          <size>0x20</size>
          <fields>
            <field>
              <name>TSUSS</name>
              <bitOffset>0</bitOffset>
              <bitWidth>31</bitWidth>
            </field>
            <field>
              <name>TSUPNS</name>
              <bitOffset>31</bitOffset>
              <bitWidth>1</bitWidth>
            </field>
          </fields>
        </register>
        <register>
          <name>PTPTSAR</name>
          <addressOffset>0x718</addressOffset>
          <size>0x20</size>
          <fields>
            <field>
              <name>TSA</name>
              <bitOffset>0</bitOffset>
              <bitWidth>32</bitWidth>
            </field>
          </fields>
        </register>
        <register>
          <name>PTPTTHR</name>
          <addressOffset>0x71c</addressOffset>
          <size>0x20</size>
          <fields>
            <field>
              <name>TTSH</name>
              <bitOffset>0</bitOffset>
              <bitWidth>32</bitWidth>
            </field>
          </fields>
        </register>
        <register>
          <name>PTPTTLR</name>
          <addressOffset>0x720</addressOffset>
          <size>0x20</size>
          <fields>
            <field>
              <name>TTSL</name>
              <bitOffset>0</bitOffset>
              <bitWidth>32</bitWidth>
            </field>
          </fields>
        </register>
        <register>
          <name>PTPTSSR</name>
          <addressOffset>0x728</addressOffset>
          <size>0x20</size>
          <fields>
            <field>
              <name>TSSO</name>
              <bitOffset>4</bitOffset>
              <bitWidth>1</bitWidth>
            </field>
            <field>
              <name>TSTTR</name>
              <bitOffset>5</bitOffset>
              <bitWidth>1</bitWidth>
            </field>
          </fields>
        </register>
        <register>
          <name>DMABMR</name>
          <addressOffset>0x1000</addressOffset>
          <size>0x20</size>
          <fields>
            <field>
              <name>SR</name>
              <bitOffset>0</bitOffset>
              <bitWidth>1</bitWidth>
            </field>
            <field>
              <name>DA</name>
              <bitOffset>1</bitOffset>
              <bitWidth>1</bitWidth>
            </field>
            <field>
              <name>DSL</name>
              <bitOffset>2</bitOffset>
              <bitWidth>5</bitWidth>
            </field>
            <field>
              <name>EDE</name>
              <bitOffset>7</bitOffset>
              <bitWidth>1</bitWidth>
            </field>
            <field>
              <name>PBL</name>
              <bitOffset>8</bitOffset>
              <bitWidth>6</bitWidth>
            </field>
            <field>
              <name>RTPR</name>
              <bitOffset>14</bitOffset>
              <bitWidth>2</bitWidth>
            </field>
            <field>
              <name>FB</name>
              <bitOffset>16</bitOffset>
              <bitWidth>1</bitWidth>
            </field>
            <field>
              <name>RDP</name>
              <bitOffset>17</bitOffset>
              <bitWidth>6</bitWidth>
            </field>
            <field>
              <name>USP</name>
              <bitOffset>23</bitOffset>
              <bitWidth>1</bitWidth>
            </field>
            <field>
              <name>FPM</name>
              <bitOffset>24</bitOffset>
              <bitWidth>1</bitWidth>
            </field>
            <field>
              <name>AAB</name>
              <bitOffset>25</bitOffset>
              <bitWidth>1</bitWidth>
            </field>
            <field>
              <name>MB</name>
              <bitOffset>26</bitOffset>
              <bitWidth>1</bitWidth>
            </field>
          </fields>
        </register>
        <register>
          <name>DMATPDR</name>
          <addressOffset>0x1004</addressOffset>
          <size>0x20</size>
          <fields>
            <field>
              <name>TPD</name>
              <bitOffset>0</bitOffset>
              <bitWidth>32</bitWidth>
            </field>
          </fields>
        </register>
        <register>
          <name>DMARPDR</name>
          <addressOffset>0x1008</addressOffset>
          <size>0x20</size>
          <fields>
            <field>
              <name>RPD</name>
              <bitOffset>0</bitOffset>
              <bitWidth>32</bitWidth>
            </field>
          </fields>
        </register>
        <register>
          <name>DMARDLAR</name>
          <addressOffset>0x100c</addressOffset>
          <size>0x20</size>
          <fields>
            <field>
              <name>SRL</name>
              <bitOffset>0</bitOffset>
              <bitWidth>32</bitWidth>
            </field>
          </fields>
        </register>
        <register>
          <name>DMATDLAR</name>
          <addressOffset>0x1010</addressOffset>
          <size>0x20</size>
          <fields>
            <field>
              <name>STL</name>
              <bitOffset>0</bitOffset>
              <bitWidth>32</bitWidth>
            </field>
          </fields>
        </register>
        <register>
          <name>DMASR</name>
          <addressOffset>0x1014</addressOffset>
          <size>0x20</size>
          <fields>
            <field>
              <name>TS</name>
              <bitOffset>0</bitOffset>
              <bitWidth>1</bitWidth>
            </field>
            <field>
              <name>TPSS</name>
              <bitOffset>1</bitOffset>
              <bitWidth>1</bitWidth>
            </field>
            <field>
              <name>TBUS</name>
              <bitOffset>2</bitOffset>
              <bitWidth>1</bitWidth>
            </field>
            <field>
              <name>TJTS</name>
              <bitOffset>3</bitOffset>
              <bitWidth>1</bitWidth>
            </field>
            <field>
              <name>ROS</name>
              <bitOffset>4</bitOffset>
              <bitWidth>1</bitWidth>
            </field>
            <field>
              <name>TUS</name>
              <bitOffset>5</bitOffset>
              <bitWidth>1</bitWidth>
            </field>
            <field>
              <name>RS</name>
              <bitOffset>6</bitOffset>
              <bitWidth>1</bitWidth>
            </field>
            <field>
              <name>RBUS</name>
              <bitOffset>7</bitOffset>
              <bitWidth>1</bitWidth>
            </field>
            <field>
              <name>RPSS</name>
              <bitOffset>8</bitOffset>
              <bitWidth>1</bitWidth>
            </field>
            <field>
              <name>RWTS</name>
              <bitOffset>9</bitOffset>
              <bitWidth>1</bitWidth>
            </field>
            <field>
              <name>ETS</name>
              <bitOffset>10</bitOffset>
              <bitWidth>1</bitWidth>
            </field>
            <field>
              <name>FBES</name>
              <bitOffset>13</bitOffset>
              <bitWidth>1</bitWidth>
            </field>
            <field>
              <name>ERS</name>
              <bitOffset>14</bitOffset>
              <bitWidth>1</bitWidth>
            </field>
            <field>
              <name>AIS</name>
              <bitOffset>15</bitOffset>
              <bitWidth>1</bitWidth>
            </field>
            <field>
              <name>NIS</name>
              <bitOffset>16</bitOffset>
              <bitWidth>1</bitWidth>
            </field>
            <field>
              <name>RPS_Waiting</name>
              <bitOffset>17</bitOffset>
              <bitWidth>2</bitWidth>
            </field>
            <field>
              <name>RPS_Suspended</name>
              <bitOffset>19</bitOffset>
              <bitWidth>1</bitWidth>
            </field>
            <field>
              <name>TPS_Reading</name>
              <bitOffset>20</bitOffset>
              <bitWidth>2</bitWidth>
            </field>
            <field>
              <name>TPS_Waiting</name>
              <bitOffset>21</bitOffset>
              <bitWidth>1</bitWidth>
            </field>
            <field>
              <name>EBS_DataTransfTx</name>
              <bitOffset>23</bitOffset>
              <bitWidth>1</bitWidth>
            </field>
            <field>
              <name>EBS_ReadTransf</name>
              <bitOffset>24</bitOffset>
              <bitWidth>1</bitWidth>
            </field>
            <field>
              <name>EBS_DescAccess</name>
              <bitOffset>25</bitOffset>
              <bitWidth>1</bitWidth>
            </field>
            <field>
              <name>MMCS</name>
              <bitOffset>27</bitOffset>
              <bitWidth>1</bitWidth>
            </field>
            <field>
              <name>PMTS</name>
              <bitOffset>28</bitOffset>
              <bitWidth>1</bitWidth>
            </field>
            <field>
              <name>TSTS</name>
              <bitOffset>29</bitOffset>
              <bitWidth>1</bitWidth>
            </field>
          </fields>
        </register>
        <register>
          <name>DMAOMR</name>
          <addressOffset>0x1018</addressOffset>
          <size>0x20</size>
          <fields>
            <field>
              <name>SR</name>
              <bitOffset>1</bitOffset>
              <bitWidth>1</bitWidth>
            </field>
            <field>
              <name>OSF</name>
              <bitOffset>2</bitOffset>
              <bitWidth>1</bitWidth>
            </field>
            <field>
              <name>RTC</name>
              <bitOffset>3</bitOffset>
              <bitWidth>2</bitWidth>
            </field>
            <field>
              <name>FUGF</name>
              <bitOffset>6</bitOffset>
              <bitWidth>1</bitWidth>
            </field>
            <field>
              <name>FEF</name>
              <bitOffset>7</bitOffset>
              <bitWidth>1</bitWidth>
            </field>
            <field>
              <name>ST</name>
              <bitOffset>13</bitOffset>
              <bitWidth>1</bitWidth>
            </field>
            <field>
              <name>TTC</name>
              <bitOffset>14</bitOffset>
              <bitWidth>3</bitWidth>
            </field>
            <field>
              <name>FTF</name>
              <bitOffset>20</bitOffset>
              <bitWidth>1</bitWidth>
            </field>
            <field>
              <name>TSF</name>
              <bitOffset>21</bitOffset>
              <bitWidth>1</bitWidth>
            </field>
            <field>
              <name>DFRF</name>
              <bitOffset>24</bitOffset>
              <bitWidth>1</bitWidth>
            </field>
            <field>
              <name>RSF</name>
              <bitOffset>25</bitOffset>
              <bitWidth>1</bitWidth>
            </field>
            <field>
              <name>DTCEFD</name>
              <bitOffset>26</bitOffset>
              <bitWidth>1</bitWidth>
            </field>
          </fields>
        </register>
        <register>
          <name>DMAIER</name>
          <addressOffset>0x101c</addressOffset>
          <size>0x20</size>
          <fields>
            <field>
              <name>TIE</name>
              <bitOffset>0</bitOffset>
              <bitWidth>1</bitWidth>
            </field>
            <field>
              <name>TPSIE</name>
              <bitOffset>1</bitOffset>
              <bitWidth>1</bitWidth>
            </field>
            <field>
              <name>TBUIE</name>
              <bitOffset>2</bitOffset>
              <bitWidth>1</bitWidth>
            </field>
            <field>
              <name>TJTIE</name>
              <bitOffset>3</bitOffset>
              <bitWidth>1</bitWidth>
            </field>
            <field>
              <name>ROIE</name>
              <bitOffset>4</bitOffset>
              <bitWidth>1</bitWidth>
            </field>
            <field>
              <name>TUIE</name>
              <bitOffset>5</bitOffset>
              <bitWidth>1</bitWidth>
            </field>
            <field>
              <name>RIE</name>
              <bitOffset>6</bitOffset>
              <bitWidth>1</bitWidth>
            </field>
            <field>
              <name>RBUIE</name>
              <bitOffset>7</bitOffset>
              <bitWidth>1</bitWidth>
            </field>
            <field>
              <name>RPSIE</name>
              <bitOffset>8</bitOffset>
              <bitWidth>1</bitWidth>
            </field>
            <field>
              <name>RWTIE</name>
              <bitOffset>9</bitOffset>
              <bitWidth>1</bitWidth>
            </field>
            <field>
              <name>ETIE</name>
              <bitOffset>10</bitOffset>
              <bitWidth>1</bitWidth>
            </field>
            <field>
              <name>FBEIE</name>
              <bitOffset>13</bitOffset>
              <bitWidth>1</bitWidth>
            </field>
            <field>
              <name>ERIE</name>
              <bitOffset>14</bitOffset>
              <bitWidth>1</bitWidth>
            </field>
            <field>
              <name>AISE</name>
              <bitOffset>15</bitOffset>
              <bitWidth>1</bitWidth>
            </field>
            <field>
              <name>NISE</name>
              <bitOffset>16</bitOffset>
              <bitWidth>1</bitWidth>
            </field>
          </fields>
        </register>
        <register>
          <name>DMAMFBOCR</name>
          <addressOffset>0x1020</addressOffset>
          <size>0x20</size>
          <fields>
            <field>
              <name>MFC</name>
              <bitOffset>0</bitOffset>
              <bitWidth>16</bitWidth>
            </field>
            <field>
              <name>OMFC</name>
              <bitOffset>16</bitOffset>
              <bitWidth>1</bitWidth>
            </field>
            <field>
              <name>MFA</name>
              <bitOffset>17</bitOffset>
              <bitWidth>11</bitWidth>
            </field>
            <field>
              <name>OFOC</name>
              <bitOffset>28</bitOffset>
              <bitWidth>1</bitWidth>
            </field>
          </fields>
        </register>
        <register>
          <name>DMARSWTR</name>
          <addressOffset>0x1024</addressOffset>
          <size>0x20</size>
        </register>
        <register>
          <name>DMACHTDR</name>
          <addressOffset>0x1048</addressOffset>
          <size>0x20</size>
          <fields>
            <field>
              <name>HTDAP</name>
              <bitOffset>0</bitOffset>
              <bitWidth>32</bitWidth>
            </field>
          </fields>
        </register>
        <register>
          <name>DMACHRDR</name>
          <addressOffset>0x104c</addressOffset>
          <size>0x20</size>
          <fields>
            <field>
              <name>HRDAP</name>
              <bitOffset>0</bitOffset>
              <bitWidth>32</bitWidth>
            </field>
          </fields>
        </register>
        <register>
          <name>DMACHTBAR</name>
          <addressOffset>0x1050</addressOffset>
          <size>0x20</size>
          <fields>
            <field>
              <name>HTBAP</name>
              <bitOffset>0</bitOffset>
              <bitWidth>32</bitWidth>
            </field>
          </fields>
        </register>
        <register>
          <name>DMACHRBAR</name>
          <addressOffset>0x1054</addressOffset>
          <size>0x20</size>
          <fields>
            <field>
              <name>HRBAP</name>
              <bitOffset>0</bitOffset>
              <bitWidth>32</bitWidth>
            </field>
          </fields>
        </register>
      </registers>
    </peripheral>
    <peripheral>
      <name>DMA2D</name>
      <baseAddress>0x4002b000</baseAddress>
      <registers>
        <register>
          <name>CR</name>
          <addressOffset>0x0</addressOffset>
          <size>0x20</size>
          <fields>
            <field>
              <name>START</name>
              <bitOffset>0</bitOffset>
              <bitWidth>1</bitWidth>
            </field>
            <field>
              <name>SUSP</name>
              <bitOffset>1</bitOffset>
              <bitWidth>1</bitWidth>
            </field>
            <field>
              <name>ABORT</name>
              <bitOffset>2</bitOffset>
              <bitWidth>1</bitWidth>
            </field>
            <field>
              <name>TEIE</name>
              <bitOffset>8</bitOffset>
              <bitWidth>1</bitWidth>
            </field>
            <field>
              <name>TCIE</name>
              <bitOffset>9</bitOffset>
              <bitWidth>1</bitWidth>
            </field>
            <field>
              <name>TWIE</name>
              <bitOffset>10</bitOffset>
              <bitWidth>1</bitWidth>
            </field>
            <field>
              <name>CAEIE</name>
              <bitOffset>11</bitOffset>
              <bitWidth>1</bitWidth>
            </field>
            <field>
              <name>CTCIE</name>
              <bitOffset>12</bitOffset>
              <bitWidth>1</bitWidth>
            </field>
            <field>
              <name>CEIE</name>
              <bitOffset>13</bitOffset>
              <bitWidth>1</bitWidth>
            </field>
            <field>
              <name>MODE</name>
              <bitOffset>16</bitOffset>
              <bitWidth>2</bitWidth>
            </field>
          </fields>
        </register>
        <register>
          <name>ISR</name>
          <addressOffset>0x4</addressOffset>
          <size>0x20</size>
          <fields>
            <field>
              <name>TEIF</name>
              <bitOffset>0</bitOffset>
              <bitWidth>1</bitWidth>
            </field>
            <field>
              <name>TCIF</name>
              <bitOffset>1</bitOffset>
              <bitWidth>1</bitWidth>
            </field>
            <field>
              <name>TWIF</name>
              <bitOffset>2</bitOffset>
              <bitWidth>1</bitWidth>
            </field>
            <field>
              <name>CAEIF</name>
              <bitOffset>3</bitOffset>
              <bitWidth>1</bitWidth>
            </field>
            <field>
              <name>CTCIF</name>
              <bitOffset>4</bitOffset>
              <bitWidth>1</bitWidth>
            </field>
            <field>
              <name>CEIF</name>
              <bitOffset>5</bitOffset>
              <bitWidth>1</bitWidth>
            </field>
          </fields>
        </register>
        <register>
          <name>IFCR</name>
          <addressOffset>0x8</addressOffset>
          <size>0x20</size>
          <fields>
            <field>
              <name>CTEIF</name>
              <bitOffset>0</bitOffset>
              <bitWidth>1</bitWidth>
            </field>
            <field>
              <name>CTCIF</name>
              <bitOffset>1</bitOffset>
              <bitWidth>1</bitWidth>
            </field>
            <field>
              <name>CTWIF</name>
              <bitOffset>2</bitOffset>
              <bitWidth>1</bitWidth>
            </field>
            <field>
              <name>CAECIF</name>
              <bitOffset>3</bitOffset>
              <bitWidth>1</bitWidth>
            </field>
            <field>
              <name>CCTCIF</name>
              <bitOffset>4</bitOffset>
              <bitWidth>1</bitWidth>
            </field>
            <field>
              <name>CCEIF</name>
              <bitOffset>5</bitOffset>
              <bitWidth>1</bitWidth>
            </field>
          </fields>
        </register>
        <register>
          <name>FGMAR</name>
          <addressOffset>0xc</addressOffset>
          <size>0x20</size>
          <fields>
            <field>
              <name>MA</name>
              <bitOffset>0</bitOffset>
              <bitWidth>32</bitWidth>
            </field>
          </fields>
        </register>
        <register>
          <name>FGOR</name>
          <addressOffset>0x10</addressOffset>
          <size>0x20</size>
          <fields>
            <field>
              <name>LO</name>
              <bitOffset>0</bitOffset>
              <bitWidth>14</bitWidth>
            </field>
          </fields>
        </register>
        <register>
          <name>BGMAR</name>
          <addressOffset>0x14</addressOffset>
          <size>0x20</size>
          <fields>
            <field>
              <name>MA</name>
              <bitOffset>0</bitOffset>
              <bitWidth>32</bitWidth>
            </field>
          </fields>
        </register>
        <register>
          <name>BGOR</name>
          <addressOffset>0x18</addressOffset>
          <size>0x20</size>
          <fields>
            <field>
              <name>LO</name>
              <bitOffset>0</bitOffset>
              <bitWidth>14</bitWidth>
            </field>
          </fields>
        </register>
        <register>
          <name>FGPFCCR</name>
          <addressOffset>0x1c</addressOffset>
          <size>0x20</size>
          <fields>
            <field>
              <name>CM</name>
              <bitOffset>0</bitOffset>
              <bitWidth>4</bitWidth>
            </field>
            <field>
              <name>CCM</name>
              <bitOffset>4</bitOffset>
              <bitWidth>1</bitWidth>
            </field>
            <field>
              <name>START</name>
              <bitOffset>5</bitOffset>
              <bitWidth>1</bitWidth>
            </field>
            <field>
              <name>CS</name>
              <bitOffset>8</bitOffset>
              <bitWidth>8</bitWidth>
            </field>
            <field>
              <name>AM</name>
              <bitOffset>16</bitOffset>
              <bitWidth>2</bitWidth>
            </field>
            <field>
              <name>ALPHA</name>
              <bitOffset>24</bitOffset>
              <bitWidth>8</bitWidth>
            </field>
          </fields>
        </register>
        <register>
          <name>FGCOLR</name>
          <addressOffset>0x20</addressOffset>
          <size>0x20</size>
          <fields>
            <field>
              <name>BLUE</name>
              <bitOffset>0</bitOffset>
              <bitWidth>8</bitWidth>
            </field>
            <field>
              <name>GREEN</name>
              <bitOffset>8</bitOffset>
              <bitWidth>8</bitWidth>
            </field>
            <field>
              <name>RED</name>
              <bitOffset>16</bitOffset>
              <bitWidth>8</bitWidth>
            </field>
          </fields>
        </register>
        <register>
          <name>BGPFCCR</name>
          <addressOffset>0x24</addressOffset>
          <size>0x20</size>
          <fields>
            <field>
              <name>CM</name>
              <bitOffset>0</bitOffset>
              <bitWidth>4</bitWidth>
            </field>
            <field>
              <name>CCM</name>
              <bitOffset>4</bitOffset>
              <bitWidth>1</bitWidth>
            </field>
            <field>
              <name>START</name>
              <bitOffset>5</bitOffset>
              <bitWidth>1</bitWidth>
            </field>
            <field>
              <name>CS</name>
              <bitOffset>8</bitOffset>
              <bitWidth>8</bitWidth>
            </field>
            <field>
              <name>AM</name>
              <bitOffset>16</bitOffset>
              <bitWidth>2</bitWidth>
            </field>
            <field>
              <name>ALPHA</name>
              <bitOffset>24</bitOffset>
              <bitWidth>8</bitWidth>
            </field>
          </fields>
        </register>
        <register>
          <name>BGCOLR</name>
          <addressOffset>0x28</addressOffset>
          <size>0x20</size>
          <fields>
            <field>
              <name>BLUE</name>
              <bitOffset>0</bitOffset>
              <bitWidth>8</bitWidth>
            </field>
            <field>
              <name>GREEN</name>
              <bitOffset>8</bitOffset>
              <bitWidth>8</bitWidth>
            </field>
            <field>
              <name>RED</name>
              <bitOffset>16</bitOffset>
              <bitWidth>8</bitWidth>
            </field>
          </fields>
        </register>
        <register>
          <name>FGCMAR</name>
          <addressOffset>0x2c</addressOffset>
          <size>0x20</size>
          <fields>
            <field>
              <name>MA</name>
              <bitOffset>0</bitOffset>
              <bitWidth>32</bitWidth>
            </field>
          </fields>
        </register>
        <register>
          <name>BGCMAR</name>
          <addressOffset>0x30</addressOffset>
          <size>0x20</size>
          <fields>
            <field>
              <name>MA</name>
              <bitOffset>0</bitOffset>
              <bitWidth>32</bitWidth>
            </field>
          </fields>
        </register>
        <register>
          <name>OPFCCR</name>
          <addressOffset>0x34</addressOffset>
          <size>0x20</size>
          <fields>
            <field>
              <name>CM</name>
              <bitOffset>0</bitOffset>
              <bitWidth>3</bitWidth>
            </field>
          </fields>
        </register>
        <register>
          <name>OCOLR</name>
          <addressOffset>0x38</addressOffset>
          <size>0x20</size>
        </register>
        <register>
          <name>OMAR</name>
          <addressOffset>0x3c</addressOffset>
          <size>0x20</size>
          <fields>
            <field>
              <name>MA</name>
              <bitOffset>0</bitOffset>
              <bitWidth>32</bitWidth>
            </field>
          </fields>
        </register>
        <register>
          <name>OOR</name>
          <addressOffset>0x40</addressOffset>
          <size>0x20</size>
          <fields>
            <field>
              <name>LO</name>
              <bitOffset>0</bitOffset>
              <bitWidth>14</bitWidth>
            </field>
          </fields>
        </register>
        <register>
          <name>NLR</name>
          <addressOffset>0x44</addressOffset>
          <size>0x20</size>
          <fields>
            <field>
              <name>NL</name>
              <bitOffset>0</bitOffset>
              <bitWidth>16</bitWidth>
            </field>
            <field>
              <name>PL</name>
              <bitOffset>16</bitOffset>
              <bitWidth>14</bitWidth>
            </field>
          </fields>
        </register>
        <register>
          <name>LWR</name>
          <addressOffset>0x48</addressOffset>
          <size>0x20</size>
          <fields>
            <field>
              <name>LW</name>
              <bitOffset>0</bitOffset>
              <bitWidth>16</bitWidth>
            </field>
          </fields>
        </register>
        <register>
          <name>AMTCR</name>
          <addressOffset>0x4c</addressOffset>
          <size>0x20</size>
          <fields>
            <field>
              <name>EN</name>
              <bitOffset>0</bitOffset>
              <bitWidth>1</bitWidth>
            </field>
            <field>
              <name>DT</name>
              <bitOffset>8</bitOffset>
              <bitWidth>8</bitWidth>
            </field>
          </fields>
        </register>
        <register>
          <name>FGCLUT.0</name>
          <addressOffset>0x400</addressOffset>
          <size>0x20</size>
        </register>
        <register>
          <name>FGCLUT.1</name>
          <addressOffset>0x404</addressOffset>
          <size>0x20</size>
        </register>
        <register>
          <name>FGCLUT.2</name>
          <addressOffset>0x408</addressOffset>
          <size>0x20</size>
        </register>
        <register>
          <name>FGCLUT.3</name>
          <addressOffset>0x40c</addressOffset>
          <size>0x20</size>
        </register>
        <register>
          <name>FGCLUT.4</name>
          <addressOffset>0x410</addressOffset>
          <size>0x20</size>
        </register>
        <register>
          <name>FGCLUT.5</name>
          <addressOffset>0x414</addressOffset>
          <size>0x20</size>
        </register>
        <register>
          <name>FGCLUT.6</name>
          <addressOffset>0x418</addressOffset>
          <size>0x20</size>
        </register>
        <register>
          <name>FGCLUT.7</name>
          <addressOffset>0x41c</addressOffset>
          <size>0x20</size>
        </register>
        <register>
          <name>FGCLUT.8</name>
          <addressOffset>0x420</addressOffset>
          <size>0x20</size>
        </register>
        <register>
          <name>FGCLUT.9</name>
          <addressOffset>0x424</addressOffset>
          <size>0x20</size>
        </register>
        <register>
          <name>FGCLUT.10</name>
          <addressOffset>0x428</addressOffset>
          <size>0x20</size>
        </register>
        <register>
          <name>FGCLUT.11</name>
          <addressOffset>0x42c</addressOffset>
          <size>0x20</size>
        </register>
        <register>
          <name>FGCLUT.12</name>
          <addressOffset>0x430</addressOffset>
          <size>0x20</size>
        </register>
        <register>
          <name>FGCLUT.13</name>
          <addressOffset>0x434</addressOffset>
          <size>0x20</size>
        </register>
        <register>
          <name>FGCLUT.14</name>
          <addressOffset>0x438</addressOffset>
          <size>0x20</size>
        </register>
        <register>
          <name>FGCLUT.15</name>
          <addressOffset>0x43c</addressOffset>
          <size>0x20</size>
        </register>
        <register>
          <name>FGCLUT.16</name>
          <addressOffset>0x440</addressOffset>
          <size>0x20</size>
        </register>
        <register>
          <name>FGCLUT.17</name>
          <addressOffset>0x444</addressOffset>
          <size>0x20</size>
        </register>
        <register>
          <name>FGCLUT.18</name>
          <addressOffset>0x448</addressOffset>
          <size>0x20</size>
        </register>
        <register>
          <name>FGCLUT.19</name>
          <addressOffset>0x44c</addressOffset>
          <size>0x20</size>
        </register>
        <register>
          <name>FGCLUT.20</name>
          <addressOffset>0x450</addressOffset>
          <size>0x20</size>
        </register>
        <register>
          <name>FGCLUT.21</name>
          <addressOffset>0x454</addressOffset>
          <size>0x20</size>
        </register>
        <register>
          <name>FGCLUT.22</name>
          <addressOffset>0x458</addressOffset>
          <size>0x20</size>
        </register>
        <register>
          <name>FGCLUT.23</name>
          <addressOffset>0x45c</addressOffset>
          <size>0x20</size>
        </register>
        <register>
          <name>FGCLUT.24</name>
          <addressOffset>0x460</addressOffset>
          <size>0x20</size>
        </register>
        <register>
          <name>FGCLUT.25</name>
          <addressOffset>0x464</addressOffset>
          <size>0x20</size>
        </register>
        <register>
          <name>FGCLUT.26</name>
          <addressOffset>0x468</addressOffset>
          <size>0x20</size>
        </register>
        <register>
          <name>FGCLUT.27</name>
          <addressOffset>0x46c</addressOffset>
          <size>0x20</size>
        </register>
        <register>
          <name>FGCLUT.28</name>
          <addressOffset>0x470</addressOffset>
          <size>0x20</size>
        </register>
        <register>
          <name>FGCLUT.29</name>
          <addressOffset>0x474</addressOffset>
          <size>0x20</size>
        </register>
        <register>
          <name>FGCLUT.30</name>
          <addressOffset>0x478</addressOffset>
          <size>0x20</size>
        </register>
        <register>
          <name>FGCLUT.31</name>
          <addressOffset>0x47c</addressOffset>
          <size>0x20</size>
        </register>
        <register>
          <name>FGCLUT.32</name>
          <addressOffset>0x480</addressOffset>
          <size>0x20</size>
        </register>
        <register>
          <name>FGCLUT.33</name>
          <addressOffset>0x484</addressOffset>
          <size>0x20</size>
        </register>
        <register>
          <name>FGCLUT.34</name>
          <addressOffset>0x488</addressOffset>
          <size>0x20</size>
        </register>
        <register>
          <name>FGCLUT.35</name>
          <addressOffset>0x48c</addressOffset>
          <size>0x20</size>
        </register>
        <register>
          <name>FGCLUT.36</name>
          <addressOffset>0x490</addressOffset>
          <size>0x20</size>
        </register>
        <register>
          <name>FGCLUT.37</name>
          <addressOffset>0x494</addressOffset>
          <size>0x20</size>
        </register>
        <register>
          <name>FGCLUT.38</name>
          <addressOffset>0x498</addressOffset>
          <size>0x20</size>
        </register>
        <register>
          <name>FGCLUT.39</name>
          <addressOffset>0x49c</addressOffset>
          <size>0x20</size>
        </register>
        <register>
          <name>FGCLUT.40</name>
          <addressOffset>0x4a0</addressOffset>
          <size>0x20</size>
        </register>
        <register>
          <name>FGCLUT.41</name>
          <addressOffset>0x4a4</addressOffset>
          <size>0x20</size>
        </register>
        <register>
          <name>FGCLUT.42</name>
          <addressOffset>0x4a8</addressOffset>
          <size>0x20</size>
        </register>
        <register>
          <name>FGCLUT.43</name>
          <addressOffset>0x4ac</addressOffset>
          <size>0x20</size>
        </register>
        <register>
          <name>FGCLUT.44</name>
          <addressOffset>0x4b0</addressOffset>
          <size>0x20</size>
        </register>
        <register>
          <name>FGCLUT.45</name>
          <addressOffset>0x4b4</addressOffset>
          <size>0x20</size>
        </register>
        <register>
          <name>FGCLUT.46</name>
          <addressOffset>0x4b8</addressOffset>
          <size>0x20</size>
        </register>
        <register>
          <name>FGCLUT.47</name>
          <addressOffset>0x4bc</addressOffset>
          <size>0x20</size>
        </register>
        <register>
          <name>FGCLUT.48</name>
          <addressOffset>0x4c0</addressOffset>
          <size>0x20</size>
        </register>
        <register>
          <name>FGCLUT.49</name>
          <addressOffset>0x4c4</addressOffset>
          <size>0x20</size>
        </register>
        <register>
          <name>FGCLUT.50</name>
          <addressOffset>0x4c8</addressOffset>
          <size>0x20</size>
        </register>
        <register>
          <name>FGCLUT.51</name>
          <addressOffset>0x4cc</addressOffset>
          <size>0x20</size>
        </register>
        <register>
          <name>FGCLUT.52</name>
          <addressOffset>0x4d0</addressOffset>
          <size>0x20</size>
        </register>
        <register>
          <name>FGCLUT.53</name>
          <addressOffset>0x4d4</addressOffset>
          <size>0x20</size>
        </register>
        <register>
          <name>FGCLUT.54</name>
          <addressOffset>0x4d8</addressOffset>
          <size>0x20</size>
        </register>
        <register>
          <name>FGCLUT.55</name>
          <addressOffset>0x4dc</addressOffset>
          <size>0x20</size>
        </register>
        <register>
          <name>FGCLUT.56</name>
          <addressOffset>0x4e0</addressOffset>
          <size>0x20</size>
        </register>
        <register>
          <name>FGCLUT.57</name>
          <addressOffset>0x4e4</addressOffset>
          <size>0x20</size>
        </register>
        <register>
          <name>FGCLUT.58</name>
          <addressOffset>0x4e8</addressOffset>
          <size>0x20</size>
        </register>
        <register>
          <name>FGCLUT.59</name>
          <addressOffset>0x4ec</addressOffset>
          <size>0x20</size>
        </register>
        <register>
          <name>FGCLUT.60</name>
          <addressOffset>0x4f0</addressOffset>
          <size>0x20</size>
        </register>
        <register>
          <name>FGCLUT.61</name>
          <addressOffset>0x4f4</addressOffset>
          <size>0x20</size>
        </register>
        <register>
          <name>FGCLUT.62</name>
          <addressOffset>0x4f8</addressOffset>
          <size>0x20</size>
        </register>
        <register>
          <name>FGCLUT.63</name>
          <addressOffset>0x4fc</addressOffset>
          <size>0x20</size>
        </register>
        <register>
          <name>FGCLUT.64</name>
          <addressOffset>0x500</addressOffset>
          <size>0x20</size>
        </register>
        <register>
          <name>FGCLUT.65</name>
          <addressOffset>0x504</addressOffset>
          <size>0x20</size>
        </register>
        <register>
          <name>FGCLUT.66</name>
          <addressOffset>0x508</addressOffset>
          <size>0x20</size>
        </register>
        <register>
          <name>FGCLUT.67</name>
          <addressOffset>0x50c</addressOffset>
          <size>0x20</size>
        </register>
        <register>
          <name>FGCLUT.68</name>
          <addressOffset>0x510</addressOffset>
          <size>0x20</size>
        </register>
        <register>
          <name>FGCLUT.69</name>
          <addressOffset>0x514</addressOffset>
          <size>0x20</size>
        </register>
        <register>
          <name>FGCLUT.70</name>
          <addressOffset>0x518</addressOffset>
          <size>0x20</size>
        </register>
        <register>
          <name>FGCLUT.71</name>
          <addressOffset>0x51c</addressOffset>
          <size>0x20</size>
        </register>
        <register>
          <name>FGCLUT.72</name>
          <addressOffset>0x520</addressOffset>
          <size>0x20</size>
        </register>
        <register>
          <name>FGCLUT.73</name>
          <addressOffset>0x524</addressOffset>
          <size>0x20</size>
        </register>
        <register>
          <name>FGCLUT.74</name>
          <addressOffset>0x528</addressOffset>
          <size>0x20</size>
        </register>
        <register>
          <name>FGCLUT.75</name>
          <addressOffset>0x52c</addressOffset>
          <size>0x20</size>
        </register>
        <register>
          <name>FGCLUT.76</name>
          <addressOffset>0x530</addressOffset>
          <size>0x20</size>
        </register>
        <register>
          <name>FGCLUT.77</name>
          <addressOffset>0x534</addressOffset>
          <size>0x20</size>
        </register>
        <register>
          <name>FGCLUT.78</name>
          <addressOffset>0x538</addressOffset>
          <size>0x20</size>
        </register>
        <register>
          <name>FGCLUT.79</name>
          <addressOffset>0x53c</addressOffset>
          <size>0x20</size>
        </register>
        <register>
          <name>FGCLUT.80</name>
          <addressOffset>0x540</addressOffset>
          <size>0x20</size>
        </register>
        <register>
          <name>FGCLUT.81</name>
          <addressOffset>0x544</addressOffset>
          <size>0x20</size>
        </register>
        <register>
          <name>FGCLUT.82</name>
          <addressOffset>0x548</addressOffset>
          <size>0x20</size>
        </register>
        <register>
          <name>FGCLUT.83</name>
          <addressOffset>0x54c</addressOffset>
          <size>0x20</size>
        </register>
        <register>
          <name>FGCLUT.84</name>
          <addressOffset>0x550</addressOffset>
          <size>0x20</size>
        </register>
        <register>
          <name>FGCLUT.85</name>
          <addressOffset>0x554</addressOffset>
          <size>0x20</size>
        </register>
        <register>
          <name>FGCLUT.86</name>
          <addressOffset>0x558</addressOffset>
          <size>0x20</size>
        </register>
        <register>
          <name>FGCLUT.87</name>
          <addressOffset>0x55c</addressOffset>
          <size>0x20</size>
        </register>
        <register>
          <name>FGCLUT.88</name>
          <addressOffset>0x560</addressOffset>
          <size>0x20</size>
        </register>
        <register>
          <name>FGCLUT.89</name>
          <addressOffset>0x564</addressOffset>
          <size>0x20</size>
        </register>
        <register>
          <name>FGCLUT.90</name>
          <addressOffset>0x568</addressOffset>
          <size>0x20</size>
        </register>
        <register>
          <name>FGCLUT.91</name>
          <addressOffset>0x56c</addressOffset>
          <size>0x20</size>
        </register>
        <register>
          <name>FGCLUT.92</name>
          <addressOffset>0x570</addressOffset>
          <size>0x20</size>
        </register>
        <register>
          <name>FGCLUT.93</name>
          <addressOffset>0x574</addressOffset>
          <size>0x20</size>
        </register>
        <register>
          <name>FGCLUT.94</name>
          <addressOffset>0x578</addressOffset>
          <size>0x20</size>
        </register>
        <register>
          <name>FGCLUT.95</name>
          <addressOffset>0x57c</addressOffset>
          <size>0x20</size>
        </register>
        <register>
          <name>FGCLUT.96</name>
          <addressOffset>0x580</addressOffset>
          <size>0x20</size>
        </register>
        <register>
          <name>FGCLUT.97</name>
          <addressOffset>0x584</addressOffset>
          <size>0x20</size>
        </register>
        <register>
          <name>FGCLUT.98</name>
          <addressOffset>0x588</addressOffset>
          <size>0x20</size>
        </register>
        <register>
          <name>FGCLUT.99</name>
          <addressOffset>0x58c</addressOffset>
          <size>0x20</size>
        </register>
        <register>
          <name>FGCLUT.100</name>
          <addressOffset>0x590</addressOffset>
          <size>0x20</size>
        </register>
        <register>
          <name>FGCLUT.101</name>
          <addressOffset>0x594</addressOffset>
          <size>0x20</size>
        </register>
        <register>
          <name>FGCLUT.102</name>
          <addressOffset>0x598</addressOffset>
          <size>0x20</size>
        </register>
        <register>
          <name>FGCLUT.103</name>
          <addressOffset>0x59c</addressOffset>
          <size>0x20</size>
        </register>
        <register>
          <name>FGCLUT.104</name>
          <addressOffset>0x5a0</addressOffset>
          <size>0x20</size>
        </register>
        <register>
          <name>FGCLUT.105</name>
          <addressOffset>0x5a4</addressOffset>
          <size>0x20</size>
        </register>
        <register>
          <name>FGCLUT.106</name>
          <addressOffset>0x5a8</addressOffset>
          <size>0x20</size>
        </register>
        <register>
          <name>FGCLUT.107</name>
          <addressOffset>0x5ac</addressOffset>
          <size>0x20</size>
        </register>
        <register>
          <name>FGCLUT.108</name>
          <addressOffset>0x5b0</addressOffset>
          <size>0x20</size>
        </register>
        <register>
          <name>FGCLUT.109</name>
          <addressOffset>0x5b4</addressOffset>
          <size>0x20</size>
        </register>
        <register>
          <name>FGCLUT.110</name>
          <addressOffset>0x5b8</addressOffset>
          <size>0x20</size>
        </register>
        <register>
          <name>FGCLUT.111</name>
          <addressOffset>0x5bc</addressOffset>
          <size>0x20</size>
        </register>
        <register>
          <name>FGCLUT.112</name>
          <addressOffset>0x5c0</addressOffset>
          <size>0x20</size>
        </register>
        <register>
          <name>FGCLUT.113</name>
          <addressOffset>0x5c4</addressOffset>
          <size>0x20</size>
        </register>
        <register>
          <name>FGCLUT.114</name>
          <addressOffset>0x5c8</addressOffset>
          <size>0x20</size>
        </register>
        <register>
          <name>FGCLUT.115</name>
          <addressOffset>0x5cc</addressOffset>
          <size>0x20</size>
        </register>
        <register>
          <name>FGCLUT.116</name>
          <addressOffset>0x5d0</addressOffset>
          <size>0x20</size>
        </register>
        <register>
          <name>FGCLUT.117</name>
          <addressOffset>0x5d4</addressOffset>
          <size>0x20</size>
        </register>
        <register>
          <name>FGCLUT.118</name>
          <addressOffset>0x5d8</addressOffset>
          <size>0x20</size>
        </register>
        <register>
          <name>FGCLUT.119</name>
          <addressOffset>0x5dc</addressOffset>
          <size>0x20</size>
        </register>
        <register>
          <name>FGCLUT.120</name>
          <addressOffset>0x5e0</addressOffset>
          <size>0x20</size>
        </register>
        <register>
          <name>FGCLUT.121</name>
          <addressOffset>0x5e4</addressOffset>
          <size>0x20</size>
        </register>
        <register>
          <name>FGCLUT.122</name>
          <addressOffset>0x5e8</addressOffset>
          <size>0x20</size>
        </register>
        <register>
          <name>FGCLUT.123</name>
          <addressOffset>0x5ec</addressOffset>
          <size>0x20</size>
        </register>
        <register>
          <name>FGCLUT.124</name>
          <addressOffset>0x5f0</addressOffset>
          <size>0x20</size>
        </register>
        <register>
          <name>FGCLUT.125</name>
          <addressOffset>0x5f4</addressOffset>
          <size>0x20</size>
        </register>
        <register>
          <name>FGCLUT.126</name>
          <addressOffset>0x5f8</addressOffset>
          <size>0x20</size>
        </register>
        <register>
          <name>FGCLUT.127</name>
          <addressOffset>0x5fc</addressOffset>
          <size>0x20</size>
        </register>
        <register>
          <name>FGCLUT.128</name>
          <addressOffset>0x600</addressOffset>
          <size>0x20</size>
        </register>
        <register>
          <name>FGCLUT.129</name>
          <addressOffset>0x604</addressOffset>
          <size>0x20</size>
        </register>
        <register>
          <name>FGCLUT.130</name>
          <addressOffset>0x608</addressOffset>
          <size>0x20</size>
        </register>
        <register>
          <name>FGCLUT.131</name>
          <addressOffset>0x60c</addressOffset>
          <size>0x20</size>
        </register>
        <register>
          <name>FGCLUT.132</name>
          <addressOffset>0x610</addressOffset>
          <size>0x20</size>
        </register>
        <register>
          <name>FGCLUT.133</name>
          <addressOffset>0x614</addressOffset>
          <size>0x20</size>
        </register>
        <register>
          <name>FGCLUT.134</name>
          <addressOffset>0x618</addressOffset>
          <size>0x20</size>
        </register>
        <register>
          <name>FGCLUT.135</name>
          <addressOffset>0x61c</addressOffset>
          <size>0x20</size>
        </register>
        <register>
          <name>FGCLUT.136</name>
          <addressOffset>0x620</addressOffset>
          <size>0x20</size>
        </register>
        <register>
          <name>FGCLUT.137</name>
          <addressOffset>0x624</addressOffset>
          <size>0x20</size>
        </register>
        <register>
          <name>FGCLUT.138</name>
          <addressOffset>0x628</addressOffset>
          <size>0x20</size>
        </register>
        <register>
          <name>FGCLUT.139</name>
          <addressOffset>0x62c</addressOffset>
          <size>0x20</size>
        </register>
        <register>
          <name>FGCLUT.140</name>
          <addressOffset>0x630</addressOffset>
          <size>0x20</size>
        </register>
        <register>
          <name>FGCLUT.141</name>
          <addressOffset>0x634</addressOffset>
          <size>0x20</size>
        </register>
        <register>
          <name>FGCLUT.142</name>
          <addressOffset>0x638</addressOffset>
          <size>0x20</size>
        </register>
        <register>
          <name>FGCLUT.143</name>
          <addressOffset>0x63c</addressOffset>
          <size>0x20</size>
        </register>
        <register>
          <name>FGCLUT.144</name>
          <addressOffset>0x640</addressOffset>
          <size>0x20</size>
        </register>
        <register>
          <name>FGCLUT.145</name>
          <addressOffset>0x644</addressOffset>
          <size>0x20</size>
        </register>
        <register>
          <name>FGCLUT.146</name>
          <addressOffset>0x648</addressOffset>
          <size>0x20</size>
        </register>
        <register>
          <name>FGCLUT.147</name>
          <addressOffset>0x64c</addressOffset>
          <size>0x20</size>
        </register>
        <register>
          <name>FGCLUT.148</name>
          <addressOffset>0x650</addressOffset>
          <size>0x20</size>
        </register>
        <register>
          <name>FGCLUT.149</name>
          <addressOffset>0x654</addressOffset>
          <size>0x20</size>
        </register>
        <register>
          <name>FGCLUT.150</name>
          <addressOffset>0x658</addressOffset>
          <size>0x20</size>
        </register>
        <register>
          <name>FGCLUT.151</name>
          <addressOffset>0x65c</addressOffset>
          <size>0x20</size>
        </register>
        <register>
          <name>FGCLUT.152</name>
          <addressOffset>0x660</addressOffset>
          <size>0x20</size>
        </register>
        <register>
          <name>FGCLUT.153</name>
          <addressOffset>0x664</addressOffset>
          <size>0x20</size>
        </register>
        <register>
          <name>FGCLUT.154</name>
          <addressOffset>0x668</addressOffset>
          <size>0x20</size>
        </register>
        <register>
          <name>FGCLUT.155</name>
          <addressOffset>0x66c</addressOffset>
          <size>0x20</size>
        </register>
        <register>
          <name>FGCLUT.156</name>
          <addressOffset>0x670</addressOffset>
          <size>0x20</size>
        </register>
        <register>
          <name>FGCLUT.157</name>
          <addressOffset>0x674</addressOffset>
          <size>0x20</size>
        </register>
        <register>
          <name>FGCLUT.158</name>
          <addressOffset>0x678</addressOffset>
          <size>0x20</size>
        </register>
        <register>
          <name>FGCLUT.159</name>
          <addressOffset>0x67c</addressOffset>
          <size>0x20</size>
        </register>
        <register>
          <name>FGCLUT.160</name>
          <addressOffset>0x680</addressOffset>
          <size>0x20</size>
        </register>
        <register>
          <name>FGCLUT.161</name>
          <addressOffset>0x684</addressOffset>
          <size>0x20</size>
        </register>
        <register>
          <name>FGCLUT.162</name>
          <addressOffset>0x688</addressOffset>
          <size>0x20</size>
        </register>
        <register>
          <name>FGCLUT.163</name>
          <addressOffset>0x68c</addressOffset>
          <size>0x20</size>
        </register>
        <register>
          <name>FGCLUT.164</name>
          <addressOffset>0x690</addressOffset>
          <size>0x20</size>
        </register>
        <register>
          <name>FGCLUT.165</name>
          <addressOffset>0x694</addressOffset>
          <size>0x20</size>
        </register>
        <register>
          <name>FGCLUT.166</name>
          <addressOffset>0x698</addressOffset>
          <size>0x20</size>
        </register>
        <register>
          <name>FGCLUT.167</name>
          <addressOffset>0x69c</addressOffset>
          <size>0x20</size>
        </register>
        <register>
          <name>FGCLUT.168</name>
          <addressOffset>0x6a0</addressOffset>
          <size>0x20</size>
        </register>
        <register>
          <name>FGCLUT.169</name>
          <addressOffset>0x6a4</addressOffset>
          <size>0x20</size>
        </register>
        <register>
          <name>FGCLUT.170</name>
          <addressOffset>0x6a8</addressOffset>
          <size>0x20</size>
        </register>
        <register>
          <name>FGCLUT.171</name>
          <addressOffset>0x6ac</addressOffset>
          <size>0x20</size>
        </register>
        <register>
          <name>FGCLUT.172</name>
          <addressOffset>0x6b0</addressOffset>
          <size>0x20</size>
        </register>
        <register>
          <name>FGCLUT.173</name>
          <addressOffset>0x6b4</addressOffset>
          <size>0x20</size>
        </register>
        <register>
          <name>FGCLUT.174</name>
          <addressOffset>0x6b8</addressOffset>
          <size>0x20</size>
        </register>
        <register>
          <name>FGCLUT.175</name>
          <addressOffset>0x6bc</addressOffset>
          <size>0x20</size>
        </register>
        <register>
          <name>FGCLUT.176</name>
          <addressOffset>0x6c0</addressOffset>
          <size>0x20</size>
        </register>
        <register>
          <name>FGCLUT.177</name>
          <addressOffset>0x6c4</addressOffset>
          <size>0x20</size>
        </register>
        <register>
          <name>FGCLUT.178</name>
          <addressOffset>0x6c8</addressOffset>
          <size>0x20</size>
        </register>
        <register>
          <name>FGCLUT.179</name>
          <addressOffset>0x6cc</addressOffset>
          <size>0x20</size>
        </register>
        <register>
          <name>FGCLUT.180</name>
          <addressOffset>0x6d0</addressOffset>
          <size>0x20</size>
        </register>
        <register>
          <name>FGCLUT.181</name>
          <addressOffset>0x6d4</addressOffset>
          <size>0x20</size>
        </register>
        <register>
          <name>FGCLUT.182</name>
          <addressOffset>0x6d8</addressOffset>
          <size>0x20</size>
        </register>
        <register>
          <name>FGCLUT.183</name>
          <addressOffset>0x6dc</addressOffset>
          <size>0x20</size>
        </register>
        <register>
          <name>FGCLUT.184</name>
          <addressOffset>0x6e0</addressOffset>
          <size>0x20</size>
        </register>
        <register>
          <name>FGCLUT.185</name>
          <addressOffset>0x6e4</addressOffset>
          <size>0x20</size>
        </register>
        <register>
          <name>FGCLUT.186</name>
          <addressOffset>0x6e8</addressOffset>
          <size>0x20</size>
        </register>
        <register>
          <name>FGCLUT.187</name>
          <addressOffset>0x6ec</addressOffset>
          <size>0x20</size>
        </register>
        <register>
          <name>FGCLUT.188</name>
          <addressOffset>0x6f0</addressOffset>
          <size>0x20</size>
        </register>
        <register>
          <name>FGCLUT.189</name>
          <addressOffset>0x6f4</addressOffset>
          <size>0x20</size>
        </register>
        <register>
          <name>FGCLUT.190</name>
          <addressOffset>0x6f8</addressOffset>
          <size>0x20</size>
        </register>
        <register>
          <name>FGCLUT.191</name>
          <addressOffset>0x6fc</addressOffset>
          <size>0x20</size>
        </register>
        <register>
          <name>FGCLUT.192</name>
          <addressOffset>0x700</addressOffset>
          <size>0x20</size>
        </register>
        <register>
          <name>FGCLUT.193</name>
          <addressOffset>0x704</addressOffset>
          <size>0x20</size>
        </register>
        <register>
          <name>FGCLUT.194</name>
          <addressOffset>0x708</addressOffset>
          <size>0x20</size>
        </register>
        <register>
          <name>FGCLUT.195</name>
          <addressOffset>0x70c</addressOffset>
          <size>0x20</size>
        </register>
        <register>
          <name>FGCLUT.196</name>
          <addressOffset>0x710</addressOffset>
          <size>0x20</size>
        </register>
        <register>
          <name>FGCLUT.197</name>
          <addressOffset>0x714</addressOffset>
          <size>0x20</size>
        </register>
        <register>
          <name>FGCLUT.198</name>
          <addressOffset>0x718</addressOffset>
          <size>0x20</size>
        </register>
        <register>
          <name>FGCLUT.199</name>
          <addressOffset>0x71c</addressOffset>
          <size>0x20</size>
        </register>
        <register>
          <name>FGCLUT.200</name>
          <addressOffset>0x720</addressOffset>
          <size>0x20</size>
        </register>
        <register>
          <name>FGCLUT.201</name>
          <addressOffset>0x724</addressOffset>
          <size>0x20</size>
        </register>
        <register>
          <name>FGCLUT.202</name>
          <addressOffset>0x728</addressOffset>
          <size>0x20</size>
        </register>
        <register>
          <name>FGCLUT.203</name>
          <addressOffset>0x72c</addressOffset>
          <size>0x20</size>
        </register>
        <register>
          <name>FGCLUT.204</name>
          <addressOffset>0x730</addressOffset>
          <size>0x20</size>
        </register>
        <register>
          <name>FGCLUT.205</name>
          <addressOffset>0x734</addressOffset>
          <size>0x20</size>
        </register>
        <register>
          <name>FGCLUT.206</name>
          <addressOffset>0x738</addressOffset>
          <size>0x20</size>
        </register>
        <register>
          <name>FGCLUT.207</name>
          <addressOffset>0x73c</addressOffset>
          <size>0x20</size>
        </register>
        <register>
          <name>FGCLUT.208</name>
          <addressOffset>0x740</addressOffset>
          <size>0x20</size>
        </register>
        <register>
          <name>FGCLUT.209</name>
          <addressOffset>0x744</addressOffset>
          <size>0x20</size>
        </register>
        <register>
          <name>FGCLUT.210</name>
          <addressOffset>0x748</addressOffset>
          <size>0x20</size>
        </register>
        <register>
          <name>FGCLUT.211</name>
          <addressOffset>0x74c</addressOffset>
          <size>0x20</size>
        </register>
        <register>
          <name>FGCLUT.212</name>
          <addressOffset>0x750</addressOffset>
          <size>0x20</size>
        </register>
        <register>
          <name>FGCLUT.213</name>
          <addressOffset>0x754</addressOffset>
          <size>0x20</size>
        </register>
        <register>
          <name>FGCLUT.214</name>
          <addressOffset>0x758</addressOffset>
          <size>0x20</size>
        </register>
        <register>
          <name>FGCLUT.215</name>
          <addressOffset>0x75c</addressOffset>
          <size>0x20</size>
        </register>
        <register>
          <name>FGCLUT.216</name>
          <addressOffset>0x760</addressOffset>
          <size>0x20</size>
        </register>
        <register>
          <name>FGCLUT.217</name>
          <addressOffset>0x764</addressOffset>
          <size>0x20</size>
        </register>
        <register>
          <name>FGCLUT.218</name>
          <addressOffset>0x768</addressOffset>
          <size>0x20</size>
        </register>
        <register>
          <name>FGCLUT.219</name>
          <addressOffset>0x76c</addressOffset>
          <size>0x20</size>
        </register>
        <register>
          <name>FGCLUT.220</name>
          <addressOffset>0x770</addressOffset>
          <size>0x20</size>
        </register>
        <register>
          <name>FGCLUT.221</name>
          <addressOffset>0x774</addressOffset>
          <size>0x20</size>
        </register>
        <register>
          <name>FGCLUT.222</name>
          <addressOffset>0x778</addressOffset>
          <size>0x20</size>
        </register>
        <register>
          <name>FGCLUT.223</name>
          <addressOffset>0x77c</addressOffset>
          <size>0x20</size>
        </register>
        <register>
          <name>FGCLUT.224</name>
          <addressOffset>0x780</addressOffset>
          <size>0x20</size>
        </register>
        <register>
          <name>FGCLUT.225</name>
          <addressOffset>0x784</addressOffset>
          <size>0x20</size>
        </register>
        <register>
          <name>FGCLUT.226</name>
          <addressOffset>0x788</addressOffset>
          <size>0x20</size>
        </register>
        <register>
          <name>FGCLUT.227</name>
          <addressOffset>0x78c</addressOffset>
          <size>0x20</size>
        </register>
        <register>
          <name>FGCLUT.228</name>
          <addressOffset>0x790</addressOffset>
          <size>0x20</size>
        </register>
        <register>
          <name>FGCLUT.229</name>
          <addressOffset>0x794</addressOffset>
          <size>0x20</size>
        </register>
        <register>
          <name>FGCLUT.230</name>
          <addressOffset>0x798</addressOffset>
          <size>0x20</size>
        </register>
        <register>
          <name>FGCLUT.231</name>
          <addressOffset>0x79c</addressOffset>
          <size>0x20</size>
        </register>
        <register>
          <name>FGCLUT.232</name>
          <addressOffset>0x7a0</addressOffset>
          <size>0x20</size>
        </register>
        <register>
          <name>FGCLUT.233</name>
          <addressOffset>0x7a4</addressOffset>
          <size>0x20</size>
        </register>
        <register>
          <name>FGCLUT.234</name>
          <addressOffset>0x7a8</addressOffset>
          <size>0x20</size>
        </register>
        <register>
          <name>FGCLUT.235</name>
          <addressOffset>0x7ac</addressOffset>
          <size>0x20</size>
        </register>
        <register>
          <name>FGCLUT.236</name>
          <addressOffset>0x7b0</addressOffset>
          <size>0x20</size>
        </register>
        <register>
          <name>FGCLUT.237</name>
          <addressOffset>0x7b4</addressOffset>
          <size>0x20</size>
        </register>
        <register>
          <name>FGCLUT.238</name>
          <addressOffset>0x7b8</addressOffset>
          <size>0x20</size>
        </register>
        <register>
          <name>FGCLUT.239</name>
          <addressOffset>0x7bc</addressOffset>
          <size>0x20</size>
        </register>
        <register>
          <name>FGCLUT.240</name>
          <addressOffset>0x7c0</addressOffset>
          <size>0x20</size>
        </register>
        <register>
          <name>FGCLUT.241</name>
          <addressOffset>0x7c4</addressOffset>
          <size>0x20</size>
        </register>
        <register>
          <name>FGCLUT.242</name>
          <addressOffset>0x7c8</addressOffset>
          <size>0x20</size>
        </register>
        <register>
          <name>FGCLUT.243</name>
          <addressOffset>0x7cc</addressOffset>
          <size>0x20</size>
        </register>
        <register>
          <name>FGCLUT.244</name>
          <addressOffset>0x7d0</addressOffset>
          <size>0x20</size>
        </register>
        <register>
          <name>FGCLUT.245</name>
          <addressOffset>0x7d4</addressOffset>
          <size>0x20</size>
        </register>
        <register>
          <name>FGCLUT.246</name>
          <addressOffset>0x7d8</addressOffset>
          <size>0x20</size>
        </register>
        <register>
          <name>FGCLUT.247</name>
          <addressOffset>0x7dc</addressOffset>
          <size>0x20</size>
        </register>
        <register>
          <name>FGCLUT.248</name>
          <addressOffset>0x7e0</addressOffset>
          <size>0x20</size>
        </register>
        <register>
          <name>FGCLUT.249</name>
          <addressOffset>0x7e4</addressOffset>
          <size>0x20</size>
        </register>
        <register>
          <name>FGCLUT.250</name>
          <addressOffset>0x7e8</addressOffset>
          <size>0x20</size>
        </register>
        <register>
          <name>FGCLUT.251</name>
          <addressOffset>0x7ec</addressOffset>
          <size>0x20</size>
        </register>
        <register>
          <name>FGCLUT.252</name>
          <addressOffset>0x7f0</addressOffset>
          <size>0x20</size>
        </register>
        <register>
          <name>FGCLUT.253</name>
          <addressOffset>0x7f4</addressOffset>
          <size>0x20</size>
        </register>
        <register>
          <name>FGCLUT.254</name>
          <addressOffset>0x7f8</addressOffset>
          <size>0x20</size>
        </register>
        <register>
          <name>FGCLUT.255</name>
          <addressOffset>0x7fc</addressOffset>
          <size>0x20</size>
        </register>
        <register>
          <name>BGCLUT.0</name>
          <addressOffset>0x800</addressOffset>
          <size>0x20</size>
        </register>
        <register>
          <name>BGCLUT.1</name>
          <addressOffset>0x804</addressOffset>
          <size>0x20</size>
        </register>
        <register>
          <name>BGCLUT.2</name>
          <addressOffset>0x808</addressOffset>
          <size>0x20</size>
        </register>
        <register>
          <name>BGCLUT.3</name>
          <addressOffset>0x80c</addressOffset>
          <size>0x20</size>
        </register>
        <register>
          <name>BGCLUT.4</name>
          <addressOffset>0x810</addressOffset>
          <size>0x20</size>
        </register>
        <register>
          <name>BGCLUT.5</name>
          <addressOffset>0x814</addressOffset>
          <size>0x20</size>
        </register>
        <register>
          <name>BGCLUT.6</name>
          <addressOffset>0x818</addressOffset>
          <size>0x20</size>
        </register>
        <register>
          <name>BGCLUT.7</name>
          <addressOffset>0x81c</addressOffset>
          <size>0x20</size>
        </register>
        <register>
          <name>BGCLUT.8</name>
          <addressOffset>0x820</addressOffset>
          <size>0x20</size>
        </register>
        <register>
          <name>BGCLUT.9</name>
          <addressOffset>0x824</addressOffset>
          <size>0x20</size>
        </register>
        <register>
          <name>BGCLUT.10</name>
          <addressOffset>0x828</addressOffset>
          <size>0x20</size>
        </register>
        <register>
          <name>BGCLUT.11</name>
          <addressOffset>0x82c</addressOffset>
          <size>0x20</size>
        </register>
        <register>
          <name>BGCLUT.12</name>
          <addressOffset>0x830</addressOffset>
          <size>0x20</size>
        </register>
        <register>
          <name>BGCLUT.13</name>
          <addressOffset>0x834</addressOffset>
          <size>0x20</size>
        </register>
        <register>
          <name>BGCLUT.14</name>
          <addressOffset>0x838</addressOffset>
          <size>0x20</size>
        </register>
        <register>
          <name>BGCLUT.15</name>
          <addressOffset>0x83c</addressOffset>
          <size>0x20</size>
        </register>
        <register>
          <name>BGCLUT.16</name>
          <addressOffset>0x840</addressOffset>
          <size>0x20</size>
        </register>
        <register>
          <name>BGCLUT.17</name>
          <addressOffset>0x844</addressOffset>
          <size>0x20</size>
        </register>
        <register>
          <name>BGCLUT.18</name>
          <addressOffset>0x848</addressOffset>
          <size>0x20</size>
        </register>
        <register>
          <name>BGCLUT.19</name>
          <addressOffset>0x84c</addressOffset>
          <size>0x20</size>
        </register>
        <register>
          <name>BGCLUT.20</name>
          <addressOffset>0x850</addressOffset>
          <size>0x20</size>
        </register>
        <register>
          <name>BGCLUT.21</name>
          <addressOffset>0x854</addressOffset>
          <size>0x20</size>
        </register>
        <register>
          <name>BGCLUT.22</name>
          <addressOffset>0x858</addressOffset>
          <size>0x20</size>
        </register>
        <register>
          <name>BGCLUT.23</name>
          <addressOffset>0x85c</addressOffset>
          <size>0x20</size>
        </register>
        <register>
          <name>BGCLUT.24</name>
          <addressOffset>0x860</addressOffset>
          <size>0x20</size>
        </register>
        <register>
          <name>BGCLUT.25</name>
          <addressOffset>0x864</addressOffset>
          <size>0x20</size>
        </register>
        <register>
          <name>BGCLUT.26</name>
          <addressOffset>0x868</addressOffset>
          <size>0x20</size>
        </register>
        <register>
          <name>BGCLUT.27</name>
          <addressOffset>0x86c</addressOffset>
          <size>0x20</size>
        </register>
        <register>
          <name>BGCLUT.28</name>
          <addressOffset>0x870</addressOffset>
          <size>0x20</size>
        </register>
        <register>
          <name>BGCLUT.29</name>
          <addressOffset>0x874</addressOffset>
          <size>0x20</size>
        </register>
        <register>
          <name>BGCLUT.30</name>
          <addressOffset>0x878</addressOffset>
          <size>0x20</size>
        </register>
        <register>
          <name>BGCLUT.31</name>
          <addressOffset>0x87c</addressOffset>
          <size>0x20</size>
        </register>
        <register>
          <name>BGCLUT.32</name>
          <addressOffset>0x880</addressOffset>
          <size>0x20</size>
        </register>
        <register>
          <name>BGCLUT.33</name>
          <addressOffset>0x884</addressOffset>
          <size>0x20</size>
        </register>
        <register>
          <name>BGCLUT.34</name>
          <addressOffset>0x888</addressOffset>
          <size>0x20</size>
        </register>
        <register>
          <name>BGCLUT.35</name>
          <addressOffset>0x88c</addressOffset>
          <size>0x20</size>
        </register>
        <register>
          <name>BGCLUT.36</name>
          <addressOffset>0x890</addressOffset>
          <size>0x20</size>
        </register>
        <register>
          <name>BGCLUT.37</name>
          <addressOffset>0x894</addressOffset>
          <size>0x20</size>
        </register>
        <register>
          <name>BGCLUT.38</name>
          <addressOffset>0x898</addressOffset>
          <size>0x20</size>
        </register>
        <register>
          <name>BGCLUT.39</name>
          <addressOffset>0x89c</addressOffset>
          <size>0x20</size>
        </register>
        <register>
          <name>BGCLUT.40</name>
          <addressOffset>0x8a0</addressOffset>
          <size>0x20</size>
        </register>
        <register>
          <name>BGCLUT.41</name>
          <addressOffset>0x8a4</addressOffset>
          <size>0x20</size>
        </register>
        <register>
          <name>BGCLUT.42</name>
          <addressOffset>0x8a8</addressOffset>
          <size>0x20</size>
        </register>
        <register>
          <name>BGCLUT.43</name>
          <addressOffset>0x8ac</addressOffset>
          <size>0x20</size>
        </register>
        <register>
          <name>BGCLUT.44</name>
          <addressOffset>0x8b0</addressOffset>
          <size>0x20</size>
        </register>
        <register>
          <name>BGCLUT.45</name>
          <addressOffset>0x8b4</addressOffset>
          <size>0x20</size>
        </register>
        <register>
          <name>BGCLUT.46</name>
          <addressOffset>0x8b8</addressOffset>
          <size>0x20</size>
        </register>
        <register>
          <name>BGCLUT.47</name>
          <addressOffset>0x8bc</addressOffset>
          <size>0x20</size>
        </register>
        <register>
          <name>BGCLUT.48</name>
          <addressOffset>0x8c0</addressOffset>
          <size>0x20</size>
        </register>
        <register>
          <name>BGCLUT.49</name>
          <addressOffset>0x8c4</addressOffset>
          <size>0x20</size>
        </register>
        <register>
          <name>BGCLUT.50</name>
          <addressOffset>0x8c8</addressOffset>
          <size>0x20</size>
        </register>
        <register>
          <name>BGCLUT.51</name>
          <addressOffset>0x8cc</addressOffset>
          <size>0x20</size>
        </register>
        <register>
          <name>BGCLUT.52</name>
          <addressOffset>0x8d0</addressOffset>
          <size>0x20</size>
        </register>
        <register>
          <name>BGCLUT.53</name>
          <addressOffset>0x8d4</addressOffset>
          <size>0x20</size>
        </register>
        <register>
          <name>BGCLUT.54</name>
          <addressOffset>0x8d8</addressOffset>
          <size>0x20</size>
        </register>
        <register>
          <name>BGCLUT.55</name>
          <addressOffset>0x8dc</addressOffset>
          <size>0x20</size>
        </register>
        <register>
          <name>BGCLUT.56</name>
          <addressOffset>0x8e0</addressOffset>
          <size>0x20</size>
        </register>
        <register>
          <name>BGCLUT.57</name>
          <addressOffset>0x8e4</addressOffset>
          <size>0x20</size>
        </register>
        <register>
          <name>BGCLUT.58</name>
          <addressOffset>0x8e8</addressOffset>
          <size>0x20</size>
        </register>
        <register>
          <name>BGCLUT.59</name>
          <addressOffset>0x8ec</addressOffset>
          <size>0x20</size>
        </register>
        <register>
          <name>BGCLUT.60</name>
          <addressOffset>0x8f0</addressOffset>
          <size>0x20</size>
        </register>
        <register>
          <name>BGCLUT.61</name>
          <addressOffset>0x8f4</addressOffset>
          <size>0x20</size>
        </register>
        <register>
          <name>BGCLUT.62</name>
          <addressOffset>0x8f8</addressOffset>
          <size>0x20</size>
        </register>
        <register>
          <name>BGCLUT.63</name>
          <addressOffset>0x8fc</addressOffset>
          <size>0x20</size>
        </register>
        <register>
          <name>BGCLUT.64</name>
          <addressOffset>0x900</addressOffset>
          <size>0x20</size>
        </register>
        <register>
          <name>BGCLUT.65</name>
          <addressOffset>0x904</addressOffset>
          <size>0x20</size>
        </register>
        <register>
          <name>BGCLUT.66</name>
          <addressOffset>0x908</addressOffset>
          <size>0x20</size>
        </register>
        <register>
          <name>BGCLUT.67</name>
          <addressOffset>0x90c</addressOffset>
          <size>0x20</size>
        </register>
        <register>
          <name>BGCLUT.68</name>
          <addressOffset>0x910</addressOffset>
          <size>0x20</size>
        </register>
        <register>
          <name>BGCLUT.69</name>
          <addressOffset>0x914</addressOffset>
          <size>0x20</size>
        </register>
        <register>
          <name>BGCLUT.70</name>
          <addressOffset>0x918</addressOffset>
          <size>0x20</size>
        </register>
        <register>
          <name>BGCLUT.71</name>
          <addressOffset>0x91c</addressOffset>
          <size>0x20</size>
        </register>
        <register>
          <name>BGCLUT.72</name>
          <addressOffset>0x920</addressOffset>
          <size>0x20</size>
        </register>
        <register>
          <name>BGCLUT.73</name>
          <addressOffset>0x924</addressOffset>
          <size>0x20</size>
        </register>
        <register>
          <name>BGCLUT.74</name>
          <addressOffset>0x928</addressOffset>
          <size>0x20</size>
        </register>
        <register>
          <name>BGCLUT.75</name>
          <addressOffset>0x92c</addressOffset>
          <size>0x20</size>
        </register>
        <register>
          <name>BGCLUT.76</name>
          <addressOffset>0x930</addressOffset>
          <size>0x20</size>
        </register>
        <register>
          <name>BGCLUT.77</name>
          <addressOffset>0x934</addressOffset>
          <size>0x20</size>
        </register>
        <register>
          <name>BGCLUT.78</name>
          <addressOffset>0x938</addressOffset>
          <size>0x20</size>
        </register>
        <register>
          <name>BGCLUT.79</name>
          <addressOffset>0x93c</addressOffset>
          <size>0x20</size>
        </register>
        <register>
          <name>BGCLUT.80</name>
          <addressOffset>0x940</addressOffset>
          <size>0x20</size>
        </register>
        <register>
          <name>BGCLUT.81</name>
          <addressOffset>0x944</addressOffset>
          <size>0x20</size>
        </register>
        <register>
          <name>BGCLUT.82</name>
          <addressOffset>0x948</addressOffset>
          <size>0x20</size>
        </register>
        <register>
          <name>BGCLUT.83</name>
          <addressOffset>0x94c</addressOffset>
          <size>0x20</size>
        </register>
        <register>
          <name>BGCLUT.84</name>
          <addressOffset>0x950</addressOffset>
          <size>0x20</size>
        </register>
        <register>
          <name>BGCLUT.85</name>
          <addressOffset>0x954</addressOffset>
          <size>0x20</size>
        </register>
        <register>
          <name>BGCLUT.86</name>
          <addressOffset>0x958</addressOffset>
          <size>0x20</size>
        </register>
        <register>
          <name>BGCLUT.87</name>
          <addressOffset>0x95c</addressOffset>
          <size>0x20</size>
        </register>
        <register>
          <name>BGCLUT.88</name>
          <addressOffset>0x960</addressOffset>
          <size>0x20</size>
        </register>
        <register>
          <name>BGCLUT.89</name>
          <addressOffset>0x964</addressOffset>
          <size>0x20</size>
        </register>
        <register>
          <name>BGCLUT.90</name>
          <addressOffset>0x968</addressOffset>
          <size>0x20</size>
        </register>
        <register>
          <name>BGCLUT.91</name>
          <addressOffset>0x96c</addressOffset>
          <size>0x20</size>
        </register>
        <register>
          <name>BGCLUT.92</name>
          <addressOffset>0x970</addressOffset>
          <size>0x20</size>
        </register>
        <register>
          <name>BGCLUT.93</name>
          <addressOffset>0x974</addressOffset>
          <size>0x20</size>
        </register>
        <register>
          <name>BGCLUT.94</name>
          <addressOffset>0x978</addressOffset>
          <size>0x20</size>
        </register>
        <register>
          <name>BGCLUT.95</name>
          <addressOffset>0x97c</addressOffset>
          <size>0x20</size>
        </register>
        <register>
          <name>BGCLUT.96</name>
          <addressOffset>0x980</addressOffset>
          <size>0x20</size>
        </register>
        <register>
          <name>BGCLUT.97</name>
          <addressOffset>0x984</addressOffset>
          <size>0x20</size>
        </register>
        <register>
          <name>BGCLUT.98</name>
          <addressOffset>0x988</addressOffset>
          <size>0x20</size>
        </register>
        <register>
          <name>BGCLUT.99</name>
          <addressOffset>0x98c</addressOffset>
          <size>0x20</size>
        </register>
        <register>
          <name>BGCLUT.100</name>
          <addressOffset>0x990</addressOffset>
          <size>0x20</size>
        </register>
        <register>
          <name>BGCLUT.101</name>
          <addressOffset>0x994</addressOffset>
          <size>0x20</size>
        </register>
        <register>
          <name>BGCLUT.102</name>
          <addressOffset>0x998</addressOffset>
          <size>0x20</size>
        </register>
        <register>
          <name>BGCLUT.103</name>
          <addressOffset>0x99c</addressOffset>
          <size>0x20</size>
        </register>
        <register>
          <name>BGCLUT.104</name>
          <addressOffset>0x9a0</addressOffset>
          <size>0x20</size>
        </register>
        <register>
          <name>BGCLUT.105</name>
          <addressOffset>0x9a4</addressOffset>
          <size>0x20</size>
        </register>
        <register>
          <name>BGCLUT.106</name>
          <addressOffset>0x9a8</addressOffset>
          <size>0x20</size>
        </register>
        <register>
          <name>BGCLUT.107</name>
          <addressOffset>0x9ac</addressOffset>
          <size>0x20</size>
        </register>
        <register>
          <name>BGCLUT.108</name>
          <addressOffset>0x9b0</addressOffset>
          <size>0x20</size>
        </register>
        <register>
          <name>BGCLUT.109</name>
          <addressOffset>0x9b4</addressOffset>
          <size>0x20</size>
        </register>
        <register>
          <name>BGCLUT.110</name>
          <addressOffset>0x9b8</addressOffset>
          <size>0x20</size>
        </register>
        <register>
          <name>BGCLUT.111</name>
          <addressOffset>0x9bc</addressOffset>
          <size>0x20</size>
        </register>
        <register>
          <name>BGCLUT.112</name>
          <addressOffset>0x9c0</addressOffset>
          <size>0x20</size>
        </register>
        <register>
          <name>BGCLUT.113</name>
          <addressOffset>0x9c4</addressOffset>
          <size>0x20</size>
        </register>
        <register>
          <name>BGCLUT.114</name>
          <addressOffset>0x9c8</addressOffset>
          <size>0x20</size>
        </register>
        <register>
          <name>BGCLUT.115</name>
          <addressOffset>0x9cc</addressOffset>
          <size>0x20</size>
        </register>
        <register>
          <name>BGCLUT.116</name>
          <addressOffset>0x9d0</addressOffset>
          <size>0x20</size>
        </register>
        <register>
          <name>BGCLUT.117</name>
          <addressOffset>0x9d4</addressOffset>
          <size>0x20</size>
        </register>
        <register>
          <name>BGCLUT.118</name>
          <addressOffset>0x9d8</addressOffset>
          <size>0x20</size>
        </register>
        <register>
          <name>BGCLUT.119</name>
          <addressOffset>0x9dc</addressOffset>
          <size>0x20</size>
        </register>
        <register>
          <name>BGCLUT.120</name>
          <addressOffset>0x9e0</addressOffset>
          <size>0x20</size>
        </register>
        <register>
          <name>BGCLUT.121</name>
          <addressOffset>0x9e4</addressOffset>
          <size>0x20</size>
        </register>
        <register>
          <name>BGCLUT.122</name>
          <addressOffset>0x9e8</addressOffset>
          <size>0x20</size>
        </register>
        <register>
          <name>BGCLUT.123</name>
          <addressOffset>0x9ec</addressOffset>
          <size>0x20</size>
        </register>
        <register>
          <name>BGCLUT.124</name>
          <addressOffset>0x9f0</addressOffset>
          <size>0x20</size>
        </register>
        <register>
          <name>BGCLUT.125</name>
          <addressOffset>0x9f4</addressOffset>
          <size>0x20</size>
        </register>
        <register>
          <name>BGCLUT.126</name>
          <addressOffset>0x9f8</addressOffset>
          <size>0x20</size>
        </register>
        <register>
          <name>BGCLUT.127</name>
          <addressOffset>0x9fc</addressOffset>
          <size>0x20</size>
        </register>
        <register>
          <name>BGCLUT.128</name>
          <addressOffset>0xa00</addressOffset>
          <size>0x20</size>
        </register>
        <register>
          <name>BGCLUT.129</name>
          <addressOffset>0xa04</addressOffset>
          <size>0x20</size>
        </register>
        <register>
          <name>BGCLUT.130</name>
          <addressOffset>0xa08</addressOffset>
          <size>0x20</size>
        </register>
        <register>
          <name>BGCLUT.131</name>
          <addressOffset>0xa0c</addressOffset>
          <size>0x20</size>
        </register>
        <register>
          <name>BGCLUT.132</name>
          <addressOffset>0xa10</addressOffset>
          <size>0x20</size>
        </register>
        <register>
          <name>BGCLUT.133</name>
          <addressOffset>0xa14</addressOffset>
          <size>0x20</size>
        </register>
        <register>
          <name>BGCLUT.134</name>
          <addressOffset>0xa18</addressOffset>
          <size>0x20</size>
        </register>
        <register>
          <name>BGCLUT.135</name>
          <addressOffset>0xa1c</addressOffset>
          <size>0x20</size>
        </register>
        <register>
          <name>BGCLUT.136</name>
          <addressOffset>0xa20</addressOffset>
          <size>0x20</size>
        </register>
        <register>
          <name>BGCLUT.137</name>
          <addressOffset>0xa24</addressOffset>
          <size>0x20</size>
        </register>
        <register>
          <name>BGCLUT.138</name>
          <addressOffset>0xa28</addressOffset>
          <size>0x20</size>
        </register>
        <register>
          <name>BGCLUT.139</name>
          <addressOffset>0xa2c</addressOffset>
          <size>0x20</size>
        </register>
        <register>
          <name>BGCLUT.140</name>
          <addressOffset>0xa30</addressOffset>
          <size>0x20</size>
        </register>
        <register>
          <name>BGCLUT.141</name>
          <addressOffset>0xa34</addressOffset>
          <size>0x20</size>
        </register>
        <register>
          <name>BGCLUT.142</name>
          <addressOffset>0xa38</addressOffset>
          <size>0x20</size>
        </register>
        <register>
          <name>BGCLUT.143</name>
          <addressOffset>0xa3c</addressOffset>
          <size>0x20</size>
        </register>
        <register>
          <name>BGCLUT.144</name>
          <addressOffset>0xa40</addressOffset>
          <size>0x20</size>
        </register>
        <register>
          <name>BGCLUT.145</name>
          <addressOffset>0xa44</addressOffset>
          <size>0x20</size>
        </register>
        <register>
          <name>BGCLUT.146</name>
          <addressOffset>0xa48</addressOffset>
          <size>0x20</size>
        </register>
        <register>
          <name>BGCLUT.147</name>
          <addressOffset>0xa4c</addressOffset>
          <size>0x20</size>
        </register>
        <register>
          <name>BGCLUT.148</name>
          <addressOffset>0xa50</addressOffset>
          <size>0x20</size>
        </register>
        <register>
          <name>BGCLUT.149</name>
          <addressOffset>0xa54</addressOffset>
          <size>0x20</size>
        </register>
        <register>
          <name>BGCLUT.150</name>
          <addressOffset>0xa58</addressOffset>
          <size>0x20</size>
        </register>
        <register>
          <name>BGCLUT.151</name>
          <addressOffset>0xa5c</addressOffset>
          <size>0x20</size>
        </register>
        <register>
          <name>BGCLUT.152</name>
          <addressOffset>0xa60</addressOffset>
          <size>0x20</size>
        </register>
        <register>
          <name>BGCLUT.153</name>
          <addressOffset>0xa64</addressOffset>
          <size>0x20</size>
        </register>
        <register>
          <name>BGCLUT.154</name>
          <addressOffset>0xa68</addressOffset>
          <size>0x20</size>
        </register>
        <register>
          <name>BGCLUT.155</name>
          <addressOffset>0xa6c</addressOffset>
          <size>0x20</size>
        </register>
        <register>
          <name>BGCLUT.156</name>
          <addressOffset>0xa70</addressOffset>
          <size>0x20</size>
        </register>
        <register>
          <name>BGCLUT.157</name>
          <addressOffset>0xa74</addressOffset>
          <size>0x20</size>
        </register>
        <register>
          <name>BGCLUT.158</name>
          <addressOffset>0xa78</addressOffset>
          <size>0x20</size>
        </register>
        <register>
          <name>BGCLUT.159</name>
          <addressOffset>0xa7c</addressOffset>
          <size>0x20</size>
        </register>
        <register>
          <name>BGCLUT.160</name>
          <addressOffset>0xa80</addressOffset>
          <size>0x20</size>
        </register>
        <register>
          <name>BGCLUT.161</name>
          <addressOffset>0xa84</addressOffset>
          <size>0x20</size>
        </register>
        <register>
          <name>BGCLUT.162</name>
          <addressOffset>0xa88</addressOffset>
          <size>0x20</size>
        </register>
        <register>
          <name>BGCLUT.163</name>
          <addressOffset>0xa8c</addressOffset>
          <size>0x20</size>
        </register>
        <register>
          <name>BGCLUT.164</name>
          <addressOffset>0xa90</addressOffset>
          <size>0x20</size>
        </register>
        <register>
          <name>BGCLUT.165</name>
          <addressOffset>0xa94</addressOffset>
          <size>0x20</size>
        </register>
        <register>
          <name>BGCLUT.166</name>
          <addressOffset>0xa98</addressOffset>
          <size>0x20</size>
        </register>
        <register>
          <name>BGCLUT.167</name>
          <addressOffset>0xa9c</addressOffset>
          <size>0x20</size>
        </register>
        <register>
          <name>BGCLUT.168</name>
          <addressOffset>0xaa0</addressOffset>
          <size>0x20</size>
        </register>
        <register>
          <name>BGCLUT.169</name>
          <addressOffset>0xaa4</addressOffset>
          <size>0x20</size>
        </register>
        <register>
          <name>BGCLUT.170</name>
          <addressOffset>0xaa8</addressOffset>
          <size>0x20</size>
        </register>
        <register>
          <name>BGCLUT.171</name>
          <addressOffset>0xaac</addressOffset>
          <size>0x20</size>
        </register>
        <register>
          <name>BGCLUT.172</name>
          <addressOffset>0xab0</addressOffset>
          <size>0x20</size>
        </register>
        <register>
          <name>BGCLUT.173</name>
          <addressOffset>0xab4</addressOffset>
          <size>0x20</size>
        </register>
        <register>
          <name>BGCLUT.174</name>
          <addressOffset>0xab8</addressOffset>
          <size>0x20</size>
        </register>
        <register>
          <name>BGCLUT.175</name>
          <addressOffset>0xabc</addressOffset>
          <size>0x20</size>
        </register>
        <register>
          <name>BGCLUT.176</name>
          <addressOffset>0xac0</addressOffset>
          <size>0x20</size>
        </register>
        <register>
          <name>BGCLUT.177</name>
          <addressOffset>0xac4</addressOffset>
          <size>0x20</size>
        </register>
        <register>
          <name>BGCLUT.178</name>
          <addressOffset>0xac8</addressOffset>
          <size>0x20</size>
        </register>
        <register>
          <name>BGCLUT.179</name>
          <addressOffset>0xacc</addressOffset>
          <size>0x20</size>
        </register>
        <register>
          <name>BGCLUT.180</name>
          <addressOffset>0xad0</addressOffset>
          <size>0x20</size>
        </register>
        <register>
          <name>BGCLUT.181</name>
          <addressOffset>0xad4</addressOffset>
          <size>0x20</size>
        </register>
        <register>
          <name>BGCLUT.182</name>
          <addressOffset>0xad8</addressOffset>
          <size>0x20</size>
        </register>
        <register>
          <name>BGCLUT.183</name>
          <addressOffset>0xadc</addressOffset>
          <size>0x20</size>
        </register>
        <register>
          <name>BGCLUT.184</name>
          <addressOffset>0xae0</addressOffset>
          <size>0x20</size>
        </register>
        <register>
          <name>BGCLUT.185</name>
          <addressOffset>0xae4</addressOffset>
          <size>0x20</size>
        </register>
        <register>
          <name>BGCLUT.186</name>
          <addressOffset>0xae8</addressOffset>
          <size>0x20</size>
        </register>
        <register>
          <name>BGCLUT.187</name>
          <addressOffset>0xaec</addressOffset>
          <size>0x20</size>
        </register>
        <register>
          <name>BGCLUT.188</name>
          <addressOffset>0xaf0</addressOffset>
          <size>0x20</size>
        </register>
        <register>
          <name>BGCLUT.189</name>
          <addressOffset>0xaf4</addressOffset>
          <size>0x20</size>
        </register>
        <register>
          <name>BGCLUT.190</name>
          <addressOffset>0xaf8</addressOffset>
          <size>0x20</size>
        </register>
        <register>
          <name>BGCLUT.191</name>
          <addressOffset>0xafc</addressOffset>
          <size>0x20</size>
        </register>
        <register>
          <name>BGCLUT.192</name>
          <addressOffset>0xb00</addressOffset>
          <size>0x20</size>
        </register>
        <register>
          <name>BGCLUT.193</name>
          <addressOffset>0xb04</addressOffset>
          <size>0x20</size>
        </register>
        <register>
          <name>BGCLUT.194</name>
          <addressOffset>0xb08</addressOffset>
          <size>0x20</size>
        </register>
        <register>
          <name>BGCLUT.195</name>
          <addressOffset>0xb0c</addressOffset>
          <size>0x20</size>
        </register>
        <register>
          <name>BGCLUT.196</name>
          <addressOffset>0xb10</addressOffset>
          <size>0x20</size>
        </register>
        <register>
          <name>BGCLUT.197</name>
          <addressOffset>0xb14</addressOffset>
          <size>0x20</size>
        </register>
        <register>
          <name>BGCLUT.198</name>
          <addressOffset>0xb18</addressOffset>
          <size>0x20</size>
        </register>
        <register>
          <name>BGCLUT.199</name>
          <addressOffset>0xb1c</addressOffset>
          <size>0x20</size>
        </register>
        <register>
          <name>BGCLUT.200</name>
          <addressOffset>0xb20</addressOffset>
          <size>0x20</size>
        </register>
        <register>
          <name>BGCLUT.201</name>
          <addressOffset>0xb24</addressOffset>
          <size>0x20</size>
        </register>
        <register>
          <name>BGCLUT.202</name>
          <addressOffset>0xb28</addressOffset>
          <size>0x20</size>
        </register>
        <register>
          <name>BGCLUT.203</name>
          <addressOffset>0xb2c</addressOffset>
          <size>0x20</size>
        </register>
        <register>
          <name>BGCLUT.204</name>
          <addressOffset>0xb30</addressOffset>
          <size>0x20</size>
        </register>
        <register>
          <name>BGCLUT.205</name>
          <addressOffset>0xb34</addressOffset>
          <size>0x20</size>
        </register>
        <register>
          <name>BGCLUT.206</name>
          <addressOffset>0xb38</addressOffset>
          <size>0x20</size>
        </register>
        <register>
          <name>BGCLUT.207</name>
          <addressOffset>0xb3c</addressOffset>
          <size>0x20</size>
        </register>
        <register>
          <name>BGCLUT.208</name>
          <addressOffset>0xb40</addressOffset>
          <size>0x20</size>
        </register>
        <register>
          <name>BGCLUT.209</name>
          <addressOffset>0xb44</addressOffset>
          <size>0x20</size>
        </register>
        <register>
          <name>BGCLUT.210</name>
          <addressOffset>0xb48</addressOffset>
          <size>0x20</size>
        </register>
        <register>
          <name>BGCLUT.211</name>
          <addressOffset>0xb4c</addressOffset>
          <size>0x20</size>
        </register>
        <register>
          <name>BGCLUT.212</name>
          <addressOffset>0xb50</addressOffset>
          <size>0x20</size>
        </register>
        <register>
          <name>BGCLUT.213</name>
          <addressOffset>0xb54</addressOffset>
          <size>0x20</size>
        </register>
        <register>
          <name>BGCLUT.214</name>
          <addressOffset>0xb58</addressOffset>
          <size>0x20</size>
        </register>
        <register>
          <name>BGCLUT.215</name>
          <addressOffset>0xb5c</addressOffset>
          <size>0x20</size>
        </register>
        <register>
          <name>BGCLUT.216</name>
          <addressOffset>0xb60</addressOffset>
          <size>0x20</size>
        </register>
        <register>
          <name>BGCLUT.217</name>
          <addressOffset>0xb64</addressOffset>
          <size>0x20</size>
        </register>
        <register>
          <name>BGCLUT.218</name>
          <addressOffset>0xb68</addressOffset>
          <size>0x20</size>
        </register>
        <register>
          <name>BGCLUT.219</name>
          <addressOffset>0xb6c</addressOffset>
          <size>0x20</size>
        </register>
        <register>
          <name>BGCLUT.220</name>
          <addressOffset>0xb70</addressOffset>
          <size>0x20</size>
        </register>
        <register>
          <name>BGCLUT.221</name>
          <addressOffset>0xb74</addressOffset>
          <size>0x20</size>
        </register>
        <register>
          <name>BGCLUT.222</name>
          <addressOffset>0xb78</addressOffset>
          <size>0x20</size>
        </register>
        <register>
          <name>BGCLUT.223</name>
          <addressOffset>0xb7c</addressOffset>
          <size>0x20</size>
        </register>
        <register>
          <name>BGCLUT.224</name>
          <addressOffset>0xb80</addressOffset>
          <size>0x20</size>
        </register>
        <register>
          <name>BGCLUT.225</name>
          <addressOffset>0xb84</addressOffset>
          <size>0x20</size>
        </register>
        <register>
          <name>BGCLUT.226</name>
          <addressOffset>0xb88</addressOffset>
          <size>0x20</size>
        </register>
        <register>
          <name>BGCLUT.227</name>
          <addressOffset>0xb8c</addressOffset>
          <size>0x20</size>
        </register>
        <register>
          <name>BGCLUT.228</name>
          <addressOffset>0xb90</addressOffset>
          <size>0x20</size>
        </register>
        <register>
          <name>BGCLUT.229</name>
          <addressOffset>0xb94</addressOffset>
          <size>0x20</size>
        </register>
        <register>
          <name>BGCLUT.230</name>
          <addressOffset>0xb98</addressOffset>
          <size>0x20</size>
        </register>
        <register>
          <name>BGCLUT.231</name>
          <addressOffset>0xb9c</addressOffset>
          <size>0x20</size>
        </register>
        <register>
          <name>BGCLUT.232</name>
          <addressOffset>0xba0</addressOffset>
          <size>0x20</size>
        </register>
        <register>
          <name>BGCLUT.233</name>
          <addressOffset>0xba4</addressOffset>
          <size>0x20</size>
        </register>
        <register>
          <name>BGCLUT.234</name>
          <addressOffset>0xba8</addressOffset>
          <size>0x20</size>
        </register>
        <register>
          <name>BGCLUT.235</name>
          <addressOffset>0xbac</addressOffset>
          <size>0x20</size>
        </register>
        <register>
          <name>BGCLUT.236</name>
          <addressOffset>0xbb0</addressOffset>
          <size>0x20</size>
        </register>
        <register>
          <name>BGCLUT.237</name>
          <addressOffset>0xbb4</addressOffset>
          <size>0x20</size>
        </register>
        <register>
          <name>BGCLUT.238</name>
          <addressOffset>0xbb8</addressOffset>
          <size>0x20</size>
        </register>
        <register>
          <name>BGCLUT.239</name>
          <addressOffset>0xbbc</addressOffset>
          <size>0x20</size>
        </register>
        <register>
          <name>BGCLUT.240</name>
          <addressOffset>0xbc0</addressOffset>
          <size>0x20</size>
        </register>
        <register>
          <name>BGCLUT.241</name>
          <addressOffset>0xbc4</addressOffset>
          <size>0x20</size>
        </register>
        <register>
          <name>BGCLUT.242</name>
          <addressOffset>0xbc8</addressOffset>
          <size>0x20</size>
        </register>
        <register>
          <name>BGCLUT.243</name>
          <addressOffset>0xbcc</addressOffset>
          <size>0x20</size>
        </register>
        <register>
          <name>BGCLUT.244</name>
          <addressOffset>0xbd0</addressOffset>
          <size>0x20</size>
        </register>
        <register>
          <name>BGCLUT.245</name>
          <addressOffset>0xbd4</addressOffset>
          <size>0x20</size>
        </register>
        <register>
          <name>BGCLUT.246</name>
          <addressOffset>0xbd8</addressOffset>
          <size>0x20</size>
        </register>
        <register>
          <name>BGCLUT.247</name>
          <addressOffset>0xbdc</addressOffset>
          <size>0x20</size>
        </register>
        <register>
          <name>BGCLUT.248</name>
          <addressOffset>0xbe0</addressOffset>
          <size>0x20</size>
        </register>
        <register>
          <name>BGCLUT.249</name>
          <addressOffset>0xbe4</addressOffset>
          <size>0x20</size>
        </register>
        <register>
          <name>BGCLUT.250</name>
          <addressOffset>0xbe8</addressOffset>
          <size>0x20</size>
        </register>
        <register>
          <name>BGCLUT.251</name>
          <addressOffset>0xbec</addressOffset>
          <size>0x20</size>
        </register>
        <register>
          <name>BGCLUT.252</name>
          <addressOffset>0xbf0</addressOffset>
          <size>0x20</size>
        </register>
        <register>
          <name>BGCLUT.253</name>
          <addressOffset>0xbf4</addressOffset>
          <size>0x20</size>
        </register>
        <register>
          <name>BGCLUT.254</name>
          <addressOffset>0xbf8</addressOffset>
          <size>0x20</size>
        </register>
        <register>
          <name>BGCLUT.255</name>
          <addressOffset>0xbfc</addressOffset>
          <size>0x20</size>
        </register>
      </registers>
    </peripheral>
    <peripheral>
      <name>USB_OTG_HS</name>
      <baseAddress>0x40040000</baseAddress>
      <registers>
        <register>
          <name>GOTGCTL</name>
          <addressOffset>0x0</addressOffset>
          <size>0x20</size>
          <fields>
            <field>
              <name>SRQSCS</name>
              <bitOffset>0</bitOffset>
              <bitWidth>1</bitWidth>
            </field>
            <field>
              <name>SRQ</name>
              <bitOffset>1</bitOffset>
              <bitWidth>1</bitWidth>
            </field>
            <field>
              <name>HNGSCS</name>
              <bitOffset>8</bitOffset>
              <bitWidth>1</bitWidth>
            </field>
            <field>
              <name>HNPRQ</name>
              <bitOffset>9</bitOffset>
              <bitWidth>1</bitWidth>
            </field>
            <field>
              <name>HSHNPEN</name>
              <bitOffset>10</bitOffset>
              <bitWidth>1</bitWidth>
            </field>
            <field>
              <name>DHNPEN</name>
              <bitOffset>11</bitOffset>
              <bitWidth>1</bitWidth>
            </field>
            <field>
              <name>CIDSTS</name>
              <bitOffset>16</bitOffset>
              <bitWidth>1</bitWidth>
            </field>
            <field>
              <name>DBCT</name>
              <bitOffset>17</bitOffset>
              <bitWidth>1</bitWidth>
            </field>
            <field>
              <name>ASVLD</name>
              <bitOffset>18</bitOffset>
              <bitWidth>1</bitWidth>
            </field>
            <field>
              <name>BSVLD</name>
              <bitOffset>19</bitOffset>
              <bitWidth>1</bitWidth>
            </field>
          </fields>
        </register>
        <register>
          <name>GOTGINT</name>
          <addressOffset>0x4</addressOffset>
          <size>0x20</size>
          <fields>
            <field>
              <name>SEDET</name>
              <bitOffset>2</bitOffset>
              <bitWidth>1</bitWidth>
            </field>
            <field>
              <name>SRSSCHG</name>
              <bitOffset>8</bitOffset>
              <bitWidth>1</bitWidth>
            </field>
            <field>
              <name>HNSSCHG</name>
              <bitOffset>9</bitOffset>
              <bitWidth>1</bitWidth>
            </field>
            <field>
              <name>HNGDET</name>
              <bitOffset>17</bitOffset>
              <bitWidth>1</bitWidth>
            </field>
            <field>
              <name>ADTOCHG</name>
              <bitOffset>18</bitOffset>
              <bitWidth>1</bitWidth>
            </field>
            <field>
              <name>DBCDNE</name>
              <bitOffset>19</bitOffset>
              <bitWidth>1</bitWidth>
            </field>
          </fields>
        </register>
        <register>
          <name>GAHBCFG</name>
          <addressOffset>0x8</addressOffset>
          <size>0x20</size>
          <fields>
            <field>
              <name>GINT</name>
              <bitOffset>0</bitOffset>
              <bitWidth>1</bitWidth>
            </field>
            <field>
              <name>HBSTLEN</name>
              <bitOffset>1</bitOffset>
              <bitWidth>4</bitWidth>
            </field>
            <field>
              <name>DMAEN</name>
              <bitOffset>5</bitOffset>
              <bitWidth>1</bitWidth>
            </field>
            <field>
              <name>TXFELVL</name>
              <bitOffset>7</bitOffset>
              <bitWidth>1</bitWidth>
            </field>
            <field>
              <name>PTXFELVL</name>
              <bitOffset>8</bitOffset>
              <bitWidth>1</bitWidth>
            </field>
          </fields>
        </register>
        <register>
          <name>GUSBCFG</name>
          <addressOffset>0xc</addressOffset>
          <size>0x20</size>
          <fields>
            <field>
              <name>TOCAL</name>
              <bitOffset>0</bitOffset>
              <bitWidth>3</bitWidth>
            </field>
            <field>
              <name>PHYSEL</name>
              <bitOffset>6</bitOffset>
              <bitWidth>1</bitWidth>
            </field>
            <field>
              <name>SRPCAP</name>
              <bitOffset>8</bitOffset>
              <bitWidth>1</bitWidth>
            </field>
            <field>
              <name>HNPCAP</name>
              <bitOffset>9</bitOffset>
              <bitWidth>1</bitWidth>
            </field>
            <field>
              <name>TRDT</name>
              <bitOffset>10</bitOffset>
              <bitWidth>4</bitWidth>
            </field>
            <field>
              <name>PHYLPCS</name>
              <bitOffset>15</bitOffset>
              <bitWidth>1</bitWidth>
            </field>
            <field>
              <name>ULPIFSLS</name>
              <bitOffset>17</bitOffset>
              <bitWidth>1</bitWidth>
            </field>
            <field>
              <name>ULPIAR</name>
              <bitOffset>18</bitOffset>
              <bitWidth>1</bitWidth>
            </field>
            <field>
              <name>ULPICSM</name>
              <bitOffset>19</bitOffset>
              <bitWidth>1</bitWidth>
            </field>
            <field>
              <name>ULPIEVBUSD</name>
              <bitOffset>20</bitOffset>
              <bitWidth>1</bitWidth>
            </field>
            <field>
              <name>ULPIEVBUSI</name>
              <bitOffset>21</bitOffset>
              <bitWidth>1</bitWidth>
            </field>
            <field>
              <name>TSDPS</name>
              <bitOffset>22</bitOffset>
              <bitWidth>1</bitWidth>
            </field>
            <field>
              <name>PCCI</name>
              <bitOffset>23</bitOffset>
              <bitWidth>1</bitWidth>
            </field>
            <field>
              <name>PTCI</name>
              <bitOffset>24</bitOffset>
              <bitWidth>1</bitWidth>
            </field>
            <field>
              <name>ULPIIPD</name>
              <bitOffset>25</bitOffset>
              <bitWidth>1</bitWidth>
            </field>
            <field>
              <name>FHMOD</name>
              <bitOffset>29</bitOffset>
              <bitWidth>1</bitWidth>
            </field>
            <field>
              <name>FDMOD</name>
              <bitOffset>30</bitOffset>
              <bitWidth>1</bitWidth>
            </field>
            <field>
              <name>CTXPKT</name>
              <bitOffset>31</bitOffset>
              <bitWidth>1</bitWidth>
            </field>
          </fields>
        </register>
        <register>
          <name>GRSTCTL</name>
          <addressOffset>0x10</addressOffset>
          <size>0x20</size>
          <fields>
            <field>
              <name>CSRST</name>
              <bitOffset>0</bitOffset>
              <bitWidth>1</bitWidth>
            </field>
            <field>
              <name>HSRST</name>
              <bitOffset>1</bitOffset>
              <bitWidth>1</bitWidth>
            </field>
            <field>
              <name>FCRST</name>
              <bitOffset>2</bitOffset>
              <bitWidth>1</bitWidth>
            </field>
            <field>
              <name>RXFFLSH</name>
              <bitOffset>4</bitOffset>
              <bitWidth>1</bitWidth>
            </field>
            <field>
              <name>TXFFLSH</name>
              <bitOffset>5</bitOffset>
              <bitWidth>1</bitWidth>
            </field>
            <field>
              <name>TXFNUM</name>
              <bitOffset>6</bitOffset>
              <bitWidth>5</bitWidth>
            </field>
            <field>
              <name>DMAREQ</name>
              <bitOffset>30</bitOffset>
              <bitWidth>1</bitWidth>
            </field>
            <field>
              <name>AHBIDL</name>
              <bitOffset>31</bitOffset>
              <bitWidth>1</bitWidth>
            </field>
          </fields>
        </register>
        <register>
          <name>GINTSTS</name>
          <addressOffset>0x14</addressOffset>
          <size>0x20</size>
          <fields>
            <field>
              <name>CMOD</name>
              <bitOffset>0</bitOffset>
              <bitWidth>1</bitWidth>
            </field>
            <field>
              <name>MMIS</name>
              <bitOffset>1</bitOffset>
              <bitWidth>1</bitWidth>
            </field>
            <field>
              <name>OTGINT</name>
              <bitOffset>2</bitOffset>
              <bitWidth>1</bitWidth>
            </field>
            <field>
              <name>SOF</name>
              <bitOffset>3</bitOffset>
              <bitWidth>1</bitWidth>
            </field>
            <field>
              <name>RXFLVL</name>
              <bitOffset>4</bitOffset>
              <bitWidth>1</bitWidth>
            </field>
            <field>
              <name>NPTXFE</name>
              <bitOffset>5</bitOffset>
              <bitWidth>1</bitWidth>
            </field>
            <field>
              <name>GINAKEFF</name>
              <bitOffset>6</bitOffset>
              <bitWidth>1</bitWidth>
            </field>
            <field>
              <name>BOUTNAKEFF</name>
              <bitOffset>7</bitOffset>
              <bitWidth>1</bitWidth>
            </field>
            <field>
              <name>ESUSP</name>
              <bitOffset>10</bitOffset>
              <bitWidth>1</bitWidth>
            </field>
            <field>
              <name>USBSUSP</name>
              <bitOffset>11</bitOffset>
              <bitWidth>1</bitWidth>
            </field>
            <field>
              <name>USBRST</name>
              <bitOffset>12</bitOffset>
              <bitWidth>1</bitWidth>
            </field>
            <field>
              <name>ENUMDNE</name>
              <bitOffset>13</bitOffset>
              <bitWidth>1</bitWidth>
            </field>
            <field>
              <name>ISOODRP</name>
              <bitOffset>14</bitOffset>
              <bitWidth>1</bitWidth>
            </field>
            <field>
              <name>EOPF</name>
              <bitOffset>15</bitOffset>
              <bitWidth>1</bitWidth>
            </field>
            <field>
              <name>IEPINT</name>
              <bitOffset>18</bitOffset>
              <bitWidth>1</bitWidth>
            </field>
            <field>
              <name>OEPINT</name>
              <bitOffset>19</bitOffset>
              <bitWidth>1</bitWidth>
            </field>
            <field>
              <name>IISOIXFR</name>
              <bitOffset>20</bitOffset>
              <bitWidth>1</bitWidth>
            </field>
            <field>
              <name>PXFR_INCOMPISOOUT</name>
              <bitOffset>21</bitOffset>
              <bitWidth>1</bitWidth>
            </field>
            <field>
              <name>DATAFSUSP</name>
              <bitOffset>22</bitOffset>
              <bitWidth>1</bitWidth>
            </field>
            <field>
              <name>HPRTINT</name>
              <bitOffset>24</bitOffset>
              <bitWidth>1</bitWidth>
            </field>
            <field>
              <name>HCINT</name>
              <bitOffset>25</bitOffset>
              <bitWidth>1</bitWidth>
            </field>
            <field>
              <name>PTXFE</name>
              <bitOffset>26</bitOffset>
              <bitWidth>1</bitWidth>
            </field>
            <field>
              <name>CIDSCHG</name>
              <bitOffset>28</bitOffset>
              <bitWidth>1</bitWidth>
            </field>
            <field>
              <name>DISCINT</name>
              <bitOffset>29</bitOffset>
              <bitWidth>1</bitWidth>
            </field>
            <field>
              <name>SRQINT</name>
              <bitOffset>30</bitOffset>
              <bitWidth>1</bitWidth>
            </field>
            <field>
              <name>WKUINT</name>
              <bitOffset>31</bitOffset>
              <bitWidth>1</bitWidth>
            </field>
          </fields>
        </register>
        <register>
          <name>GINTMSK</name>
          <addressOffset>0x18</addressOffset>
          <size>0x20</size>
          <fields>
            <field>
              <name>MMISM</name>
              <bitOffset>1</bitOffset>
              <bitWidth>1</bitWidth>
            </field>
            <field>
              <name>OTGINT</name>
              <bitOffset>2</bitOffset>
              <bitWidth>1</bitWidth>
            </field>
            <field>
              <name>SOFM</name>
              <bitOffset>3</bitOffset>
              <bitWidth>1</bitWidth>
            </field>
            <field>
              <name>RXFLVLM</name>
              <bitOffset>4</bitOffset>
              <bitWidth>1</bitWidth>
            </field>
            <field>
              <name>NPTXFEM</name>
              <bitOffset>5</bitOffset>
              <bitWidth>1</bitWidth>
            </field>
            <field>
              <name>GINAKEFFM</name>
              <bitOffset>6</bitOffset>
              <bitWidth>1</bitWidth>
            </field>
            <field>
              <name>GONAKEFFM</name>
              <bitOffset>7</bitOffset>
              <bitWidth>1</bitWidth>
            </field>
            <field>
              <name>ESUSPM</name>
              <bitOffset>10</bitOffset>
              <bitWidth>1</bitWidth>
            </field>
            <field>
              <name>USBSUSPM</name>
              <bitOffset>11</bitOffset>
              <bitWidth>1</bitWidth>
            </field>
            <field>
              <name>USBRST</name>
              <bitOffset>12</bitOffset>
              <bitWidth>1</bitWidth>
            </field>
            <field>
              <name>ENUMDNEM</name>
              <bitOffset>13</bitOffset>
              <bitWidth>1</bitWidth>
            </field>
            <field>
              <name>ISOODRPM</name>
              <bitOffset>14</bitOffset>
              <bitWidth>1</bitWidth>
            </field>
            <field>
              <name>EOPFM</name>
              <bitOffset>15</bitOffset>
              <bitWidth>1</bitWidth>
            </field>
            <field>
              <name>EPMISM</name>
              <bitOffset>17</bitOffset>
              <bitWidth>1</bitWidth>
            </field>
            <field>
              <name>IEPINT</name>
              <bitOffset>18</bitOffset>
              <bitWidth>1</bitWidth>
            </field>
            <field>
              <name>OEPINT</name>
              <bitOffset>19</bitOffset>
              <bitWidth>1</bitWidth>
            </field>
            <field>
              <name>IISOIXFRM</name>
              <bitOffset>20</bitOffset>
              <bitWidth>1</bitWidth>
            </field>
            <field>
              <name>PXFRM_IISOOXFRM</name>
              <bitOffset>21</bitOffset>
              <bitWidth>1</bitWidth>
            </field>
            <field>
              <name>FSUSPM</name>
              <bitOffset>22</bitOffset>
              <bitWidth>1</bitWidth>
            </field>
            <field>
              <name>PRTIM</name>
              <bitOffset>24</bitOffset>
              <bitWidth>1</bitWidth>
            </field>
            <field>
              <name>HCIM</name>
              <bitOffset>25</bitOffset>
              <bitWidth>1</bitWidth>
            </field>
            <field>
              <name>PTXFEM</name>
              <bitOffset>26</bitOffset>
              <bitWidth>1</bitWidth>
            </field>
            <field>
              <name>CIDSCHGM</name>
              <bitOffset>28</bitOffset>
              <bitWidth>1</bitWidth>
            </field>
            <field>
              <name>DISCINT</name>
              <bitOffset>29</bitOffset>
              <bitWidth>1</bitWidth>
            </field>
            <field>
              <name>SRQIM</name>
              <bitOffset>30</bitOffset>
              <bitWidth>1</bitWidth>
            </field>
            <field>
              <name>WUIM</name>
              <bitOffset>31</bitOffset>
              <bitWidth>1</bitWidth>
            </field>
          </fields>
        </register>
        <register>
          <name>GRXSTSR</name>
          <addressOffset>0x1c</addressOffset>
          <size>0x20</size>
        </register>
        <register>
          <name>GRXSTSP</name>
          <addressOffset>0x20</addressOffset>
          <size>0x20</size>
          <fields>
            <field>
              <name>EPNUM</name>
              <bitOffset>0</bitOffset>
              <bitWidth>4</bitWidth>
            </field>
            <field>
              <name>BCNT</name>
              <bitOffset>4</bitOffset>
              <bitWidth>11</bitWidth>
            </field>
            <field>
              <name>DPID</name>
              <bitOffset>15</bitOffset>
              <bitWidth>2</bitWidth>
            </field>
            <field>
              <name>PKTSTS</name>
              <bitOffset>17</bitOffset>
              <bitWidth>4</bitWidth>
            </field>
          </fields>
        </register>
        <register>
          <name>GRXFSIZ</name>
          <addressOffset>0x24</addressOffset>
          <size>0x20</size>
          <fields>
            <field>
              <name>RXFD</name>
              <bitOffset>0</bitOffset>
              <bitWidth>16</bitWidth>
            </field>
          </fields>
        </register>
        <register>
          <name>DIEPTXF0_HNPTXFSIZ</name>
          <addressOffset>0x28</addressOffset>
          <size>0x20</size>
        </register>
        <register>
          <name>HNPTXSTS</name>
          <addressOffset>0x2c</addressOffset>
          <size>0x20</size>
        </register>
        <register>
          <name>GCCFG</name>
          <addressOffset>0x38</addressOffset>
          <size>0x20</size>
          <fields>
            <field>
              <name>PWRDWN</name>
              <bitOffset>16</bitOffset>
              <bitWidth>1</bitWidth>
            </field>
            <field>
              <name>I2CPADEN</name>
              <bitOffset>17</bitOffset>
              <bitWidth>1</bitWidth>
            </field>
            <field>
              <name>VBUSASEN</name>
              <bitOffset>18</bitOffset>
              <bitWidth>1</bitWidth>
            </field>
            <field>
              <name>VBUSBSEN</name>
              <bitOffset>19</bitOffset>
              <bitWidth>1</bitWidth>
            </field>
            <field>
              <name>SOFOUTEN</name>
              <bitOffset>20</bitOffset>
              <bitWidth>1</bitWidth>
            </field>
            <field>
              <name>NOVBUSSENS</name>
              <bitOffset>21</bitOffset>
              <bitWidth>1</bitWidth>
            </field>
          </fields>
        </register>
        <register>
          <name>CID</name>
          <addressOffset>0x3c</addressOffset>
          <size>0x20</size>
          <fields>
            <field>
              <name>PRODUCT_ID</name>
              <bitOffset>0</bitOffset>
              <bitWidth>32</bitWidth>
            </field>
          </fields>
        </register>
        <register>
          <name>HPTXFSIZ</name>
          <addressOffset>0x100</addressOffset>
          <size>0x20</size>
          <fields>
            <field>
              <name>PTXSA</name>
              <bitOffset>0</bitOffset>
              <bitWidth>16</bitWidth>
            </field>
            <field>
              <name>PTXFD</name>
              <bitOffset>16</bitOffset>
              <bitWidth>16</bitWidth>
            </field>
          </fields>
        </register>
        <register>
          <name>DIEPTXF.0</name>
          <addressOffset>0x104</addressOffset>
          <size>0x20</size>
          <fields>
            <field>
              <name>INEPTXSA</name>
              <bitOffset>0</bitOffset>
              <bitWidth>16</bitWidth>
            </field>
            <field>
              <name>INEPTXFD</name>
              <bitOffset>16</bitOffset>
              <bitWidth>16</bitWidth>
            </field>
          </fields>
        </register>
        <register>
          <name>DIEPTXF.1</name>
          <addressOffset>0x108</addressOffset>
          <size>0x20</size>
          <fields>
            <field>
              <name>INEPTXSA</name>
              <bitOffset>0</bitOffset>
              <bitWidth>16</bitWidth>
            </field>
            <field>
              <name>INEPTXFD</name>
              <bitOffset>16</bitOffset>
              <bitWidth>16</bitWidth>
            </field>
          </fields>
        </register>
        <register>
          <name>DIEPTXF.2</name>
          <addressOffset>0x10c</addressOffset>
          <size>0x20</size>
          <fields>
            <field>
              <name>INEPTXSA</name>
              <bitOffset>0</bitOffset>
              <bitWidth>16</bitWidth>
            </field>
            <field>
              <name>INEPTXFD</name>
              <bitOffset>16</bitOffset>
              <bitWidth>16</bitWidth>
            </field>
          </fields>
        </register>
        <register>
          <name>DIEPTXF.3</name>
          <addressOffset>0x110</addressOffset>
          <size>0x20</size>
          <fields>
            <field>
              <name>INEPTXSA</name>
              <bitOffset>0</bitOffset>
              <bitWidth>16</bitWidth>
            </field>
            <field>
              <name>INEPTXFD</name>
              <bitOffset>16</bitOffset>
              <bitWidth>16</bitWidth>
            </field>
          </fields>
        </register>
        <register>
          <name>DIEPTXF.4</name>
          <addressOffset>0x114</addressOffset>
          <size>0x20</size>
          <fields>
            <field>
              <name>INEPTXSA</name>
              <bitOffset>0</bitOffset>
              <bitWidth>16</bitWidth>
            </field>
            <field>
              <name>INEPTXFD</name>
              <bitOffset>16</bitOffset>
              <bitWidth>16</bitWidth>
            </field>
          </fields>
        </register>
        <register>
          <name>DIEPTXF.5</name>
          <addressOffset>0x118</addressOffset>
          <size>0x20</size>
          <fields>
            <field>
              <name>INEPTXSA</name>
              <bitOffset>0</bitOffset>
              <bitWidth>16</bitWidth>
            </field>
            <field>
              <name>INEPTXFD</name>
              <bitOffset>16</bitOffset>
              <bitWidth>16</bitWidth>
            </field>
          </fields>
        </register>
        <register>
          <name>DIEPTXF.6</name>
          <addressOffset>0x11c</addressOffset>
          <size>0x20</size>
          <fields>
            <field>
              <name>INEPTXSA</name>
              <bitOffset>0</bitOffset>
              <bitWidth>16</bitWidth>
            </field>
            <field>
              <name>INEPTXFD</name>
              <bitOffset>16</bitOffset>
              <bitWidth>16</bitWidth>
            </field>
          </fields>
        </register>
        <register>
          <name>DIEPTXF.7</name>
          <addressOffset>0x120</addressOffset>
          <size>0x20</size>
          <fields>
            <field>
              <name>INEPTXSA</name>
              <bitOffset>0</bitOffset>
              <bitWidth>16</bitWidth>
            </field>
            <field>
              <name>INEPTXFD</name>
              <bitOffset>16</bitOffset>
              <bitWidth>16</bitWidth>
            </field>
          </fields>
        </register>
        <register>
          <name>DIEPTXF.8</name>
          <addressOffset>0x124</addressOffset>
          <size>0x20</size>
          <fields>
            <field>
              <name>INEPTXSA</name>
              <bitOffset>0</bitOffset>
              <bitWidth>16</bitWidth>
            </field>
            <field>
              <name>INEPTXFD</name>
              <bitOffset>16</bitOffset>
              <bitWidth>16</bitWidth>
            </field>
          </fields>
        </register>
        <register>
          <name>DIEPTXF.9</name>
          <addressOffset>0x128</addressOffset>
          <size>0x20</size>
          <fields>
            <field>
              <name>INEPTXSA</name>
              <bitOffset>0</bitOffset>
              <bitWidth>16</bitWidth>
            </field>
            <field>
              <name>INEPTXFD</name>
              <bitOffset>16</bitOffset>
              <bitWidth>16</bitWidth>
            </field>
          </fields>
        </register>
        <register>
          <name>DIEPTXF.10</name>
          <addressOffset>0x12c</addressOffset>
          <size>0x20</size>
          <fields>
            <field>
              <name>INEPTXSA</name>
              <bitOffset>0</bitOffset>
              <bitWidth>16</bitWidth>
            </field>
            <field>
              <name>INEPTXFD</name>
              <bitOffset>16</bitOffset>
              <bitWidth>16</bitWidth>
            </field>
          </fields>
        </register>
        <register>
          <name>DIEPTXF.11</name>
          <addressOffset>0x130</addressOffset>
          <size>0x20</size>
          <fields>
            <field>
              <name>INEPTXSA</name>
              <bitOffset>0</bitOffset>
              <bitWidth>16</bitWidth>
            </field>
            <field>
              <name>INEPTXFD</name>
              <bitOffset>16</bitOffset>
              <bitWidth>16</bitWidth>
            </field>
          </fields>
        </register>
        <register>
          <name>DIEPTXF.12</name>
          <addressOffset>0x134</addressOffset>
          <size>0x20</size>
          <fields>
            <field>
              <name>INEPTXSA</name>
              <bitOffset>0</bitOffset>
              <bitWidth>16</bitWidth>
            </field>
            <field>
              <name>INEPTXFD</name>
              <bitOffset>16</bitOffset>
              <bitWidth>16</bitWidth>
            </field>
          </fields>
        </register>
        <register>
          <name>DIEPTXF.13</name>
          <addressOffset>0x138</addressOffset>
          <size>0x20</size>
          <fields>
            <field>
              <name>INEPTXSA</name>
              <bitOffset>0</bitOffset>
              <bitWidth>16</bitWidth>
            </field>
            <field>
              <name>INEPTXFD</name>
              <bitOffset>16</bitOffset>
              <bitWidth>16</bitWidth>
            </field>
          </fields>
        </register>
        <register>
          <name>DIEPTXF.14</name>
          <addressOffset>0x13c</addressOffset>
          <size>0x20</size>
          <fields>
            <field>
              <name>INEPTXSA</name>
              <bitOffset>0</bitOffset>
              <bitWidth>16</bitWidth>
            </field>
            <field>
              <name>INEPTXFD</name>
              <bitOffset>16</bitOffset>
              <bitWidth>16</bitWidth>
            </field>
          </fields>
        </register>
      </registers>
    </peripheral>
    <peripheral>
      <name>USB_OTG_FS</name>
      <baseAddress>0x50000000</baseAddress>
      <registers>
        <register>
          <name>GOTGCTL</name>
          <addressOffset>0x0</addressOffset>
          <size>0x20</size>
          <fields>
            <field>
              <name>SRQSCS</name>
              <bitOffset>0</bitOffset>
              <bitWidth>1</bitWidth>
            </field>
            <field>
              <name>SRQ</name>
              <bitOffset>1</bitOffset>
              <bitWidth>1</bitWidth>
            </field>
            <field>
              <name>HNGSCS</name>
              <bitOffset>8</bitOffset>
              <bitWidth>1</bitWidth>
            </field>
            <field>
              <name>HNPRQ</name>
              <bitOffset>9</bitOffset>
              <bitWidth>1</bitWidth>
            </field>
            <field>
              <name>HSHNPEN</name>
              <bitOffset>10</bitOffset>
              <bitWidth>1</bitWidth>
            </field>
            <field>
              <name>DHNPEN</name>
              <bitOffset>11</bitOffset>
              <bitWidth>1</bitWidth>
            </field>
            <field>
              <name>CIDSTS</name>
              <bitOffset>16</bitOffset>
              <bitWidth>1</bitWidth>
            </field>
            <field>
              <name>DBCT</name>
              <bitOffset>17</bitOffset>
              <bitWidth>1</bitWidth>
            </field>
            <field>
              <name>ASVLD</name>
              <bitOffset>18</bitOffset>
              <bitWidth>1</bitWidth>
            </field>
            <field>
              <name>BSVLD</name>
              <bitOffset>19</bitOffset>
              <bitWidth>1</bitWidth>
            </field>
          </fields>
        </register>
        <register>
          <name>GOTGINT</name>
          <addressOffset>0x4</addressOffset>
          <size>0x20</size>
          <fields>
            <field>
              <name>SEDET</name>
              <bitOffset>2</bitOffset>
              <bitWidth>1</bitWidth>
            </field>
            <field>
              <name>SRSSCHG</name>
              <bitOffset>8</bitOffset>
              <bitWidth>1</bitWidth>
            </field>
            <field>
              <name>HNSSCHG</name>
              <bitOffset>9</bitOffset>
              <bitWidth>1</bitWidth>
            </field>
            <field>
              <name>HNGDET</name>
              <bitOffset>17</bitOffset>
              <bitWidth>1</bitWidth>
            </field>
            <field>
              <name>ADTOCHG</name>
              <bitOffset>18</bitOffset>
              <bitWidth>1</bitWidth>
            </field>
            <field>
              <name>DBCDNE</name>
              <bitOffset>19</bitOffset>
              <bitWidth>1</bitWidth>
            </field>
          </fields>
        </register>
        <register>
          <name>GAHBCFG</name>
          <addressOffset>0x8</addressOffset>
          <size>0x20</size>
          <fields>
            <field>
              <name>GINT</name>
              <bitOffset>0</bitOffset>
              <bitWidth>1</bitWidth>
            </field>
            <field>
              <name>HBSTLEN</name>
              <bitOffset>1</bitOffset>
              <bitWidth>4</bitWidth>
            </field>
            <field>
              <name>DMAEN</name>
              <bitOffset>5</bitOffset>
              <bitWidth>1</bitWidth>
            </field>
            <field>
              <name>TXFELVL</name>
              <bitOffset>7</bitOffset>
              <bitWidth>1</bitWidth>
            </field>
            <field>
              <name>PTXFELVL</name>
              <bitOffset>8</bitOffset>
              <bitWidth>1</bitWidth>
            </field>
          </fields>
        </register>
        <register>
          <name>GUSBCFG</name>
          <addressOffset>0xc</addressOffset>
          <size>0x20</size>
          <fields>
            <field>
              <name>TOCAL</name>
              <bitOffset>0</bitOffset>
              <bitWidth>3</bitWidth>
            </field>
            <field>
              <name>PHYSEL</name>
              <bitOffset>6</bitOffset>
              <bitWidth>1</bitWidth>
            </field>
            <field>
              <name>SRPCAP</name>
              <bitOffset>8</bitOffset>
              <bitWidth>1</bitWidth>
            </field>
            <field>
              <name>HNPCAP</name>
              <bitOffset>9</bitOffset>
              <bitWidth>1</bitWidth>
            </field>
            <field>
              <name>TRDT</name>
              <bitOffset>10</bitOffset>
              <bitWidth>4</bitWidth>
            </field>
            <field>
              <name>PHYLPCS</name>
              <bitOffset>15</bitOffset>
              <bitWidth>1</bitWidth>
            </field>
            <field>
              <name>ULPIFSLS</name>
              <bitOffset>17</bitOffset>
              <bitWidth>1</bitWidth>
            </field>
            <field>
              <name>ULPIAR</name>
              <bitOffset>18</bitOffset>
              <bitWidth>1</bitWidth>
            </field>
            <field>
              <name>ULPICSM</name>
              <bitOffset>19</bitOffset>
              <bitWidth>1</bitWidth>
            </field>
            <field>
              <name>ULPIEVBUSD</name>
              <bitOffset>20</bitOffset>
              <bitWidth>1</bitWidth>
            </field>
            <field>
              <name>ULPIEVBUSI</name>
              <bitOffset>21</bitOffset>
              <bitWidth>1</bitWidth>
            </field>
            <field>
              <name>TSDPS</name>
              <bitOffset>22</bitOffset>
              <bitWidth>1</bitWidth>
            </field>
            <field>
              <name>PCCI</name>
              <bitOffset>23</bitOffset>
              <bitWidth>1</bitWidth>
            </field>
            <field>
              <name>PTCI</name>
              <bitOffset>24</bitOffset>
              <bitWidth>1</bitWidth>
            </field>
            <field>
              <name>ULPIIPD</name>
              <bitOffset>25</bitOffset>
              <bitWidth>1</bitWidth>
            </field>
            <field>
              <name>FHMOD</name>
              <bitOffset>29</bitOffset>
              <bitWidth>1</bitWidth>
            </field>
            <field>
              <name>FDMOD</name>
              <bitOffset>30</bitOffset>
              <bitWidth>1</bitWidth>
            </field>
            <field>
              <name>CTXPKT</name>
              <bitOffset>31</bitOffset>
              <bitWidth>1</bitWidth>
            </field>
          </fields>
        </register>
        <register>
          <name>GRSTCTL</name>
          <addressOffset>0x10</addressOffset>
          <size>0x20</size>
          <fields>
            <field>
              <name>CSRST</name>
              <bitOffset>0</bitOffset>
              <bitWidth>1</bitWidth>
            </field>
            <field>
              <name>HSRST</name>
              <bitOffset>1</bitOffset>
              <bitWidth>1</bitWidth>
            </field>
            <field>
              <name>FCRST</name>
              <bitOffset>2</bitOffset>
              <bitWidth>1</bitWidth>
            </field>
            <field>
              <name>RXFFLSH</name>
              <bitOffset>4</bitOffset>
              <bitWidth>1</bitWidth>
            </field>
            <field>
              <name>TXFFLSH</name>
              <bitOffset>5</bitOffset>
              <bitWidth>1</bitWidth>
            </field>
            <field>
              <name>TXFNUM</name>
              <bitOffset>6</bitOffset>
              <bitWidth>5</bitWidth>
            </field>
            <field>
              <name>DMAREQ</name>
              <bitOffset>30</bitOffset>
              <bitWidth>1</bitWidth>
            </field>
            <field>
              <name>AHBIDL</name>
              <bitOffset>31</bitOffset>
              <bitWidth>1</bitWidth>
            </field>
          </fields>
        </register>
        <register>
          <name>GINTSTS</name>
          <addressOffset>0x14</addressOffset>
          <size>0x20</size>
          <fields>
            <field>
              <name>CMOD</name>
              <bitOffset>0</bitOffset>
              <bitWidth>1</bitWidth>
            </field>
            <field>
              <name>MMIS</name>
              <bitOffset>1</bitOffset>
              <bitWidth>1</bitWidth>
            </field>
            <field>
              <name>OTGINT</name>
              <bitOffset>2</bitOffset>
              <bitWidth>1</bitWidth>
            </field>
            <field>
              <name>SOF</name>
              <bitOffset>3</bitOffset>
              <bitWidth>1</bitWidth>
            </field>
            <field>
              <name>RXFLVL</name>
              <bitOffset>4</bitOffset>
              <bitWidth>1</bitWidth>
            </field>
            <field>
              <name>NPTXFE</name>
              <bitOffset>5</bitOffset>
              <bitWidth>1</bitWidth>
            </field>
            <field>
              <name>GINAKEFF</name>
              <bitOffset>6</bitOffset>
              <bitWidth>1</bitWidth>
            </field>
            <field>
              <name>BOUTNAKEFF</name>
              <bitOffset>7</bitOffset>
              <bitWidth>1</bitWidth>
            </field>
            <field>
              <name>ESUSP</name>
              <bitOffset>10</bitOffset>
              <bitWidth>1</bitWidth>
            </field>
            <field>
              <name>USBSUSP</name>
              <bitOffset>11</bitOffset>
              <bitWidth>1</bitWidth>
            </field>
            <field>
              <name>USBRST</name>
              <bitOffset>12</bitOffset>
              <bitWidth>1</bitWidth>
            </field>
            <field>
              <name>ENUMDNE</name>
              <bitOffset>13</bitOffset>
              <bitWidth>1</bitWidth>
            </field>
            <field>
              <name>ISOODRP</name>
              <bitOffset>14</bitOffset>
              <bitWidth>1</bitWidth>
            </field>
            <field>
              <name>EOPF</name>
              <bitOffset>15</bitOffset>
              <bitWidth>1</bitWidth>
            </field>
            <field>
              <name>IEPINT</name>
              <bitOffset>18</bitOffset>
              <bitWidth>1</bitWidth>
            </field>
            <field>
              <name>OEPINT</name>
              <bitOffset>19</bitOffset>
              <bitWidth>1</bitWidth>
            </field>
            <field>
              <name>IISOIXFR</name>
              <bitOffset>20</bitOffset>
              <bitWidth>1</bitWidth>
            </field>
            <field>
              <name>PXFR_INCOMPISOOUT</name>
              <bitOffset>21</bitOffset>
              <bitWidth>1</bitWidth>
            </field>
            <field>
              <name>DATAFSUSP</name>
              <bitOffset>22</bitOffset>
              <bitWidth>1</bitWidth>
            </field>
            <field>
              <name>HPRTINT</name>
              <bitOffset>24</bitOffset>
              <bitWidth>1</bitWidth>
            </field>
            <field>
              <name>HCINT</name>
              <bitOffset>25</bitOffset>
              <bitWidth>1</bitWidth>
            </field>
            <field>
              <name>PTXFE</name>
              <bitOffset>26</bitOffset>
              <bitWidth>1</bitWidth>
            </field>
            <field>
              <name>CIDSCHG</name>
              <bitOffset>28</bitOffset>
              <bitWidth>1</bitWidth>
            </field>
            <field>
              <name>DISCINT</name>
              <bitOffset>29</bitOffset>
              <bitWidth>1</bitWidth>
            </field>
            <field>
              <name>SRQINT</name>
              <bitOffset>30</bitOffset>
              <bitWidth>1</bitWidth>
            </field>
            <field>
              <name>WKUINT</name>
              <bitOffset>31</bitOffset>
              <bitWidth>1</bitWidth>
            </field>
          </fields>
        </register>
        <register>
          <name>GINTMSK</name>
          <addressOffset>0x18</addressOffset>
          <size>0x20</size>
          <fields>
            <field>
              <name>MMISM</name>
              <bitOffset>1</bitOffset>
              <bitWidth>1</bitWidth>
            </field>
            <field>
              <name>OTGINT</name>
              <bitOffset>2</bitOffset>
              <bitWidth>1</bitWidth>
            </field>
            <field>
              <name>SOFM</name>
              <bitOffset>3</bitOffset>
              <bitWidth>1</bitWidth>
            </field>
            <field>
              <name>RXFLVLM</name>
              <bitOffset>4</bitOffset>
              <bitWidth>1</bitWidth>
            </field>
            <field>
              <name>NPTXFEM</name>
              <bitOffset>5</bitOffset>
              <bitWidth>1</bitWidth>
            </field>
            <field>
              <name>GINAKEFFM</name>
              <bitOffset>6</bitOffset>
              <bitWidth>1</bitWidth>
            </field>
            <field>
              <name>GONAKEFFM</name>
              <bitOffset>7</bitOffset>
              <bitWidth>1</bitWidth>
            </field>
            <field>
              <name>ESUSPM</name>
              <bitOffset>10</bitOffset>
              <bitWidth>1</bitWidth>
            </field>
            <field>
              <name>USBSUSPM</name>
              <bitOffset>11</bitOffset>
              <bitWidth>1</bitWidth>
            </field>
            <field>
              <name>USBRST</name>
              <bitOffset>12</bitOffset>
              <bitWidth>1</bitWidth>
            </field>
            <field>
              <name>ENUMDNEM</name>
              <bitOffset>13</bitOffset>
              <bitWidth>1</bitWidth>
            </field>
            <field>
              <name>ISOODRPM</name>
              <bitOffset>14</bitOffset>
              <bitWidth>1</bitWidth>
            </field>
            <field>
              <name>EOPFM</name>
              <bitOffset>15</bitOffset>
              <bitWidth>1</bitWidth>
            </field>
            <field>
              <name>EPMISM</name>
              <bitOffset>17</bitOffset>
              <bitWidth>1</bitWidth>
            </field>
            <field>
              <name>IEPINT</name>
              <bitOffset>18</bitOffset>
              <bitWidth>1</bitWidth>
            </field>
            <field>
              <name>OEPINT</name>
              <bitOffset>19</bitOffset>
              <bitWidth>1</bitWidth>
            </field>
            <field>
              <name>IISOIXFRM</name>
              <bitOffset>20</bitOffset>
              <bitWidth>1</bitWidth>
            </field>
            <field>
              <name>PXFRM_IISOOXFRM</name>
              <bitOffset>21</bitOffset>
              <bitWidth>1</bitWidth>
            </field>
            <field>
              <name>FSUSPM</name>
              <bitOffset>22</bitOffset>
              <bitWidth>1</bitWidth>
            </field>
            <field>
              <name>PRTIM</name>
              <bitOffset>24</bitOffset>
              <bitWidth>1</bitWidth>
            </field>
            <field>
              <name>HCIM</name>
              <bitOffset>25</bitOffset>
              <bitWidth>1</bitWidth>
            </field>
            <field>
              <name>PTXFEM</name>
              <bitOffset>26</bitOffset>
              <bitWidth>1</bitWidth>
            </field>
            <field>
              <name>CIDSCHGM</name>
              <bitOffset>28</bitOffset>
              <bitWidth>1</bitWidth>
            </field>
            <field>
              <name>DISCINT</name>
              <bitOffset>29</bitOffset>
              <bitWidth>1</bitWidth>
            </field>
            <field>
              <name>SRQIM</name>
              <bitOffset>30</bitOffset>
              <bitWidth>1</bitWidth>
            </field>
            <field>
              <name>WUIM</name>
              <bitOffset>31</bitOffset>
              <bitWidth>1</bitWidth>
            </field>
          </fields>
        </register>
        <register>
          <name>GRXSTSR</name>
          <addressOffset>0x1c</addressOffset>
          <size>0x20</size>
        </register>
        <register>
          <name>GRXSTSP</name>
          <addressOffset>0x20</addressOffset>
          <size>0x20</size>
          <fields>
            <field>
              <name>EPNUM</name>
              <bitOffset>0</bitOffset>
              <bitWidth>4</bitWidth>
            </field>
            <field>
              <name>BCNT</name>
              <bitOffset>4</bitOffset>
              <bitWidth>11</bitWidth>
            </field>
            <field>
              <name>DPID</name>
              <bitOffset>15</bitOffset>
              <bitWidth>2</bitWidth>
            </field>
            <field>
              <name>PKTSTS</name>
              <bitOffset>17</bitOffset>
              <bitWidth>4</bitWidth>
            </field>
          </fields>
        </register>
        <register>
          <name>GRXFSIZ</name>
          <addressOffset>0x24</addressOffset>
          <size>0x20</size>
          <fields>
            <field>
              <name>RXFD</name>
              <bitOffset>0</bitOffset>
              <bitWidth>16</bitWidth>
            </field>
          </fields>
        </register>
        <register>
          <name>DIEPTXF0_HNPTXFSIZ</name>
          <addressOffset>0x28</addressOffset>
          <size>0x20</size>
        </register>
        <register>
          <name>HNPTXSTS</name>
          <addressOffset>0x2c</addressOffset>
          <size>0x20</size>
        </register>
        <register>
          <name>GCCFG</name>
          <addressOffset>0x38</addressOffset>
          <size>0x20</size>
          <fields>
            <field>
              <name>PWRDWN</name>
              <bitOffset>16</bitOffset>
              <bitWidth>1</bitWidth>
            </field>
            <field>
              <name>I2CPADEN</name>
              <bitOffset>17</bitOffset>
              <bitWidth>1</bitWidth>
            </field>
            <field>
              <name>VBUSASEN</name>
              <bitOffset>18</bitOffset>
              <bitWidth>1</bitWidth>
            </field>
            <field>
              <name>VBUSBSEN</name>
              <bitOffset>19</bitOffset>
              <bitWidth>1</bitWidth>
            </field>
            <field>
              <name>SOFOUTEN</name>
              <bitOffset>20</bitOffset>
              <bitWidth>1</bitWidth>
            </field>
            <field>
              <name>NOVBUSSENS</name>
              <bitOffset>21</bitOffset>
              <bitWidth>1</bitWidth>
            </field>
          </fields>
        </register>
        <register>
          <name>CID</name>
          <addressOffset>0x3c</addressOffset>
          <size>0x20</size>
          <fields>
            <field>
              <name>PRODUCT_ID</name>
              <bitOffset>0</bitOffset>
              <bitWidth>32</bitWidth>
            </field>
          </fields>
        </register>
        <register>
          <name>HPTXFSIZ</name>
          <addressOffset>0x100</addressOffset>
          <size>0x20</size>
          <fields>
            <field>
              <name>PTXSA</name>
              <bitOffset>0</bitOffset>
              <bitWidth>16</bitWidth>
            </field>
            <field>
              <name>PTXFD</name>
              <bitOffset>16</bitOffset>
              <bitWidth>16</bitWidth>
            </field>
          </fields>
        </register>
        <register>
          <name>DIEPTXF.0</name>
          <addressOffset>0x104</addressOffset>
          <size>0x20</size>
          <fields>
            <field>
              <name>INEPTXSA</name>
              <bitOffset>0</bitOffset>
              <bitWidth>16</bitWidth>
            </field>
            <field>
              <name>INEPTXFD</name>
              <bitOffset>16</bitOffset>
              <bitWidth>16</bitWidth>
            </field>
          </fields>
        </register>
        <register>
          <name>DIEPTXF.1</name>
          <addressOffset>0x108</addressOffset>
          <size>0x20</size>
          <fields>
            <field>
              <name>INEPTXSA</name>
              <bitOffset>0</bitOffset>
              <bitWidth>16</bitWidth>
            </field>
            <field>
              <name>INEPTXFD</name>
              <bitOffset>16</bitOffset>
              <bitWidth>16</bitWidth>
            </field>
          </fields>
        </register>
        <register>
          <name>DIEPTXF.2</name>
          <addressOffset>0x10c</addressOffset>
          <size>0x20</size>
          <fields>
            <field>
              <name>INEPTXSA</name>
              <bitOffset>0</bitOffset>
              <bitWidth>16</bitWidth>
            </field>
            <field>
              <name>INEPTXFD</name>
              <bitOffset>16</bitOffset>
              <bitWidth>16</bitWidth>
            </field>
          </fields>
        </register>
        <register>
          <name>DIEPTXF.3</name>
          <addressOffset>0x110</addressOffset>
          <size>0x20</size>
          <fields>
            <field>
              <name>INEPTXSA</name>
              <bitOffset>0</bitOffset>
              <bitWidth>16</bitWidth>
            </field>
            <field>
              <name>INEPTXFD</name>
              <bitOffset>16</bitOffset>
              <bitWidth>16</bitWidth>
            </field>
          </fields>
        </register>
        <register>
          <name>DIEPTXF.4</name>
          <addressOffset>0x114</addressOffset>
          <size>0x20</size>
          <fields>
            <field>
              <name>INEPTXSA</name>
              <bitOffset>0</bitOffset>
              <bitWidth>16</bitWidth>
            </field>
            <field>
              <name>INEPTXFD</name>
              <bitOffset>16</bitOffset>
              <bitWidth>16</bitWidth>
            </field>
          </fields>
        </register>
        <register>
          <name>DIEPTXF.5</name>
          <addressOffset>0x118</addressOffset>
          <size>0x20</size>
          <fields>
            <field>
              <name>INEPTXSA</name>
              <bitOffset>0</bitOffset>
              <bitWidth>16</bitWidth>
            </field>
            <field>
              <name>INEPTXFD</name>
              <bitOffset>16</bitOffset>
              <bitWidth>16</bitWidth>
            </field>
          </fields>
        </register>
        <register>
          <name>DIEPTXF.6</name>
          <addressOffset>0x11c</addressOffset>
          <size>0x20</size>
          <fields>
            <field>
              <name>INEPTXSA</name>
              <bitOffset>0</bitOffset>
              <bitWidth>16</bitWidth>
            </field>
            <field>
              <name>INEPTXFD</name>
              <bitOffset>16</bitOffset>
              <bitWidth>16</bitWidth>
            </field>
          </fields>
        </register>
        <register>
          <name>DIEPTXF.7</name>
          <addressOffset>0x120</addressOffset>
          <size>0x20</size>
          <fields>
            <field>
              <name>INEPTXSA</name>
              <bitOffset>0</bitOffset>
              <bitWidth>16</bitWidth>
            </field>
            <field>
              <name>INEPTXFD</name>
              <bitOffset>16</bitOffset>
              <bitWidth>16</bitWidth>
            </field>
          </fields>
        </register>
        <register>
          <name>DIEPTXF.8</name>
          <addressOffset>0x124</addressOffset>
          <size>0x20</size>
          <fields>
            <field>
              <name>INEPTXSA</name>
              <bitOffset>0</bitOffset>
              <bitWidth>16</bitWidth>
            </field>
            <field>
              <name>INEPTXFD</name>
              <bitOffset>16</bitOffset>
              <bitWidth>16</bitWidth>
            </field>
          </fields>
        </register>
        <register>
          <name>DIEPTXF.9</name>
          <addressOffset>0x128</addressOffset>
          <size>0x20</size>
          <fields>
            <field>
              <name>INEPTXSA</name>
              <bitOffset>0</bitOffset>
              <bitWidth>16</bitWidth>
            </field>
            <field>
              <name>INEPTXFD</name>
              <bitOffset>16</bitOffset>
              <bitWidth>16</bitWidth>
            </field>
          </fields>
        </register>
        <register>
          <name>DIEPTXF.10</name>
          <addressOffset>0x12c</addressOffset>
          <size>0x20</size>
          <fields>
            <field>
              <name>INEPTXSA</name>
              <bitOffset>0</bitOffset>
              <bitWidth>16</bitWidth>
            </field>
            <field>
              <name>INEPTXFD</name>
              <bitOffset>16</bitOffset>
              <bitWidth>16</bitWidth>
            </field>
          </fields>
        </register>
        <register>
          <name>DIEPTXF.11</name>
          <addressOffset>0x130</addressOffset>
          <size>0x20</size>
          <fields>
            <field>
              <name>INEPTXSA</name>
              <bitOffset>0</bitOffset>
              <bitWidth>16</bitWidth>
            </field>
            <field>
              <name>INEPTXFD</name>
              <bitOffset>16</bitOffset>
              <bitWidth>16</bitWidth>
            </field>
          </fields>
        </register>
        <register>
          <name>DIEPTXF.12</name>
          <addressOffset>0x134</addressOffset>
          <size>0x20</size>
          <fields>
            <field>
              <name>INEPTXSA</name>
              <bitOffset>0</bitOffset>
              <bitWidth>16</bitWidth>
            </field>
            <field>
              <name>INEPTXFD</name>
              <bitOffset>16</bitOffset>
              <bitWidth>16</bitWidth>
            </field>
          </fields>
        </register>
        <register>
          <name>DIEPTXF.13</name>
          <addressOffset>0x138</addressOffset>
          <size>0x20</size>
          <fields>
            <field>
              <name>INEPTXSA</name>
              <bitOffset>0</bitOffset>
              <bitWidth>16</bitWidth>
            </field>
            <field>
              <name>INEPTXFD</name>
              <bitOffset>16</bitOffset>
              <bitWidth>16</bitWidth>
            </field>
          </fields>
        </register>
        <register>
          <name>DIEPTXF.14</name>
          <addressOffset>0x13c</addressOffset>
          <size>0x20</size>
          <fields>
            <field>
              <name>INEPTXSA</name>
              <bitOffset>0</bitOffset>
              <bitWidth>16</bitWidth>
            </field>
            <field>
              <name>INEPTXFD</name>
              <bitOffset>16</bitOffset>
              <bitWidth>16</bitWidth>
            </field>
          </fields>
        </register>
      </registers>
    </peripheral>
    <peripheral>
      <name>DCMI</name>
      <baseAddress>0x50050000</baseAddress>
      <registers>
        <register>
          <name>CR</name>
          <addressOffset>0x0</addressOffset>
          <size>0x20</size>
          <fields>
            <field>
              <name>CAPTURE</name>
              <bitOffset>0</bitOffset>
              <bitWidth>1</bitWidth>
            </field>
            <field>
              <name>CM</name>
              <bitOffset>1</bitOffset>
              <bitWidth>1</bitWidth>
            </field>
            <field>
              <name>CROP</name>
              <bitOffset>2</bitOffset>
              <bitWidth>1</bitWidth>
            </field>
            <field>
              <name>JPEG</name>
              <bitOffset>3</bitOffset>
              <bitWidth>1</bitWidth>
            </field>
            <field>
              <name>ESS</name>
              <bitOffset>4</bitOffset>
              <bitWidth>1</bitWidth>
            </field>
            <field>
              <name>PCKPOL</name>
              <bitOffset>5</bitOffset>
              <bitWidth>1</bitWidth>
            </field>
            <field>
              <name>HSPOL</name>
              <bitOffset>6</bitOffset>
              <bitWidth>1</bitWidth>
            </field>
            <field>
              <name>VSPOL</name>
              <bitOffset>7</bitOffset>
              <bitWidth>1</bitWidth>
            </field>
            <field>
              <name>CRE</name>
              <bitOffset>12</bitOffset>
              <bitWidth>1</bitWidth>
            </field>
            <field>
              <name>ENABLE</name>
              <bitOffset>14</bitOffset>
              <bitWidth>1</bitWidth>
            </field>
          </fields>
        </register>
        <register>
          <name>SR</name>
          <addressOffset>0x4</addressOffset>
          <size>0x20</size>
          <fields>
            <field>
              <name>HSYNC</name>
              <bitOffset>0</bitOffset>
              <bitWidth>1</bitWidth>
            </field>
            <field>
              <name>VSYNC</name>
              <bitOffset>1</bitOffset>
              <bitWidth>1</bitWidth>
            </field>
            <field>
              <name>FNE</name>
              <bitOffset>2</bitOffset>
              <bitWidth>1</bitWidth>
            </field>
          </fields>
        </register>
        <register>
          <name>RISR</name>
          <addressOffset>0x8</addressOffset>
          <size>0x20</size>
        </register>
        <register>
          <name>IER</name>
          <addressOffset>0xc</addressOffset>
          <size>0x20</size>
          <fields>
            <field>
              <name>FRAME_IE</name>
              <bitOffset>0</bitOffset>
              <bitWidth>1</bitWidth>
            </field>
            <field>
              <name>OVR_IE</name>
              <bitOffset>1</bitOffset>
              <bitWidth>1</bitWidth>
            </field>
            <field>
              <name>ERR_IE</name>
              <bitOffset>2</bitOffset>
              <bitWidth>1</bitWidth>
            </field>
            <field>
              <name>VSYNC_IE</name>
              <bitOffset>3</bitOffset>
              <bitWidth>1</bitWidth>
            </field>
            <field>
              <name>LINE_IE</name>
              <bitOffset>4</bitOffset>
              <bitWidth>1</bitWidth>
            </field>
          </fields>
        </register>
        <register>
          <name>MISR</name>
          <addressOffset>0x10</addressOffset>
          <size>0x20</size>
        </register>
        <register>
          <name>ICR</name>
          <addressOffset>0x14</addressOffset>
          <size>0x20</size>
          <fields>
            <field>
              <name>FRAME_ISC</name>
              <bitOffset>0</bitOffset>
              <bitWidth>1</bitWidth>
            </field>
            <field>
              <name>OVR_ISC</name>
              <bitOffset>1</bitOffset>
              <bitWidth>1</bitWidth>
            </field>
            <field>
              <name>ERR_ISC</name>
              <bitOffset>2</bitOffset>
              <bitWidth>1</bitWidth>
            </field>
            <field>
              <name>VSYNC_ISC</name>
              <bitOffset>3</bitOffset>
              <bitWidth>1</bitWidth>
            </field>
            <field>
              <name>LINE_ISC</name>
              <bitOffset>4</bitOffset>
              <bitWidth>1</bitWidth>
            </field>
          </fields>
        </register>
        <register>
          <name>ESCR</name>
          <addressOffset>0x18</addressOffset>
          <size>0x20</size>
          <fields>
            <field>
              <name>FSC</name>
              <bitOffset>0</bitOffset>
              <bitWidth>8</bitWidth>
            </field>
            <field>
              <name>LSC</name>
              <bitOffset>8</bitOffset>
              <bitWidth>8</bitWidth>
            </field>
            <field>
              <name>LEC</name>
              <bitOffset>16</bitOffset>
              <bitWidth>8</bitWidth>
            </field>
            <field>
              <name>FEC</name>
              <bitOffset>24</bitOffset>
              <bitWidth>8</bitWidth>
            </field>
          </fields>
        </register>
        <register>
          <name>ESUR</name>
          <addressOffset>0x1c</addressOffset>
          <size>0x20</size>
          <fields>
            <field>
              <name>FSU</name>
              <bitOffset>0</bitOffset>
              <bitWidth>8</bitWidth>
            </field>
            <field>
              <name>LSU</name>
              <bitOffset>8</bitOffset>
              <bitWidth>8</bitWidth>
            </field>
            <field>
              <name>LEU</name>
              <bitOffset>16</bitOffset>
              <bitWidth>8</bitWidth>
            </field>
            <field>
              <name>FEU</name>
              <bitOffset>24</bitOffset>
              <bitWidth>8</bitWidth>
            </field>
          </fields>
        </register>
        <register>
          <name>CWSTRTR</name>
          <addressOffset>0x20</addressOffset>
          <size>0x20</size>
        </register>
        <register>
          <name>CWSIZER</name>
          <addressOffset>0x24</addressOffset>
          <size>0x20</size>
        </register>
        <register>
          <name>DR</name>
          <addressOffset>0x28</addressOffset>
          <size>0x20</size>
          <fields>
            <field>
              <name>BYTE0</name>
              <bitOffset>0</bitOffset>
              <bitWidth>8</bitWidth>
            </field>
            <field>
              <name>BYTE1</name>
              <bitOffset>8</bitOffset>
              <bitWidth>8</bitWidth>
            </field>
            <field>
              <name>BYTE2</name>
              <bitOffset>16</bitOffset>
              <bitWidth>8</bitWidth>
            </field>
            <field>
              <name>BYTE3</name>
              <bitOffset>24</bitOffset>
              <bitWidth>8</bitWidth>
            </field>
          </fields>
        </register>
      </registers>
    </peripheral>
    <peripheral>
      <name>RNG</name>
      <baseAddress>0x50060800</baseAddress>
      <registers>
        <register>
          <name>CR</name>
          <addressOffset>0x0</addressOffset>
          <size>0x20</size>
          <fields>
            <field>
              <name>RNGEN</name>
              <bitOffset>2</bitOffset>
              <bitWidth>1</bitWidth>
            </field>
            <field>
              <name>IE</name>
              <bitOffset>3</bitOffset>
              <bitWidth>1</bitWidth>
            </field>
          </fields>
        </register>
        <register>
          <name>SR</name>
          <addressOffset>0x4</addressOffset>
          <size>0x20</size>
          <fields>
            <field>
              <name>DRDY</name>
              <bitOffset>0</bitOffset>
              <bitWidth>1</bitWidth>
            </field>
            <field>
              <name>CECS</name>
              <bitOffset>1</bitOffset>
              <bitWidth>1</bitWidth>
            </field>
            <field>
              <name>SECS</name>
              <bitOffset>2</bitOffset>
              <bitWidth>1</bitWidth>
            </field>
            <field>
              <name>CEIS</name>
              <bitOffset>5</bitOffset>
              <bitWidth>1</bitWidth>
            </field>
            <field>
              <name>SEIS</name>
              <bitOffset>6</bitOffset>
              <bitWidth>1</bitWidth>
            </field>
          </fields>
        </register>
        <register>
          <name>DR</name>
          <addressOffset>0x8</addressOffset>
          <size>0x20</size>
        </register>
      </registers>
    </peripheral>
    <peripheral>
      <name>FMC_Bank1</name>
      <baseAddress>0xa0000000</baseAddress>
      <registers>
        <register>
          <name>BTCR.0</name>
          <addressOffset>0x0</addressOffset>
          <size>0x20</size>
        </register>
        <register>
          <name>BTCR.1</name>
          <addressOffset>0x4</addressOffset>
          <size>0x20</size>
        </register>
        <register>
          <name>BTCR.2</name>
          <addressOffset>0x8</addressOffset>
          <size>0x20</size>
        </register>
        <register>
          <name>BTCR.3</name>
          <addressOffset>0xc</addressOffset>
          <size>0x20</size>
        </register>
        <register>
          <name>BTCR.4</name>
          <addressOffset>0x10</addressOffset>
          <size>0x20</size>
        </register>
        <register>
          <name>BTCR.5</name>
          <addressOffset>0x14</addressOffset>
          <size>0x20</size>
        </register>
        <register>
          <name>BTCR.6</name>
          <addressOffset>0x18</addressOffset>
          <size>0x20</size>
        </register>
        <register>
          <name>BTCR.7</name>
          <addressOffset>0x1c</addressOffset>
          <size>0x20</size>
        </register>
      </registers>
    </peripheral>
    <peripheral>
      <name>FMC_Bank2_3</name>
      <baseAddress>0xa0000060</baseAddress>
      <registers>
        <register>
          <name>PCR2</name>
          <addressOffset>0x0</addressOffset>
          <size>0x20</size>
          <fields>
            <field>
              <name>PWAITEN</name>
              <bitOffset>1</bitOffset>
              <bitWidth>1</bitWidth>
            </field>
            <field>
              <name>PBKEN</name>
              <bitOffset>2</bitOffset>
              <bitWidth>1</bitWidth>
            </field>
            <field>
              <name>PTYP</name>
              <bitOffset>3</bitOffset>
              <bitWidth>1</bitWidth>
            </field>
            <field>
              <name>PWID</name>
              <bitOffset>4</bitOffset>
              <bitWidth>2</bitWidth>
            </field>
            <field>
              <name>ECCEN</name>
              <bitOffset>6</bitOffset>
              <bitWidth>1</bitWidth>
            </field>
            <field>
              <name>TCLR</name>
              <bitOffset>9</bitOffset>
              <bitWidth>4</bitWidth>
            </field>
            <field>
              <name>TAR</name>
              <bitOffset>13</bitOffset>
              <bitWidth>4</bitWidth>
            </field>
            <field>
              <name>ECCPS</name>
              <bitOffset>17</bitOffset>
              <bitWidth>3</bitWidth>
            </field>
          </fields>
        </register>
        <register>
          <name>SR2</name>
          <addressOffset>0x4</addressOffset>
          <size>0x20</size>
          <fields>
            <field>
              <name>IRS</name>
              <bitOffset>0</bitOffset>
              <bitWidth>1</bitWidth>
            </field>
            <field>
              <name>ILS</name>
              <bitOffset>1</bitOffset>
              <bitWidth>1</bitWidth>
            </field>
            <field>
              <name>IFS</name>
              <bitOffset>2</bitOffset>
              <bitWidth>1</bitWidth>
            </field>
            <field>
              <name>IREN</name>
              <bitOffset>3</bitOffset>
              <bitWidth>1</bitWidth>
            </field>
            <field>
              <name>ILEN</name>
              <bitOffset>4</bitOffset>
              <bitWidth>1</bitWidth>
            </field>
            <field>
              <name>IFEN</name>
              <bitOffset>5</bitOffset>
              <bitWidth>1</bitWidth>
            </field>
            <field>
              <name>FEMPT</name>
              <bitOffset>6</bitOffset>
              <bitWidth>1</bitWidth>
            </field>
          </fields>
        </register>
        <register>
          <name>PMEM2</name>
          <addressOffset>0x8</addressOffset>
          <size>0x20</size>
          <fields>
            <field>
              <name>MEMSET2</name>
              <bitOffset>0</bitOffset>
              <bitWidth>8</bitWidth>
            </field>
            <field>
              <name>MEMWAIT2</name>
              <bitOffset>8</bitOffset>
              <bitWidth>8</bitWidth>
            </field>
            <field>
              <name>MEMHOLD2</name>
              <bitOffset>16</bitOffset>
              <bitWidth>8</bitWidth>
            </field>
            <field>
              <name>MEMHIZ2</name>
              <bitOffset>24</bitOffset>
              <bitWidth>8</bitWidth>
            </field>
          </fields>
        </register>
        <register>
          <name>PATT2</name>
          <addressOffset>0xc</addressOffset>
          <size>0x20</size>
          <fields>
            <field>
              <name>ATTSET2</name>
              <bitOffset>0</bitOffset>
              <bitWidth>8</bitWidth>
            </field>
            <field>
              <name>ATTWAIT2</name>
              <bitOffset>8</bitOffset>
              <bitWidth>8</bitWidth>
            </field>
            <field>
              <name>ATTHOLD2</name>
              <bitOffset>16</bitOffset>
              <bitWidth>8</bitWidth>
            </field>
            <field>
              <name>ATTHIZ2</name>
              <bitOffset>24</bitOffset>
              <bitWidth>8</bitWidth>
            </field>
          </fields>
        </register>
        <register>
          <name>ECCR2</name>
          <addressOffset>0x14</addressOffset>
          <size>0x20</size>
          <fields>
            <field>
              <name>ECC2</name>
              <bitOffset>0</bitOffset>
              <bitWidth>32</bitWidth>
            </field>
          </fields>
        </register>
        <register>
          <name>PCR3</name>
          <addressOffset>0x20</addressOffset>
          <size>0x20</size>
          <fields>
            <field>
              <name>PWAITEN</name>
              <bitOffset>1</bitOffset>
              <bitWidth>1</bitWidth>
            </field>
            <field>
              <name>PBKEN</name>
              <bitOffset>2</bitOffset>
              <bitWidth>1</bitWidth>
            </field>
            <field>
              <name>PTYP</name>
              <bitOffset>3</bitOffset>
              <bitWidth>1</bitWidth>
            </field>
            <field>
              <name>PWID</name>
              <bitOffset>4</bitOffset>
              <bitWidth>2</bitWidth>
            </field>
            <field>
              <name>ECCEN</name>
              <bitOffset>6</bitOffset>
              <bitWidth>1</bitWidth>
            </field>
            <field>
              <name>TCLR</name>
              <bitOffset>9</bitOffset>
              <bitWidth>4</bitWidth>
            </field>
            <field>
              <name>TAR</name>
              <bitOffset>13</bitOffset>
              <bitWidth>4</bitWidth>
            </field>
            <field>
              <name>ECCPS</name>
              <bitOffset>17</bitOffset>
              <bitWidth>3</bitWidth>
            </field>
          </fields>
        </register>
        <register>
          <name>SR3</name>
          <addressOffset>0x24</addressOffset>
          <size>0x20</size>
          <fields>
            <field>
              <name>IRS</name>
              <bitOffset>0</bitOffset>
              <bitWidth>1</bitWidth>
            </field>
            <field>
              <name>ILS</name>
              <bitOffset>1</bitOffset>
              <bitWidth>1</bitWidth>
            </field>
            <field>
              <name>IFS</name>
              <bitOffset>2</bitOffset>
              <bitWidth>1</bitWidth>
            </field>
            <field>
              <name>IREN</name>
              <bitOffset>3</bitOffset>
              <bitWidth>1</bitWidth>
            </field>
            <field>
              <name>ILEN</name>
              <bitOffset>4</bitOffset>
              <bitWidth>1</bitWidth>
            </field>
            <field>
              <name>IFEN</name>
              <bitOffset>5</bitOffset>
              <bitWidth>1</bitWidth>
            </field>
            <field>
              <name>FEMPT</name>
              <bitOffset>6</bitOffset>
              <bitWidth>1</bitWidth>
            </field>
          </fields>
        </register>
        <register>
          <name>PMEM3</name>
          <addressOffset>0x28</addressOffset>
          <size>0x20</size>
          <fields>
            <field>
              <name>MEMSET3</name>
              <bitOffset>0</bitOffset>
              <bitWidth>8</bitWidth>
            </field>
            <field>
              <name>MEMWAIT3</name>
              <bitOffset>8</bitOffset>
              <bitWidth>8</bitWidth>
            </field>
            <field>
              <name>MEMHOLD3</name>
              <bitOffset>16</bitOffset>
              <bitWidth>8</bitWidth>
            </field>
            <field>
              <name>MEMHIZ3</name>
              <bitOffset>24</bitOffset>
              <bitWidth>8</bitWidth>
            </field>
          </fields>
        </register>
        <register>
          <name>PATT3</name>
          <addressOffset>0x2c</addressOffset>
          <size>0x20</size>
          <fields>
            <field>
              <name>ATTSET3</name>
              <bitOffset>0</bitOffset>
              <bitWidth>8</bitWidth>
            </field>
            <field>
              <name>ATTWAIT3</name>
              <bitOffset>8</bitOffset>
              <bitWidth>8</bitWidth>
            </field>
            <field>
              <name>ATTHOLD3</name>
              <bitOffset>16</bitOffset>
              <bitWidth>8</bitWidth>
            </field>
            <field>
              <name>ATTHIZ3</name>
              <bitOffset>24</bitOffset>
              <bitWidth>8</bitWidth>
            </field>
          </fields>
        </register>
        <register>
          <name>ECCR3</name>
          <addressOffset>0x34</addressOffset>
          <size>0x20</size>
          <fields>
            <field>
              <name>ECC3</name>
              <bitOffset>0</bitOffset>
              <bitWidth>32</bitWidth>
            </field>
          </fields>
        </register>
      </registers>
    </peripheral>
    <peripheral>
      <name>FMC_Bank4</name>
      <baseAddress>0xa00000a0</baseAddress>
      <registers>
        <register>
          <name>PCR4</name>
          <addressOffset>0x0</addressOffset>
          <size>0x20</size>
          <fields>
            <field>
              <name>PWAITEN</name>
              <bitOffset>1</bitOffset>
              <bitWidth>1</bitWidth>
            </field>
            <field>
              <name>PBKEN</name>
              <bitOffset>2</bitOffset>
              <bitWidth>1</bitWidth>
            </field>
            <field>
              <name>PTYP</name>
              <bitOffset>3</bitOffset>
              <bitWidth>1</bitWidth>
            </field>
            <field>
              <name>PWID</name>
              <bitOffset>4</bitOffset>
              <bitWidth>2</bitWidth>
            </field>
            <field>
              <name>ECCEN</name>
              <bitOffset>6</bitOffset>
              <bitWidth>1</bitWidth>
            </field>
            <field>
              <name>TCLR</name>
              <bitOffset>9</bitOffset>
              <bitWidth>4</bitWidth>
            </field>
            <field>
              <name>TAR</name>
              <bitOffset>13</bitOffset>
              <bitWidth>4</bitWidth>
            </field>
            <field>
              <name>ECCPS</name>
              <bitOffset>17</bitOffset>
              <bitWidth>3</bitWidth>
            </field>
          </fields>
        </register>
        <register>
          <name>SR4</name>
          <addressOffset>0x4</addressOffset>
          <size>0x20</size>
          <fields>
            <field>
              <name>IRS</name>
              <bitOffset>0</bitOffset>
              <bitWidth>1</bitWidth>
            </field>
            <field>
              <name>ILS</name>
              <bitOffset>1</bitOffset>
              <bitWidth>1</bitWidth>
            </field>
            <field>
              <name>IFS</name>
              <bitOffset>2</bitOffset>
              <bitWidth>1</bitWidth>
            </field>
            <field>
              <name>IREN</name>
              <bitOffset>3</bitOffset>
              <bitWidth>1</bitWidth>
            </field>
            <field>
              <name>ILEN</name>
              <bitOffset>4</bitOffset>
              <bitWidth>1</bitWidth>
            </field>
            <field>
              <name>IFEN</name>
              <bitOffset>5</bitOffset>
              <bitWidth>1</bitWidth>
            </field>
            <field>
              <name>FEMPT</name>
              <bitOffset>6</bitOffset>
              <bitWidth>1</bitWidth>
            </field>
          </fields>
        </register>
        <register>
          <name>PMEM4</name>
          <addressOffset>0x8</addressOffset>
          <size>0x20</size>
          <fields>
            <field>
              <name>MEMSET4</name>
              <bitOffset>0</bitOffset>
              <bitWidth>8</bitWidth>
            </field>
            <field>
              <name>MEMWAIT4</name>
              <bitOffset>8</bitOffset>
              <bitWidth>8</bitWidth>
            </field>
            <field>
              <name>MEMHOLD4</name>
              <bitOffset>16</bitOffset>
              <bitWidth>8</bitWidth>
            </field>
            <field>
              <name>MEMHIZ4</name>
              <bitOffset>24</bitOffset>
              <bitWidth>8</bitWidth>
            </field>
          </fields>
        </register>
        <register>
          <name>PATT4</name>
          <addressOffset>0xc</addressOffset>
          <size>0x20</size>
          <fields>
            <field>
              <name>ATTSET4</name>
              <bitOffset>0</bitOffset>
              <bitWidth>8</bitWidth>
            </field>
            <field>
              <name>ATTWAIT4</name>
              <bitOffset>8</bitOffset>
              <bitWidth>8</bitWidth>
            </field>
            <field>
              <name>ATTHOLD4</name>
              <bitOffset>16</bitOffset>
              <bitWidth>8</bitWidth>
            </field>
            <field>
              <name>ATTHIZ4</name>
              <bitOffset>24</bitOffset>
              <bitWidth>8</bitWidth>
            </field>
          </fields>
        </register>
        <register>
          <name>PIO4</name>
          <addressOffset>0x10</addressOffset>
          <size>0x20</size>
          <fields>
            <field>
              <name>IOSET4</name>
              <bitOffset>0</bitOffset>
              <bitWidth>8</bitWidth>
            </field>
            <field>
              <name>IOWAIT4</name>
              <bitOffset>8</bitOffset>
              <bitWidth>8</bitWidth>
            </field>
            <field>
              <name>IOHOLD4</name>
              <bitOffset>16</bitOffset>
              <bitWidth>8</bitWidth>
            </field>
            <field>
              <name>IOHIZ4</name>
              <bitOffset>24</bitOffset>
              <bitWidth>8</bitWidth>
            </field>
          </fields>
        </register>
      </registers>
    </peripheral>
    <peripheral>
      <name>FMC_Bank1E</name>
      <baseAddress>0xa0000104</baseAddress>
      <registers>
        <register>
          <name>BWTR.0</name>
          <addressOffset>0x0</addressOffset>
          <size>0x20</size>
          <fields>
            <field>
              <name>ADDSET</name>
              <bitOffset>0</bitOffset>
              <bitWidth>4</bitWidth>
            </field>
            <field>
              <name>ADDHLD</name>
              <bitOffset>4</bitOffset>
              <bitWidth>4</bitWidth>
            </field>
            <field>
              <name>DATAST</name>
              <bitOffset>8</bitOffset>
              <bitWidth>8</bitWidth>
            </field>
            <field>
              <name>BUSTURN</name>
              <bitOffset>16</bitOffset>
              <bitWidth>4</bitWidth>
            </field>
            <field>
              <name>ACCMOD</name>
              <bitOffset>28</bitOffset>
              <bitWidth>2</bitWidth>
            </field>
          </fields>
        </register>
        <register>
          <name>BWTR.1</name>
          <addressOffset>0x4</addressOffset>
          <size>0x20</size>
          <fields>
            <field>
              <name>ADDSET</name>
              <bitOffset>0</bitOffset>
              <bitWidth>4</bitWidth>
            </field>
            <field>
              <name>ADDHLD</name>
              <bitOffset>4</bitOffset>
              <bitWidth>4</bitWidth>
            </field>
            <field>
              <name>DATAST</name>
              <bitOffset>8</bitOffset>
              <bitWidth>8</bitWidth>
            </field>
            <field>
              <name>BUSTURN</name>
              <bitOffset>16</bitOffset>
              <bitWidth>4</bitWidth>
            </field>
            <field>
              <name>ACCMOD</name>
              <bitOffset>28</bitOffset>
              <bitWidth>2</bitWidth>
            </field>
          </fields>
        </register>
        <register>
          <name>BWTR.2</name>
          <addressOffset>0x8</addressOffset>
          <size>0x20</size>
          <fields>
            <field>
              <name>ADDSET</name>
              <bitOffset>0</bitOffset>
              <bitWidth>4</bitWidth>
            </field>
            <field>
              <name>ADDHLD</name>
              <bitOffset>4</bitOffset>
              <bitWidth>4</bitWidth>
            </field>
            <field>
              <name>DATAST</name>
              <bitOffset>8</bitOffset>
              <bitWidth>8</bitWidth>
            </field>
            <field>
              <name>BUSTURN</name>
              <bitOffset>16</bitOffset>
              <bitWidth>4</bitWidth>
            </field>
            <field>
              <name>ACCMOD</name>
              <bitOffset>28</bitOffset>
              <bitWidth>2</bitWidth>
            </field>
          </fields>
        </register>
        <register>
          <name>BWTR.3</name>
          <addressOffset>0xc</addressOffset>
          <size>0x20</size>
          <fields>
            <field>
              <name>ADDSET</name>
              <bitOffset>0</bitOffset>
              <bitWidth>4</bitWidth>
            </field>
            <field>
              <name>ADDHLD</name>
              <bitOffset>4</bitOffset>
              <bitWidth>4</bitWidth>
            </field>
            <field>
              <name>DATAST</name>
              <bitOffset>8</bitOffset>
              <bitWidth>8</bitWidth>
            </field>
            <field>
              <name>BUSTURN</name>
              <bitOffset>16</bitOffset>
              <bitWidth>4</bitWidth>
            </field>
            <field>
              <name>ACCMOD</name>
              <bitOffset>28</bitOffset>
              <bitWidth>2</bitWidth>
            </field>
          </fields>
        </register>
        <register>
          <name>BWTR.4</name>
          <addressOffset>0x10</addressOffset>
          <size>0x20</size>
        </register>
        <register>
          <name>BWTR.5</name>
          <addressOffset>0x14</addressOffset>
          <size>0x20</size>
        </register>
        <register>
          <name>BWTR.6</name>
          <addressOffset>0x18</addressOffset>
          <size>0x20</size>
        </register>
      </registers>
    </peripheral>
    <peripheral>
      <name>FMC_Bank5_6</name>
      <baseAddress>0xa0000140</baseAddress>
      <registers>
        <register>
          <name>SDCR.0</name>
          <addressOffset>0x0</addressOffset>
          <size>0x20</size>
          <fields>
            <field>
              <name>NC</name>
              <bitOffset>0</bitOffset>
              <bitWidth>2</bitWidth>
            </field>
            <field>
              <name>NR</name>
              <bitOffset>2</bitOffset>
              <bitWidth>2</bitWidth>
            </field>
            <field>
              <name>MWID</name>
              <bitOffset>4</bitOffset>
              <bitWidth>2</bitWidth>
            </field>
            <field>
              <name>NB</name>
              <bitOffset>6</bitOffset>
              <bitWidth>1</bitWidth>
            </field>
            <field>
              <name>CAS</name>
              <bitOffset>7</bitOffset>
              <bitWidth>2</bitWidth>
            </field>
            <field>
              <name>WP</name>
              <bitOffset>9</bitOffset>
              <bitWidth>1</bitWidth>
            </field>
            <field>
              <name>SDCLK</name>
              <bitOffset>10</bitOffset>
              <bitWidth>2</bitWidth>
            </field>
            <field>
              <name>RBURST</name>
              <bitOffset>12</bitOffset>
              <bitWidth>1</bitWidth>
            </field>
            <field>
              <name>RPIPE</name>
              <bitOffset>13</bitOffset>
              <bitWidth>2</bitWidth>
            </field>
          </fields>
        </register>
        <register>
          <name>SDCR.1</name>
          <addressOffset>0x4</addressOffset>
          <size>0x20</size>
          <fields>
            <field>
              <name>NC</name>
              <bitOffset>0</bitOffset>
              <bitWidth>2</bitWidth>
            </field>
            <field>
              <name>NR</name>
              <bitOffset>2</bitOffset>
              <bitWidth>2</bitWidth>
            </field>
            <field>
              <name>MWID</name>
              <bitOffset>4</bitOffset>
              <bitWidth>2</bitWidth>
            </field>
            <field>
              <name>NB</name>
              <bitOffset>6</bitOffset>
              <bitWidth>1</bitWidth>
            </field>
            <field>
              <name>CAS</name>
              <bitOffset>7</bitOffset>
              <bitWidth>2</bitWidth>
            </field>
            <field>
              <name>WP</name>
              <bitOffset>9</bitOffset>
              <bitWidth>1</bitWidth>
            </field>
            <field>
              <name>SDCLK</name>
              <bitOffset>10</bitOffset>
              <bitWidth>2</bitWidth>
            </field>
            <field>
              <name>RBURST</name>
              <bitOffset>12</bitOffset>
              <bitWidth>1</bitWidth>
            </field>
            <field>
              <name>RPIPE</name>
              <bitOffset>13</bitOffset>
              <bitWidth>2</bitWidth>
            </field>
          </fields>
        </register>
        <register>
          <name>SDTR.0</name>
          <addressOffset>0x8</addressOffset>
          <size>0x20</size>
          <fields>
            <field>
              <name>TMRD</name>
              <bitOffset>0</bitOffset>
              <bitWidth>4</bitWidth>
            </field>
            <field>
              <name>TXSR</name>
              <bitOffset>4</bitOffset>
              <bitWidth>4</bitWidth>
            </field>
            <field>
              <name>TRAS</name>
              <bitOffset>8</bitOffset>
              <bitWidth>4</bitWidth>
            </field>
            <field>
              <name>TRC</name>
              <bitOffset>12</bitOffset>
              <bitWidth>4</bitWidth>
            </field>
            <field>
              <name>TWR</name>
              <bitOffset>16</bitOffset>
              <bitWidth>4</bitWidth>
            </field>
            <field>
              <name>TRP</name>
              <bitOffset>20</bitOffset>
              <bitWidth>4</bitWidth>
            </field>
            <field>
              <name>TRCD</name>
              <bitOffset>24</bitOffset>
              <bitWidth>4</bitWidth>
            </field>
          </fields>
        </register>
        <register>
          <name>SDTR.1</name>
          <addressOffset>0xc</addressOffset>
          <size>0x20</size>
          <fields>
            <field>
              <name>TMRD</name>
              <bitOffset>0</bitOffset>
              <bitWidth>4</bitWidth>
            </field>
            <field>
              <name>TXSR</name>
              <bitOffset>4</bitOffset>
              <bitWidth>4</bitWidth>
            </field>
            <field>
              <name>TRAS</name>
              <bitOffset>8</bitOffset>
              <bitWidth>4</bitWidth>
            </field>
            <field>
              <name>TRC</name>
              <bitOffset>12</bitOffset>
              <bitWidth>4</bitWidth>
            </field>
            <field>
              <name>TWR</name>
              <bitOffset>16</bitOffset>
              <bitWidth>4</bitWidth>
            </field>
            <field>
              <name>TRP</name>
              <bitOffset>20</bitOffset>
              <bitWidth>4</bitWidth>
            </field>
            <field>
              <name>TRCD</name>
              <bitOffset>24</bitOffset>
              <bitWidth>4</bitWidth>
            </field>
          </fields>
        </register>
        <register>
          <name>SDCMR</name>
          <addressOffset>0x10</addressOffset>
          <size>0x20</size>
          <fields>
            <field>
              <name>MODE</name>
              <bitOffset>0</bitOffset>
              <bitWidth>3</bitWidth>
            </field>
            <field>
              <name>CTB2</name>
              <bitOffset>3</bitOffset>
              <bitWidth>1</bitWidth>
            </field>
            <field>
              <name>CTB1</name>
              <bitOffset>4</bitOffset>
              <bitWidth>1</bitWidth>
            </field>
            <field>
              <name>NRFS</name>
              <bitOffset>5</bitOffset>
              <bitWidth>4</bitWidth>
            </field>
            <field>
              <name>MRD</name>
              <bitOffset>9</bitOffset>
              <bitWidth>13</bitWidth>
            </field>
          </fields>
        </register>
        <register>
          <name>SDRTR</name>
          <addressOffset>0x14</addressOffset>
          <size>0x20</size>
          <fields>
            <field>
              <name>CRE</name>
              <bitOffset>0</bitOffset>
              <bitWidth>1</bitWidth>
            </field>
            <field>
              <name>COUNT</name>
              <bitOffset>1</bitOffset>
              <bitWidth>13</bitWidth>
            </field>
            <field>
              <name>REIE</name>
              <bitOffset>14</bitOffset>
              <bitWidth>1</bitWidth>
            </field>
          </fields>
        </register>
        <register>
          <name>SDSR</name>
          <addressOffset>0x18</addressOffset>
          <size>0x20</size>
          <fields>
            <field>
              <name>RE</name>
              <bitOffset>0</bitOffset>
              <bitWidth>1</bitWidth>
            </field>
            <field>
              <name>MODES1</name>
              <bitOffset>1</bitOffset>
              <bitWidth>2</bitWidth>
            </field>
            <field>
              <name>MODES2</name>
              <bitOffset>3</bitOffset>
              <bitWidth>2</bitWidth>
            </field>
            <field>
              <name>BUSY</name>
              <bitOffset>5</bitOffset>
              <bitWidth>1</bitWidth>
            </field>
          </fields>
        </register>
      </registers>
    </peripheral>
    <peripheral>
      <name>DBGMCU</name>
      <baseAddress>0xe0042000</baseAddress>
      <registers>
        <register>
          <name>IDCODE</name>
          <addressOffset>0x0</addressOffset>
          <size>0x20</size>
          <fields>
            <field>
              <name>DEV_ID</name>
              <bitOffset>0</bitOffset>
              <bitWidth>12</bitWidth>
            </field>
            <field>
              <name>REV_ID</name>
              <bitOffset>16</bitOffset>
              <bitWidth>16</bitWidth>
            </field>
          </fields>
        </register>
        <register>
          <name>CR</name>
          <addressOffset>0x4</addressOffset>
          <size>0x20</size>
          <fields>
            <field>
              <name>DBG_SLEEP</name>
              <bitOffset>0</bitOffset>
              <bitWidth>1</bitWidth>
            </field>
            <field>
              <name>DBG_STOP</name>
              <bitOffset>1</bitOffset>
              <bitWidth>1</bitWidth>
            </field>
            <field>
              <name>DBG_STANDBY</name>
              <bitOffset>2</bitOffset>
              <bitWidth>1</bitWidth>
            </field>
            <field>
              <name>TRACE_IOEN</name>
              <bitOffset>5</bitOffset>
              <bitWidth>1</bitWidth>
            </field>
            <field>
              <name>TRACE_MODE</name>
              <bitOffset>6</bitOffset>
              <bitWidth>2</bitWidth>
            </field>
          </fields>
        </register>
        <register>
          <name>APB1FZ</name>
          <addressOffset>0x8</addressOffset>
          <size>0x20</size>
          <fields>
            <field>
              <name>DBG_TIM2_STOP</name>
              <bitOffset>0</bitOffset>
              <bitWidth>1</bitWidth>
            </field>
            <field>
              <name>DBG_TIM3_STOP</name>
              <bitOffset>1</bitOffset>
              <bitWidth>1</bitWidth>
            </field>
            <field>
              <name>DBG_TIM4_STOP</name>
              <bitOffset>2</bitOffset>
              <bitWidth>1</bitWidth>
            </field>
            <field>
              <name>DBG_TIM5_STOP</name>
              <bitOffset>3</bitOffset>
              <bitWidth>1</bitWidth>
            </field>
            <field>
              <name>DBG_TIM6_STOP</name>
              <bitOffset>4</bitOffset>
              <bitWidth>1</bitWidth>
            </field>
            <field>
              <name>DBG_TIM7_STOP</name>
              <bitOffset>5</bitOffset>
              <bitWidth>1</bitWidth>
            </field>
            <field>
              <name>DBG_TIM12_STOP</name>
              <bitOffset>6</bitOffset>
              <bitWidth>1</bitWidth>
            </field>
            <field>
              <name>DBG_TIM13_STOP</name>
              <bitOffset>7</bitOffset>
              <bitWidth>1</bitWidth>
            </field>
            <field>
              <name>DBG_TIM14_STOP</name>
              <bitOffset>8</bitOffset>
              <bitWidth>1</bitWidth>
            </field>
            <field>
              <name>DBG_RTC_STOP</name>
              <bitOffset>10</bitOffset>
              <bitWidth>1</bitWidth>
            </field>
            <field>
              <name>DBG_WWDG_STOP</name>
              <bitOffset>11</bitOffset>
              <bitWidth>1</bitWidth>
            </field>
            <field>
              <name>DBG_IWDG_STOP</name>
              <bitOffset>12</bitOffset>
              <bitWidth>1</bitWidth>
            </field>
            <field>
              <name>DBG_I2C1_SMBUS_TIMEOUT</name>
              <bitOffset>21</bitOffset>
              <bitWidth>1</bitWidth>
            </field>
            <field>
              <name>DBG_I2C2_SMBUS_TIMEOUT</name>
              <bitOffset>22</bitOffset>
              <bitWidth>1</bitWidth>
            </field>
            <field>
              <name>DBG_I2C3_SMBUS_TIMEOUT</name>
              <bitOffset>23</bitOffset>
              <bitWidth>1</bitWidth>
            </field>
            <field>
              <name>DBG_CAN1_STOP</name>
              <bitOffset>25</bitOffset>
              <bitWidth>1</bitWidth>
            </field>
            <field>
              <name>DBG_CAN2_STOP</name>
              <bitOffset>26</bitOffset>
              <bitWidth>1</bitWidth>
            </field>
          </fields>
        </register>
        <register>
          <name>APB2FZ</name>
          <addressOffset>0xc</addressOffset>
          <size>0x20</size>
          <fields>
            <field>
              <name>DBG_TIM1_STOP</name>
              <bitOffset>0</bitOffset>
              <bitWidth>1</bitWidth>
            </field>
            <field>
              <name>DBG_TIM8_STOP</name>
              <bitOffset>1</bitOffset>
              <bitWidth>1</bitWidth>
            </field>
            <field>
              <name>DBG_TIM9_STOP</name>
              <bitOffset>16</bitOffset>
              <bitWidth>1</bitWidth>
            </field>
            <field>
              <name>DBG_TIM10_STOP</name>
              <bitOffset>17</bitOffset>
              <bitWidth>1</bitWidth>
            </field>
            <field>
              <name>DBG_TIM11_STOP</name>
              <bitOffset>18</bitOffset>
              <bitWidth>1</bitWidth>
            </field>
          </fields>
        </register>
      </registers>
    </peripheral>
  </peripherals>
</device>
